VERSION 5.8 ;
BUSBITCHARS "[]" ;
DIVIDERCHAR "/" ;
UNITS
    DATABASE MICRONS 2000 ;
END UNITS

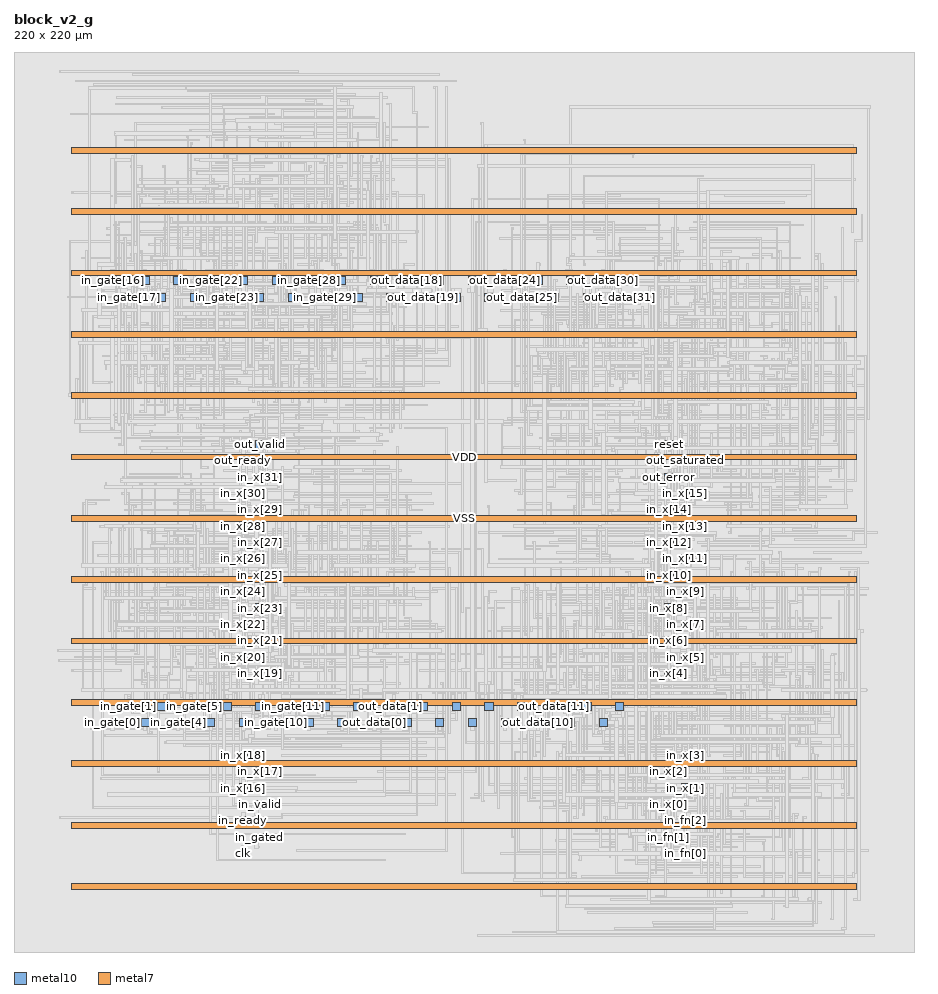
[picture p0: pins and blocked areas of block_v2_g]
MACRO block_v2_g
  FOREIGN block_v2_g 0 0 ;
  CLASS BLOCK ;
  SIZE 220 BY 220 ;
  PIN clk
    DIRECTION INPUT ;
    USE SIGNAL ;
    PORT
      LAYER metal10 ;
        RECT  55.095 23.07 57.095 25.07 ;
    END
  END clk
  PIN in_fn[0]
    DIRECTION INPUT ;
    USE SIGNAL ;
    PORT
      LAYER metal10 ;
        RECT  163.095 23.07 165.095 25.07 ;
    END
  END in_fn[0]
  PIN in_fn[1]
    DIRECTION INPUT ;
    USE SIGNAL ;
    PORT
      LAYER metal10 ;
        RECT  159.095 27.07 161.095 29.07 ;
    END
  END in_fn[1]
  PIN in_fn[2]
    DIRECTION INPUT ;
    USE SIGNAL ;
    PORT
      LAYER metal10 ;
        RECT  163.095 31.07 165.095 33.07 ;
    END
  END in_fn[2]
  PIN in_gate[0]
    DIRECTION INPUT ;
    USE SIGNAL ;
    PORT
      LAYER metal10 ;
        RECT  23.095 55.07 25.095 57.07 ;
    END
  END in_gate[0]
  PIN in_gate[10]
    DIRECTION INPUT ;
    USE SIGNAL ;
    PORT
      LAYER metal10 ;
        RECT  63.095 55.07 65.095 57.07 ;
    END
  END in_gate[10]
  PIN in_gate[11]
    DIRECTION INPUT ;
    USE SIGNAL ;
    PORT
      LAYER metal10 ;
        RECT  67.095 59.07 69.095 61.07 ;
    END
  END in_gate[11]
  PIN in_gate[12]
    DIRECTION INPUT ;
    USE SIGNAL ;
    PORT
      LAYER metal10 ;
        RECT  71.095 55.07 73.095 57.07 ;
    END
  END in_gate[12]
  PIN in_gate[13]
    DIRECTION INPUT ;
    USE SIGNAL ;
    PORT
      LAYER metal10 ;
        RECT  75.095 59.07 77.095 61.07 ;
    END
  END in_gate[13]
  PIN in_gate[14]
    DIRECTION INPUT ;
    USE SIGNAL ;
    PORT
      LAYER metal10 ;
        RECT  79.095 55.07 81.095 57.07 ;
    END
  END in_gate[14]
  PIN in_gate[15]
    DIRECTION INPUT ;
    USE SIGNAL ;
    PORT
      LAYER metal10 ;
        RECT  83.095 59.07 85.095 61.07 ;
    END
  END in_gate[15]
  PIN in_gate[16]
    DIRECTION INPUT ;
    USE SIGNAL ;
    PORT
      LAYER metal10 ;
        RECT  23.095 163.07 25.095 165.07 ;
    END
  END in_gate[16]
  PIN in_gate[17]
    DIRECTION INPUT ;
    USE SIGNAL ;
    PORT
      LAYER metal10 ;
        RECT  27.095 159.07 29.095 161.07 ;
    END
  END in_gate[17]
  PIN in_gate[18]
    DIRECTION INPUT ;
    USE SIGNAL ;
    PORT
      LAYER metal10 ;
        RECT  31.095 163.07 33.095 165.07 ;
    END
  END in_gate[18]
  PIN in_gate[19]
    DIRECTION INPUT ;
    USE SIGNAL ;
    PORT
      LAYER metal10 ;
        RECT  35.095 159.07 37.095 161.07 ;
    END
  END in_gate[19]
  PIN in_gate[1]
    DIRECTION INPUT ;
    USE SIGNAL ;
    PORT
      LAYER metal10 ;
        RECT  27.095 59.07 29.095 61.07 ;
    END
  END in_gate[1]
  PIN in_gate[20]
    DIRECTION INPUT ;
    USE SIGNAL ;
    PORT
      LAYER metal10 ;
        RECT  39.095 163.07 41.095 165.07 ;
    END
  END in_gate[20]
  PIN in_gate[21]
    DIRECTION INPUT ;
    USE SIGNAL ;
    PORT
      LAYER metal10 ;
        RECT  43.095 159.07 45.095 161.07 ;
    END
  END in_gate[21]
  PIN in_gate[22]
    DIRECTION INPUT ;
    USE SIGNAL ;
    PORT
      LAYER metal10 ;
        RECT  47.095 163.07 49.095 165.07 ;
    END
  END in_gate[22]
  PIN in_gate[23]
    DIRECTION INPUT ;
    USE SIGNAL ;
    PORT
      LAYER metal10 ;
        RECT  51.095 159.07 53.095 161.07 ;
    END
  END in_gate[23]
  PIN in_gate[24]
    DIRECTION INPUT ;
    USE SIGNAL ;
    PORT
      LAYER metal10 ;
        RECT  55.095 163.07 57.095 165.07 ;
    END
  END in_gate[24]
  PIN in_gate[25]
    DIRECTION INPUT ;
    USE SIGNAL ;
    PORT
      LAYER metal10 ;
        RECT  59.095 159.07 61.095 161.07 ;
    END
  END in_gate[25]
  PIN in_gate[26]
    DIRECTION INPUT ;
    USE SIGNAL ;
    PORT
      LAYER metal10 ;
        RECT  63.095 163.07 65.095 165.07 ;
    END
  END in_gate[26]
  PIN in_gate[27]
    DIRECTION INPUT ;
    USE SIGNAL ;
    PORT
      LAYER metal10 ;
        RECT  67.095 159.07 69.095 161.07 ;
    END
  END in_gate[27]
  PIN in_gate[28]
    DIRECTION INPUT ;
    USE SIGNAL ;
    PORT
      LAYER metal10 ;
        RECT  71.095 163.07 73.095 165.07 ;
    END
  END in_gate[28]
  PIN in_gate[29]
    DIRECTION INPUT ;
    USE SIGNAL ;
    PORT
      LAYER metal10 ;
        RECT  75.095 159.07 77.095 161.07 ;
    END
  END in_gate[29]
  PIN in_gate[2]
    DIRECTION INPUT ;
    USE SIGNAL ;
    PORT
      LAYER metal10 ;
        RECT  31.095 55.07 33.095 57.07 ;
    END
  END in_gate[2]
  PIN in_gate[30]
    DIRECTION INPUT ;
    USE SIGNAL ;
    PORT
      LAYER metal10 ;
        RECT  79.095 163.07 81.095 165.07 ;
    END
  END in_gate[30]
  PIN in_gate[31]
    DIRECTION INPUT ;
    USE SIGNAL ;
    PORT
      LAYER metal10 ;
        RECT  83.095 159.07 85.095 161.07 ;
    END
  END in_gate[31]
  PIN in_gate[3]
    DIRECTION INPUT ;
    USE SIGNAL ;
    PORT
      LAYER metal10 ;
        RECT  35.095 59.07 37.095 61.07 ;
    END
  END in_gate[3]
  PIN in_gate[4]
    DIRECTION INPUT ;
    USE SIGNAL ;
    PORT
      LAYER metal10 ;
        RECT  39.095 55.07 41.095 57.07 ;
    END
  END in_gate[4]
  PIN in_gate[5]
    DIRECTION INPUT ;
    USE SIGNAL ;
    PORT
      LAYER metal10 ;
        RECT  43.095 59.07 45.095 61.07 ;
    END
  END in_gate[5]
  PIN in_gate[6]
    DIRECTION INPUT ;
    USE SIGNAL ;
    PORT
      LAYER metal10 ;
        RECT  47.095 55.07 49.095 57.07 ;
    END
  END in_gate[6]
  PIN in_gate[7]
    DIRECTION INPUT ;
    USE SIGNAL ;
    PORT
      LAYER metal10 ;
        RECT  51.095 59.07 53.095 61.07 ;
    END
  END in_gate[7]
  PIN in_gate[8]
    DIRECTION INPUT ;
    USE SIGNAL ;
    PORT
      LAYER metal10 ;
        RECT  55.095 55.07 57.095 57.07 ;
    END
  END in_gate[8]
  PIN in_gate[9]
    DIRECTION INPUT ;
    USE SIGNAL ;
    PORT
      LAYER metal10 ;
        RECT  59.095 59.07 61.095 61.07 ;
    END
  END in_gate[9]
  PIN in_gated
    DIRECTION INPUT ;
    USE SIGNAL ;
    PORT
      LAYER metal10 ;
        RECT  59.095 27.07 61.095 29.07 ;
    END
  END in_gated
  PIN in_ready
    DIRECTION OUTPUT ;
    USE SIGNAL ;
    PORT
      LAYER metal10 ;
        RECT  55.095 31.07 57.095 33.07 ;
    END
  END in_ready
  PIN in_valid
    DIRECTION INPUT ;
    USE SIGNAL ;
    PORT
      LAYER metal10 ;
        RECT  59.095 35.07 61.095 37.07 ;
    END
  END in_valid
  PIN in_x[0]
    DIRECTION INPUT ;
    USE SIGNAL ;
    PORT
      LAYER metal10 ;
        RECT  159.095 35.07 161.095 37.07 ;
    END
  END in_x[0]
  PIN in_x[10]
    DIRECTION INPUT ;
    USE SIGNAL ;
    PORT
      LAYER metal10 ;
        RECT  159.095 91.07 161.095 93.07 ;
    END
  END in_x[10]
  PIN in_x[11]
    DIRECTION INPUT ;
    USE SIGNAL ;
    PORT
      LAYER metal10 ;
        RECT  163.095 95.07 165.095 97.07 ;
    END
  END in_x[11]
  PIN in_x[12]
    DIRECTION INPUT ;
    USE SIGNAL ;
    PORT
      LAYER metal10 ;
        RECT  159.095 99.07 161.095 101.07 ;
    END
  END in_x[12]
  PIN in_x[13]
    DIRECTION INPUT ;
    USE SIGNAL ;
    PORT
      LAYER metal10 ;
        RECT  163.095 103.07 165.095 105.07 ;
    END
  END in_x[13]
  PIN in_x[14]
    DIRECTION INPUT ;
    USE SIGNAL ;
    PORT
      LAYER metal10 ;
        RECT  159.095 107.07 161.095 109.07 ;
    END
  END in_x[14]
  PIN in_x[15]
    DIRECTION INPUT ;
    USE SIGNAL ;
    PORT
      LAYER metal10 ;
        RECT  163.095 111.07 165.095 113.07 ;
    END
  END in_x[15]
  PIN in_x[16]
    DIRECTION INPUT ;
    USE SIGNAL ;
    PORT
      LAYER metal10 ;
        RECT  55.095 39.07 57.095 41.07 ;
    END
  END in_x[16]
  PIN in_x[17]
    DIRECTION INPUT ;
    USE SIGNAL ;
    PORT
      LAYER metal10 ;
        RECT  59.095 43.07 61.095 45.07 ;
    END
  END in_x[17]
  PIN in_x[18]
    DIRECTION INPUT ;
    USE SIGNAL ;
    PORT
      LAYER metal10 ;
        RECT  55.095 47.07 57.095 49.07 ;
    END
  END in_x[18]
  PIN in_x[19]
    DIRECTION INPUT ;
    USE SIGNAL ;
    PORT
      LAYER metal10 ;
        RECT  59.095 67.07 61.095 69.07 ;
    END
  END in_x[19]
  PIN in_x[1]
    DIRECTION INPUT ;
    USE SIGNAL ;
    PORT
      LAYER metal10 ;
        RECT  163.095 39.07 165.095 41.07 ;
    END
  END in_x[1]
  PIN in_x[20]
    DIRECTION INPUT ;
    USE SIGNAL ;
    PORT
      LAYER metal10 ;
        RECT  55.095 71.07 57.095 73.07 ;
    END
  END in_x[20]
  PIN in_x[21]
    DIRECTION INPUT ;
    USE SIGNAL ;
    PORT
      LAYER metal10 ;
        RECT  59.095 75.07 61.095 77.07 ;
    END
  END in_x[21]
  PIN in_x[22]
    DIRECTION INPUT ;
    USE SIGNAL ;
    PORT
      LAYER metal10 ;
        RECT  55.095 79.07 57.095 81.07 ;
    END
  END in_x[22]
  PIN in_x[23]
    DIRECTION INPUT ;
    USE SIGNAL ;
    PORT
      LAYER metal10 ;
        RECT  59.095 83.07 61.095 85.07 ;
    END
  END in_x[23]
  PIN in_x[24]
    DIRECTION INPUT ;
    USE SIGNAL ;
    PORT
      LAYER metal10 ;
        RECT  55.095 87.07 57.095 89.07 ;
    END
  END in_x[24]
  PIN in_x[25]
    DIRECTION INPUT ;
    USE SIGNAL ;
    PORT
      LAYER metal10 ;
        RECT  59.095 91.07 61.095 93.07 ;
    END
  END in_x[25]
  PIN in_x[26]
    DIRECTION INPUT ;
    USE SIGNAL ;
    PORT
      LAYER metal10 ;
        RECT  55.095 95.07 57.095 97.07 ;
    END
  END in_x[26]
  PIN in_x[27]
    DIRECTION INPUT ;
    USE SIGNAL ;
    PORT
      LAYER metal10 ;
        RECT  59.095 99.07 61.095 101.07 ;
    END
  END in_x[27]
  PIN in_x[28]
    DIRECTION INPUT ;
    USE SIGNAL ;
    PORT
      LAYER metal10 ;
        RECT  55.095 103.07 57.095 105.07 ;
    END
  END in_x[28]
  PIN in_x[29]
    DIRECTION INPUT ;
    USE SIGNAL ;
    PORT
      LAYER metal10 ;
        RECT  59.095 107.07 61.095 109.07 ;
    END
  END in_x[29]
  PIN in_x[2]
    DIRECTION INPUT ;
    USE SIGNAL ;
    PORT
      LAYER metal10 ;
        RECT  159.095 43.07 161.095 45.07 ;
    END
  END in_x[2]
  PIN in_x[30]
    DIRECTION INPUT ;
    USE SIGNAL ;
    PORT
      LAYER metal10 ;
        RECT  55.095 111.07 57.095 113.07 ;
    END
  END in_x[30]
  PIN in_x[31]
    DIRECTION INPUT ;
    USE SIGNAL ;
    PORT
      LAYER metal10 ;
        RECT  59.095 115.07 61.095 117.07 ;
    END
  END in_x[31]
  PIN in_x[3]
    DIRECTION INPUT ;
    USE SIGNAL ;
    PORT
      LAYER metal10 ;
        RECT  163.095 47.07 165.095 49.07 ;
    END
  END in_x[3]
  PIN in_x[4]
    DIRECTION INPUT ;
    USE SIGNAL ;
    PORT
      LAYER metal10 ;
        RECT  159.095 67.07 161.095 69.07 ;
    END
  END in_x[4]
  PIN in_x[5]
    DIRECTION INPUT ;
    USE SIGNAL ;
    PORT
      LAYER metal10 ;
        RECT  163.095 71.07 165.095 73.07 ;
    END
  END in_x[5]
  PIN in_x[6]
    DIRECTION INPUT ;
    USE SIGNAL ;
    PORT
      LAYER metal10 ;
        RECT  159.095 75.07 161.095 77.07 ;
    END
  END in_x[6]
  PIN in_x[7]
    DIRECTION INPUT ;
    USE SIGNAL ;
    PORT
      LAYER metal10 ;
        RECT  163.095 79.07 165.095 81.07 ;
    END
  END in_x[7]
  PIN in_x[8]
    DIRECTION INPUT ;
    USE SIGNAL ;
    PORT
      LAYER metal10 ;
        RECT  159.095 83.07 161.095 85.07 ;
    END
  END in_x[8]
  PIN in_x[9]
    DIRECTION INPUT ;
    USE SIGNAL ;
    PORT
      LAYER metal10 ;
        RECT  163.095 87.07 165.095 89.07 ;
    END
  END in_x[9]
  PIN out_data[0]
    DIRECTION OUTPUT ;
    USE SIGNAL ;
    PORT
      LAYER metal10 ;
        RECT  87.095 55.07 89.095 57.07 ;
    END
  END out_data[0]
  PIN out_data[10]
    DIRECTION OUTPUT ;
    USE SIGNAL ;
    PORT
      LAYER metal10 ;
        RECT  127.095 55.07 129.095 57.07 ;
    END
  END out_data[10]
  PIN out_data[11]
    DIRECTION OUTPUT ;
    USE SIGNAL ;
    PORT
      LAYER metal10 ;
        RECT  131.095 59.07 133.095 61.07 ;
    END
  END out_data[11]
  PIN out_data[12]
    DIRECTION OUTPUT ;
    USE SIGNAL ;
    PORT
      LAYER metal10 ;
        RECT  135.095 55.07 137.095 57.07 ;
    END
  END out_data[12]
  PIN out_data[13]
    DIRECTION OUTPUT ;
    USE SIGNAL ;
    PORT
      LAYER metal10 ;
        RECT  139.095 59.07 141.095 61.07 ;
    END
  END out_data[13]
  PIN out_data[14]
    DIRECTION OUTPUT ;
    USE SIGNAL ;
    PORT
      LAYER metal10 ;
        RECT  143.095 55.07 145.095 57.07 ;
    END
  END out_data[14]
  PIN out_data[15]
    DIRECTION OUTPUT ;
    USE SIGNAL ;
    PORT
      LAYER metal10 ;
        RECT  147.095 59.07 149.095 61.07 ;
    END
  END out_data[15]
  PIN out_data[16]
    DIRECTION OUTPUT ;
    USE SIGNAL ;
    PORT
      LAYER metal10 ;
        RECT  87.095 163.07 89.095 165.07 ;
    END
  END out_data[16]
  PIN out_data[17]
    DIRECTION OUTPUT ;
    USE SIGNAL ;
    PORT
      LAYER metal10 ;
        RECT  91.095 159.07 93.095 161.07 ;
    END
  END out_data[17]
  PIN out_data[18]
    DIRECTION OUTPUT ;
    USE SIGNAL ;
    PORT
      LAYER metal10 ;
        RECT  95.095 163.07 97.095 165.07 ;
    END
  END out_data[18]
  PIN out_data[19]
    DIRECTION OUTPUT ;
    USE SIGNAL ;
    PORT
      LAYER metal10 ;
        RECT  99.095 159.07 101.095 161.07 ;
    END
  END out_data[19]
  PIN out_data[1]
    DIRECTION OUTPUT ;
    USE SIGNAL ;
    PORT
      LAYER metal10 ;
        RECT  91.095 59.07 93.095 61.07 ;
    END
  END out_data[1]
  PIN out_data[20]
    DIRECTION OUTPUT ;
    USE SIGNAL ;
    PORT
      LAYER metal10 ;
        RECT  103.095 163.07 105.095 165.07 ;
    END
  END out_data[20]
  PIN out_data[21]
    DIRECTION OUTPUT ;
    USE SIGNAL ;
    PORT
      LAYER metal10 ;
        RECT  107.095 159.07 109.095 161.07 ;
    END
  END out_data[21]
  PIN out_data[22]
    DIRECTION OUTPUT ;
    USE SIGNAL ;
    PORT
      LAYER metal10 ;
        RECT  111.095 163.07 113.095 165.07 ;
    END
  END out_data[22]
  PIN out_data[23]
    DIRECTION OUTPUT ;
    USE SIGNAL ;
    PORT
      LAYER metal10 ;
        RECT  115.095 159.07 117.095 161.07 ;
    END
  END out_data[23]
  PIN out_data[24]
    DIRECTION OUTPUT ;
    USE SIGNAL ;
    PORT
      LAYER metal10 ;
        RECT  119.095 163.07 121.095 165.07 ;
    END
  END out_data[24]
  PIN out_data[25]
    DIRECTION OUTPUT ;
    USE SIGNAL ;
    PORT
      LAYER metal10 ;
        RECT  123.095 159.07 125.095 161.07 ;
    END
  END out_data[25]
  PIN out_data[26]
    DIRECTION OUTPUT ;
    USE SIGNAL ;
    PORT
      LAYER metal10 ;
        RECT  127.095 163.07 129.095 165.07 ;
    END
  END out_data[26]
  PIN out_data[27]
    DIRECTION OUTPUT ;
    USE SIGNAL ;
    PORT
      LAYER metal10 ;
        RECT  131.095 159.07 133.095 161.07 ;
    END
  END out_data[27]
  PIN out_data[28]
    DIRECTION OUTPUT ;
    USE SIGNAL ;
    PORT
      LAYER metal10 ;
        RECT  135.095 163.07 137.095 165.07 ;
    END
  END out_data[28]
  PIN out_data[29]
    DIRECTION OUTPUT ;
    USE SIGNAL ;
    PORT
      LAYER metal10 ;
        RECT  139.095 159.07 141.095 161.07 ;
    END
  END out_data[29]
  PIN out_data[2]
    DIRECTION OUTPUT ;
    USE SIGNAL ;
    PORT
      LAYER metal10 ;
        RECT  95.095 55.07 97.095 57.07 ;
    END
  END out_data[2]
  PIN out_data[30]
    DIRECTION OUTPUT ;
    USE SIGNAL ;
    PORT
      LAYER metal10 ;
        RECT  143.095 163.07 145.095 165.07 ;
    END
  END out_data[30]
  PIN out_data[31]
    DIRECTION OUTPUT ;
    USE SIGNAL ;
    PORT
      LAYER metal10 ;
        RECT  147.095 159.07 149.095 161.07 ;
    END
  END out_data[31]
  PIN out_data[3]
    DIRECTION OUTPUT ;
    USE SIGNAL ;
    PORT
      LAYER metal10 ;
        RECT  99.095 59.07 101.095 61.07 ;
    END
  END out_data[3]
  PIN out_data[4]
    DIRECTION OUTPUT ;
    USE SIGNAL ;
    PORT
      LAYER metal10 ;
        RECT  103.095 55.07 105.095 57.07 ;
    END
  END out_data[4]
  PIN out_data[5]
    DIRECTION OUTPUT ;
    USE SIGNAL ;
    PORT
      LAYER metal10 ;
        RECT  107.095 59.07 109.095 61.07 ;
    END
  END out_data[5]
  PIN out_data[6]
    DIRECTION OUTPUT ;
    USE SIGNAL ;
    PORT
      LAYER metal10 ;
        RECT  111.095 55.07 113.095 57.07 ;
    END
  END out_data[6]
  PIN out_data[7]
    DIRECTION OUTPUT ;
    USE SIGNAL ;
    PORT
      LAYER metal10 ;
        RECT  115.095 59.07 117.095 61.07 ;
    END
  END out_data[7]
  PIN out_data[8]
    DIRECTION OUTPUT ;
    USE SIGNAL ;
    PORT
      LAYER metal10 ;
        RECT  119.095 55.07 121.095 57.07 ;
    END
  END out_data[8]
  PIN out_data[9]
    DIRECTION OUTPUT ;
    USE SIGNAL ;
    PORT
      LAYER metal10 ;
        RECT  123.095 59.07 125.095 61.07 ;
    END
  END out_data[9]
  PIN out_error
    DIRECTION OUTPUT ;
    USE SIGNAL ;
    PORT
      LAYER metal10 ;
        RECT  159.095 115.07 161.095 117.07 ;
    END
  END out_error
  PIN out_ready
    DIRECTION INPUT ;
    USE SIGNAL ;
    PORT
      LAYER metal10 ;
        RECT  55.095 119.07 57.095 121.07 ;
    END
  END out_ready
  PIN out_saturated
    DIRECTION OUTPUT ;
    USE SIGNAL ;
    PORT
      LAYER metal10 ;
        RECT  163.095 119.07 165.095 121.07 ;
    END
  END out_saturated
  PIN out_valid
    DIRECTION OUTPUT ;
    USE SIGNAL ;
    PORT
      LAYER metal10 ;
        RECT  59.095 123.07 61.095 125.07 ;
    END
  END out_valid
  PIN reset
    DIRECTION INPUT ;
    USE SIGNAL ;
    PORT
      LAYER metal10 ;
        RECT  159.095 123.07 161.095 125.07 ;
    END
  END reset
  PIN VSS
    DIRECTION INOUT ;
    USE GROUND ;
    PORT
      LAYER metal7 ;
        RECT  14.06 195.3 205.96 196.7 ;
        RECT  14.06 165.3 205.96 166.7 ;
        RECT  14.06 135.3 205.96 136.7 ;
        RECT  14.06 105.3 205.96 106.7 ;
        RECT  14.06 75.3 205.96 76.7 ;
        RECT  14.06 45.3 205.96 46.7 ;
        RECT  14.06 15.3 205.96 16.7 ;
    END
  END VSS
  PIN VDD
    DIRECTION INOUT ;
    USE POWER ;
    PORT
      LAYER metal7 ;
        RECT  14.06 180.3 205.96 181.7 ;
        RECT  14.06 150.3 205.96 151.7 ;
        RECT  14.06 120.3 205.96 121.7 ;
        RECT  14.06 90.3 205.96 91.7 ;
        RECT  14.06 60.3 205.96 61.7 ;
        RECT  14.06 30.3 205.96 31.7 ;
    END
  END VDD
  OBS
    LAYER metal1 ;
     RECT 0 0 220 220 ;
    LAYER metal2 ;
     RECT 0 0 220 220 ;
    LAYER metal3 ;
     RECT 0 0 220 220 ;
    LAYER metal4 ;
     RECT 0 0 220 220 ;
    LAYER metal5 ;
     RECT 0 0 220 220 ;
    LAYER metal6 ;
     RECT 0 0 220 220 ;
    LAYER metal7 ;
     RECT  15.095 139.87 15.695 140.27 ;
     RECT  16.695 134.27 17.095 134.67 ;
     RECT  17.495 171.07 17.935 171.47 ;
     RECT  18.095 163.87 18.695 164.27 ;
     RECT  16.695 88.67 19.895 89.07 ;
     RECT  16.695 109.47 20.175 109.87 ;
     RECT  21.175 92.67 21.895 93.07 ;
     RECT  22.295 93.47 22.695 93.87 ;
     RECT  20.895 103.87 22.695 104.27 ;
     RECT  22.295 114.27 22.695 114.67 ;
     RECT  22.295 142.27 22.695 142.67 ;
     RECT  17.495 110.27 23.255 110.67 ;
     RECT  19.095 139.07 23.255 139.47 ;
     RECT  22.855 38.27 23.495 38.67 ;
     RECT  19.095 99.87 23.815 100.27 ;
     RECT  23.095 103.07 24.095 103.47 ;
     RECT  23.695 127.87 24.295 128.27 ;
     RECT  23.695 139.07 24.295 139.47 ;
     RECT  23.895 74.27 24.375 74.67 ;
     RECT  23.895 163.87 24.375 164.27 ;
     RECT  23.895 56.67 24.655 57.07 ;
     RECT  24.535 178.27 25.095 178.67 ;
     RECT  24.535 183.07 25.095 183.47 ;
     RECT  24.255 177.47 25.495 177.87 ;
     RECT  23.095 78.27 25.775 78.67 ;
     RECT  21.735 145.47 25.895 145.87 ;
     RECT  22.575 176.67 25.895 177.07 ;
     RECT  25.495 177.47 25.895 178.67 ;
     RECT  25.495 128.67 26.055 129.07 ;
     RECT  24.815 79.07 26.295 79.47 ;
     RECT  14.175 68.67 26.335 69.07 ;
     RECT  15.895 127.07 26.335 127.47 ;
     RECT  26.295 78.27 26.695 79.47 ;
     RECT  23.895 85.47 26.695 85.87 ;
     RECT  26.215 115.07 26.695 115.47 ;
     RECT  25.655 123.87 26.695 124.27 ;
     RECT  26.295 103.87 26.895 104.27 ;
     RECT  25.495 103.07 27.175 103.47 ;
     RECT  26.295 153.47 27.175 153.87 ;
     RECT  24.815 159.07 27.495 159.47 ;
     RECT  26.775 174.27 27.495 174.67 ;
     RECT  27.095 160.67 27.735 161.07 ;
     RECT  27.895 62.27 28.295 62.67 ;
     RECT  26.215 111.87 28.295 112.27 ;
     RECT  27.895 128.67 28.295 129.07 ;
     RECT  27.895 153.47 28.295 153.87 ;
     RECT  27.895 79.07 28.575 79.47 ;
     RECT  26.295 172.67 28.575 173.07 ;
     RECT  13.495 173.47 28.735 173.87 ;
     RECT  10.535 73.47 28.855 73.87 ;
     RECT  24.695 93.47 28.855 93.87 ;
     RECT  23.135 129.47 28.855 129.87 ;
     RECT  27.895 193.47 28.855 193.87 ;
     RECT  28.695 58.27 29.095 59.47 ;
     RECT  23.415 92.67 29.095 93.07 ;
     RECT  29.095 59.07 29.135 59.47 ;
     RECT  28.695 162.27 29.135 162.67 ;
     RECT  28.735 173.47 29.135 174.67 ;
     RECT  28.695 194.27 29.135 194.67 ;
     RECT  19.095 155.07 29.695 155.47 ;
     RECT  29.135 174.27 29.695 174.67 ;
     RECT  29.295 73.47 29.895 73.87 ;
     RECT  28.455 170.27 29.895 170.67 ;
     RECT  29.295 172.67 29.895 173.07 ;
     RECT  28.695 108.67 29.975 109.07 ;
     RECT  16.415 169.47 30.295 169.87 ;
     RECT  29.575 72.67 30.695 73.07 ;
     RECT  30.135 94.27 30.695 94.67 ;
     RECT  29.295 141.47 30.695 141.87 ;
     RECT  30.295 169.47 30.695 170.67 ;
     RECT  29.575 173.47 30.695 173.87 ;
     RECT  30.135 187.07 30.695 187.47 ;
     RECT  30.295 139.07 31.095 139.47 ;
     RECT  30.695 114.27 31.495 114.67 ;
     RECT  30.695 123.07 31.495 123.47 ;
     RECT  30.695 160.67 31.495 161.07 ;
     RECT  30.975 171.07 31.495 171.47 ;
     RECT  30.975 183.87 31.495 184.27 ;
     RECT  28.455 191.87 31.495 192.27 ;
     RECT  21.735 161.47 31.655 161.87 ;
     RECT  31.095 163.87 31.655 164.27 ;
     RECT  31.095 68.67 31.935 69.07 ;
     RECT  26.295 143.07 32.215 143.47 ;
     RECT  30.695 131.87 32.295 132.27 ;
     RECT  31.535 145.47 32.295 145.87 ;
     RECT  23.695 184.67 32.495 185.07 ;
     RECT  28.175 142.27 32.695 142.67 ;
     RECT  29.575 162.27 32.695 162.67 ;
     RECT  24.695 70.27 32.775 70.67 ;
     RECT  29.495 153.47 32.775 153.87 ;
     RECT  31.895 55.87 33.055 56.27 ;
     RECT  32.095 67.87 33.095 68.27 ;
     RECT  32.375 84.67 33.095 85.07 ;
     RECT  32.655 134.27 33.095 134.67 ;
     RECT  32.695 142.27 33.095 144.27 ;
     RECT  32.695 161.47 33.095 162.67 ;
     RECT  31.895 163.07 33.335 163.47 ;
     RECT  27.095 109.47 33.615 109.87 ;
     RECT  32.695 53.47 33.895 53.87 ;
     RECT  30.975 103.07 33.895 103.47 ;
     RECT  33.495 122.27 33.895 122.67 ;
     RECT  33.215 127.07 33.895 127.47 ;
     RECT  33.495 145.47 33.895 145.87 ;
     RECT  33.495 169.47 33.895 169.87 ;
     RECT  14.735 71.87 34.175 72.27 ;
     RECT  29.575 128.67 34.695 129.07 ;
     RECT  34.295 59.07 34.735 59.47 ;
     RECT  34.295 114.27 34.735 114.67 ;
     RECT  33.495 143.07 35.015 143.47 ;
     RECT  28.695 126.27 35.295 126.67 ;
     RECT  35.095 43.87 35.575 44.27 ;
     RECT  35.095 138.27 35.575 138.67 ;
     RECT  35.095 163.07 35.575 163.47 ;
     RECT  35.095 182.27 35.575 182.67 ;
     RECT  28.175 168.67 36.135 169.07 ;
     RECT  30.415 83.07 36.295 83.47 ;
     RECT  35.735 134.27 36.295 134.67 ;
     RECT  35.735 173.47 36.295 173.87 ;
     RECT  34.295 174.27 36.695 174.67 ;
     RECT  35.095 99.07 36.975 99.47 ;
     RECT  35.895 141.47 36.975 141.87 ;
     RECT  36.575 62.27 37.095 62.67 ;
     RECT  24.255 131.07 37.095 131.47 ;
     RECT  36.015 160.67 37.095 161.07 ;
     RECT  36.295 169.47 37.095 169.87 ;
     RECT  36.295 191.87 37.095 192.27 ;
     RECT  22.575 175.07 37.135 175.47 ;
     RECT  29.015 85.47 37.415 85.87 ;
     RECT  30.695 170.27 37.495 170.67 ;
     RECT  25.375 167.87 37.535 168.27 ;
     RECT  37.135 174.27 37.535 175.47 ;
     RECT  14.175 185.47 37.535 185.87 ;
     RECT  37.415 84.67 37.815 85.87 ;
     RECT  36.855 51.07 37.895 51.47 ;
     RECT  31.815 67.07 37.895 67.47 ;
     RECT  32.655 102.27 37.895 102.67 ;
     RECT  33.495 162.27 37.895 162.67 ;
     RECT  37.495 169.47 37.895 170.67 ;
     RECT  37.495 131.87 38.095 132.27 ;
     RECT  36.575 168.67 38.295 169.07 ;
     RECT  31.815 186.27 38.295 186.67 ;
     RECT  37.695 67.87 38.695 68.27 ;
     RECT  38.255 132.67 38.695 133.07 ;
     RECT  38.295 167.87 38.695 169.07 ;
     RECT  38.255 179.07 38.695 179.47 ;
     RECT  38.295 185.47 38.695 186.67 ;
     RECT  30.415 79.07 39.095 79.47 ;
     RECT  37.495 183.07 39.215 183.47 ;
     RECT  39.095 79.07 39.495 80.27 ;
     RECT  39.095 102.27 39.495 102.67 ;
     RECT  38.815 163.07 39.495 163.47 ;
     RECT  39.095 71.87 39.775 72.27 ;
     RECT  39.095 100.67 39.775 101.07 ;
     RECT  39.095 141.47 39.775 141.87 ;
     RECT  10.815 71.07 39.895 71.47 ;
     RECT  32.375 163.87 39.895 164.27 ;
     RECT  26.495 115.87 40.055 116.27 ;
     RECT  39.895 70.27 40.295 71.47 ;
     RECT  39.895 162.27 40.295 164.27 ;
     RECT  39.655 187.87 40.295 188.27 ;
     RECT  39.895 55.87 40.335 56.27 ;
     RECT  40.295 70.27 40.335 70.67 ;
     RECT  39.895 79.07 40.335 79.47 ;
     RECT  39.895 112.67 40.335 113.07 ;
     RECT  39.895 126.27 40.335 126.67 ;
     RECT  21.735 63.87 40.615 64.27 ;
     RECT  32.375 93.47 40.615 93.87 ;
     RECT  29.095 58.27 40.895 58.67 ;
     RECT  38.815 87.07 41.095 87.47 ;
     RECT  36.575 176.67 41.095 177.07 ;
     RECT  40.695 62.27 41.175 62.67 ;
     RECT  40.695 131.07 41.175 131.47 ;
     RECT  37.135 147.07 41.175 147.47 ;
     RECT  40.695 115.87 41.455 116.27 ;
     RECT  39.495 79.87 41.495 80.27 ;
     RECT  30.975 115.07 41.615 115.47 ;
     RECT  40.695 144.67 41.735 145.07 ;
     RECT  41.495 79.07 41.895 80.27 ;
     RECT  40.775 84.67 41.895 85.07 ;
     RECT  39.655 132.67 41.895 133.07 ;
     RECT  40.775 163.87 41.895 164.27 ;
     RECT  41.495 74.27 42.015 74.67 ;
     RECT  41.615 114.27 42.015 115.47 ;
     RECT  42.175 93.47 42.695 93.87 ;
     RECT  41.335 100.67 42.695 101.07 ;
     RECT  41.895 175.07 42.695 175.47 ;
     RECT  42.175 199.07 42.695 199.47 ;
     RECT  28.455 82.27 43.135 82.67 ;
     RECT  25.935 140.67 43.135 141.07 ;
     RECT  43.015 62.27 43.495 62.67 ;
     RECT  43.015 94.27 43.495 94.67 ;
     RECT  28.175 116.67 43.495 117.07 ;
     RECT  13.055 159.87 43.495 160.27 ;
     RECT  42.015 114.27 43.695 114.67 ;
     RECT  43.095 197.47 43.695 197.87 ;
     RECT  37.415 83.07 43.895 83.47 ;
     RECT  33.775 99.87 43.895 100.27 ;
     RECT  33.775 69.47 43.975 69.87 ;
     RECT  20.335 96.67 43.975 97.07 ;
     RECT  43.015 68.67 44.295 69.07 ;
     RECT  43.895 82.27 44.295 83.47 ;
     RECT  43.895 99.07 44.295 100.27 ;
     RECT  43.295 112.67 44.295 113.07 ;
     RECT  41.335 139.87 44.295 140.27 ;
     RECT  43.095 103.87 44.535 104.27 ;
     RECT  17.495 130.27 44.695 130.67 ;
     RECT  44.695 59.07 45.095 59.47 ;
     RECT  44.135 100.67 45.095 101.07 ;
     RECT  36.855 103.07 45.095 103.47 ;
     RECT  44.695 127.87 45.095 130.67 ;
     RECT  44.135 159.87 45.095 160.27 ;
     RECT  44.695 190.27 45.095 190.67 ;
     RECT  27.055 198.27 45.375 198.67 ;
     RECT  29.575 66.27 45.4 66.67 ;
     RECT  39.095 95.07 45.4 95.47 ;
     RECT  39.655 171.87 45.4 172.27 ;
     RECT  32.935 172.67 45.4 173.07 ;
     RECT  40.775 160.67 45.495 161.07 ;
     RECT  43.895 93.47 45.655 93.87 ;
     RECT  45.4 65.47 45.8 66.67 ;
     RECT  45.4 94.27 45.8 95.47 ;
     RECT  45.4 171.07 45.8 172.27 ;
     RECT  45.4 172.67 45.8 173.87 ;
     RECT  41.895 141.47 45.895 141.87 ;
     RECT  45.495 159.87 45.895 161.07 ;
     RECT  44.135 193.47 45.895 193.87 ;
     RECT  38.815 73.47 45.935 73.87 ;
     RECT  41.495 102.27 45.935 102.67 ;
     RECT  30.975 133.47 45.935 133.87 ;
     RECT  45.495 139.87 46.215 140.27 ;
     RECT  28.455 110.27 46.495 110.67 ;
     RECT  24.535 125.47 46.495 125.87 ;
     RECT  21.455 55.07 46.695 55.47 ;
     RECT  44.415 108.67 46.695 109.07 ;
     RECT  45.255 183.07 46.695 183.47 ;
     RECT  46.295 66.27 47.055 66.67 ;
     RECT  31.535 187.07 47.055 187.47 ;
     RECT  44.295 99.07 47.095 99.47 ;
     RECT  47.095 99.07 47.495 100.27 ;
     RECT  46.655 103.07 47.495 103.47 ;
     RECT  46.095 147.07 47.495 147.47 ;
     RECT  46.935 148.67 47.495 149.07 ;
     RECT  47.095 89.47 47.615 89.87 ;
     RECT  45.495 118.27 47.615 118.67 ;
     RECT  47.095 55.87 47.895 56.27 ;
     RECT  47.095 133.47 47.895 133.87 ;
     RECT  47.095 168.67 47.895 169.07 ;
     RECT  40.295 162.27 48.175 162.67 ;
     RECT  47.895 148.67 48.295 149.87 ;
     RECT  47.775 163.07 48.295 163.47 ;
     RECT  47.895 99.07 48.455 99.47 ;
     RECT  28.735 113.47 48.455 113.87 ;
     RECT  37.535 174.27 48.455 174.67 ;
     RECT  21.735 87.87 48.735 88.27 ;
     RECT  45.495 116.67 48.735 117.07 ;
     RECT  38.695 185.47 48.735 185.87 ;
     RECT  28.735 83.87 49.015 84.27 ;
     RECT  47.775 73.47 49.095 73.87 ;
     RECT  30.695 188.67 49.095 189.07 ;
     RECT  48.695 77.47 49.295 77.87 ;
     RECT  37.895 169.47 49.295 169.87 ;
     RECT  34.055 88.67 49.495 89.07 ;
     RECT  48.695 130.27 49.575 130.67 ;
     RECT  38.535 153.47 49.575 153.87 ;
     RECT  49.455 74.27 49.895 74.67 ;
     RECT  49.495 87.87 49.895 89.07 ;
     RECT  49.175 149.47 49.895 149.87 ;
     RECT  48.895 162.27 49.895 162.67 ;
     RECT  44.295 82.27 50.135 82.67 ;
     RECT  41.895 155.07 50.135 155.47 ;
     RECT  33.095 161.47 50.295 161.87 ;
     RECT  49.495 187.07 50.415 187.47 ;
     RECT  37.695 63.07 50.695 63.47 ;
     RECT  50.295 88.67 50.695 89.07 ;
     RECT  45.535 131.07 50.695 131.47 ;
     RECT  50.295 161.47 50.695 162.67 ;
     RECT  48.895 176.67 50.695 177.07 ;
     RECT  33.775 92.67 50.855 93.07 ;
     RECT  27.055 107.87 50.975 108.27 ;
     RECT  46.095 186.27 51.095 186.67 ;
     RECT  50.855 92.67 51.255 93.87 ;
     RECT  46.295 95.07 51.255 95.47 ;
     RECT  31.255 124.67 51.255 125.07 ;
     RECT  33.095 143.87 51.255 144.27 ;
     RECT  50.295 144.67 51.255 145.07 ;
     RECT  32.935 184.67 51.255 185.07 ;
     RECT  50.575 73.47 51.495 73.87 ;
     RECT  50.855 122.27 51.495 122.67 ;
     RECT  50.855 149.47 51.495 149.87 ;
     RECT  51.095 186.27 51.495 187.47 ;
     RECT  50.855 193.47 51.495 193.87 ;
     RECT  51.095 161.47 51.535 161.87 ;
     RECT  45.895 159.87 51.695 160.27 ;
     RECT  29.495 202.27 51.815 202.67 ;
     RECT  43.095 84.67 52.095 85.07 ;
     RECT  21.455 157.47 52.095 157.87 ;
     RECT  51.695 159.07 52.095 160.27 ;
     RECT  51.695 144.67 52.295 145.07 ;
     RECT  39.935 177.47 52.295 177.87 ;
     RECT  49.175 198.27 52.295 198.67 ;
     RECT  51.895 62.27 52.375 62.67 ;
     RECT  51.895 194.27 52.375 194.67 ;
     RECT  51.895 186.27 52.655 186.67 ;
     RECT  50.295 125.47 52.695 125.87 ;
     RECT  26.695 78.27 52.935 78.67 ;
     RECT  48.335 63.87 53.095 64.27 ;
     RECT  52.695 124.67 53.095 125.87 ;
     RECT  51.975 143.87 53.095 144.27 ;
     RECT  42.735 67.07 53.215 67.47 ;
     RECT  48.695 69.47 53.215 69.87 ;
     RECT  33.495 86.27 53.215 86.67 ;
     RECT  52.695 89.47 53.215 89.87 ;
     RECT  44.415 70.27 53.495 70.67 ;
     RECT  39.935 72.67 53.495 73.07 ;
     RECT  49.895 87.87 53.495 88.27 ;
     RECT  27.895 98.27 53.495 98.67 ;
     RECT  31.815 139.07 53.775 139.47 ;
     RECT  25.935 156.67 53.775 157.07 ;
     RECT  53.495 72.67 53.895 73.87 ;
     RECT  53.495 87.87 53.895 89.07 ;
     RECT  51.975 155.87 53.895 156.27 ;
     RECT  42.455 191.07 53.895 191.47 ;
     RECT  48.695 139.87 54.295 140.27 ;
     RECT  53.495 63.07 54.335 63.47 ;
     RECT  23.415 80.67 54.335 81.07 ;
     RECT  53.495 78.27 54.615 78.67 ;
     RECT  48.895 167.87 54.615 168.27 ;
     RECT  54.295 139.07 54.695 140.27 ;
     RECT  53.375 193.47 54.695 193.87 ;
     RECT  54.295 183.07 54.895 183.47 ;
     RECT  53.495 71.07 55.175 71.47 ;
     RECT  37.135 123.07 55.175 123.47 ;
     RECT  22.015 52.67 55.455 53.07 ;
     RECT  54.295 87.87 55.455 88.27 ;
     RECT  51.255 93.47 55.455 93.87 ;
     RECT  54.695 139.07 55.455 139.47 ;
     RECT  55.055 68.67 55.495 69.07 ;
     RECT  55.055 95.07 55.495 95.47 ;
     RECT  55.055 127.07 55.495 127.47 ;
     RECT  51.895 99.07 55.735 99.47 ;
     RECT  41.615 53.47 55.895 53.87 ;
     RECT  55.895 25.47 56.295 25.87 ;
     RECT  55.095 39.87 56.295 40.27 ;
     RECT  55.895 41.47 56.295 41.87 ;
     RECT  55.895 51.87 56.295 53.87 ;
     RECT  55.895 55.07 56.295 55.47 ;
     RECT  55.615 80.67 56.295 81.07 ;
     RECT  55.615 86.27 56.295 86.67 ;
     RECT  55.895 89.47 56.295 89.87 ;
     RECT  55.335 110.27 56.295 110.67 ;
     RECT  55.895 122.27 56.295 122.67 ;
     RECT  55.095 163.07 56.295 163.47 ;
     RECT  55.895 188.67 56.295 189.07 ;
     RECT  55.895 33.47 56.575 33.87 ;
     RECT  37.135 56.67 56.575 57.07 ;
     RECT  48.055 96.67 56.575 97.07 ;
     RECT  44.415 97.47 56.575 97.87 ;
     RECT  55.895 155.07 56.575 155.47 ;
     RECT  53.935 55.87 56.695 56.27 ;
     RECT  43.015 85.47 56.695 85.87 ;
     RECT  56.695 55.07 57.095 56.27 ;
     RECT  56.695 85.47 57.095 87.47 ;
     RECT  56.455 123.07 57.095 123.47 ;
     RECT  56.175 141.47 57.095 141.87 ;
     RECT  56.695 103.07 57.135 103.47 ;
     RECT  46.375 128.67 57.135 129.07 ;
     RECT  39.655 131.87 57.415 132.27 ;
     RECT  20.615 152.67 57.415 153.07 ;
     RECT  24.535 199.87 57.415 200.27 ;
     RECT  45.8 65.47 57.695 65.87 ;
     RECT  39.095 109.47 57.695 109.87 ;
     RECT  53.095 124.67 57.695 125.07 ;
     RECT  34.295 142.27 57.695 142.67 ;
     RECT  57.295 70.27 57.895 70.67 ;
     RECT  57.295 107.87 57.895 108.27 ;
     RECT  57.295 137.47 57.895 137.87 ;
     RECT  57.015 155.07 57.895 155.47 ;
     RECT  44.975 158.27 57.895 158.67 ;
     RECT  33.775 183.87 57.895 184.27 ;
     RECT  57.295 201.47 57.895 201.87 ;
     RECT  19.095 35.07 57.975 35.47 ;
     RECT  41.895 79.07 57.975 79.47 ;
     RECT  57.495 100.67 57.975 101.07 ;
     RECT  39.935 111.87 57.975 112.27 ;
     RECT  57.495 47.87 58.255 48.27 ;
     RECT  55.095 108.67 58.255 109.07 ;
     RECT  57.495 131.07 58.255 131.47 ;
     RECT  57.495 143.87 58.535 144.27 ;
     RECT  57.855 55.87 58.695 56.27 ;
     RECT  57.855 127.07 58.695 127.47 ;
     RECT  46.095 175.07 58.695 175.47 ;
     RECT  57.495 92.67 58.815 93.07 ;
     RECT  58.295 134.27 58.815 134.67 ;
     RECT  58.295 97.47 59.095 97.87 ;
     RECT  58.295 113.47 59.095 113.87 ;
     RECT  58.695 35.07 59.495 35.47 ;
     RECT  58.975 59.07 59.495 59.47 ;
     RECT  58.975 74.27 59.495 74.67 ;
     RECT  55.335 98.27 59.495 98.67 ;
     RECT  58.135 123.07 59.495 123.47 ;
     RECT  45.8 173.47 59.495 173.87 ;
     RECT  59.095 131.07 59.655 131.47 ;
     RECT  59.095 193.47 59.655 193.87 ;
     RECT  59.095 25.47 59.935 25.87 ;
     RECT  59.095 43.87 59.935 44.27 ;
     RECT  57.495 84.67 59.935 85.07 ;
     RECT  53.895 88.67 59.935 89.07 ;
     RECT  59.095 124.67 59.935 125.07 ;
     RECT  55.895 129.47 59.935 129.87 ;
     RECT  59.535 133.47 59.935 134.67 ;
     RECT  42.735 145.47 59.935 145.87 ;
     RECT  59.095 57.47 60.215 57.87 ;
     RECT  50.295 58.27 60.215 58.67 ;
     RECT  43.015 115.07 60.215 115.47 ;
     RECT  59.095 118.27 60.215 118.67 ;
     RECT  39.935 154.27 60.215 154.67 ;
     RECT  45.8 171.07 60.215 171.47 ;
     RECT  47.775 187.87 60.215 188.27 ;
     RECT  25.095 208.67 60.215 209.07 ;
     RECT  59.815 62.27 60.295 62.67 ;
     RECT  59.815 100.67 60.295 101.07 ;
     RECT  56.175 176.67 60.295 177.07 ;
     RECT  59.535 198.27 60.295 198.67 ;
     RECT  55.095 78.27 60.495 78.67 ;
     RECT  59.095 107.87 61.055 108.27 ;
     RECT  48.295 148.67 61.055 149.07 ;
     RECT  59.095 161.47 61.055 161.87 ;
     RECT  60.375 98.27 61.095 98.67 ;
     RECT  60.655 127.07 61.095 127.47 ;
     RECT  60.655 171.07 61.095 171.47 ;
     RECT  53.655 125.47 61.335 125.87 ;
     RECT  48.055 191.87 61.335 192.27 ;
     RECT  25.895 178.27 61.615 178.67 ;
     RECT  60.695 55.87 61.895 56.27 ;
     RECT  61.495 84.67 61.895 85.07 ;
     RECT  61.495 123.07 61.895 123.47 ;
     RECT  61.495 149.47 61.895 149.87 ;
     RECT  61.495 194.27 61.895 194.67 ;
     RECT  36.015 206.27 61.895 206.67 ;
     RECT  57.495 66.27 62.175 66.67 ;
     RECT  53.895 73.47 62.175 73.87 ;
     RECT  18.655 54.27 62.695 54.67 ;
     RECT  62.055 100.67 62.695 101.07 ;
     RECT  39.095 147.87 62.695 148.27 ;
     RECT  62.295 83.87 63.015 84.27 ;
     RECT  43.095 163.87 63.015 164.27 ;
     RECT  47.495 99.87 63.095 100.27 ;
     RECT  51.975 184.67 63.295 185.07 ;
     RECT  59.095 188.67 63.295 189.07 ;
     RECT  49.175 192.67 63.295 193.07 ;
     RECT  52.815 81.47 63.495 81.87 ;
     RECT  63.095 99.87 63.495 101.07 ;
     RECT  52.095 159.07 63.495 159.47 ;
     RECT  63.095 122.27 63.575 122.67 ;
     RECT  13.895 204.67 63.575 205.07 ;
     RECT  57.095 87.07 63.895 87.47 ;
     RECT  63.095 67.07 64.135 67.47 ;
     RECT  36.295 101.47 64.135 101.87 ;
     RECT  63.735 64.67 64.295 65.07 ;
     RECT  62.335 86.27 64.295 86.67 ;
     RECT  63.895 87.07 64.295 88.27 ;
     RECT  63.175 107.87 64.295 108.27 ;
     RECT  63.455 134.27 64.295 134.67 ;
     RECT  63.735 182.27 64.295 182.67 ;
     RECT  63.895 54.27 64.415 54.67 ;
     RECT  63.895 143.87 64.415 144.27 ;
     RECT  45.8 94.27 64.695 94.67 ;
     RECT  59.095 156.67 64.695 157.07 ;
     RECT  63.895 161.47 64.695 161.87 ;
     RECT  45.535 71.87 64.975 72.27 ;
     RECT  63.095 93.47 64.975 93.87 ;
     RECT  63.895 113.47 64.975 113.87 ;
     RECT  62.615 66.27 65.095 66.67 ;
     RECT  64.575 88.67 65.095 89.07 ;
     RECT  64.575 124.67 65.095 125.07 ;
     RECT  62.615 169.47 65.095 169.87 ;
     RECT  64.575 199.87 65.095 200.27 ;
     RECT  52.535 67.87 65.255 68.27 ;
     RECT  62.295 139.87 65.255 140.27 ;
     RECT  64.695 167.87 65.255 168.27 ;
     RECT  11.095 32.67 65.35 33.07 ;
     RECT  53.095 82.27 65.35 82.67 ;
     RECT  36.695 138.27 65.35 138.67 ;
     RECT  58.135 147.07 65.35 147.47 ;
     RECT  43.015 200.67 65.35 201.07 ;
     RECT  62.055 125.47 65.495 125.87 ;
     RECT  65.35 32.67 65.75 33.87 ;
     RECT  65.35 81.47 65.75 82.67 ;
     RECT  65.35 138.27 65.75 139.47 ;
     RECT  65.35 147.07 65.75 148.27 ;
     RECT  65.35 200.67 65.75 201.87 ;
     RECT  63.095 103.07 65.815 103.47 ;
     RECT  65.415 74.27 65.895 74.67 ;
     RECT  61.495 97.47 65.895 97.87 ;
     RECT  65.415 118.27 65.895 118.67 ;
     RECT  65.495 124.67 65.895 125.87 ;
     RECT  64.855 143.87 65.895 144.27 ;
     RECT  45.535 126.27 66.095 126.67 ;
     RECT  48.615 168.67 66.095 169.07 ;
     RECT  53.095 144.67 66.295 145.07 ;
     RECT  49.175 83.07 66.375 83.47 ;
     RECT  61.215 176.67 66.375 177.07 ;
     RECT  48.695 79.87 66.655 80.27 ;
     RECT  65.495 159.07 66.655 159.47 ;
     RECT  62.055 52.67 66.695 53.07 ;
     RECT  66.255 62.27 66.695 62.67 ;
     RECT  65.975 66.27 66.695 66.67 ;
     RECT  66.255 89.47 66.695 89.87 ;
     RECT  65.975 98.27 66.695 98.67 ;
     RECT  66.295 143.87 66.695 145.07 ;
     RECT  65.695 167.87 66.695 168.27 ;
     RECT  66.295 83.87 66.935 84.27 ;
     RECT  56.295 51.87 67.095 52.27 ;
     RECT  63.455 178.27 67.215 178.67 ;
     RECT  67.095 51.87 67.495 53.07 ;
     RECT  67.095 58.27 67.495 58.67 ;
     RECT  55.055 63.87 67.495 64.27 ;
     RECT  67.095 70.27 67.495 70.67 ;
     RECT  67.095 97.47 67.495 97.87 ;
     RECT  56.735 99.07 67.495 99.47 ;
     RECT  67.095 138.27 67.495 138.67 ;
     RECT  62.615 158.27 67.495 158.67 ;
     RECT  67.095 159.07 67.495 160.27 ;
     RECT  67.095 197.47 67.495 197.87 ;
     RECT  51.135 117.47 67.775 117.87 ;
     RECT  63.495 100.67 68.055 101.07 ;
     RECT  67.095 79.87 68.295 80.27 ;
     RECT  67.375 103.07 68.295 103.47 ;
     RECT  67.095 182.27 68.295 182.67 ;
     RECT  67.895 62.27 68.335 62.67 ;
     RECT  67.895 66.27 68.335 66.67 ;
     RECT  67.895 134.27 68.335 134.67 ;
     RECT  67.895 161.47 68.335 161.87 ;
     RECT  63.095 73.47 68.615 73.87 ;
     RECT  57.855 110.27 68.615 110.67 ;
     RECT  65.75 139.07 68.615 139.47 ;
     RECT  36.575 143.07 68.615 143.47 ;
     RECT  56.175 130.27 68.695 130.67 ;
     RECT  67.935 63.87 69.095 64.27 ;
     RECT  66.815 87.07 69.095 87.47 ;
     RECT  68.215 118.27 69.095 118.67 ;
     RECT  68.215 126.27 69.095 126.67 ;
     RECT  68.695 130.27 69.095 131.47 ;
     RECT  61.775 163.07 69.095 163.47 ;
     RECT  50.695 162.27 69.175 162.67 ;
     RECT  67.495 52.67 69.455 53.07 ;
     RECT  53.935 69.47 69.455 69.87 ;
     RECT  54.495 112.67 69.455 113.07 ;
     RECT  68.695 123.07 69.455 123.47 ;
     RECT  11.095 215.07 69.455 215.47 ;
     RECT  59.935 133.47 69.615 133.87 ;
     RECT  68.695 101.47 69.735 101.87 ;
     RECT  69.335 55.87 69.895 56.27 ;
     RECT  69.055 97.47 69.895 97.87 ;
     RECT  67.895 107.87 70.015 108.27 ;
     RECT  69.615 133.47 70.015 134.67 ;
     RECT  25.375 146.27 70.015 146.67 ;
     RECT  67.895 163.87 70.015 164.27 ;
     RECT  46.935 199.07 70.015 199.47 ;
     RECT  45.095 127.87 70.855 128.27 ;
     RECT  58.415 152.67 70.855 153.07 ;
     RECT  67.655 87.87 71.095 88.27 ;
     RECT  67.895 93.47 71.135 93.87 ;
     RECT  71.095 87.87 71.495 89.07 ;
     RECT  70.455 107.87 71.495 108.27 ;
     RECT  65.975 169.47 71.495 169.87 ;
     RECT  67.095 192.67 71.495 193.07 ;
     RECT  69.495 144.67 71.695 145.07 ;
     RECT  59.895 189.47 71.695 189.87 ;
     RECT  52.695 157.47 71.975 157.87 ;
     RECT  63.895 80.67 72.255 81.07 ;
     RECT  71.015 108.67 72.295 109.07 ;
     RECT  71.855 134.27 72.295 134.67 ;
     RECT  71.575 182.27 72.295 182.67 ;
     RECT  57.095 55.07 72.535 55.47 ;
     RECT  62.895 116.67 72.695 117.07 ;
     RECT  69.335 167.87 72.695 168.27 ;
     RECT  71.895 55.87 72.815 56.27 ;
     RECT  71.895 191.87 72.815 192.27 ;
     RECT  72.415 68.67 73.095 69.07 ;
     RECT  59.535 95.07 73.095 95.47 ;
     RECT  71.575 100.67 73.095 101.07 ;
     RECT  72.695 116.67 73.095 117.87 ;
     RECT  72.695 129.47 73.095 129.87 ;
     RECT  46.095 140.67 73.095 141.07 ;
     RECT  58.695 142.27 73.095 142.67 ;
     RECT  72.695 167.87 73.095 169.07 ;
     RECT  58.695 71.07 73.375 71.47 ;
     RECT  21.495 43.07 73.655 43.47 ;
     RECT  72.415 178.27 73.895 178.67 ;
     RECT  71.295 207.87 73.895 208.27 ;
     RECT  72.695 163.87 73.935 164.27 ;
     RECT  73.495 175.07 73.935 175.47 ;
     RECT  73.495 143.07 74.215 143.47 ;
     RECT  73.495 167.87 74.215 168.27 ;
     RECT  56.175 183.07 74.215 183.47 ;
     RECT  64.855 193.47 74.495 193.87 ;
     RECT  65.895 124.67 74.775 125.07 ;
     RECT  74.295 142.27 74.775 142.67 ;
     RECT  61.495 174.27 75.095 174.67 ;
     RECT  24.815 207.07 75.095 207.47 ;
     RECT  60.935 57.47 75.335 57.87 ;
     RECT  74.935 59.07 75.495 59.47 ;
     RECT  74.935 93.47 75.495 93.87 ;
     RECT  69.895 128.67 75.495 129.07 ;
     RECT  73.095 168.67 75.495 169.07 ;
     RECT  75.095 174.27 75.495 175.47 ;
     RECT  75.095 206.27 75.495 207.47 ;
     RECT  75.095 68.67 75.615 69.07 ;
     RECT  75.095 74.27 75.615 74.67 ;
     RECT  75.095 138.27 75.615 138.67 ;
     RECT  75.095 161.47 75.615 161.87 ;
     RECT  75.095 193.47 75.895 193.87 ;
     RECT  70.735 70.27 76.055 70.67 ;
     RECT  72.135 147.07 76.295 147.47 ;
     RECT  74.295 58.27 76.455 58.67 ;
     RECT  76.055 70.27 76.455 71.47 ;
     RECT  75.895 87.07 76.455 87.47 ;
     RECT  75.895 134.27 76.455 134.67 ;
     RECT  76.615 97.47 76.695 97.87 ;
     RECT  65.135 99.87 76.695 100.27 ;
     RECT  69.095 131.07 76.735 131.47 ;
     RECT  74.295 103.87 77.015 104.27 ;
     RECT  62.615 115.87 77.015 116.27 ;
     RECT  66.295 155.07 77.015 155.47 ;
     RECT  30.695 175.87 77.015 176.27 ;
     RECT  72.975 80.67 77.095 81.07 ;
     RECT  76.615 89.47 77.095 89.87 ;
     RECT  76.695 97.47 77.095 100.27 ;
     RECT  76.055 168.67 77.095 169.07 ;
     RECT  68.215 184.67 77.095 185.07 ;
     RECT  76.615 194.27 77.095 194.67 ;
     RECT  59.815 85.47 77.295 85.87 ;
     RECT  65.415 127.07 77.295 127.47 ;
     RECT  42.455 210.27 77.295 210.67 ;
     RECT  61.775 63.07 77.575 63.47 ;
     RECT  66.535 125.47 77.575 125.87 ;
     RECT  70.295 123.07 77.855 123.47 ;
     RECT  60.375 56.67 77.895 57.07 ;
     RECT  76.895 68.67 77.895 69.07 ;
     RECT  77.175 70.27 77.895 70.67 ;
     RECT  76.895 93.47 77.895 93.87 ;
     RECT  77.175 161.47 77.895 161.87 ;
     RECT  63.095 145.47 78.135 145.87 ;
     RECT  76.455 71.07 78.295 71.47 ;
     RECT  77.495 167.87 78.415 168.27 ;
     RECT  78.295 62.27 78.695 62.67 ;
     RECT  78.295 70.27 78.695 71.47 ;
     RECT  76.895 95.07 78.695 95.47 ;
     RECT  78.015 129.47 78.695 129.87 ;
     RECT  78.015 147.07 78.695 147.47 ;
     RECT  78.015 155.07 78.695 155.47 ;
     RECT  78.295 207.07 78.695 207.47 ;
     RECT  67.935 86.27 79.255 86.67 ;
     RECT  72.975 79.87 79.495 80.27 ;
     RECT  78.855 167.87 79.495 168.27 ;
     RECT  78.855 189.47 79.495 189.87 ;
     RECT  62.615 109.47 79.535 109.87 ;
     RECT  79.095 123.07 79.535 123.47 ;
     RECT  79.095 85.47 79.815 85.87 ;
     RECT  79.095 194.27 79.815 194.67 ;
     RECT  50.855 203.07 79.815 203.47 ;
     RECT  41.495 50.27 80.095 50.67 ;
     RECT  76.695 107.87 80.095 108.27 ;
     RECT  77.495 144.67 80.095 145.07 ;
     RECT  46.095 170.27 80.095 170.67 ;
     RECT  79.895 55.07 80.375 55.47 ;
     RECT  46.655 102.27 80.375 102.67 ;
     RECT  79.895 157.47 80.375 157.87 ;
     RECT  75.895 191.87 80.375 192.27 ;
     RECT  19.495 211.87 80.375 212.27 ;
     RECT  79.895 187.87 80.655 188.27 ;
     RECT  75.895 57.47 80.935 57.87 ;
     RECT  65.495 205.47 80.935 205.87 ;
     RECT  65.695 72.67 81.095 73.07 ;
     RECT  80.535 94.27 81.095 94.67 ;
     RECT  80.535 163.87 81.095 164.27 ;
     RECT  70.175 162.27 81.215 162.67 ;
     RECT  67.935 158.27 81.495 158.67 ;
     RECT  75.495 206.27 81.775 206.67 ;
     RECT  80.815 52.67 81.895 53.07 ;
     RECT  81.375 110.27 81.895 110.67 ;
     RECT  81.495 157.47 81.895 158.67 ;
     RECT  81.375 182.27 81.895 182.67 ;
     RECT  79.695 207.87 81.895 208.27 ;
     RECT  81.495 178.27 82.055 178.67 ;
     RECT  79.895 138.27 82.335 138.67 ;
     RECT  72.695 199.87 82.335 200.27 ;
     RECT  74.095 154.27 82.615 154.67 ;
     RECT  51.495 187.07 82.615 187.47 ;
     RECT  81.655 56.67 82.695 57.07 ;
     RECT  82.215 94.27 82.695 94.67 ;
     RECT  82.215 189.47 82.695 189.87 ;
     RECT  73.095 117.47 82.895 117.87 ;
     RECT  71.855 152.67 82.895 153.07 ;
     RECT  75.215 163.07 82.895 163.47 ;
     RECT  82.295 171.07 82.895 171.47 ;
     RECT  75.095 183.07 82.895 183.47 ;
     RECT  67.375 78.27 83.175 78.67 ;
     RECT  71.495 88.67 83.175 89.07 ;
     RECT  51.135 171.87 83.175 172.27 ;
     RECT  78.295 174.27 83.175 174.67 ;
     RECT  79.095 124.67 83.455 125.07 ;
     RECT  67.895 156.67 83.455 157.07 ;
     RECT  47.895 209.47 83.455 209.87 ;
     RECT  57.015 41.47 83.735 41.87 ;
     RECT  61.495 79.07 84.015 79.47 ;
     RECT  83.895 79.87 84.295 80.27 ;
     RECT  59.535 92.67 84.295 93.07 ;
     RECT  83.895 159.07 84.295 159.47 ;
     RECT  83.095 161.47 84.295 161.87 ;
     RECT  83.895 199.87 84.295 200.27 ;
     RECT  78.295 125.47 84.575 125.87 ;
     RECT  83.095 127.07 84.575 127.47 ;
     RECT  59.815 185.47 84.575 185.87 ;
     RECT  83.895 78.27 85.095 78.67 ;
     RECT  84.695 62.27 85.135 62.67 ;
     RECT  84.695 170.27 85.135 170.67 ;
     RECT  78.015 98.27 85.3 98.67 ;
     RECT  76.335 118.27 85.3 118.67 ;
     RECT  84.695 194.27 85.415 194.67 ;
     RECT  69.615 130.27 85.695 130.67 ;
     RECT  83.095 178.27 85.695 178.67 ;
     RECT  85.3 98.27 85.7 99.47 ;
     RECT  85.3 117.47 85.7 118.67 ;
     RECT  45.255 95.87 85.895 96.27 ;
     RECT  69.055 83.87 85.975 84.27 ;
     RECT  73.535 108.67 85.975 109.07 ;
     RECT  63.175 141.47 85.975 141.87 ;
     RECT  85.495 158.27 85.975 158.67 ;
     RECT  85.495 163.07 85.975 163.47 ;
     RECT  85.495 185.47 85.975 185.87 ;
     RECT  55.055 186.27 85.975 186.67 ;
     RECT  77.095 97.47 86.255 97.87 ;
     RECT  66.695 143.87 86.255 144.27 ;
     RECT  58.415 96.67 86.295 97.07 ;
     RECT  78.575 63.87 86.535 64.27 ;
     RECT  86.295 95.87 86.695 97.07 ;
     RECT  86.135 163.87 86.695 164.27 ;
     RECT  86.135 187.87 86.695 188.27 ;
     RECT  86.295 56.67 87.095 57.07 ;
     RECT  72.135 169.47 87.095 169.87 ;
     RECT  86.295 99.87 87.375 100.27 ;
     RECT  86.295 162.27 87.375 162.67 ;
     RECT  86.975 89.47 87.495 89.87 ;
     RECT  86.695 175.87 87.495 176.27 ;
     RECT  84.695 107.87 87.655 108.27 ;
     RECT  43.015 132.67 87.655 133.07 ;
     RECT  87.095 194.27 87.655 194.67 ;
     RECT  57.575 203.87 88.215 204.27 ;
     RECT  85.855 88.67 88.295 89.07 ;
     RECT  87.815 122.27 88.295 122.67 ;
     RECT  87.255 127.07 88.295 127.47 ;
     RECT  87.895 55.07 88.495 55.47 ;
     RECT  71.575 139.87 88.775 140.27 ;
     RECT  60.655 177.47 88.775 177.87 ;
     RECT  87.895 189.47 88.775 189.87 ;
     RECT  74.655 192.67 88.775 193.07 ;
     RECT  88.655 99.87 89.095 100.27 ;
     RECT  66.815 176.67 89.095 177.07 ;
     RECT  75.495 175.07 89.335 175.47 ;
     RECT  89.495 62.27 89.895 62.67 ;
     RECT  89.495 66.27 89.895 66.67 ;
     RECT  89.495 128.67 89.895 129.07 ;
     RECT  62.335 148.67 89.895 149.07 ;
     RECT  88.695 193.47 89.895 193.87 ;
     RECT  89.495 197.47 89.895 197.87 ;
     RECT  89.495 209.47 89.895 209.87 ;
     RECT  48.335 123.87 90.175 124.27 ;
     RECT  69.615 126.27 90.175 126.67 ;
     RECT  89.495 71.07 90.695 71.47 ;
     RECT  84.455 73.47 90.695 73.87 ;
     RECT  63.735 202.27 90.695 202.67 ;
     RECT  49.495 22.27 90.735 22.67 ;
     RECT  85.495 94.27 90.735 94.67 ;
     RECT  88.695 162.27 90.735 162.67 ;
     RECT  90.295 178.27 90.735 178.67 ;
     RECT  71.015 69.47 91.295 69.87 ;
     RECT  68.215 111.07 91.295 111.47 ;
     RECT  62.615 183.87 91.295 184.27 ;
     RECT  61.495 208.67 91.295 209.07 ;
     RECT  86.975 156.67 91.495 157.07 ;
     RECT  90.615 177.47 91.495 177.87 ;
     RECT  71.015 54.27 91.575 54.67 ;
     RECT  91.095 107.87 91.575 108.27 ;
     RECT  91.095 118.27 91.575 118.67 ;
     RECT  88.695 124.67 91.575 125.07 ;
     RECT  91.095 85.47 91.855 85.87 ;
     RECT  64.855 190.27 91.855 190.67 ;
     RECT  88.695 199.07 91.855 199.47 ;
     RECT  88.695 72.67 91.895 73.07 ;
     RECT  91.095 148.67 92.135 149.07 ;
     RECT  91.895 72.67 92.295 73.87 ;
     RECT  73.815 116.67 92.295 117.07 ;
     RECT  91.175 207.07 92.295 207.47 ;
     RECT  91.895 127.07 92.415 127.47 ;
     RECT  59.815 153.47 92.415 153.87 ;
     RECT  56.175 155.87 92.415 156.27 ;
     RECT  91.095 56.67 92.975 57.07 ;
     RECT  92.295 73.47 92.975 73.87 ;
     RECT  65.135 188.67 92.975 189.07 ;
     RECT  82.495 103.07 93.095 103.47 ;
     RECT  86.975 127.87 93.095 128.27 ;
     RECT  92.695 62.27 93.255 62.67 ;
     RECT  46.295 160.67 93.255 161.07 ;
     RECT  68.695 159.87 93.535 160.27 ;
     RECT  65.75 81.47 93.815 81.87 ;
     RECT  91.095 97.47 93.815 97.87 ;
     RECT  83.095 198.27 93.815 198.67 ;
     RECT  85.015 63.07 93.895 63.47 ;
     RECT  93.415 88.67 93.895 89.07 ;
     RECT  93.415 123.07 93.895 123.47 ;
     RECT  93.415 149.47 93.895 149.87 ;
     RECT  91.735 185.47 93.895 185.87 ;
     RECT  90.295 57.47 94.375 57.87 ;
     RECT  59.815 65.47 94.375 65.87 ;
     RECT  92.695 85.47 94.375 85.87 ;
     RECT  74.095 100.67 94.375 101.07 ;
     RECT  60.375 131.87 94.375 132.27 ;
     RECT  79.695 87.07 94.655 87.47 ;
     RECT  85.7 117.47 94.655 117.87 ;
     RECT  94.255 127.87 94.695 128.27 ;
     RECT  69.055 71.87 94.935 72.27 ;
     RECT  95.095 54.27 95.495 54.67 ;
     RECT  79.415 55.87 95.495 56.27 ;
     RECT  95.095 82.27 95.495 82.67 ;
     RECT  86.695 95.87 95.495 96.27 ;
     RECT  88.095 132.67 95.495 133.07 ;
     RECT  47.895 28.67 95.775 29.07 ;
     RECT  92.695 161.47 95.775 161.87 ;
     RECT  93.495 96.67 96.055 97.07 ;
     RECT  81.895 157.47 96.055 157.87 ;
     RECT  77.735 173.47 96.055 173.87 ;
     RECT  95.655 87.07 96.295 87.47 ;
     RECT  95.655 111.07 96.295 111.47 ;
     RECT  68.775 51.87 96.335 52.27 ;
     RECT  78.695 70.27 96.615 70.67 ;
     RECT  87.895 108.67 96.695 109.07 ;
     RECT  70.455 101.47 96.895 101.87 ;
     RECT  68.695 39.07 97.095 39.47 ;
     RECT  95.375 81.47 97.095 81.87 ;
     RECT  96.695 107.87 97.095 109.07 ;
     RECT  91.895 93.47 97.175 93.87 ;
     RECT  85.7 99.07 97.175 99.47 ;
     RECT  90.615 110.27 97.175 110.67 ;
     RECT  69.895 115.07 97.175 115.47 ;
     RECT  41.895 211.07 97.895 211.47 ;
     RECT  97.495 88.67 98.015 89.07 ;
     RECT  91.095 92.67 98.015 93.07 ;
     RECT  97.495 94.27 98.015 94.67 ;
     RECT  95.095 167.87 98.015 168.27 ;
     RECT  65.75 33.47 98.695 33.87 ;
     RECT  90.895 145.47 98.695 145.87 ;
     RECT  97.495 175.87 98.855 176.27 ;
     RECT  65.75 147.87 99.415 148.27 ;
     RECT  99.095 62.27 99.695 62.67 ;
     RECT  69.055 84.67 99.695 85.07 ;
     RECT  86.975 102.27 99.695 102.67 ;
     RECT  97.095 107.87 99.975 108.27 ;
     RECT  97.495 160.67 99.975 161.07 ;
     RECT  87.535 138.27 100.295 138.67 ;
     RECT  86.415 184.67 100.295 185.07 ;
     RECT  65.415 47.87 100.815 48.27 ;
     RECT  53.935 51.07 100.815 51.47 ;
     RECT  81.095 133.47 101.095 133.87 ;
     RECT  65.75 201.47 101.375 201.87 ;
     RECT  80.815 86.27 101.655 86.67 ;
     RECT  101.255 64.67 101.895 65.07 ;
     RECT  101.255 99.87 101.895 100.27 ;
     RECT  79.135 80.67 101.935 81.07 ;
     RECT  68.495 111.87 101.935 112.27 ;
     RECT  101.495 161.47 102.215 161.87 ;
     RECT  100.695 163.87 102.215 164.27 ;
     RECT  80.255 109.47 102.495 109.87 ;
     RECT  53.495 35.87 103.495 36.27 ;
     RECT  95.375 79.87 103.495 80.27 ;
     RECT  91.735 146.27 103.495 146.67 ;
     RECT  102.655 211.07 103.495 211.47 ;
     RECT  71.895 87.87 103.615 88.27 ;
     RECT  86.135 98.27 103.615 98.67 ;
     RECT  70.735 139.07 103.895 139.47 ;
     RECT  29.015 214.27 103.895 214.67 ;
     RECT  103.775 54.27 104.295 54.67 ;
     RECT  103.775 73.47 104.295 73.87 ;
     RECT  103.895 163.07 104.455 163.47 ;
     RECT  103.895 78.27 105.015 78.67 ;
     RECT  104.335 65.47 105.095 65.87 ;
     RECT  21.175 42.27 105.295 42.67 ;
     RECT  65.495 49.47 105.575 49.87 ;
     RECT  79.415 95.07 105.855 95.47 ;
     RECT  69.055 24.67 105.895 25.07 ;
     RECT  95.375 127.87 105.895 128.27 ;
     RECT  93.695 147.07 105.895 147.47 ;
     RECT  105.455 211.07 105.895 211.47 ;
     RECT  84.455 79.07 106.135 79.47 ;
     RECT  79.695 103.87 106.415 104.27 ;
     RECT  85.295 144.67 106.415 145.07 ;
     RECT  85.015 191.87 106.415 192.27 ;
     RECT  76.615 53.47 106.695 53.87 ;
     RECT  99.015 93.47 106.695 93.87 ;
     RECT  85.855 143.07 106.695 143.47 ;
     RECT  92.575 193.47 106.695 193.87 ;
     RECT  106.855 62.27 107.495 62.67 ;
     RECT  48.055 38.27 107.815 38.67 ;
     RECT  93.695 58.27 108.095 58.67 ;
     RECT  15.015 212.67 108.095 213.07 ;
     RECT  93.695 56.67 108.295 57.07 ;
     RECT  102.375 88.67 108.295 89.07 ;
     RECT  92.695 152.67 108.655 153.07 ;
     RECT  95.375 71.07 109.095 71.47 ;
     RECT  102.375 97.47 109.095 97.87 ;
     RECT  108.535 161.47 109.095 161.87 ;
     RECT  73.255 114.27 109.775 114.67 ;
     RECT  109.095 83.07 109.895 83.47 ;
     RECT  99.295 159.87 109.895 160.27 ;
     RECT  102.375 63.07 110.055 63.47 ;
     RECT  111.095 161.47 111.735 161.87 ;
     RECT  111.895 54.27 112.295 54.67 ;
     RECT  111.895 137.47 112.295 137.87 ;
     RECT  88.935 43.87 113.095 44.27 ;
     RECT  111.615 37.47 113.895 37.87 ;
     RECT  114.135 62.27 114.695 62.67 ;
     RECT  98.295 72.67 114.695 73.07 ;
     RECT  104.615 98.27 114.695 98.67 ;
     RECT  114.135 202.27 114.695 202.67 ;
     RECT  114.295 36.67 115.095 37.07 ;
     RECT  99.015 68.67 115.095 69.07 ;
     RECT  115.095 86.27 115.655 86.67 ;
     RECT  115.815 108.67 116.295 109.07 ;
     RECT  113.495 65.47 117.095 65.87 ;
     RECT  116.655 159.07 117.095 159.47 ;
     RECT  116.695 83.07 117.335 83.47 ;
     RECT  115.895 87.87 117.895 88.27 ;
     RECT  118.295 35.07 118.735 35.47 ;
     RECT  117.495 57.47 119.495 57.87 ;
     RECT  110.295 83.87 119.855 84.27 ;
     RECT  119.095 118.27 120.135 118.67 ;
     RECT  119.895 54.27 120.415 54.67 ;
     RECT  119.895 163.87 120.695 164.27 ;
     RECT  119.735 128.67 121.895 129.07 ;
     RECT  121.495 175.07 121.895 177.07 ;
     RECT  121.495 27.87 122.095 28.27 ;
     RECT  121.895 176.67 122.095 177.07 ;
     RECT  118.295 63.87 122.375 64.27 ;
     RECT  121.975 62.27 122.695 62.67 ;
     RECT  122.255 103.87 122.695 104.27 ;
     RECT  115.095 115.07 122.935 115.47 ;
     RECT  122.295 138.27 123.215 138.67 ;
     RECT  121.495 88.67 123.495 89.07 ;
     RECT  123.095 160.67 123.775 161.07 ;
     RECT  123.375 111.87 124.295 112.27 ;
     RECT  123.375 127.87 124.295 128.27 ;
     RECT  123.895 62.27 124.335 62.67 ;
     RECT  123.895 64.67 124.615 65.07 ;
     RECT  124.495 94.27 125.095 94.67 ;
     RECT  124.495 198.27 125.095 198.67 ;
     RECT  124.695 77.47 125.175 77.87 ;
     RECT  123.375 51.87 125.2 52.27 ;
     RECT  124.695 55.07 125.455 55.47 ;
     RECT  112.735 63.07 125.455 63.47 ;
     RECT  125.2 51.87 125.6 53.07 ;
     RECT  124.695 68.67 125.735 69.07 ;
     RECT  119.095 79.07 125.735 79.47 ;
     RECT  117.495 85.47 125.735 85.87 ;
     RECT  114.295 139.07 125.735 139.47 ;
     RECT  125.335 89.47 125.895 89.87 ;
     RECT  125.335 139.87 125.895 140.27 ;
     RECT  116.095 78.27 126.295 78.67 ;
     RECT  126.295 78.27 126.695 79.47 ;
     RECT  126.295 51.87 126.855 52.27 ;
     RECT  125.495 126.27 126.855 126.67 ;
     RECT  122.295 154.27 126.855 154.67 ;
     RECT  126.295 37.47 127.415 37.87 ;
     RECT  126.735 99.87 127.495 100.27 ;
     RECT  127.095 47.87 127.695 48.27 ;
     RECT  127.575 88.67 128.295 89.07 ;
     RECT  126.295 132.67 128.295 133.07 ;
     RECT  125.615 140.67 128.295 141.07 ;
     RECT  127.095 71.07 128.535 71.47 ;
     RECT  113.495 129.47 128.535 129.87 ;
     RECT  112.695 178.27 128.535 178.67 ;
     RECT  124.695 98.27 128.815 98.67 ;
     RECT  127.895 142.27 128.815 142.67 ;
     RECT  126.295 145.47 128.815 145.87 ;
     RECT  127.895 147.07 128.815 147.47 ;
     RECT  127.895 167.87 128.815 168.27 ;
     RECT  122.295 48.67 129.095 49.07 ;
     RECT  119.175 70.27 129.095 70.67 ;
     RECT  119.735 123.07 129.095 123.47 ;
     RECT  123.895 131.87 129.095 132.27 ;
     RECT  127.895 58.27 129.655 58.67 ;
     RECT  128.695 47.87 129.895 48.27 ;
     RECT  129.255 71.07 129.895 71.47 ;
     RECT  129.255 103.87 129.895 104.27 ;
     RECT  127.855 146.27 129.895 146.67 ;
     RECT  125.055 64.67 130.215 65.07 ;
     RECT  121.415 177.47 130.295 177.87 ;
     RECT  119.175 161.47 130.495 161.87 ;
     RECT  125.6 52.67 130.695 53.07 ;
     RECT  127.095 81.47 130.695 81.87 ;
     RECT  130.295 177.47 130.695 178.67 ;
     RECT  128.695 53.47 130.775 53.87 ;
     RECT  129.495 51.87 131.055 52.27 ;
     RECT  130.295 70.27 131.055 70.67 ;
     RECT  123.895 87.87 131.335 88.27 ;
     RECT  130.935 57.47 131.495 57.87 ;
     RECT  125.335 109.47 131.495 109.87 ;
     RECT  131.095 67.07 131.615 67.47 ;
     RECT  125.495 36.67 131.895 37.07 ;
     RECT  113.575 102.27 131.895 102.67 ;
     RECT  118.335 152.67 131.895 153.07 ;
     RECT  131.095 138.27 132.175 138.67 ;
     RECT  131.895 35.87 132.295 37.07 ;
     RECT  130.095 113.47 132.295 113.87 ;
     RECT  131.895 152.67 132.295 154.67 ;
     RECT  132.055 55.07 132.695 55.47 ;
     RECT  131.895 163.87 132.735 164.27 ;
     RECT  125.055 99.07 133.015 99.47 ;
     RECT  132.615 48.67 133.095 49.07 ;
     RECT  132.695 55.07 133.095 57.07 ;
     RECT  131.495 63.07 133.095 63.47 ;
     RECT  132.615 89.47 133.095 89.87 ;
     RECT  132.335 161.47 133.095 161.87 ;
     RECT  132.695 138.27 133.295 138.67 ;
     RECT  118.335 71.87 133.575 72.27 ;
     RECT  120.575 130.27 133.575 130.67 ;
     RECT  131.895 143.87 133.575 144.27 ;
     RECT  133.175 36.67 133.895 37.07 ;
     RECT  132.615 47.87 133.895 48.27 ;
     RECT  131.495 72.67 133.895 73.07 ;
     RECT  133.455 95.07 133.895 95.47 ;
     RECT  132.695 87.87 134.135 88.27 ;
     RECT  132.695 153.47 134.135 153.87 ;
     RECT  112.455 38.27 134.415 38.67 ;
     RECT  122.255 143.07 134.415 143.47 ;
     RECT  134.295 49.47 134.695 49.87 ;
     RECT  133.455 81.47 134.695 81.87 ;
     RECT  133.735 134.27 134.695 134.67 ;
     RECT  134.295 149.47 134.695 149.87 ;
     RECT  132.295 154.27 135.095 154.67 ;
     RECT  134.295 55.07 135.255 55.47 ;
     RECT  125.495 162.27 135.255 162.67 ;
     RECT  134.015 34.27 135.495 34.67 ;
     RECT  134.855 55.87 135.495 56.27 ;
     RECT  133.455 78.27 135.495 78.67 ;
     RECT  135.095 153.47 135.495 154.67 ;
     RECT  135.095 143.07 135.535 143.47 ;
     RECT  135.095 163.87 135.535 164.27 ;
     RECT  110.295 51.07 136.295 51.47 ;
     RECT  133.095 56.67 136.295 57.07 ;
     RECT  134.295 130.27 136.295 130.67 ;
     RECT  135.695 147.07 136.295 147.47 ;
     RECT  135.695 168.67 136.295 169.07 ;
     RECT  134.295 64.67 136.375 65.07 ;
     RECT  134.295 71.07 136.935 71.47 ;
     RECT  135.895 170.27 136.935 170.67 ;
     RECT  122.255 65.47 137.095 65.87 ;
     RECT  136.695 59.07 137.215 59.47 ;
     RECT  136.695 79.87 137.215 80.27 ;
     RECT  118.895 156.67 137.215 157.07 ;
     RECT  118.615 174.27 137.215 174.67 ;
     RECT  135.895 18.27 137.495 18.67 ;
     RECT  109.495 19.07 137.495 19.47 ;
     RECT  132.695 85.47 137.495 85.87 ;
     RECT  136.695 103.87 137.775 104.27 ;
     RECT  122.255 112.67 137.775 113.07 ;
     RECT  133.455 145.47 137.775 145.87 ;
     RECT  136.815 32.67 137.895 33.07 ;
     RECT  137.375 55.87 137.895 56.27 ;
     RECT  136.815 80.67 137.895 81.07 ;
     RECT  129.495 139.87 137.895 140.27 ;
     RECT  137.495 114.27 138.055 114.67 ;
     RECT  137.495 160.67 138.055 161.07 ;
     RECT  137.935 22.27 138.695 22.67 ;
     RECT  118.895 23.87 138.695 24.27 ;
     RECT  128.415 35.07 138.695 35.47 ;
     RECT  137.655 79.87 138.695 80.27 ;
     RECT  125.335 147.87 138.695 148.27 ;
     RECT  135.415 152.67 138.695 153.07 ;
     RECT  137.495 43.87 138.895 44.27 ;
     RECT  138.295 47.87 138.895 48.27 ;
     RECT  138.295 68.67 138.895 69.07 ;
     RECT  130.695 178.27 138.895 178.67 ;
     RECT  124.215 157.47 139.455 157.87 ;
     RECT  139.055 33.47 139.495 33.87 ;
     RECT  138.495 41.47 139.495 41.87 ;
     RECT  138.775 63.07 139.495 63.47 ;
     RECT  138.495 71.87 139.495 72.27 ;
     RECT  136.695 108.67 139.495 109.07 ;
     RECT  139.055 163.87 139.495 164.27 ;
     RECT  137.495 64.67 139.735 65.07 ;
     RECT  139.095 134.27 139.735 134.67 ;
     RECT  139.095 167.87 139.735 168.27 ;
     RECT  137.655 156.67 139.895 157.07 ;
     RECT  131.095 93.47 140.015 93.87 ;
     RECT  133.175 100.67 140.015 101.07 ;
     RECT  124.215 141.47 140.015 141.87 ;
     RECT  139.895 49.47 140.295 49.87 ;
     RECT  139.895 89.47 140.295 89.87 ;
     RECT  135.095 116.67 140.295 117.07 ;
     RECT  139.895 156.67 140.295 157.87 ;
     RECT  139.895 160.67 140.295 161.07 ;
     RECT  130.295 124.67 140.575 125.07 ;
     RECT  140.695 127.87 141.135 128.27 ;
     RECT  140.695 137.47 141.135 137.87 ;
     RECT  140.695 163.87 141.135 164.27 ;
     RECT  127.855 69.47 141.415 69.87 ;
     RECT  141.295 53.47 141.895 53.87 ;
     RECT  141.295 94.27 141.895 94.67 ;
     RECT  125.615 128.67 141.895 129.07 ;
     RECT  140.735 160.67 141.895 161.07 ;
     RECT  141.495 156.67 141.975 157.07 ;
     RECT  142.135 123.87 142.295 124.27 ;
     RECT  128.415 125.47 142.295 125.87 ;
     RECT  130.375 146.27 142.295 146.67 ;
     RECT  126.735 159.07 142.535 159.47 ;
     RECT  142.135 29.47 142.695 29.87 ;
     RECT  142.135 83.87 142.695 84.27 ;
     RECT  142.295 123.87 142.695 125.87 ;
     RECT  142.295 146.27 142.695 147.47 ;
     RECT  141.855 152.67 142.695 153.07 ;
     RECT  123.095 24.67 142.815 25.07 ;
     RECT  117.495 39.07 142.815 39.47 ;
     RECT  115.895 40.67 142.815 41.07 ;
     RECT  124.495 63.87 142.815 64.27 ;
     RECT  126.695 79.07 142.815 79.47 ;
     RECT  141.495 138.27 142.815 138.67 ;
     RECT  132.335 84.67 143.095 85.07 ;
     RECT  127.575 87.07 143.095 87.47 ;
     RECT  131.495 126.27 143.095 126.67 ;
     RECT  132.335 88.67 143.375 89.07 ;
     RECT  124.495 176.67 143.375 177.07 ;
     RECT  142.975 43.87 143.495 44.27 ;
     RECT  142.695 53.47 143.495 53.87 ;
     RECT  143.095 83.87 143.495 85.07 ;
     RECT  138.295 98.27 143.655 98.67 ;
     RECT  143.095 102.27 143.655 102.67 ;
     RECT  143.095 149.47 143.655 149.87 ;
     RECT  142.135 87.87 143.895 88.27 ;
     RECT  143.535 74.27 144.295 74.67 ;
     RECT  143.815 77.47 144.295 77.87 ;
     RECT  143.895 87.07 144.295 88.27 ;
     RECT  142.135 103.87 144.295 104.27 ;
     RECT  143.815 108.67 144.295 109.07 ;
     RECT  143.095 47.87 144.495 48.27 ;
     RECT  143.895 162.27 144.495 162.67 ;
     RECT  143.095 55.87 144.775 56.27 ;
     RECT  127.295 139.07 144.775 139.47 ;
     RECT  143.895 163.87 145.055 164.27 ;
     RECT  144.095 32.67 145.095 33.07 ;
     RECT  134.295 58.27 145.095 58.67 ;
     RECT  132.615 97.47 145.095 97.87 ;
     RECT  144.655 122.27 145.095 122.67 ;
     RECT  144.375 124.67 145.095 125.07 ;
     RECT  142.415 174.27 145.095 174.67 ;
     RECT  144.695 87.87 145.15 88.27 ;
     RECT  144.935 88.67 145.15 89.07 ;
     RECT  124.775 133.47 145.15 133.87 ;
     RECT  129.255 142.27 145.15 142.67 ;
     RECT  144.695 147.87 145.335 148.27 ;
     RECT  135.095 169.47 145.335 169.87 ;
     RECT  145.15 87.87 145.55 89.07 ;
     RECT  145.15 131.87 145.55 133.87 ;
     RECT  145.15 141.47 145.55 142.67 ;
     RECT  134.295 67.87 145.615 68.27 ;
     RECT  135.415 111.07 145.615 111.47 ;
     RECT  121.895 175.07 145.615 175.47 ;
     RECT  145.495 23.07 145.895 23.47 ;
     RECT  145.495 62.27 145.895 62.67 ;
     RECT  143.255 63.87 145.895 64.27 ;
     RECT  145.495 74.27 145.895 74.67 ;
     RECT  143.495 83.87 145.895 84.27 ;
     RECT  142.415 96.67 145.895 97.07 ;
     RECT  124.775 86.27 146.175 86.67 ;
     RECT  129.495 155.07 146.175 155.47 ;
     RECT  143.895 63.07 146.295 63.47 ;
     RECT  142.695 147.07 146.295 147.47 ;
     RECT  146.055 147.87 146.295 148.27 ;
     RECT  123.095 107.87 146.455 108.27 ;
     RECT  125.335 115.07 146.455 115.47 ;
     RECT  145.495 138.27 146.455 138.67 ;
     RECT  145.215 57.47 146.695 57.87 ;
     RECT  146.295 63.07 146.695 64.27 ;
     RECT  145.775 94.27 146.695 94.67 ;
     RECT  146.055 122.27 146.695 122.67 ;
     RECT  146.295 147.07 146.695 148.27 ;
     RECT  139.335 178.27 146.695 178.67 ;
     RECT  143.895 51.07 146.735 51.47 ;
     RECT  146.295 129.47 146.735 129.87 ;
     RECT  143.095 25.47 147.015 25.87 ;
     RECT  132.295 35.87 147.015 36.27 ;
     RECT  140.295 157.47 147.015 157.87 ;
     RECT  146.895 62.27 147.095 62.67 ;
     RECT  146.055 26.27 147.495 26.67 ;
     RECT  147.095 62.27 147.495 63.47 ;
     RECT  146.895 68.67 147.495 69.07 ;
     RECT  146.895 85.47 147.495 85.87 ;
     RECT  146.895 139.87 147.495 140.27 ;
     RECT  145.495 163.87 147.495 164.27 ;
     RECT  132.335 27.07 147.575 27.47 ;
     RECT  146.295 70.27 147.575 70.67 ;
     RECT  147.095 116.67 147.855 117.07 ;
     RECT  135.495 153.47 147.855 153.87 ;
     RECT  144.375 69.47 147.895 69.87 ;
     RECT  128.975 140.67 147.895 141.07 ;
     RECT  145.55 87.87 148.135 88.27 ;
     RECT  133.175 115.87 148.135 116.27 ;
     RECT  130.295 184.67 148.135 185.07 ;
     RECT  147.495 63.07 148.295 63.47 ;
     RECT  147.895 68.67 148.295 69.87 ;
     RECT  147.175 88.67 148.295 89.07 ;
     RECT  147.455 107.87 148.295 108.27 ;
     RECT  147.735 124.67 148.295 125.07 ;
     RECT  147.895 139.87 148.295 141.07 ;
     RECT  147.735 157.47 148.295 157.87 ;
     RECT  133.455 73.47 148.415 73.87 ;
     RECT  143.815 79.07 148.415 79.47 ;
     RECT  128.975 155.87 148.415 156.27 ;
     RECT  122.255 66.27 148.695 66.67 ;
     RECT  125.335 117.47 148.695 117.87 ;
     RECT  148.695 62.27 149.095 63.47 ;
     RECT  144.935 65.47 149.095 65.87 ;
     RECT  149.095 63.07 149.255 63.47 ;
     RECT  148.695 160.67 149.255 161.07 ;
     RECT  139.335 67.07 149.415 67.47 ;
     RECT  141.855 78.27 149.495 78.67 ;
     RECT  149.415 66.27 149.815 67.47 ;
     RECT  148.695 87.87 149.815 88.27 ;
     RECT  147.175 35.07 149.895 35.47 ;
     RECT  149.495 78.27 149.895 80.27 ;
     RECT  148.855 139.07 149.895 139.47 ;
     RECT  149.495 86.27 150.095 86.67 ;
     RECT  143.255 156.67 150.295 157.07 ;
     RECT  149.495 70.27 150.655 70.67 ;
     RECT  142.415 131.07 150.655 131.47 ;
     RECT  150.255 47.87 150.695 48.27 ;
     RECT  150.255 51.07 150.695 51.47 ;
     RECT  149.415 92.67 150.695 93.07 ;
     RECT  150.295 155.87 150.695 157.07 ;
     RECT  144.295 87.07 151.095 87.47 ;
     RECT  130.935 99.87 151.215 100.27 ;
     RECT  148.855 24.67 151.495 25.07 ;
     RECT  136.815 28.67 151.495 29.07 ;
     RECT  134.575 43.07 151.495 43.47 ;
     RECT  146.695 63.87 151.495 64.27 ;
     RECT  147.095 71.07 151.495 71.47 ;
     RECT  151.095 77.47 151.495 77.87 ;
     RECT  151.095 86.27 151.495 87.47 ;
     RECT  151.095 89.47 151.495 89.87 ;
     RECT  118.335 95.87 151.495 96.27 ;
     RECT  138.495 111.87 151.495 112.27 ;
     RECT  151.095 156.67 151.495 157.07 ;
     RECT  151.095 194.27 151.495 194.67 ;
     RECT  150.295 78.27 151.775 78.67 ;
     RECT  151.095 140.67 151.775 141.07 ;
     RECT  136.695 154.27 151.775 154.67 ;
     RECT  145.495 127.87 152.295 128.27 ;
     RECT  151.655 129.47 152.295 129.87 ;
     RECT  151.895 51.87 152.335 52.27 ;
     RECT  139.055 148.67 152.335 149.07 ;
     RECT  146.295 159.07 152.615 159.47 ;
     RECT  148.855 88.67 152.695 89.07 ;
     RECT  152.695 87.87 153.095 89.07 ;
     RECT  146.055 142.27 153.095 142.67 ;
     RECT  142.695 36.67 153.175 37.07 ;
     RECT  152.695 71.07 153.175 71.47 ;
     RECT  152.695 78.27 153.175 78.67 ;
     RECT  137.095 158.27 153.175 158.67 ;
     RECT  152.695 134.27 153.455 134.67 ;
     RECT  136.815 95.07 153.615 95.47 ;
     RECT  147.735 94.27 153.895 94.67 ;
     RECT  153.335 157.47 153.895 157.87 ;
     RECT  153.495 33.47 154.015 33.87 ;
     RECT  124.775 42.27 154.015 42.67 ;
     RECT  150.295 83.87 154.015 84.27 ;
     RECT  153.615 95.07 154.015 96.27 ;
     RECT  145.55 141.47 154.015 141.87 ;
     RECT  145.495 152.67 154.015 153.07 ;
     RECT  128.695 13.47 154.295 13.87 ;
     RECT  153.495 62.27 154.295 62.67 ;
     RECT  153.495 140.67 154.295 141.07 ;
     RECT  144.095 176.67 154.295 177.07 ;
     RECT  137.375 191.87 154.295 192.27 ;
     RECT  154.175 17.47 154.695 17.87 ;
     RECT  154.175 24.67 154.695 25.07 ;
     RECT  154.175 73.47 154.695 73.87 ;
     RECT  144.655 102.27 154.695 102.67 ;
     RECT  153.895 114.27 154.695 114.67 ;
     RECT  152.775 127.87 154.695 128.27 ;
     RECT  130.935 144.67 154.855 145.07 ;
     RECT  149.895 79.87 155.095 80.27 ;
     RECT  141.855 127.07 155.135 127.47 ;
     RECT  139.335 145.47 155.415 145.87 ;
     RECT  155.015 14.27 155.495 14.67 ;
     RECT  155.095 79.07 155.495 80.27 ;
     RECT  153.095 87.87 155.495 88.27 ;
     RECT  155.015 141.47 155.495 141.87 ;
     RECT  155.095 38.27 155.695 38.67 ;
     RECT  155.095 65.47 155.695 65.87 ;
     RECT  147.735 57.47 155.895 57.87 ;
     RECT  155.095 78.27 155.975 78.67 ;
     RECT  155.095 115.07 155.975 115.47 ;
     RECT  147.095 19.07 156.255 19.47 ;
     RECT  155.895 56.67 156.295 57.87 ;
     RECT  155.855 62.27 156.295 62.67 ;
     RECT  154.735 95.07 156.295 95.47 ;
     RECT  153.895 126.27 156.295 126.67 ;
     RECT  155.015 147.87 156.295 148.27 ;
     RECT  149.975 160.67 156.295 161.07 ;
     RECT  154.295 51.07 156.535 51.47 ;
     RECT  143.815 39.07 156.695 39.47 ;
     RECT  147.175 147.07 156.695 147.47 ;
     RECT  150.695 155.87 156.815 156.27 ;
     RECT  156.695 19.07 157.095 19.47 ;
     RECT  155.895 36.67 157.095 37.07 ;
     RECT  156.695 38.27 157.095 39.47 ;
     RECT  155.895 67.87 157.095 68.27 ;
     RECT  146.335 80.67 157.095 81.07 ;
     RECT  142.295 99.07 157.095 99.47 ;
     RECT  138.775 118.27 157.095 118.67 ;
     RECT  156.695 122.27 157.095 122.67 ;
     RECT  153.495 132.67 157.095 133.07 ;
     RECT  156.695 133.47 157.095 134.67 ;
     RECT  156.415 145.47 157.095 145.87 ;
     RECT  156.695 147.07 157.095 148.27 ;
     RECT  156.135 169.47 157.095 169.87 ;
     RECT  156.695 63.07 157.375 63.47 ;
     RECT  142.415 64.67 157.375 65.07 ;
     RECT  151.655 99.87 157.375 100.27 ;
     RECT  152.695 139.07 157.495 139.47 ;
     RECT  156.975 79.87 157.895 80.27 ;
     RECT  157.255 124.67 157.895 125.07 ;
     RECT  157.495 138.27 157.895 139.47 ;
     RECT  111.895 183.87 157.895 184.27 ;
     RECT  157.495 99.07 157.935 99.47 ;
     RECT  155.095 162.27 157.935 162.67 ;
     RECT  131.095 177.47 157.935 177.87 ;
     RECT  157.495 23.87 158.215 24.27 ;
     RECT  157.495 32.67 158.215 33.07 ;
     RECT  141.495 109.47 158.215 109.87 ;
     RECT  148.295 139.87 158.215 140.27 ;
     RECT  157.495 167.87 158.215 168.27 ;
     RECT  152.775 63.87 158.295 64.27 ;
     RECT  156.695 87.87 158.495 88.27 ;
     RECT  125.335 103.07 158.495 103.47 ;
     RECT  150.815 115.87 158.495 116.27 ;
     RECT  147.895 174.27 158.495 174.67 ;
     RECT  149.135 22.27 158.695 22.67 ;
     RECT  158.295 63.87 158.695 65.07 ;
     RECT  155.575 67.07 158.695 67.47 ;
     RECT  158.095 94.27 158.695 94.67 ;
     RECT  158.095 141.47 158.695 141.87 ;
     RECT  157.815 161.47 158.695 161.87 ;
     RECT  158.295 97.47 158.775 97.87 ;
     RECT  157.495 53.47 159.055 53.87 ;
     RECT  154.015 95.87 159.055 96.27 ;
     RECT  149.815 66.27 159.095 66.67 ;
     RECT  146.895 125.47 159.4 125.87 ;
     RECT  156.695 13.47 159.495 13.87 ;
     RECT  155.095 19.87 159.495 20.27 ;
     RECT  159.095 66.27 159.495 67.47 ;
     RECT  158.935 144.67 159.495 145.07 ;
     RECT  157.815 160.67 159.495 161.07 ;
     RECT  159.095 29.47 159.615 29.87 ;
     RECT  156.695 57.47 159.615 57.87 ;
     RECT  159.095 74.27 159.615 74.67 ;
     RECT  159.095 119.07 159.615 119.47 ;
     RECT  159.095 129.47 159.615 129.87 ;
     RECT  155.895 153.47 159.615 153.87 ;
     RECT  159.4 124.67 159.8 125.87 ;
     RECT  159.495 19.07 159.895 20.27 ;
     RECT  153.895 25.47 159.895 25.87 ;
     RECT  156.695 85.47 159.895 85.87 ;
     RECT  145.775 81.47 160.175 81.87 ;
     RECT  159.775 35.07 160.295 35.47 ;
     RECT  159.775 43.87 160.295 44.27 ;
     RECT  159.495 109.47 160.295 109.87 ;
     RECT  158.095 114.27 160.295 114.67 ;
     RECT  159.895 27.87 160.455 28.27 ;
     RECT  159.895 79.87 160.455 80.27 ;
     RECT  159.895 92.67 160.455 93.07 ;
     RECT  159.895 122.27 160.455 122.67 ;
     RECT  156.295 56.67 160.695 57.07 ;
     RECT  136.255 143.07 160.735 143.47 ;
     RECT  133.735 159.87 160.735 160.27 ;
     RECT  144.375 49.47 161.015 49.87 ;
     RECT  159.895 117.47 161.015 117.87 ;
     RECT  136.535 163.07 161.015 163.47 ;
     RECT  159.895 169.47 161.015 169.87 ;
     RECT  160.695 56.67 161.095 57.87 ;
     RECT  160.615 102.27 161.095 102.67 ;
     RECT  160.695 22.27 161.295 22.67 ;
     RECT  149.415 35.87 161.295 36.27 ;
     RECT  160.695 53.47 161.575 53.87 ;
     RECT  159.895 33.47 161.855 33.87 ;
     RECT  148.295 68.67 161.855 69.07 ;
     RECT  160.695 85.47 161.855 85.87 ;
     RECT  156.695 130.27 161.855 130.67 ;
     RECT  161.455 27.87 161.895 28.27 ;
     RECT  161.455 59.07 161.895 59.47 ;
     RECT  160.615 67.87 161.895 68.27 ;
     RECT  161.455 77.47 161.895 77.87 ;
     RECT  159.495 87.07 161.895 87.47 ;
     RECT  159.8 124.67 161.895 125.07 ;
     RECT  158.935 148.67 161.895 149.07 ;
     RECT  161.455 169.47 161.895 169.87 ;
     RECT  159.895 51.07 162.135 51.47 ;
     RECT  151.095 131.07 162.135 131.47 ;
     RECT  134.015 50.27 162.415 50.67 ;
     RECT  161.495 158.27 162.415 158.67 ;
     RECT  148.575 163.87 162.415 164.27 ;
     RECT  144.655 170.27 162.415 170.67 ;
     RECT  147.735 172.67 162.415 173.07 ;
     RECT  160.695 176.67 162.415 177.07 ;
     RECT  156.415 47.87 162.695 48.27 ;
     RECT  161.175 55.87 162.695 56.27 ;
     RECT  162.295 71.07 162.695 71.47 ;
     RECT  161.495 107.87 162.695 108.27 ;
     RECT  161.495 111.07 162.695 111.47 ;
     RECT  147.175 112.67 162.695 113.07 ;
     RECT  162.295 143.07 162.975 143.47 ;
     RECT  145.495 168.67 162.975 169.07 ;
     RECT  161.455 49.47 163.095 49.87 ;
     RECT  162.295 130.27 163.095 130.67 ;
     RECT  127.575 82.27 163.255 82.67 ;
     RECT  157.815 132.67 163.255 133.07 ;
     RECT  157.895 138.27 163.255 138.67 ;
     RECT  163.095 49.47 163.495 50.67 ;
     RECT  163.095 130.27 163.495 131.47 ;
     RECT  158.295 39.07 163.535 39.47 ;
     RECT  156.415 127.07 163.535 127.47 ;
     RECT  142.695 171.07 163.535 171.47 ;
     RECT  134.295 72.67 163.815 73.07 ;
     RECT  163.095 107.87 163.815 108.27 ;
     RECT  163.095 112.67 164.095 113.07 ;
     RECT  163.695 29.47 164.295 29.87 ;
     RECT  162.295 109.47 164.295 109.87 ;
     RECT  162.295 155.07 164.295 155.47 ;
     RECT  163.895 47.87 164.375 48.27 ;
     RECT  163.495 131.07 164.375 131.47 ;
     RECT  163.895 99.07 164.655 99.47 ;
     RECT  158.655 155.87 164.655 156.27 ;
     RECT  157.095 147.87 164.935 148.27 ;
     RECT  164.255 33.47 165.095 33.87 ;
     RECT  164.255 40.67 165.095 41.07 ;
     RECT  161.175 42.27 165.095 42.67 ;
     RECT  164.535 81.47 165.095 81.87 ;
     RECT  164.255 87.07 165.095 87.47 ;
     RECT  164.255 103.87 165.095 104.27 ;
     RECT  136.535 55.07 165.1 55.47 ;
     RECT  143.255 71.87 165.1 72.27 ;
     RECT  156.415 78.27 165.1 78.67 ;
     RECT  136.815 83.07 165.1 83.47 ;
     RECT  153.335 110.27 165.1 110.67 ;
     RECT  163.135 126.27 165.1 126.67 ;
     RECT  158.935 139.07 165.1 139.47 ;
     RECT  160.335 157.47 165.1 157.87 ;
     RECT  162.015 163.07 165.1 163.47 ;
     RECT  164.695 23.87 165.215 24.27 ;
     RECT  154.455 143.87 165.215 144.27 ;
     RECT  164.695 72.67 165.495 73.07 ;
     RECT  164.695 94.27 165.495 94.67 ;
     RECT  155.855 152.67 165.495 153.07 ;
     RECT  165.1 55.07 165.5 56.27 ;
     RECT  165.1 70.27 165.5 72.27 ;
     RECT  165.1 77.47 165.5 78.67 ;
     RECT  165.1 83.07 165.5 84.27 ;
     RECT  165.1 110.27 165.5 111.47 ;
     RECT  165.1 126.27 165.5 127.47 ;
     RECT  165.1 138.27 165.5 139.47 ;
     RECT  165.1 157.47 165.5 158.67 ;
     RECT  165.1 163.07 165.5 164.27 ;
     RECT  159.895 19.07 165.775 19.47 ;
     RECT  139.095 37.47 165.775 37.87 ;
     RECT  163.095 63.07 165.775 63.47 ;
     RECT  153.895 98.27 165.775 98.67 ;
     RECT  163.975 49.47 165.895 49.87 ;
     RECT  164.695 63.87 166.055 64.27 ;
     RECT  165.5 77.47 166.055 77.87 ;
     RECT  157.495 123.07 166.055 123.47 ;
     RECT  163.895 139.87 166.055 140.27 ;
     RECT  152.215 156.67 166.055 157.07 ;
     RECT  163.095 36.67 166.295 37.07 ;
     RECT  164.815 109.47 166.295 109.87 ;
     RECT  165.495 79.87 166.335 80.27 ;
     RECT  153.895 100.67 166.335 101.07 ;
     RECT  165.495 112.67 166.335 113.07 ;
     RECT  154.735 140.67 166.335 141.07 ;
     RECT  162.295 56.67 166.615 57.07 ;
     RECT  166.295 36.67 166.695 37.87 ;
     RECT  166.215 55.07 166.695 55.47 ;
     RECT  166.215 59.07 166.695 59.47 ;
     RECT  166.295 109.47 166.695 110.67 ;
     RECT  166.215 115.87 166.695 116.27 ;
     RECT  165.375 162.27 166.695 162.67 ;
     RECT  166.295 87.87 166.895 88.27 ;
     RECT  165.495 155.07 166.895 155.47 ;
     RECT  156.975 65.47 167.175 65.87 ;
     RECT  141.575 175.87 167.175 176.27 ;
     RECT  121.975 4.67 167.455 5.07 ;
     RECT  166.295 68.67 167.455 69.07 ;
     RECT  166.215 83.07 167.495 83.47 ;
     RECT  166.495 87.07 167.495 87.47 ;
     RECT  167.055 140.67 167.495 141.07 ;
     RECT  162.015 154.27 167.495 154.67 ;
     RECT  166.215 159.07 167.495 159.47 ;
     RECT  142.695 128.67 167.735 129.07 ;
     RECT  154.175 69.47 167.895 69.87 ;
     RECT  167.095 56.67 168.015 57.07 ;
     RECT  167.095 115.07 168.015 115.47 ;
     RECT  145.55 131.87 168.015 132.27 ;
     RECT  159.895 161.47 168.015 161.87 ;
     RECT  167.895 19.07 168.295 19.47 ;
     RECT  130.655 54.27 168.295 54.67 ;
     RECT  167.895 68.67 168.295 69.87 ;
     RECT  167.895 71.07 168.295 71.47 ;
     RECT  167.895 72.67 168.295 73.07 ;
     RECT  163.095 148.67 168.295 149.07 ;
     RECT  167.895 179.07 168.295 179.47 ;
     RECT  139.095 189.47 168.575 189.87 ;
     RECT  165.5 70.27 168.695 70.67 ;
     RECT  161.495 95.07 168.855 95.47 ;
     RECT  168.175 27.87 169.095 28.27 ;
     RECT  162.015 43.87 169.095 44.27 ;
     RECT  168.295 68.67 169.095 69.07 ;
     RECT  168.695 69.47 169.095 70.67 ;
     RECT  168.455 137.47 169.095 137.87 ;
     RECT  167.895 156.67 169.095 157.07 ;
     RECT  168.695 163.07 169.135 163.47 ;
     RECT  157.815 28.67 169.495 29.07 ;
     RECT  158.695 64.67 169.495 65.07 ;
     RECT  157.535 133.47 169.495 133.87 ;
     RECT  145.775 12.67 169.895 13.07 ;
     RECT  169.495 27.87 169.895 29.07 ;
     RECT  169.295 29.47 169.895 29.87 ;
     RECT  169.495 64.67 169.895 65.87 ;
     RECT  169.295 66.27 169.895 66.67 ;
     RECT  168.175 71.87 169.895 72.27 ;
     RECT  169.015 100.67 169.895 101.07 ;
     RECT  169.495 133.47 169.895 134.67 ;
     RECT  169.495 47.87 170.255 48.27 ;
     RECT  169.495 70.27 170.255 70.67 ;
     RECT  142.695 123.87 170.535 124.27 ;
     RECT  169.495 159.07 170.535 159.47 ;
     RECT  169.295 71.07 170.695 71.47 ;
     RECT  170.135 126.27 170.695 126.67 ;
     RECT  170.135 149.47 170.695 149.87 ;
     RECT  167.615 167.87 170.695 168.27 ;
     RECT  159.095 113.47 170.815 113.87 ;
     RECT  165.5 158.27 170.975 158.67 ;
     RECT  152.495 26.27 171.095 26.67 ;
     RECT  166.775 67.87 171.095 68.27 ;
     RECT  170.295 28.67 171.375 29.07 ;
     RECT  157.095 38.27 171.375 38.67 ;
     RECT  147.175 39.87 171.375 40.27 ;
     RECT  167.095 144.67 171.375 145.07 ;
     RECT  170.975 158.27 171.375 159.47 ;
     RECT  146.895 5.47 171.495 5.87 ;
     RECT  171.095 67.87 171.495 69.07 ;
     RECT  170.975 87.07 171.495 87.47 ;
     RECT  143.535 146.27 171.495 146.67 ;
     RECT  168.175 155.07 171.495 155.47 ;
     RECT  139.335 10.27 171.655 10.67 ;
     RECT  159.215 24.67 171.655 25.07 ;
     RECT  171.095 66.27 171.655 66.67 ;
     RECT  119.455 101.47 171.655 101.87 ;
     RECT  169.895 27.87 171.895 28.27 ;
     RECT  171.095 71.87 171.935 72.27 ;
     RECT  151.895 21.47 172.215 21.87 ;
     RECT  171.895 27.87 172.295 29.07 ;
     RECT  171.815 77.47 172.295 77.87 ;
     RECT  171.815 117.47 172.295 117.87 ;
     RECT  148.295 93.47 172.495 93.87 ;
     RECT  170.295 147.87 172.495 148.27 ;
     RECT  171.895 154.27 172.495 154.67 ;
     RECT  160.055 118.27 172.695 118.67 ;
     RECT  153.895 34.27 172.775 34.67 ;
     RECT  172.655 14.27 173.095 14.67 ;
     RECT  172.655 38.27 173.095 38.67 ;
     RECT  172.655 67.87 173.095 68.27 ;
     RECT  172.695 117.47 173.095 118.67 ;
     RECT  167.615 139.07 173.095 139.47 ;
     RECT  171.095 40.67 173.335 41.07 ;
     RECT  154.175 88.67 173.335 89.07 ;
     RECT  172.695 97.47 173.335 97.87 ;
     RECT  172.695 152.67 173.335 153.07 ;
     RECT  171.495 68.67 173.495 69.07 ;
     RECT  173.495 62.27 173.895 62.67 ;
     RECT  171.095 63.07 173.895 63.47 ;
     RECT  173.495 67.87 173.895 69.07 ;
     RECT  173.495 118.27 173.895 118.67 ;
     RECT  173.495 154.27 173.895 154.67 ;
     RECT  172.655 167.87 173.895 168.27 ;
     RECT  169.895 65.47 174.175 65.87 ;
     RECT  165.5 55.87 174.455 56.27 ;
     RECT  166.695 110.27 174.695 110.67 ;
     RECT  173.775 147.87 174.695 148.27 ;
     RECT  174.295 140.67 175.015 141.07 ;
     RECT  171.255 64.67 175.095 65.07 ;
     RECT  173.495 26.27 175.295 26.67 ;
     RECT  174.295 33.47 175.295 33.87 ;
     RECT  174.295 79.87 175.295 80.27 ;
     RECT  153.615 142.27 175.295 142.67 ;
     RECT  169.495 148.67 175.295 149.07 ;
     RECT  172.695 171.07 175.295 171.47 ;
     RECT  174.895 34.27 175.495 34.67 ;
     RECT  174.895 51.07 175.495 51.47 ;
     RECT  175.095 64.67 175.495 65.87 ;
     RECT  174.615 102.27 175.495 102.67 ;
     RECT  174.335 143.87 175.495 144.27 ;
     RECT  173.775 158.27 175.495 158.67 ;
     RECT  174.615 168.67 175.495 169.07 ;
     RECT  175.095 139.87 175.575 140.27 ;
     RECT  175.095 92.67 175.855 93.07 ;
     RECT  172.935 143.07 175.895 143.47 ;
     RECT  175.455 42.27 176.295 42.67 ;
     RECT  175.175 123.07 176.295 123.47 ;
     RECT  175.895 142.27 176.295 143.47 ;
     RECT  175.895 97.47 176.415 97.87 ;
     RECT  165.5 163.87 176.5 164.27 ;
     RECT  165.655 96.67 176.695 97.07 ;
     RECT  156.695 108.67 176.695 109.07 ;
     RECT  173.095 117.47 176.695 117.87 ;
     RECT  174.295 162.27 176.695 162.67 ;
     RECT  176.5 163.07 176.9 164.27 ;
     RECT  138.775 18.27 176.975 18.67 ;
     RECT  160.335 25.47 176.975 25.87 ;
     RECT  175.495 65.47 176.975 65.87 ;
     RECT  145.215 84.67 176.975 85.07 ;
     RECT  151.495 86.27 176.975 86.67 ;
     RECT  168.735 72.67 177.095 73.07 ;
     RECT  153.615 116.67 177.535 117.07 ;
     RECT  141.295 52.67 177.815 53.07 ;
     RECT  173.495 47.87 177.895 48.27 ;
     RECT  176.575 103.87 177.895 104.27 ;
     RECT  177.415 143.07 177.895 143.47 ;
     RECT  176.295 142.27 178.295 142.67 ;
     RECT  165.5 138.27 178.375 138.67 ;
     RECT  177.695 34.27 178.695 34.67 ;
     RECT  175.735 63.07 178.695 63.47 ;
     RECT  178.295 142.27 178.695 143.47 ;
     RECT  177.415 161.47 178.695 161.87 ;
     RECT  155.495 79.07 178.935 79.47 ;
     RECT  158.655 111.87 178.935 112.27 ;
     RECT  176.695 144.67 178.935 145.07 ;
     RECT  164.535 145.47 178.935 145.87 ;
     RECT  140.175 9.47 179.215 9.87 ;
     RECT  166.215 131.07 179.35 131.47 ;
     RECT  162.015 153.47 179.35 153.87 ;
     RECT  178.535 35.87 179.495 36.27 ;
     RECT  174.295 43.07 179.495 43.47 ;
     RECT  178.815 51.07 179.495 51.47 ;
     RECT  179.095 64.67 179.495 65.87 ;
     RECT  178.695 143.07 179.495 143.47 ;
     RECT  179.095 167.87 179.495 168.27 ;
     RECT  144.695 185.47 179.495 185.87 ;
     RECT  179.35 131.07 179.75 132.27 ;
     RECT  179.35 152.67 179.75 153.87 ;
     RECT  172.295 28.67 179.775 29.07 ;
     RECT  146.615 41.47 179.775 41.87 ;
     RECT  178.295 42.27 179.775 42.67 ;
     RECT  168.175 99.07 179.775 99.47 ;
     RECT  179.095 110.27 179.775 110.67 ;
     RECT  178.295 139.87 179.775 140.27 ;
     RECT  173.495 146.27 179.775 146.67 ;
     RECT  177.495 154.27 179.775 154.67 ;
     RECT  173.775 43.87 180.295 44.27 ;
     RECT  179.375 95.07 180.295 95.47 ;
     RECT  176.015 133.47 180.295 133.87 ;
     RECT  179.895 74.27 180.335 74.67 ;
     RECT  179.895 108.67 180.615 109.07 ;
     RECT  165.5 111.07 180.615 111.47 ;
     RECT  179.895 111.87 180.615 112.27 ;
     RECT  177.495 70.27 181.175 70.67 ;
     RECT  179.095 88.67 181.175 89.07 ;
     RECT  180.695 89.47 181.175 89.87 ;
     RECT  163.975 95.87 181.175 96.27 ;
     RECT  166.695 37.47 181.495 37.87 ;
     RECT  181.495 36.67 181.895 37.87 ;
     RECT  181.055 68.67 181.895 69.07 ;
     RECT  165.375 174.27 181.895 174.67 ;
     RECT  181.495 41.47 182.015 41.87 ;
     RECT  165.375 125.47 182.295 125.87 ;
     RECT  156.695 20.67 182.575 21.07 ;
     RECT  161.095 57.47 182.575 57.87 ;
     RECT  176.695 83.07 182.575 83.47 ;
     RECT  182.295 102.27 182.695 103.47 ;
     RECT  180.775 103.87 182.695 104.27 ;
     RECT  182.295 66.27 182.855 66.67 ;
     RECT  182.295 77.47 182.855 77.87 ;
     RECT  182.695 103.07 182.855 103.47 ;
     RECT  164.695 141.47 182.855 141.87 ;
     RECT  182.295 153.47 182.855 153.87 ;
     RECT  170.135 169.47 183.135 169.87 ;
     RECT  166.495 63.87 183.415 64.27 ;
     RECT  167.055 99.87 183.415 100.27 ;
     RECT  182.735 13.47 183.495 13.87 ;
     RECT  183.015 26.27 183.495 26.67 ;
     RECT  182.175 95.07 183.495 95.47 ;
     RECT  178.255 162.27 183.495 162.67 ;
     RECT  155.015 27.07 183.695 27.47 ;
     RECT  167.895 130.27 183.695 130.67 ;
     RECT  183.095 64.67 183.895 65.07 ;
     RECT  183.095 132.67 183.975 133.07 ;
     RECT  175.175 156.67 183.975 157.07 ;
     RECT  183.895 63.87 184.295 65.07 ;
     RECT  183.855 79.87 184.295 80.27 ;
     RECT  182.455 145.47 184.295 145.87 ;
     RECT  183.895 39.07 184.535 39.47 ;
     RECT  179.75 131.87 184.535 132.27 ;
     RECT  183.095 147.87 184.535 148.27 ;
     RECT  133.735 48.67 184.815 49.07 ;
     RECT  184.295 63.87 184.815 64.27 ;
     RECT  183.895 133.47 184.815 133.87 ;
     RECT  163.495 50.27 185.05 50.67 ;
     RECT  173.495 56.67 185.05 57.07 ;
     RECT  179.75 152.67 185.05 153.07 ;
     RECT  180.495 170.27 185.05 170.67 ;
     RECT  184.695 34.27 185.095 34.67 ;
     RECT  184.695 54.27 185.095 54.67 ;
     RECT  173.495 113.47 185.095 113.87 ;
     RECT  176.575 143.87 185.095 144.27 ;
     RECT  166.215 78.27 185.375 78.67 ;
     RECT  184.695 103.87 185.375 104.27 ;
     RECT  171.375 159.07 185.375 159.47 ;
     RECT  185.05 49.47 185.45 50.67 ;
     RECT  185.05 55.87 185.45 57.07 ;
     RECT  185.05 152.67 185.45 153.87 ;
     RECT  185.05 169.47 185.45 170.67 ;
     RECT  182.455 68.67 185.655 69.07 ;
     RECT  165.5 83.87 185.655 84.27 ;
     RECT  178.255 126.27 185.655 126.67 ;
     RECT  185.255 7.87 185.895 8.27 ;
     RECT  184.695 43.07 185.895 43.47 ;
     RECT  179.495 65.47 185.895 65.87 ;
     RECT  185.255 144.67 185.895 145.07 ;
     RECT  158.935 73.47 185.935 73.87 ;
     RECT  185.495 74.27 185.935 74.67 ;
     RECT  171.095 100.67 185.935 101.07 ;
     RECT  182.295 140.67 185.935 141.07 ;
     RECT  163.135 35.07 186.215 35.47 ;
     RECT  158.375 147.07 186.215 147.47 ;
     RECT  168.175 171.87 186.495 172.27 ;
     RECT  186.095 71.07 186.695 71.47 ;
     RECT  186.095 117.47 186.695 117.87 ;
     RECT  165.095 176.67 186.695 177.07 ;
     RECT  186.295 47.87 186.775 48.27 ;
     RECT  181.895 111.07 186.775 111.47 ;
     RECT  185.495 123.07 186.775 123.47 ;
     RECT  186.295 141.47 187.055 141.87 ;
     RECT  180.775 92.67 187.335 93.07 ;
     RECT  177.135 27.87 187.495 28.27 ;
     RECT  186.935 97.47 187.495 97.87 ;
     RECT  184.135 139.87 187.495 140.27 ;
     RECT  186.655 144.67 187.495 145.07 ;
     RECT  186.935 171.07 187.495 171.47 ;
     RECT  187.095 54.27 187.615 54.67 ;
     RECT  178.295 18.27 187.895 18.67 ;
     RECT  173.775 109.47 187.895 109.87 ;
     RECT  187.095 124.67 187.895 125.07 ;
     RECT  185.45 49.47 188.175 49.87 ;
     RECT  183.015 71.87 188.175 72.27 ;
     RECT  187.775 24.67 188.295 25.07 ;
     RECT  181.495 43.87 188.295 44.27 ;
     RECT  187.215 48.67 188.295 49.07 ;
     RECT  187.215 53.47 188.295 53.87 ;
     RECT  187.775 63.87 188.295 64.27 ;
     RECT  187.215 73.47 188.295 73.87 ;
     RECT  187.775 92.67 188.295 93.07 ;
     RECT  187.495 125.47 188.295 125.87 ;
     RECT  187.215 149.47 188.295 149.87 ;
     RECT  173.895 67.87 188.455 68.27 ;
     RECT  182.735 131.07 188.455 131.47 ;
     RECT  139.055 183.07 188.455 183.47 ;
     RECT  168.735 19.07 188.695 19.47 ;
     RECT  181.895 36.67 188.735 37.07 ;
     RECT  159.495 67.07 188.735 67.47 ;
     RECT  188.055 11.07 189.095 11.47 ;
     RECT  188.695 18.27 189.095 19.47 ;
     RECT  188.055 23.87 189.095 24.27 ;
     RECT  169.095 69.47 189.095 69.87 ;
     RECT  188.615 88.67 189.095 89.07 ;
     RECT  188.335 133.47 189.095 133.87 ;
     RECT  188.695 147.07 189.295 147.47 ;
     RECT  168.455 173.47 189.295 173.87 ;
     RECT  188.695 42.27 189.575 42.67 ;
     RECT  174.055 159.87 189.575 160.27 ;
     RECT  157.815 80.67 189.855 81.07 ;
     RECT  189.175 27.87 189.895 28.27 ;
     RECT  189.455 117.47 189.895 117.87 ;
     RECT  189.175 144.67 189.895 145.07 ;
     RECT  166.215 178.27 189.895 178.67 ;
     RECT  189.495 67.87 190.135 68.27 ;
     RECT  176.855 118.27 190.295 118.67 ;
     RECT  174.055 139.07 190.415 139.47 ;
     RECT  189.495 147.87 190.415 148.27 ;
     RECT  190.295 13.47 190.695 13.87 ;
     RECT  190.295 117.47 190.695 118.67 ;
     RECT  186.295 162.27 190.695 162.67 ;
     RECT  178.815 116.67 190.975 117.07 ;
     RECT  188.335 139.87 191.095 140.27 ;
     RECT  174.055 107.87 191.255 108.27 ;
     RECT  178.815 138.27 191.255 138.67 ;
     RECT  182.175 155.87 191.255 156.27 ;
     RECT  189.735 23.87 191.495 24.27 ;
     RECT  190.015 52.67 191.495 53.07 ;
     RECT  191.095 139.07 191.495 140.27 ;
     RECT  190.295 144.67 191.495 145.07 ;
     RECT  160.055 160.67 191.495 161.07 ;
     RECT  159.215 32.67 191.535 33.07 ;
     RECT  155.895 51.87 191.535 52.27 ;
     RECT  191.095 83.07 191.535 83.47 ;
     RECT  191.095 94.27 191.535 94.67 ;
     RECT  191.095 118.27 191.535 118.67 ;
     RECT  190.295 33.47 191.815 33.87 ;
     RECT  165.935 81.47 191.895 81.87 ;
     RECT  191.095 66.27 192.095 66.67 ;
     RECT  172.375 127.87 192.095 128.27 ;
     RECT  178.535 163.87 192.095 164.27 ;
     RECT  182.175 51.07 192.295 51.47 ;
     RECT  191.895 80.67 192.295 81.87 ;
     RECT  165.5 127.07 192.295 127.47 ;
     RECT  191.895 107.87 192.375 108.27 ;
     RECT  191.895 138.27 192.375 138.67 ;
     RECT  185.45 169.47 192.375 169.87 ;
     RECT  191.895 109.47 192.655 109.87 ;
     RECT  191.895 129.47 192.655 129.87 ;
     RECT  190.295 130.27 192.695 130.67 ;
     RECT  184.695 64.67 192.935 65.07 ;
     RECT  163.415 85.47 192.935 85.87 ;
     RECT  178.815 93.47 192.935 93.87 ;
     RECT  167.895 177.47 192.935 177.87 ;
     RECT  191.695 56.67 193.095 57.07 ;
     RECT  192.535 88.67 193.095 89.07 ;
     RECT  190.855 111.87 193.095 112.27 ;
     RECT  192.695 130.27 193.095 131.47 ;
     RECT  192.535 142.27 193.095 142.67 ;
     RECT  192.815 57.47 193.495 57.87 ;
     RECT  192.695 32.67 193.775 33.07 ;
     RECT  173.775 184.67 193.775 185.07 ;
     RECT  173.775 55.07 193.895 55.47 ;
     RECT  193.495 56.67 193.895 57.87 ;
     RECT  193.375 107.87 193.895 108.27 ;
     RECT  192.815 139.87 193.895 140.27 ;
     RECT  193.375 159.87 193.895 160.27 ;
     RECT  175.455 39.87 194.335 40.27 ;
     RECT  169.015 115.07 194.335 115.47 ;
     RECT  193.495 129.47 194.335 129.87 ;
     RECT  167.335 157.47 194.335 157.87 ;
     RECT  185.45 153.47 194.615 153.87 ;
     RECT  176.9 163.07 194.615 163.47 ;
     RECT  193.935 12.67 194.695 13.07 ;
     RECT  192.815 42.27 194.695 42.67 ;
     RECT  193.375 64.67 194.695 65.07 ;
     RECT  194.215 103.87 194.695 104.27 ;
     RECT  187.775 146.27 194.695 146.67 ;
     RECT  194.295 79.87 194.895 80.27 ;
     RECT  194.295 123.07 194.895 123.47 ;
     RECT  173.495 23.07 195.455 23.47 ;
     RECT  192.295 80.67 195.455 81.07 ;
     RECT  156.415 6.27 195.495 6.67 ;
     RECT  194.495 49.47 195.495 49.87 ;
     RECT  193.655 69.47 195.495 69.87 ;
     RECT  195.055 74.27 195.495 74.67 ;
     RECT  194.775 127.87 195.495 128.27 ;
     RECT  195.095 39.87 195.735 40.27 ;
     RECT  185.815 143.87 195.735 144.27 ;
     RECT  195.095 152.67 195.735 153.07 ;
     RECT  156.135 7.07 196.295 7.47 ;
     RECT  191.415 53.47 196.295 53.87 ;
     RECT  194.215 78.27 196.295 78.67 ;
     RECT  185.255 102.27 196.295 102.67 ;
     RECT  195.615 103.87 196.295 104.27 ;
     RECT  195.895 129.47 196.295 129.87 ;
     RECT  181.055 143.07 196.295 143.47 ;
     RECT  195.895 156.67 196.295 157.07 ;
     RECT  187.895 161.47 196.295 161.87 ;
     RECT  195.895 169.47 196.295 169.87 ;
     RECT  195.895 47.87 196.575 48.27 ;
     RECT  180.215 99.07 196.575 99.47 ;
     RECT  167.335 115.87 196.575 116.27 ;
     RECT  190.855 19.07 196.855 19.47 ;
     RECT  195.095 22.27 196.855 22.67 ;
     RECT  194.295 92.67 196.855 93.07 ;
     RECT  196.455 38.27 197.095 38.67 ;
     RECT  193.895 56.67 197.095 57.07 ;
     RECT  196.175 119.07 197.095 119.47 ;
     RECT  195.055 170.27 197.095 170.67 ;
     RECT  185.255 108.67 197.135 109.07 ;
     RECT  185.255 110.27 197.135 110.67 ;
     RECT  155.575 11.87 197.415 12.27 ;
     RECT  193.495 51.07 197.415 51.47 ;
     RECT  196.695 93.47 197.415 93.87 ;
     RECT  185.255 79.07 197.695 79.47 ;
     RECT  185.255 158.27 197.695 158.67 ;
     RECT  196.735 73.47 197.895 73.87 ;
     RECT  194.495 126.27 197.895 126.67 ;
     RECT  197.015 167.87 197.895 168.27 ;
     RECT  187.215 111.07 198.535 111.47 ;
     RECT  197.495 57.47 198.815 57.87 ;
     RECT  191.895 162.27 198.815 162.67 ;
     RECT  179.375 40.67 199.935 41.07 ;
     RECT  192.815 81.47 199.935 81.87 ;
     RECT  182.735 95.87 199.935 96.27 ;
     RECT  186.375 113.47 199.935 113.87 ;
     RECT  190.695 117.47 199.935 117.87 ;
     RECT  188.695 141.47 199.935 141.87 ;
     RECT  185.45 55.87 200.215 56.27 ;
     RECT  199.535 7.87 200.295 8.27 ;
     RECT  187.495 68.67 200.295 69.07 ;
     RECT  159.895 58.27 200.495 58.67 ;
     RECT  185.255 70.27 200.775 70.67 ;
     RECT  199.895 72.67 201.055 73.07 ;
     RECT  181.895 128.67 201.055 129.07 ;
     RECT  200.375 124.67 201.095 125.07 ;
     RECT  200.655 159.87 201.095 160.27 ;
     RECT  184.695 123.87 201.335 124.27 ;
     RECT  201.495 85.47 201.895 85.87 ;
     RECT  201.495 115.87 201.895 116.27 ;
     RECT  201.495 152.67 201.895 153.07 ;
     RECT  194.215 67.87 202.695 68.27 ;
     RECT  191.975 118.27 202.695 118.67 ;
     RECT  202.295 176.67 202.735 177.07 ;
     RECT  202.295 39.87 203.015 40.27 ;
     RECT  196.175 66.27 203.495 66.67 ;
     RECT  183.295 148.67 203.495 149.07 ;
     RECT  177.135 101.47 203.575 101.87 ;
     RECT  193.655 63.07 204.135 63.47 ;
     RECT  202.335 38.27 204.295 38.67 ;
     RECT  203.895 92.67 204.415 93.07 ;
     RECT  183.575 112.67 204.975 113.07 ;
     RECT  189.095 18.27 205 18.67 ;
     RECT  190.855 100.67 205 101.07 ;
     RECT  191.495 139.07 205 139.47 ;
     RECT  190.015 140.67 205 141.07 ;
     RECT  183.015 37.47 205.255 37.87 ;
     RECT  204.695 175.87 205.255 176.27 ;
     RECT  205 18.27 205.4 19.47 ;
     RECT  205 100.67 205.4 102.67 ;
     RECT  205 138.27 205.4 139.47 ;
     RECT  205 140.67 205.4 142.67 ;
     RECT  192.815 127.07 205.815 127.47 ;
     RECT  167.095 188.67 205.815 189.07 ;
     RECT  205.4 19.07 205.895 19.47 ;
     RECT  205.415 92.67 205.895 93.07 ;
     RECT  199.255 115.07 205.895 115.47 ;
     RECT  14.06 15.3 205.96 16.7 ;
     RECT  14.06 30.3 205.96 31.7 ;
     RECT  14.06 45.3 205.96 46.7 ;
     RECT  14.06 60.3 205.96 61.7 ;
     RECT  14.06 75.3 205.96 76.7 ;
     RECT  14.06 90.3 205.96 91.7 ;
     RECT  14.06 105.3 205.96 106.7 ;
     RECT  14.06 120.3 205.96 121.7 ;
     RECT  14.06 135.3 205.96 136.7 ;
     RECT  14.06 150.3 205.96 151.7 ;
     RECT  14.06 165.3 205.96 166.7 ;
     RECT  14.06 180.3 205.96 181.7 ;
     RECT  14.06 195.3 205.96 196.7 ;
     RECT  195.095 163.87 206.375 164.27 ;
     RECT  205.135 12.67 206.695 13.07 ;
     RECT  191.095 50.27 206.695 50.67 ;
     RECT  202.055 93.47 206.695 93.87 ;
     RECT  205.695 143.87 206.695 144.27 ;
     RECT  195.335 97.47 207.215 97.87 ;
     RECT  206.255 78.27 207.495 78.67 ;
     RECT  207.095 179.87 207.495 180.27 ;
     RECT  190.295 103.07 208.055 103.47 ;
     RECT  193.095 131.07 208.055 131.47 ;
     RECT  205.4 138.27 208.295 138.67 ;
     RECT  203.455 145.47 208.295 145.87 ;
     RECT  191.135 87.07 208.335 87.47 ;
     RECT  185.255 132.67 208.335 133.07 ;
     RECT  207.895 63.87 208.615 64.27 ;
     RECT  188.895 24.67 208.895 25.07 ;
     RECT  193.935 88.67 208.895 89.07 ;
     RECT  184.695 95.07 208.895 95.47 ;
     RECT  194.215 130.27 209.095 130.67 ;
     RECT  205.4 142.27 209.175 142.67 ;
     RECT  113.295 3.87 210.295 4.27 ;
     RECT  205.4 102.27 211.135 102.67 ;
    LAYER metal8 ;
     RECT  202.295 4.67 202.695 5.5 ;
     RECT  202.295 5.5 203.495 5.9 ;
     RECT  188.695 11.07 189.095 11.47 ;
     RECT  194.295 12.67 194.695 13.07 ;
     RECT  206.295 12.67 206.695 13.07 ;
     RECT  154.295 17.47 154.695 17.87 ;
     RECT  138.295 22.27 138.695 24.27 ;
     RECT  157.495 23.87 157.895 24.27 ;
     RECT  164.695 23.87 165.095 24.27 ;
     RECT  188.695 23.87 189.095 24.27 ;
     RECT  191.095 12.67 191.495 24.27 ;
     RECT  55.895 25.47 56.295 25.87 ;
     RECT  59.095 25.47 59.495 25.87 ;
     RECT  183.095 13.47 183.495 26.67 ;
     RECT  151.095 24.67 151.495 27.87 ;
     RECT  150.295 27.87 151.495 28.27 ;
     RECT  159.895 25.47 160.295 28.27 ;
     RECT  151.095 28.67 151.495 29.07 ;
     RECT  170.295 28.67 170.695 29.07 ;
     RECT  159.095 13.47 159.495 29.87 ;
     RECT  150.295 28.27 150.695 30.27 ;
     RECT  150.295 30.27 151.495 30.67 ;
     RECT  144.695 31.87 145.095 33.07 ;
     RECT  157.495 31.87 157.895 33.07 ;
     RECT  192.695 19.07 193.095 33.07 ;
     RECT  55.895 33.47 56.295 33.87 ;
     RECT  159.895 31.87 160.295 33.87 ;
     RECT  164.695 33.47 165.095 33.87 ;
     RECT  190.295 13.47 190.695 33.87 ;
     RECT  135.095 11.07 135.495 34.67 ;
     RECT  175.095 11.07 175.495 34.67 ;
     RECT  178.295 18.27 178.695 34.67 ;
     RECT  184.695 31.87 185.095 34.67 ;
     RECT  59.095 35.07 59.495 35.47 ;
     RECT  159.895 35.07 160.295 35.47 ;
     RECT  133.495 36.67 133.895 37.07 ;
     RECT  155.895 36.67 156.295 37.07 ;
     RECT  139.095 33.47 139.495 37.87 ;
     RECT  23.095 38.27 23.495 38.67 ;
     RECT  155.095 14.27 155.495 38.67 ;
     RECT  163.095 36.67 163.495 38.67 ;
     RECT  172.695 14.27 173.095 38.67 ;
     RECT  196.695 38.27 197.095 38.67 ;
     RECT  158.295 22.27 158.695 39.47 ;
     RECT  68.695 39.07 69.095 40.27 ;
     RECT  195.095 6.27 195.495 40.27 ;
     RECT  164.695 39.87 165.095 41.07 ;
     RECT  171.095 5.47 171.495 41.07 ;
     RECT  55.895 41.47 56.295 41.87 ;
     RECT  181.495 41.47 181.895 41.87 ;
     RECT  175.895 38.27 176.295 42.67 ;
     RECT  174.295 33.47 174.695 43.47 ;
     RECT  185.495 7.87 185.895 43.47 ;
     RECT  188.695 42.27 189.095 43.47 ;
     RECT  137.495 32.67 137.895 44.27 ;
     RECT  143.095 25.47 143.495 44.27 ;
     RECT  168.695 27.87 169.095 44.27 ;
     RECT  187.895 24.67 188.295 44.27 ;
     RECT  138.295 35.07 138.695 44.67 ;
     RECT  59.095 43.87 59.495 45.07 ;
     RECT  137.495 44.67 138.695 45.07 ;
     RECT  90.295 38.27 90.695 45.4 ;
     RECT  114.295 36.67 114.695 45.4 ;
     RECT  123.095 24.67 123.495 45.4 ;
     RECT  142.295 29.47 142.695 45.4 ;
     RECT  153.495 33.47 153.895 45.4 ;
     RECT  161.495 27.87 161.895 45.4 ;
     RECT  163.895 29.47 164.295 45.4 ;
     RECT  169.495 12.67 169.895 45.4 ;
     RECT  89.495 45.4 90.695 45.8 ;
     RECT  114.295 45.4 115.495 45.8 ;
     RECT  123.095 45.4 124.295 45.8 ;
     RECT  142.295 45.4 143.495 45.8 ;
     RECT  152.695 45.4 153.895 45.8 ;
     RECT  161.495 45.4 162.695 45.8 ;
     RECT  163.095 45.4 164.295 45.8 ;
     RECT  168.695 45.4 169.895 45.8 ;
     RECT  160.695 22.27 161.095 46.27 ;
     RECT  173.495 26.27 173.895 46.27 ;
     RECT  151.095 30.67 151.495 46.67 ;
     RECT  159.895 43.87 160.295 46.67 ;
     RECT  160.695 46.27 161.895 46.67 ;
     RECT  173.495 46.27 176.295 46.67 ;
     RECT  203.095 5.9 203.495 46.67 ;
     RECT  57.495 46.27 57.895 48.27 ;
     RECT  133.495 47.87 133.895 48.27 ;
     RECT  143.095 45.8 143.495 48.27 ;
     RECT  150.295 43.07 150.695 48.27 ;
     RECT  162.295 45.8 162.695 48.27 ;
     RECT  163.895 46.27 164.295 48.27 ;
     RECT  195.895 7.07 196.295 48.27 ;
     RECT  122.295 17.47 122.695 49.07 ;
     RECT  132.695 4.67 133.095 49.07 ;
     RECT  187.895 46.27 188.295 49.07 ;
     RECT  134.295 49.47 134.695 49.87 ;
     RECT  195.095 47.87 195.495 49.87 ;
     RECT  37.495 51.07 37.895 51.47 ;
     RECT  135.895 18.27 136.295 51.47 ;
     RECT  150.295 51.07 150.695 51.47 ;
     RECT  179.095 35.87 179.495 51.47 ;
     RECT  191.095 50.27 191.495 51.47 ;
     RECT  126.295 37.47 126.695 52.27 ;
     RECT  151.895 21.47 152.295 52.27 ;
     RECT  66.295 52.67 66.695 53.07 ;
     RECT  128.695 13.47 129.095 53.87 ;
     RECT  63.895 54.27 64.295 54.67 ;
     RECT  95.095 54.27 95.495 54.67 ;
     RECT  103.895 54.27 104.295 54.67 ;
     RECT  111.895 54.27 112.295 54.67 ;
     RECT  119.895 54.27 120.295 54.67 ;
     RECT  143.095 53.47 143.495 54.67 ;
     RECT  184.695 41.47 185.095 54.67 ;
     RECT  187.095 27.87 187.495 54.67 ;
     RECT  135.095 38.27 135.495 55.07 ;
     RECT  55.895 54.27 56.295 55.47 ;
     RECT  79.895 54.27 80.295 55.47 ;
     RECT  87.895 54.27 88.295 55.47 ;
     RECT  124.695 54.27 125.095 55.47 ;
     RECT  134.295 55.07 135.495 55.47 ;
     RECT  193.495 51.07 193.895 55.47 ;
     RECT  31.895 54.27 32.295 56.27 ;
     RECT  39.895 54.27 40.295 56.27 ;
     RECT  47.095 54.27 47.495 56.27 ;
     RECT  71.895 54.27 72.295 56.27 ;
     RECT  137.495 45.07 137.895 56.27 ;
     RECT  162.295 55.87 162.695 56.27 ;
     RECT  186.295 47.87 186.695 56.27 ;
     RECT  23.895 54.27 24.295 57.07 ;
     RECT  91.095 55.87 91.495 57.07 ;
     RECT  135.895 54.27 136.295 57.07 ;
     RECT  167.095 23.87 167.495 57.07 ;
     RECT  166.295 55.07 166.695 57.47 ;
     RECT  59.095 57.47 59.495 57.87 ;
     RECT  131.095 57.47 131.495 57.87 ;
     RECT  146.295 57.47 146.695 57.87 ;
     RECT  156.695 19.07 157.095 57.87 ;
     RECT  166.295 57.47 167.495 57.87 ;
     RECT  187.895 53.47 188.295 57.87 ;
     RECT  59.095 59.07 59.495 59.47 ;
     RECT  75.095 57.47 75.495 59.47 ;
     RECT  90.295 57.47 90.695 59.47 ;
     RECT  136.695 57.47 137.095 59.47 ;
     RECT  144.695 58.27 145.095 59.47 ;
     RECT  161.495 46.67 161.895 59.47 ;
     RECT  166.295 59.07 166.695 59.47 ;
     RECT  89.495 45.8 89.895 60.67 ;
     RECT  81.495 52.67 81.895 61.07 ;
     RECT  89.495 60.67 90.695 61.07 ;
     RECT  27.895 62.27 28.295 62.67 ;
     RECT  36.695 62.27 37.095 62.67 ;
     RECT  43.095 62.27 43.495 62.67 ;
     RECT  51.895 62.27 52.295 62.67 ;
     RECT  59.895 62.27 60.295 62.67 ;
     RECT  66.295 62.27 66.695 62.67 ;
     RECT  67.895 62.27 68.295 62.67 ;
     RECT  89.495 62.27 89.895 62.67 ;
     RECT  92.695 62.27 93.095 62.67 ;
     RECT  99.095 62.27 99.495 62.67 ;
     RECT  107.095 62.27 107.495 62.67 ;
     RECT  114.295 62.27 114.695 62.67 ;
     RECT  122.295 62.27 122.695 62.67 ;
     RECT  123.895 45.8 124.295 62.67 ;
     RECT  145.495 23.07 145.895 62.67 ;
     RECT  148.695 47.87 149.095 62.67 ;
     RECT  155.895 51.87 156.295 62.67 ;
     RECT  173.495 62.27 173.895 62.67 ;
     RECT  53.495 35.87 53.895 63.47 ;
     RECT  139.095 41.47 139.495 63.47 ;
     RECT  143.895 51.07 144.295 63.47 ;
     RECT  163.095 45.8 163.495 63.47 ;
     RECT  178.295 42.27 178.695 63.47 ;
     RECT  68.695 55.87 69.095 64.27 ;
     RECT  79.095 63.87 79.495 64.27 ;
     RECT  84.695 62.27 85.095 64.27 ;
     RECT  118.295 35.07 118.695 64.27 ;
     RECT  132.695 63.07 133.095 64.27 ;
     RECT  145.495 63.87 145.895 64.27 ;
     RECT  164.695 42.27 165.095 64.27 ;
     RECT  171.095 63.07 171.495 64.27 ;
     RECT  187.895 63.87 188.295 64.27 ;
     RECT  207.895 63.87 208.295 64.27 ;
     RECT  194.295 42.27 194.695 65.07 ;
     RECT  47.895 28.67 48.295 65.35 ;
     RECT  58.295 55.87 58.695 65.35 ;
     RECT  130.295 52.67 130.695 65.35 ;
     RECT  31.895 60.67 32.295 65.47 ;
     RECT  47.095 65.35 48.295 65.75 ;
     RECT  58.295 65.35 59.495 65.75 ;
     RECT  130.295 65.35 133.095 65.75 ;
     RECT  31.095 65.47 32.295 65.87 ;
     RECT  104.695 52.67 105.095 65.87 ;
     RECT  113.495 37.47 113.895 65.87 ;
     RECT  115.895 40.67 116.295 65.87 ;
     RECT  57.495 59.07 57.895 66.67 ;
     RECT  67.895 65.47 68.295 66.67 ;
     RECT  89.495 65.47 89.895 66.67 ;
     RECT  169.495 47.87 169.895 66.67 ;
     RECT  182.295 65.47 182.695 66.67 ;
     RECT  191.095 52.67 191.495 66.67 ;
     RECT  67.095 58.27 67.495 67.07 ;
     RECT  168.695 45.8 169.095 67.07 ;
     RECT  191.895 51.07 192.295 67.07 ;
     RECT  37.495 59.07 37.895 67.47 ;
     RECT  63.095 65.47 63.495 67.47 ;
     RECT  67.095 67.07 68.295 67.47 ;
     RECT  158.295 52.67 158.695 67.47 ;
     RECT  168.695 67.07 170.695 67.47 ;
     RECT  171.095 66.27 171.495 67.47 ;
     RECT  191.095 67.07 192.295 67.47 ;
     RECT  32.695 53.47 33.095 68.27 ;
     RECT  134.295 64.67 134.695 68.27 ;
     RECT  189.495 27.87 189.895 68.27 ;
     RECT  202.295 39.87 202.695 68.27 ;
     RECT  31.095 65.87 31.495 69.07 ;
     RECT  43.895 68.67 44.295 69.07 ;
     RECT  55.095 39.87 55.495 69.07 ;
     RECT  75.095 68.67 75.495 69.07 ;
     RECT  77.495 56.67 77.895 69.07 ;
     RECT  109.495 19.07 109.895 69.07 ;
     RECT  124.695 62.27 125.095 69.07 ;
     RECT  138.295 47.87 138.695 69.07 ;
     RECT  147.095 19.07 147.495 69.07 ;
     RECT  166.295 68.67 166.695 69.07 ;
     RECT  181.495 43.87 181.895 69.07 ;
     RECT  199.895 7.87 200.295 69.07 ;
     RECT  48.695 60.67 49.095 69.87 ;
     RECT  195.095 55.87 195.495 69.87 ;
     RECT  54.295 56.67 54.695 70.27 ;
     RECT  54.295 70.27 56.295 70.67 ;
     RECT  57.495 70.27 57.895 70.67 ;
     RECT  67.095 70.27 67.495 70.67 ;
     RECT  128.695 70.27 129.095 70.67 ;
     RECT  149.495 35.07 149.895 70.67 ;
     RECT  169.495 70.27 169.895 70.67 ;
     RECT  177.495 47.87 177.895 70.67 ;
     RECT  53.495 70.27 53.895 71.47 ;
     RECT  90.295 61.07 90.695 71.47 ;
     RECT  127.095 47.87 127.495 71.47 ;
     RECT  129.495 47.87 129.895 71.47 ;
     RECT  152.695 45.8 153.095 71.47 ;
     RECT  167.895 19.07 168.295 71.47 ;
     RECT  170.295 67.47 170.695 71.47 ;
     RECT  28.695 59.07 29.095 72.27 ;
     RECT  51.095 57.47 51.495 72.27 ;
     RECT  63.895 64.67 64.295 72.27 ;
     RECT  161.495 67.87 161.895 72.27 ;
     RECT  98.295 33.47 98.695 73.07 ;
     RECT  199.895 71.87 200.295 73.07 ;
     RECT  59.095 65.75 59.495 73.47 ;
     RECT  48.695 73.47 49.095 73.87 ;
     RECT  58.295 73.47 59.495 73.87 ;
     RECT  103.895 73.47 104.295 73.87 ;
     RECT  139.095 71.87 139.495 73.87 ;
     RECT  154.295 24.67 154.695 73.87 ;
     RECT  162.295 71.07 162.695 73.87 ;
     RECT  164.695 72.67 165.095 73.87 ;
     RECT  167.895 72.67 168.295 73.87 ;
     RECT  197.495 57.47 197.895 73.87 ;
     RECT  41.495 50.27 41.895 74.67 ;
     RECT  49.495 22.27 49.895 74.67 ;
     RECT  65.495 49.47 65.895 74.67 ;
     RECT  143.895 65.47 144.295 74.67 ;
     RECT  179.895 43.87 180.295 74.67 ;
     RECT  185.495 65.47 185.895 74.67 ;
     RECT  90.295 73.47 90.695 75.07 ;
     RECT  38.295 67.87 38.695 75.47 ;
     RECT  75.095 74.27 75.495 75.47 ;
     RECT  90.295 75.07 91.495 75.47 ;
     RECT  145.495 74.27 145.895 75.47 ;
     RECT  159.095 74.27 159.495 75.47 ;
     RECT  168.695 68.67 169.095 75.47 ;
     RECT  195.095 74.27 195.495 75.47 ;
     RECT  155.095 65.47 155.495 76.67 ;
     RECT  159.895 51.07 160.295 76.67 ;
     RECT  59.095 74.27 59.495 77.07 ;
     RECT  154.295 76.67 155.495 77.07 ;
     RECT  158.295 76.67 160.295 77.07 ;
     RECT  151.095 63.87 151.495 77.87 ;
     RECT  69.495 55.87 69.895 78.27 ;
     RECT  48.695 77.47 49.095 78.67 ;
     RECT  53.495 78.27 53.895 78.67 ;
     RECT  56.695 68.67 57.095 78.67 ;
     RECT  69.495 78.27 71.495 78.67 ;
     RECT  103.895 78.27 104.295 78.67 ;
     RECT  135.095 55.87 135.495 78.67 ;
     RECT  150.295 78.27 150.695 78.67 ;
     RECT  152.695 76.67 153.095 78.67 ;
     RECT  155.095 78.27 155.495 78.67 ;
     RECT  171.895 77.47 172.295 78.67 ;
     RECT  195.895 53.47 196.295 78.67 ;
     RECT  207.095 78.27 207.495 78.67 ;
     RECT  119.095 57.47 119.495 79.47 ;
     RECT  51.095 73.47 51.495 80.27 ;
     RECT  55.895 70.67 56.295 80.27 ;
     RECT  67.895 67.47 68.295 80.27 ;
     RECT  83.895 71.87 84.295 80.27 ;
     RECT  103.095 35.87 103.495 80.27 ;
     RECT  136.695 65.47 137.095 80.27 ;
     RECT  165.495 49.47 165.895 80.27 ;
     RECT  174.295 79.87 174.695 80.27 ;
     RECT  183.895 39.07 184.295 80.27 ;
     RECT  194.295 78.27 194.695 80.27 ;
     RECT  63.895 79.87 64.295 81.07 ;
     RECT  76.695 79.87 77.095 81.07 ;
     RECT  137.495 64.67 137.895 81.07 ;
     RECT  156.695 63.07 157.095 81.07 ;
     RECT  55.895 80.67 56.295 81.87 ;
     RECT  77.495 70.27 77.895 81.87 ;
     RECT  96.695 39.07 97.095 81.87 ;
     RECT  130.295 70.27 130.695 81.87 ;
     RECT  134.295 71.07 134.695 81.87 ;
     RECT  164.695 81.47 165.095 81.87 ;
     RECT  31.895 67.07 32.295 83.07 ;
     RECT  31.895 83.07 33.095 83.47 ;
     RECT  35.895 83.07 36.295 83.47 ;
     RECT  116.695 65.47 117.095 83.47 ;
     RECT  161.495 77.47 161.895 83.47 ;
     RECT  167.095 57.87 167.495 83.47 ;
     RECT  176.695 72.67 177.095 83.47 ;
     RECT  191.095 67.47 191.495 83.47 ;
     RECT  62.295 54.27 62.695 84.27 ;
     RECT  66.295 66.27 66.695 84.27 ;
     RECT  110.295 51.07 110.695 84.27 ;
     RECT  142.295 78.27 142.695 84.27 ;
     RECT  32.695 83.47 33.095 85.07 ;
     RECT  57.495 84.67 57.895 85.07 ;
     RECT  47.095 65.75 47.495 85.3 ;
     RECT  115.095 45.8 115.495 85.3 ;
     RECT  138.295 79.87 138.695 85.3 ;
     RECT  159.895 79.87 160.295 85.3 ;
     RECT  189.495 73.47 189.895 85.3 ;
     RECT  47.095 85.3 48.295 85.7 ;
     RECT  115.095 85.3 116.295 85.7 ;
     RECT  137.495 85.3 138.695 85.7 ;
     RECT  159.095 85.3 160.295 85.7 ;
     RECT  189.495 85.3 191.495 85.7 ;
     RECT  23.895 74.27 24.295 85.87 ;
     RECT  91.095 75.47 91.495 85.87 ;
     RECT  117.495 39.07 117.895 85.87 ;
     RECT  132.695 65.75 133.095 85.87 ;
     RECT  147.095 71.07 147.495 85.87 ;
     RECT  160.695 53.47 161.095 85.87 ;
     RECT  201.495 52.67 201.895 85.87 ;
     RECT  43.095 84.67 43.495 86.67 ;
     RECT  55.895 86.27 56.295 86.67 ;
     RECT  63.895 86.27 64.295 86.67 ;
     RECT  71.095 78.67 71.495 86.67 ;
     RECT  115.095 86.27 115.495 86.67 ;
     RECT  149.495 86.27 149.895 86.67 ;
     RECT  156.695 85.47 157.095 86.67 ;
     RECT  40.695 62.27 41.095 87.47 ;
     RECT  75.895 57.47 76.295 87.47 ;
     RECT  164.695 86.27 165.095 87.47 ;
     RECT  167.095 86.27 167.495 87.47 ;
     RECT  171.095 71.87 171.495 87.47 ;
     RECT  143.895 77.47 144.295 87.87 ;
     RECT  54.295 83.07 54.695 88.27 ;
     RECT  115.895 85.7 116.295 88.27 ;
     RECT  123.895 64.67 124.295 88.27 ;
     RECT  132.695 87.87 133.095 88.27 ;
     RECT  143.895 87.87 145.095 88.27 ;
     RECT  148.695 65.47 149.095 88.27 ;
     RECT  166.295 87.87 166.695 88.27 ;
     RECT  50.295 58.27 50.695 89.07 ;
     RECT  64.695 66.27 65.095 89.07 ;
     RECT  87.895 73.47 88.295 89.07 ;
     RECT  93.495 63.07 93.895 89.07 ;
     RECT  97.495 86.27 97.895 89.07 ;
     RECT  107.895 56.67 108.295 89.07 ;
     RECT  121.495 27.87 121.895 89.07 ;
     RECT  127.895 58.27 128.295 89.07 ;
     RECT  147.895 63.07 148.295 89.07 ;
     RECT  154.295 77.07 154.695 89.07 ;
     RECT  188.695 69.47 189.095 89.07 ;
     RECT  192.695 56.67 193.095 89.07 ;
     RECT  16.695 63.87 17.095 89.47 ;
     RECT  16.695 89.47 17.895 89.87 ;
     RECT  47.095 89.47 47.495 89.87 ;
     RECT  52.695 63.87 53.095 89.87 ;
     RECT  55.095 78.27 55.495 89.87 ;
     RECT  66.295 89.47 66.695 89.87 ;
     RECT  125.495 36.67 125.895 89.87 ;
     RECT  132.695 89.47 133.095 89.87 ;
     RECT  139.895 49.47 140.295 89.87 ;
     RECT  151.095 89.47 151.495 89.87 ;
     RECT  155.095 87.87 155.495 89.87 ;
     RECT  179.095 88.67 179.495 89.87 ;
     RECT  180.695 89.47 181.095 89.87 ;
     RECT  203.095 66.27 203.495 89.87 ;
     RECT  46.295 55.07 46.695 91.87 ;
     RECT  46.295 91.87 47.495 92.27 ;
     RECT  21.495 43.07 21.895 93.07 ;
     RECT  57.495 92.67 57.895 93.07 ;
     RECT  91.095 89.47 91.495 93.07 ;
     RECT  150.295 83.87 150.695 93.07 ;
     RECT  156.695 87.87 157.095 93.07 ;
     RECT  175.095 51.07 175.495 93.07 ;
     RECT  186.295 71.07 186.695 93.07 ;
     RECT  187.895 73.47 188.295 93.07 ;
     RECT  194.295 91.07 194.695 93.07 ;
     RECT  203.895 38.27 204.295 93.07 ;
     RECT  205.495 19.07 205.895 93.07 ;
     RECT  22.295 86.27 22.695 93.87 ;
     RECT  24.695 70.27 25.095 93.87 ;
     RECT  106.295 53.47 106.695 93.87 ;
     RECT  131.095 67.07 131.495 93.87 ;
     RECT  196.695 56.67 197.095 93.87 ;
     RECT  206.295 50.27 206.695 93.87 ;
     RECT  30.295 72.67 30.695 94.67 ;
     RECT  43.095 94.27 43.495 94.67 ;
     RECT  80.695 72.67 81.095 94.67 ;
     RECT  82.295 56.67 82.695 94.67 ;
     RECT  97.495 94.27 97.895 94.67 ;
     RECT  124.695 77.47 125.095 94.67 ;
     RECT  141.495 53.47 141.895 94.67 ;
     RECT  146.295 70.27 146.695 94.67 ;
     RECT  153.495 62.27 153.895 94.67 ;
     RECT  158.295 77.07 158.695 94.67 ;
     RECT  159.895 92.67 160.295 94.67 ;
     RECT  164.695 94.27 165.095 94.67 ;
     RECT  191.095 85.7 191.495 94.67 ;
     RECT  78.295 62.27 78.695 95.47 ;
     RECT  133.495 72.67 133.895 95.47 ;
     RECT  155.895 67.87 156.295 95.47 ;
     RECT  161.495 87.07 161.895 95.47 ;
     RECT  179.895 83.07 180.295 95.47 ;
     RECT  183.095 64.67 183.495 95.47 ;
     RECT  85.495 94.27 85.895 96.27 ;
     RECT  95.095 82.27 95.495 96.27 ;
     RECT  145.495 91.07 145.895 97.07 ;
     RECT  55.095 95.07 55.495 97.87 ;
     RECT  58.295 73.87 58.695 97.87 ;
     RECT  61.495 84.67 61.895 97.87 ;
     RECT  67.095 91.07 67.495 97.87 ;
     RECT  69.495 97.47 69.895 97.87 ;
     RECT  91.095 97.47 91.495 97.87 ;
     RECT  108.695 71.07 109.095 97.87 ;
     RECT  158.295 97.47 158.695 97.87 ;
     RECT  172.695 67.87 173.095 97.87 ;
     RECT  175.895 46.67 176.295 97.87 ;
     RECT  184.695 95.07 185.095 97.87 ;
     RECT  187.095 79.07 187.495 97.87 ;
     RECT  29.495 73.47 29.895 98.67 ;
     RECT  60.695 55.87 61.095 98.67 ;
     RECT  66.295 94.27 66.695 98.67 ;
     RECT  114.295 72.67 114.695 98.67 ;
     RECT  59.895 78.27 60.295 99.07 ;
     RECT  35.095 43.87 35.495 99.47 ;
     RECT  47.895 85.7 48.295 99.47 ;
     RECT  51.895 99.07 52.295 99.47 ;
     RECT  59.895 99.07 61.895 99.47 ;
     RECT  157.495 53.47 157.895 99.47 ;
     RECT  59.095 98.27 59.495 99.87 ;
     RECT  19.095 35.07 19.495 100.27 ;
     RECT  59.095 99.87 61.095 100.27 ;
     RECT  86.295 56.67 86.695 100.27 ;
     RECT  88.695 72.67 89.095 100.27 ;
     RECT  101.495 64.67 101.895 100.27 ;
     RECT  127.095 81.47 127.495 100.27 ;
     RECT  39.095 71.87 39.495 101.07 ;
     RECT  42.295 93.47 42.695 101.07 ;
     RECT  44.695 59.07 45.095 101.07 ;
     RECT  57.495 100.67 57.895 101.07 ;
     RECT  62.295 100.67 62.695 101.07 ;
     RECT  72.695 68.67 73.095 101.07 ;
     RECT  169.495 71.87 169.895 101.07 ;
     RECT  37.495 89.47 37.895 102.67 ;
     RECT  39.095 102.27 39.495 102.67 ;
     RECT  41.495 84.67 41.895 102.67 ;
     RECT  59.895 100.67 60.295 102.67 ;
     RECT  143.095 55.87 143.495 102.67 ;
     RECT  154.295 102.27 154.695 102.67 ;
     RECT  171.095 100.67 171.495 102.67 ;
     RECT  182.295 77.47 182.695 102.67 ;
     RECT  23.095 78.27 23.495 103.47 ;
     RECT  25.495 79.87 25.895 103.47 ;
     RECT  33.495 99.07 33.895 103.47 ;
     RECT  44.695 103.07 45.895 103.47 ;
     RECT  47.095 92.27 47.495 103.47 ;
     RECT  56.695 102.27 57.095 103.47 ;
     RECT  63.095 73.47 63.495 103.47 ;
     RECT  67.895 93.47 68.295 103.47 ;
     RECT  92.695 85.47 93.095 103.47 ;
     RECT  22.295 103.87 22.695 104.27 ;
     RECT  26.295 85.47 26.695 104.27 ;
     RECT  43.095 103.87 43.495 104.27 ;
     RECT  74.295 58.27 74.695 104.27 ;
     RECT  122.295 103.87 122.695 104.27 ;
     RECT  142.295 99.07 142.695 104.27 ;
     RECT  143.895 103.87 144.295 104.27 ;
     RECT  164.695 103.87 165.095 104.27 ;
     RECT  194.295 103.87 194.695 104.27 ;
     RECT  55.895 89.47 56.295 105.25 ;
     RECT  67.095 99.07 67.495 105.25 ;
     RECT  68.695 87.07 69.095 105.25 ;
     RECT  77.495 93.47 77.895 105.25 ;
     RECT  87.095 89.47 87.495 105.25 ;
     RECT  55.895 105.25 57.095 105.65 ;
     RECT  67.095 105.25 68.295 105.65 ;
     RECT  68.695 105.25 69.895 105.65 ;
     RECT  77.495 105.25 78.695 105.65 ;
     RECT  87.095 105.25 88.295 105.65 ;
     RECT  129.495 103.87 129.895 105.87 ;
     RECT  70.295 105.47 70.695 107.87 ;
     RECT  57.495 107.07 57.895 108.27 ;
     RECT  59.095 105.47 59.495 108.27 ;
     RECT  63.895 87.87 64.295 108.27 ;
     RECT  67.895 105.65 68.295 108.27 ;
     RECT  70.295 107.87 71.495 108.27 ;
     RECT  76.695 89.47 77.095 108.27 ;
     RECT  84.695 78.27 85.095 108.27 ;
     RECT  91.095 105.47 91.495 108.27 ;
     RECT  161.495 107.07 161.895 108.27 ;
     RECT  163.095 103.87 163.495 108.27 ;
     RECT  163.895 99.07 164.295 108.67 ;
     RECT  28.695 92.67 29.095 109.07 ;
     RECT  46.295 95.07 46.695 109.07 ;
     RECT  71.895 87.87 72.295 109.07 ;
     RECT  115.895 94.27 116.295 109.07 ;
     RECT  136.695 103.87 137.095 109.07 ;
     RECT  143.895 107.07 144.295 109.07 ;
     RECT  162.295 108.67 164.295 109.07 ;
     RECT  191.895 107.87 192.295 109.07 ;
     RECT  16.695 94.27 17.095 109.87 ;
     RECT  131.095 105.47 131.495 109.87 ;
     RECT  159.895 105.47 160.295 109.87 ;
     RECT  163.895 109.47 164.295 110.27 ;
     RECT  17.495 89.87 17.895 110.67 ;
     RECT  55.895 110.27 56.295 110.67 ;
     RECT  81.495 91.07 81.895 110.67 ;
     RECT  163.895 110.27 165.095 110.67 ;
     RECT  174.295 103.87 174.695 110.67 ;
     RECT  179.895 108.67 180.295 110.67 ;
     RECT  95.895 87.07 96.295 111.47 ;
     RECT  27.895 79.07 28.295 112.27 ;
     RECT  39.895 79.07 40.295 113.07 ;
     RECT  43.895 93.47 44.295 113.07 ;
     RECT  63.895 113.47 64.295 113.87 ;
     RECT  159.095 85.7 159.495 113.87 ;
     RECT  163.095 112.67 163.495 113.87 ;
     RECT  184.695 99.07 185.095 113.87 ;
     RECT  22.295 113.47 22.695 114.67 ;
     RECT  31.095 83.87 31.495 114.67 ;
     RECT  34.295 59.07 34.695 114.67 ;
     RECT  137.495 85.7 137.895 114.67 ;
     RECT  159.895 113.47 160.295 114.67 ;
     RECT  26.295 115.07 26.695 115.47 ;
     RECT  115.095 115.07 115.495 115.47 ;
     RECT  147.895 107.87 148.295 115.47 ;
     RECT  155.095 94.27 155.495 115.47 ;
     RECT  43.095 107.07 43.495 117.07 ;
     RECT  45.495 103.47 45.895 117.07 ;
     RECT  91.895 93.47 92.295 117.07 ;
     RECT  159.895 116.67 160.295 117.87 ;
     RECT  59.095 118.27 59.495 118.67 ;
     RECT  65.495 97.47 65.895 118.67 ;
     RECT  68.695 118.27 69.095 118.67 ;
     RECT  91.095 118.27 91.495 118.67 ;
     RECT  161.495 111.07 161.895 118.67 ;
     RECT  173.495 118.27 173.895 118.67 ;
     RECT  191.095 118.27 191.495 118.67 ;
     RECT  33.495 121.47 33.895 122.67 ;
     RECT  63.095 115.07 63.495 122.67 ;
     RECT  87.895 105.65 88.295 122.67 ;
     RECT  144.695 97.47 145.095 122.67 ;
     RECT  146.295 122.27 146.695 123.07 ;
     RECT  31.095 123.07 31.495 123.47 ;
     RECT  48.695 79.87 49.095 123.47 ;
     RECT  55.895 122.27 56.295 123.47 ;
     RECT  56.695 105.65 57.095 123.47 ;
     RECT  59.095 123.07 59.495 123.47 ;
     RECT  61.495 99.47 61.895 123.47 ;
     RECT  68.695 121.47 69.095 123.47 ;
     RECT  70.295 123.07 70.695 123.47 ;
     RECT  79.095 79.87 79.495 123.47 ;
     RECT  93.495 96.67 93.895 123.47 ;
     RECT  128.695 123.07 129.095 123.47 ;
     RECT  145.495 123.07 146.695 123.47 ;
     RECT  147.095 116.67 147.495 123.47 ;
     RECT  157.495 121.47 157.895 123.47 ;
     RECT  185.495 115.07 185.895 123.47 ;
     RECT  194.295 123.07 194.695 123.47 ;
     RECT  59.095 124.67 59.495 125.07 ;
     RECT  159.895 122.27 160.295 125.07 ;
     RECT  161.495 124.67 161.895 125.07 ;
     RECT  60.695 100.27 61.095 125.2 ;
     RECT  131.895 113.47 132.295 125.2 ;
     RECT  195.895 103.87 196.295 125.2 ;
     RECT  60.695 125.2 61.895 125.6 ;
     RECT  131.895 125.2 133.895 125.6 ;
     RECT  194.295 125.2 196.295 125.6 ;
     RECT  50.295 123.07 50.695 125.87 ;
     RECT  78.295 105.65 78.695 125.87 ;
     RECT  187.895 102.27 188.295 125.87 ;
     RECT  159.095 119.07 159.495 126.27 ;
     RECT  68.695 126.27 69.095 126.67 ;
     RECT  88.695 124.67 89.095 126.67 ;
     RECT  159.095 126.27 160.295 126.67 ;
     RECT  170.295 113.47 170.695 126.67 ;
     RECT  33.495 126.27 33.895 127.47 ;
     RECT  55.095 108.67 55.495 127.47 ;
     RECT  58.295 113.47 58.695 127.47 ;
     RECT  191.895 109.47 192.295 127.47 ;
     RECT  23.895 127.87 24.295 128.27 ;
     RECT  105.495 24.67 105.895 128.27 ;
     RECT  123.895 111.87 124.295 128.27 ;
     RECT  140.695 127.87 141.095 128.27 ;
     RECT  151.895 111.87 152.295 128.27 ;
     RECT  154.295 114.27 154.695 128.27 ;
     RECT  141.495 109.47 141.895 129.07 ;
     RECT  25.495 128.67 25.895 129.87 ;
     RECT  55.895 129.47 56.295 129.87 ;
     RECT  75.095 93.47 75.495 129.87 ;
     RECT  78.295 129.47 78.695 129.87 ;
     RECT  119.095 118.27 119.495 129.87 ;
     RECT  146.295 129.47 146.695 129.87 ;
     RECT  151.895 129.47 152.295 129.87 ;
     RECT  191.895 129.47 192.295 129.87 ;
     RECT  195.895 129.47 196.295 129.87 ;
     RECT  162.295 109.07 162.695 130.67 ;
     RECT  40.695 115.87 41.095 131.47 ;
     RECT  57.495 126.27 57.895 131.47 ;
     RECT  59.095 131.07 59.495 131.47 ;
     RECT  159.095 129.47 159.495 131.47 ;
     RECT  38.295 132.67 38.695 133.07 ;
     RECT  127.895 129.47 128.295 133.07 ;
     RECT  156.695 122.27 157.095 133.07 ;
     RECT  179.895 111.87 180.295 133.87 ;
     RECT  151.095 131.07 151.495 134.67 ;
     RECT  152.695 126.27 153.095 134.67 ;
     RECT  159.895 126.67 160.295 134.67 ;
     RECT  183.895 133.47 184.295 134.67 ;
     RECT  32.695 134.27 33.095 136.27 ;
     RECT  61.495 125.6 61.895 137.47 ;
     RECT  147.895 124.67 148.295 137.47 ;
     RECT  188.695 133.47 189.095 137.47 ;
     RECT  57.495 137.47 57.895 137.87 ;
     RECT  61.495 137.47 63.495 137.87 ;
     RECT  94.295 127.87 94.695 137.87 ;
     RECT  147.895 137.47 149.095 137.87 ;
     RECT  187.895 137.47 189.095 137.87 ;
     RECT  36.695 131.07 37.095 138.67 ;
     RECT  131.095 134.27 131.495 138.67 ;
     RECT  35.895 134.27 36.295 139.07 ;
     RECT  35.895 139.07 37.095 139.47 ;
     RECT  63.895 134.27 64.295 139.47 ;
     RECT  172.695 139.07 173.095 139.47 ;
     RECT  189.495 117.47 189.895 139.47 ;
     RECT  193.495 107.87 193.895 139.47 ;
     RECT  15.095 129.47 15.495 140.27 ;
     RECT  45.495 118.27 45.895 140.27 ;
     RECT  163.895 131.07 164.295 140.27 ;
     RECT  175.095 102.27 175.495 140.27 ;
     RECT  187.095 124.67 187.495 140.27 ;
     RECT  30.295 139.07 30.695 141.07 ;
     RECT  72.695 129.47 73.095 141.07 ;
     RECT  127.895 140.67 129.095 141.07 ;
     RECT  129.495 139.87 129.895 141.07 ;
     RECT  167.095 115.07 167.495 141.07 ;
     RECT  182.295 103.87 182.695 141.07 ;
     RECT  164.695 110.67 165.095 141.87 ;
     RECT  186.295 117.47 186.695 141.87 ;
     RECT  130.295 124.67 130.695 142.27 ;
     RECT  144.695 124.67 145.095 142.27 ;
     RECT  187.895 137.87 188.295 142.27 ;
     RECT  34.295 128.67 34.695 142.67 ;
     RECT  130.295 142.27 131.495 142.67 ;
     RECT  135.895 130.27 136.295 142.67 ;
     RECT  143.895 142.27 145.095 142.67 ;
     RECT  152.695 139.07 153.095 142.67 ;
     RECT  174.295 140.67 174.695 142.67 ;
     RECT  184.695 142.27 188.295 142.67 ;
     RECT  192.695 111.87 193.095 142.67 ;
     RECT  26.295 123.87 26.695 143.47 ;
     RECT  177.495 103.87 177.895 143.47 ;
     RECT  33.495 143.07 33.895 143.87 ;
     RECT  22.295 142.27 22.695 144.27 ;
     RECT  33.495 143.87 34.695 144.27 ;
     RECT  57.495 143.87 57.895 144.27 ;
     RECT  63.895 143.87 64.295 144.27 ;
     RECT  65.495 143.87 65.895 144.27 ;
     RECT  160.695 102.27 161.095 144.27 ;
     RECT  175.095 143.87 175.495 144.27 ;
     RECT  184.695 142.67 185.095 144.27 ;
     RECT  185.495 143.87 188.295 144.27 ;
     RECT  188.695 141.47 189.095 144.27 ;
     RECT  189.495 143.87 190.695 144.27 ;
     RECT  206.295 143.87 206.695 144.27 ;
     RECT  50.295 131.07 50.695 145.07 ;
     RECT  69.495 105.65 69.895 145.07 ;
     RECT  159.095 143.87 159.495 145.07 ;
     RECT  185.495 144.27 185.895 145.07 ;
     RECT  189.495 144.27 189.895 145.07 ;
     RECT  37.495 131.87 37.895 145.15 ;
     RECT  128.695 141.07 129.095 145.15 ;
     RECT  135.095 116.67 135.495 145.15 ;
     RECT  175.895 123.07 176.295 145.15 ;
     RECT  183.095 132.67 183.495 145.15 ;
     RECT  191.095 144.67 191.495 145.15 ;
     RECT  51.095 122.27 51.495 145.47 ;
     RECT  37.495 145.15 38.695 145.55 ;
     RECT  128.695 145.15 130.695 145.55 ;
     RECT  135.095 145.15 137.095 145.55 ;
     RECT  175.095 145.15 176.295 145.55 ;
     RECT  183.095 145.15 184.295 145.55 ;
     RECT  190.295 145.15 191.495 145.55 ;
     RECT  31.895 131.87 32.295 145.87 ;
     RECT  36.695 139.47 37.095 145.87 ;
     RECT  49.495 145.47 51.495 145.87 ;
     RECT  63.095 137.87 63.495 145.87 ;
     RECT  126.295 132.67 126.695 145.87 ;
     RECT  133.495 125.6 133.895 145.87 ;
     RECT  174.295 145.47 174.695 145.87 ;
     RECT  183.895 145.55 184.295 145.87 ;
     RECT  207.895 99.07 208.295 145.87 ;
     RECT  194.295 125.6 194.695 146.67 ;
     RECT  51.895 144.67 52.295 147.07 ;
     RECT  191.895 138.27 192.295 147.07 ;
     RECT  47.095 133.47 47.495 147.47 ;
     RECT  51.095 147.07 52.295 147.47 ;
     RECT  75.895 134.27 76.295 147.47 ;
     RECT  127.895 142.27 128.295 147.47 ;
     RECT  171.095 146.27 171.495 147.47 ;
     RECT  188.695 147.07 189.095 147.47 ;
     RECT  191.095 147.07 192.295 147.47 ;
     RECT  62.295 139.87 62.695 148.27 ;
     RECT  138.295 98.27 138.695 148.27 ;
     RECT  155.895 126.27 156.295 148.27 ;
     RECT  170.295 145.47 170.695 148.27 ;
     RECT  143.895 142.67 144.295 148.67 ;
     RECT  187.895 144.27 188.295 148.67 ;
     RECT  15.895 127.07 16.295 149.07 ;
     RECT  51.095 147.47 51.495 149.07 ;
     RECT  143.095 148.67 144.295 149.07 ;
     RECT  161.495 148.67 161.895 149.07 ;
     RECT  163.095 118.27 163.495 149.07 ;
     RECT  169.495 134.27 169.895 149.07 ;
     RECT  187.895 148.67 189.095 149.07 ;
     RECT  203.095 108.67 203.495 149.07 ;
     RECT  47.895 145.47 48.295 149.87 ;
     RECT  49.495 145.87 49.895 149.87 ;
     RECT  134.295 134.27 134.695 149.87 ;
     RECT  143.095 149.07 143.495 149.87 ;
     RECT  83.095 127.07 83.495 150.27 ;
     RECT  77.495 144.67 77.895 150.67 ;
     RECT  82.295 150.27 83.495 150.67 ;
     RECT  91.095 148.67 91.495 150.67 ;
     RECT  149.495 139.07 149.895 150.67 ;
     RECT  187.895 149.47 188.295 150.67 ;
     RECT  156.695 134.27 157.095 151.87 ;
     RECT  188.695 149.07 189.095 151.87 ;
     RECT  41.495 132.67 41.895 152.27 ;
     RECT  155.895 151.87 157.095 152.27 ;
     RECT  187.895 151.87 189.095 152.27 ;
     RECT  92.695 127.87 93.095 153.07 ;
     RECT  138.295 151.87 138.695 153.07 ;
     RECT  145.495 138.27 145.895 153.07 ;
     RECT  195.095 127.87 195.495 153.07 ;
     RECT  201.495 115.87 201.895 153.07 ;
     RECT  78.295 147.07 78.695 153.47 ;
     RECT  27.895 128.67 28.295 153.87 ;
     RECT  77.495 153.47 78.695 153.87 ;
     RECT  132.695 138.27 133.095 153.87 ;
     RECT  142.295 152.67 142.695 153.87 ;
     RECT  122.295 138.27 122.695 154.67 ;
     RECT  136.695 145.55 137.095 154.67 ;
     RECT  167.095 144.67 167.495 154.67 ;
     RECT  171.895 117.47 172.295 154.67 ;
     RECT  173.495 151.87 173.895 154.67 ;
     RECT  19.095 139.07 19.495 155.47 ;
     RECT  38.295 145.55 38.695 155.47 ;
     RECT  55.895 155.07 56.295 155.47 ;
     RECT  57.495 155.07 57.895 155.47 ;
     RECT  74.295 142.27 74.695 155.47 ;
     RECT  75.095 138.27 75.495 155.47 ;
     RECT  129.495 146.27 129.895 155.47 ;
     RECT  162.295 143.07 162.695 155.47 ;
     RECT  163.895 155.07 164.295 155.47 ;
     RECT  165.495 112.67 165.895 155.47 ;
     RECT  177.495 154.27 177.895 155.47 ;
     RECT  23.895 139.07 24.295 156.67 ;
     RECT  16.695 134.27 17.095 157.07 ;
     RECT  23.895 156.67 25.095 157.07 ;
     RECT  58.295 134.27 58.695 157.07 ;
     RECT  67.895 134.27 68.295 157.07 ;
     RECT  141.495 138.27 141.895 157.07 ;
     RECT  151.095 140.67 151.495 157.07 ;
     RECT  171.095 155.07 171.495 157.07 ;
     RECT  195.895 156.67 196.295 157.07 ;
     RECT  52.695 143.87 53.095 157.87 ;
     RECT  79.895 138.27 80.295 157.87 ;
     RECT  153.495 132.67 153.895 157.87 ;
     RECT  59.095 156.67 59.495 158.27 ;
     RECT  57.495 158.27 57.895 158.67 ;
     RECT  58.295 158.27 59.495 158.67 ;
     RECT  67.095 138.27 67.495 158.67 ;
     RECT  85.495 158.27 85.895 158.67 ;
     RECT  168.695 137.47 169.095 159.4 ;
     RECT  27.095 109.47 27.495 159.47 ;
     RECT  63.095 156.67 63.495 159.47 ;
     RECT  167.895 159.4 169.095 159.8 ;
     RECT  51.095 149.47 51.495 159.87 ;
     RECT  50.295 159.87 51.495 160.27 ;
     RECT  109.495 83.07 109.895 160.27 ;
     RECT  193.495 139.87 193.895 160.27 ;
     RECT  200.695 124.67 201.095 160.27 ;
     RECT  27.095 159.87 27.495 161.07 ;
     RECT  31.095 159.87 31.495 161.07 ;
     RECT  46.295 159.87 46.695 161.07 ;
     RECT  97.495 159.87 97.895 161.07 ;
     RECT  137.495 139.87 137.895 161.07 ;
     RECT  139.895 150.27 140.295 161.07 ;
     RECT  141.495 159.87 141.895 161.07 ;
     RECT  148.695 137.87 149.095 161.07 ;
     RECT  155.895 152.27 156.295 161.07 ;
     RECT  191.095 147.47 191.495 161.07 ;
     RECT  170.295 149.47 170.695 161.47 ;
     RECT  36.695 160.67 37.095 161.87 ;
     RECT  44.695 159.87 45.095 161.87 ;
     RECT  51.095 161.47 51.495 161.87 ;
     RECT  59.095 161.47 59.495 161.87 ;
     RECT  63.895 161.47 64.295 161.87 ;
     RECT  67.895 161.47 68.295 161.87 ;
     RECT  75.095 161.47 75.495 161.87 ;
     RECT  77.495 153.87 77.895 161.87 ;
     RECT  83.095 161.47 83.495 161.87 ;
     RECT  92.695 159.87 93.095 161.87 ;
     RECT  101.495 161.47 101.895 161.87 ;
     RECT  108.695 161.47 109.095 161.87 ;
     RECT  111.095 161.47 111.495 161.87 ;
     RECT  116.695 159.07 117.095 161.87 ;
     RECT  123.095 160.67 123.495 161.87 ;
     RECT  132.695 161.47 133.095 161.87 ;
     RECT  147.895 157.47 148.295 161.87 ;
     RECT  158.295 130.27 158.695 161.87 ;
     RECT  159.895 143.07 160.295 161.87 ;
     RECT  169.495 159.07 169.895 161.87 ;
     RECT  170.295 161.47 171.495 161.87 ;
     RECT  178.295 139.87 178.695 161.87 ;
     RECT  187.895 152.27 188.295 161.87 ;
     RECT  39.095 141.47 39.495 162.27 ;
     RECT  159.095 160.67 159.495 162.27 ;
     RECT  28.695 126.27 29.095 162.67 ;
     RECT  33.495 145.47 33.895 162.67 ;
     RECT  38.295 162.27 39.495 162.67 ;
     RECT  86.295 161.47 86.695 162.67 ;
     RECT  125.495 126.27 125.895 162.67 ;
     RECT  155.095 141.47 155.495 162.67 ;
     RECT  159.095 162.27 160.295 162.67 ;
     RECT  166.295 115.87 166.695 162.67 ;
     RECT  174.295 147.87 174.695 162.67 ;
     RECT  183.095 147.87 183.495 162.67 ;
     RECT  190.295 145.55 190.695 162.67 ;
     RECT  191.895 159.87 192.295 162.67 ;
     RECT  35.095 138.27 35.495 163.47 ;
     RECT  39.095 163.07 39.495 163.47 ;
     RECT  47.895 161.47 48.295 163.47 ;
     RECT  55.095 161.47 55.495 163.47 ;
     RECT  68.695 159.87 69.095 163.47 ;
     RECT  85.495 163.07 85.895 163.47 ;
     RECT  103.895 163.07 104.295 163.47 ;
     RECT  143.895 162.27 144.295 163.47 ;
     RECT  168.695 163.07 169.095 163.47 ;
     RECT  161.495 158.27 161.895 163.87 ;
     RECT  43.095 159.87 43.495 164.27 ;
     RECT  131.895 143.87 132.295 164.27 ;
     RECT  139.095 108.67 139.495 164.27 ;
     RECT  140.695 137.47 141.095 164.27 ;
     RECT  147.095 139.87 147.495 164.27 ;
     RECT  161.495 163.87 162.695 164.27 ;
     RECT  72.695 163.87 73.095 165.07 ;
     RECT  80.695 163.87 81.095 165.07 ;
     RECT  100.695 163.87 101.095 165.07 ;
     RECT  143.895 163.87 144.295 165.07 ;
     RECT  73.495 143.07 73.895 165.1 ;
     RECT  157.495 124.67 157.895 165.1 ;
     RECT  159.895 162.67 160.295 165.1 ;
     RECT  73.495 165.1 74.695 165.5 ;
     RECT  157.495 165.1 159.495 165.5 ;
     RECT  159.895 165.1 161.095 165.5 ;
     RECT  23.895 163.87 24.295 166.67 ;
     RECT  31.895 163.07 32.295 166.67 ;
     RECT  41.495 163.87 41.895 166.67 ;
     RECT  47.095 148.67 47.495 166.67 ;
     RECT  119.895 163.87 120.295 166.67 ;
     RECT  135.095 163.87 135.495 166.67 ;
     RECT  135.895 147.07 136.295 167.87 ;
     RECT  38.295 162.67 38.695 168.27 ;
     RECT  64.695 124.67 65.095 168.27 ;
     RECT  66.295 155.07 66.695 168.27 ;
     RECT  73.495 166.27 73.895 168.27 ;
     RECT  79.095 124.67 79.495 168.27 ;
     RECT  95.095 132.67 95.495 168.27 ;
     RECT  127.895 167.87 128.295 168.27 ;
     RECT  135.095 167.87 136.295 168.27 ;
     RECT  170.295 161.87 170.695 168.27 ;
     RECT  173.495 167.87 173.895 168.27 ;
     RECT  179.095 110.27 179.495 168.27 ;
     RECT  197.495 126.27 197.895 168.27 ;
     RECT  145.495 161.47 145.895 169.07 ;
     RECT  175.095 145.55 175.495 169.07 ;
     RECT  74.295 165.5 74.695 169.47 ;
     RECT  78.295 155.07 78.695 169.47 ;
     RECT  159.095 165.5 159.495 169.47 ;
     RECT  33.495 169.47 33.895 169.87 ;
     RECT  49.495 162.27 49.895 169.87 ;
     RECT  73.495 169.47 74.695 169.87 ;
     RECT  78.295 169.47 79.495 169.87 ;
     RECT  135.095 168.27 135.495 169.87 ;
     RECT  135.895 168.67 136.295 169.87 ;
     RECT  156.695 169.47 157.095 169.87 ;
     RECT  159.095 169.47 160.295 169.87 ;
     RECT  161.495 169.47 161.895 169.87 ;
     RECT  176.695 144.67 177.095 169.87 ;
     RECT  195.895 169.47 196.295 169.87 ;
     RECT  29.495 153.47 29.895 170.67 ;
     RECT  196.695 119.07 197.095 170.67 ;
     RECT  162.295 164.27 162.695 171.07 ;
     RECT  17.495 130.27 17.895 171.47 ;
     RECT  31.095 163.07 31.495 171.47 ;
     RECT  60.695 127.07 61.095 171.47 ;
     RECT  82.295 150.67 82.695 171.47 ;
     RECT  161.495 171.07 162.695 171.47 ;
     RECT  172.695 152.67 173.095 171.47 ;
     RECT  187.095 144.67 187.495 171.47 ;
     RECT  26.295 153.47 26.695 173.07 ;
     RECT  205.495 115.07 205.895 173.65 ;
     RECT  13.495 135.87 13.895 173.87 ;
     RECT  35.895 141.47 36.295 173.87 ;
     RECT  205.495 173.65 207.495 174.05 ;
     RECT  182.295 153.47 182.695 174.27 ;
     RECT  27.095 161.47 27.495 174.67 ;
     RECT  34.295 144.27 34.695 174.67 ;
     RECT  61.495 149.47 61.895 174.67 ;
     RECT  78.295 174.27 78.695 174.67 ;
     RECT  147.895 169.47 148.295 174.67 ;
     RECT  181.495 174.27 182.695 174.67 ;
     RECT  58.295 158.67 58.695 175.47 ;
     RECT  73.495 169.87 73.895 175.47 ;
     RECT  121.495 128.67 121.895 175.47 ;
     RECT  97.495 175.87 97.895 176.27 ;
     RECT  25.495 145.47 25.895 177.07 ;
     RECT  40.695 144.67 41.095 177.07 ;
     RECT  50.295 160.27 50.695 177.07 ;
     RECT  88.695 162.27 89.095 177.07 ;
     RECT  160.695 165.5 161.095 177.07 ;
     RECT  186.295 162.27 186.695 177.07 ;
     RECT  202.295 118.27 202.695 177.07 ;
     RECT  82.295 177.47 83.495 177.87 ;
     RECT  91.095 156.67 91.495 177.87 ;
     RECT  131.095 142.67 131.495 177.87 ;
     RECT  167.895 159.8 168.295 177.87 ;
     RECT  24.695 157.07 25.095 178.67 ;
     RECT  81.495 154.27 81.895 178.67 ;
     RECT  83.095 177.87 83.495 178.67 ;
     RECT  112.695 43.87 113.095 178.67 ;
     RECT  146.295 159.07 146.695 178.67 ;
     RECT  189.495 147.87 189.895 178.67 ;
     RECT  38.295 177.47 38.695 179.47 ;
     RECT  207.095 174.05 207.495 180.27 ;
     RECT  56.695 141.47 57.095 181.07 ;
     RECT  161.495 171.47 161.895 181.07 ;
     RECT  167.895 179.07 168.295 181.07 ;
     RECT  45.495 141.47 45.895 182.27 ;
     RECT  35.095 180.67 35.495 182.67 ;
     RECT  45.495 182.27 46.695 182.67 ;
     RECT  63.895 175.87 64.295 182.67 ;
     RECT  67.895 163.87 68.295 182.67 ;
     RECT  71.895 134.27 72.295 182.67 ;
     RECT  37.495 162.27 37.895 183.47 ;
     RECT  46.295 182.67 46.695 183.47 ;
     RECT  54.295 182.27 54.695 183.47 ;
     RECT  75.095 168.67 75.495 183.47 ;
     RECT  76.695 168.67 77.095 183.87 ;
     RECT  31.095 182.27 31.495 184.27 ;
     RECT  75.895 183.87 77.095 184.27 ;
     RECT  111.895 137.47 112.295 184.27 ;
     RECT  157.495 167.87 157.895 184.27 ;
     RECT  30.295 141.47 30.695 185.05 ;
     RECT  43.895 139.87 44.295 185.05 ;
     RECT  47.095 168.67 47.495 185.05 ;
     RECT  77.495 167.87 77.895 185.05 ;
     RECT  99.895 138.27 100.295 185.07 ;
     RECT  130.295 145.55 130.695 185.07 ;
     RECT  30.295 185.05 31.495 185.45 ;
     RECT  43.095 185.05 44.295 185.45 ;
     RECT  47.095 185.05 48.295 185.45 ;
     RECT  77.495 185.05 78.695 185.45 ;
     RECT  85.495 185.47 85.895 185.87 ;
     RECT  93.495 149.47 93.895 185.87 ;
     RECT  144.695 147.87 145.095 185.87 ;
     RECT  195.095 163.87 195.495 185.87 ;
     RECT  51.895 159.87 52.295 186.67 ;
     RECT  30.295 187.07 30.695 187.47 ;
     RECT  49.495 187.07 49.895 187.47 ;
     RECT  39.895 126.27 40.295 188.27 ;
     RECT  79.895 187.07 80.295 188.27 ;
     RECT  86.295 163.87 86.695 188.27 ;
     RECT  48.695 130.27 49.095 189.07 ;
     RECT  55.895 159.87 56.295 189.07 ;
     RECT  59.095 173.47 59.495 189.07 ;
     RECT  167.095 159.07 167.495 189.07 ;
     RECT  59.895 176.67 60.295 189.87 ;
     RECT  79.095 169.87 79.495 189.87 ;
     RECT  87.895 127.07 88.295 189.87 ;
     RECT  139.095 167.87 139.495 189.87 ;
     RECT  44.695 190.27 45.095 190.67 ;
     RECT  53.495 155.87 53.895 191.47 ;
     RECT  31.095 185.45 31.495 192.27 ;
     RECT  36.695 169.47 37.095 192.27 ;
     RECT  71.895 190.27 72.295 192.27 ;
     RECT  75.895 184.27 76.295 192.27 ;
     RECT  113.495 129.47 113.895 192.27 ;
     RECT  71.095 169.47 71.495 193.07 ;
     RECT  27.895 193.47 28.295 193.87 ;
     RECT  45.495 193.47 45.895 193.87 ;
     RECT  59.095 193.47 59.495 193.87 ;
     RECT  75.095 193.47 75.495 193.87 ;
     RECT  88.695 193.47 89.095 193.87 ;
     RECT  106.295 143.07 106.695 193.87 ;
     RECT  28.695 168.67 29.095 194.67 ;
     RECT  76.695 184.67 77.095 194.67 ;
     RECT  84.695 170.27 85.095 194.67 ;
     RECT  87.095 175.87 87.495 194.67 ;
     RECT  51.895 194.27 52.295 195.47 ;
     RECT  79.095 194.27 79.495 195.47 ;
     RECT  123.895 131.87 124.295 195.47 ;
     RECT  151.095 194.27 151.495 195.47 ;
     RECT  204.695 175.87 205.095 197.07 ;
     RECT  43.095 185.45 43.495 197.87 ;
     RECT  67.095 159.87 67.495 197.87 ;
     RECT  89.495 128.67 89.895 197.87 ;
     RECT  59.895 198.27 60.295 198.67 ;
     RECT  83.095 198.27 83.495 198.67 ;
     RECT  124.695 98.27 125.095 198.67 ;
     RECT  42.295 175.07 42.695 199.47 ;
     RECT  24.695 183.07 25.095 200.27 ;
     RECT  51.895 198.27 52.295 200.27 ;
     RECT  64.695 169.47 65.095 200.27 ;
     RECT  72.695 199.87 73.095 200.27 ;
     RECT  83.895 159.07 84.295 200.27 ;
     RECT  57.495 183.87 57.895 201.87 ;
     RECT  29.495 172.67 29.895 202.67 ;
     RECT  90.295 178.27 90.695 202.67 ;
     RECT  114.295 139.07 114.695 202.67 ;
     RECT  54.295 193.47 54.695 203.47 ;
     RECT  88.695 199.07 89.095 203.47 ;
     RECT  98.295 145.47 98.695 205 ;
     RECT  97.495 205 98.695 205.4 ;
     RECT  65.495 159.07 65.895 205.87 ;
     RECT  51.095 193.47 51.495 206.67 ;
     RECT  82.295 189.47 82.695 206.67 ;
     RECT  135.895 170.27 136.295 206.67 ;
     RECT  208.695 130.27 209.095 206.67 ;
     RECT  78.295 185.45 78.695 207.47 ;
     RECT  91.895 127.07 92.295 207.47 ;
     RECT  73.495 178.27 73.895 208.27 ;
     RECT  81.495 182.27 81.895 208.27 ;
     RECT  61.495 194.27 61.895 209.07 ;
     RECT  47.895 185.45 48.295 209.87 ;
     RECT  89.495 209.47 89.895 209.87 ;
     RECT  18.295 163.87 18.695 211.47 ;
     RECT  97.495 205.4 97.895 211.47 ;
     RECT  103.095 146.27 103.495 211.47 ;
     RECT  105.495 147.07 105.895 211.47 ;
    LAYER metal9 ;
     RECT  14.895 129.27 23.695 130.07 ;
     RECT  23.695 54.07 24.495 54.87 ;
     RECT  23.695 127.67 24.495 128.47 ;
     RECT  23.695 129.27 24.495 131.67 ;
     RECT  23.695 166.07 24.495 166.87 ;
     RECT  25.295 129.27 26.095 130.07 ;
     RECT  24.495 130.87 26.895 131.67 ;
     RECT  26.895 129.27 27.695 131.67 ;
     RECT  26.895 158.07 27.695 160.47 ;
     RECT  25.295 161.27 27.695 162.07 ;
     RECT  26.895 62.07 28.495 62.87 ;
     RECT  23.695 193.27 28.495 194.07 ;
     RECT  30.095 140.47 30.895 141.27 ;
     RECT  30.095 161.27 30.895 163.67 ;
     RECT  30.895 162.87 31.695 163.67 ;
     RECT  31.695 54.07 32.495 54.87 ;
     RECT  31.695 166.07 32.495 166.87 ;
     RECT  13.295 135.67 33.295 136.47 ;
     RECT  36.495 62.07 37.295 62.87 ;
     RECT  34.895 161.27 37.295 162.07 ;
     RECT  38.095 132.47 38.895 133.27 ;
     RECT  38.095 161.27 38.895 163.67 ;
     RECT  39.695 54.07 40.495 54.87 ;
     RECT  16.495 63.67 41.295 64.47 ;
     RECT  41.295 63.67 42.095 69.27 ;
     RECT  39.695 166.07 42.095 166.87 ;
     RECT  42.895 62.07 43.695 62.87 ;
     RECT  22.095 86.07 43.695 86.87 ;
     RECT  16.495 94.07 43.695 94.87 ;
     RECT  22.095 103.67 43.695 104.47 ;
     RECT  38.895 102.07 45.295 102.87 ;
     RECT  44.495 161.27 45.295 162.07 ;
     RECT  30.895 159.67 46.895 160.47 ;
     RECT  46.895 54.07 48.495 54.87 ;
     RECT  36.495 145.27 48.495 146.07 ;
     RECT  47.695 161.27 48.495 162.07 ;
     RECT  24.495 199.67 48.495 200.47 ;
     RECT  31.695 60.47 49.295 61.27 ;
     RECT  48.495 78.07 50.095 78.87 ;
     RECT  33.295 169.27 50.095 170.07 ;
     RECT  30.095 186.87 50.095 187.67 ;
     RECT  30.895 122.87 50.895 123.67 ;
     RECT  49.295 142.07 50.895 142.87 ;
     RECT  50.895 39.67 51.695 42.07 ;
     RECT  50.895 57.27 51.695 58.07 ;
     RECT  49.295 71.67 51.695 72.47 ;
     RECT  25.295 79.67 51.695 80.47 ;
     RECT  15.695 148.47 51.695 149.27 ;
     RECT  50.895 161.27 51.695 162.07 ;
     RECT  33.295 98.87 52.495 99.67 ;
     RECT  49.295 159.67 52.495 160.47 ;
     RECT  51.695 62.07 53.295 62.87 ;
     RECT  45.295 193.27 53.295 194.07 ;
     RECT  52.495 78.07 54.095 78.87 ;
     RECT  35.695 82.87 54.895 83.67 ;
     RECT  30.895 182.07 54.895 182.87 ;
     RECT  37.295 89.27 55.695 90.07 ;
     RECT  22.095 143.67 55.695 144.47 ;
     RECT  55.695 25.27 56.495 26.07 ;
     RECT  55.695 33.27 56.495 34.07 ;
     RECT  55.695 41.27 56.495 42.07 ;
     RECT  55.695 54.07 56.495 54.87 ;
     RECT  53.295 70.07 56.495 70.87 ;
     RECT  55.695 81.27 56.495 82.07 ;
     RECT  55.695 86.07 56.495 86.87 ;
     RECT  54.895 97.27 56.495 98.07 ;
     RECT  55.695 110.07 56.495 110.87 ;
     RECT  55.695 122.87 56.495 123.67 ;
     RECT  27.695 129.27 56.495 130.07 ;
     RECT  55.695 142.07 56.495 144.47 ;
     RECT  38.095 154.87 56.495 155.67 ;
     RECT  54.895 161.27 56.495 162.07 ;
     RECT  42.095 68.47 57.295 69.27 ;
     RECT  55.695 102.07 57.295 102.87 ;
     RECT  34.895 180.47 57.295 181.27 ;
     RECT  55.695 46.07 58.095 46.87 ;
     RECT  37.295 50.87 58.095 51.67 ;
     RECT  37.295 58.87 58.095 59.67 ;
     RECT  57.295 84.47 58.095 85.27 ;
     RECT  57.295 92.47 58.095 93.27 ;
     RECT  52.495 100.47 58.095 101.27 ;
     RECT  42.895 106.87 58.095 107.67 ;
     RECT  33.295 126.07 58.095 126.87 ;
     RECT  57.295 143.67 58.095 144.47 ;
     RECT  55.695 159.67 58.095 160.47 ;
     RECT  56.495 142.07 58.895 142.87 ;
     RECT  16.495 156.47 58.895 157.27 ;
     RECT  58.895 25.27 59.695 26.07 ;
     RECT  58.895 33.27 59.695 35.67 ;
     RECT  58.895 44.47 59.695 46.87 ;
     RECT  58.095 57.27 59.695 58.07 ;
     RECT  57.295 76.47 59.695 77.27 ;
     RECT  58.895 105.27 59.695 106.07 ;
     RECT  58.895 118.07 59.695 118.87 ;
     RECT  57.295 124.47 59.695 125.27 ;
     RECT  58.895 142.07 59.695 144.47 ;
     RECT  58.895 161.27 59.695 162.07 ;
     RECT  56.495 78.07 60.495 78.87 ;
     RECT  58.895 102.07 60.495 102.87 ;
     RECT  59.695 62.07 61.295 62.87 ;
     RECT  48.495 73.27 62.895 74.07 ;
     RECT  62.095 100.47 62.895 101.27 ;
     RECT  58.895 65.27 63.695 66.07 ;
     RECT  26.095 114.87 63.695 115.67 ;
     RECT  62.095 156.47 63.695 157.27 ;
     RECT  63.695 54.07 64.495 54.87 ;
     RECT  55.695 79.67 64.495 80.47 ;
     RECT  22.095 113.27 64.495 114.07 ;
     RECT  63.695 138.87 64.495 139.67 ;
     RECT  59.695 143.67 64.495 144.47 ;
     RECT  63.695 161.27 64.495 162.07 ;
     RECT  58.895 130.87 65.15 131.67 ;
     RECT  41.295 151.67 65.15 152.47 ;
     RECT  57.295 70.07 65.295 70.87 ;
     RECT  65.15 129.27 65.95 131.67 ;
     RECT  65.15 150.07 65.95 152.47 ;
     RECT  65.295 68.47 66.095 70.87 ;
     RECT  65.295 62.07 66.895 62.87 ;
     RECT  44.495 94.07 66.895 94.87 ;
     RECT  66.895 70.07 67.695 70.87 ;
     RECT  66.895 90.87 67.695 91.67 ;
     RECT  66.895 161.27 68.495 162.07 ;
     RECT  51.695 39.67 69.295 40.47 ;
     RECT  33.295 121.27 69.295 122.07 ;
     RECT  65.295 143.67 70.095 144.47 ;
     RECT  58.895 122.87 70.895 123.67 ;
     RECT  71.695 54.07 72.495 54.87 ;
     RECT  44.495 190.07 72.495 190.87 ;
     RECT  51.695 199.67 73.295 200.47 ;
     RECT  46.895 166.07 74.095 166.87 ;
     RECT  57.295 154.87 74.895 155.67 ;
     RECT  72.495 164.47 74.895 165.27 ;
     RECT  74.895 57.27 75.695 58.07 ;
     RECT  66.095 68.47 75.695 69.27 ;
     RECT  38.095 74.87 75.695 75.67 ;
     RECT  65.95 129.27 75.695 130.07 ;
     RECT  74.895 161.27 75.695 162.07 ;
     RECT  74.895 164.47 75.695 166.87 ;
     RECT  58.895 193.27 75.695 194.07 ;
     RECT  65.95 150.07 78.095 150.87 ;
     RECT  78.095 174.07 78.895 174.87 ;
     RECT  18.095 210.87 78.895 211.67 ;
     RECT  52.495 63.67 79.695 64.47 ;
     RECT  51.695 194.87 79.695 195.67 ;
     RECT  79.695 54.07 80.495 54.87 ;
     RECT  52.495 186.87 80.495 187.67 ;
     RECT  81.295 60.47 82.095 61.27 ;
     RECT  81.295 90.87 82.095 91.67 ;
     RECT  38.095 177.27 82.895 178.07 ;
     RECT  50.895 206.07 82.895 206.87 ;
     RECT  82.895 161.27 83.695 162.07 ;
     RECT  80.495 164.47 83.695 165.27 ;
     RECT  59.695 198.07 83.695 198.87 ;
     RECT  63.695 71.67 84.495 72.47 ;
     RECT  84.495 63.67 85.295 64.47 ;
     RECT  57.295 158.07 86.095 158.87 ;
     RECT  38.895 162.87 86.095 163.67 ;
     RECT  86.095 161.27 86.895 162.07 ;
     RECT  85.295 185.27 86.895 186.07 ;
     RECT  86.095 166.07 87.695 166.87 ;
     RECT  87.695 54.07 88.495 54.87 ;
     RECT  87.695 161.27 88.495 166.87 ;
     RECT  76.495 79.67 89.295 80.47 ;
     RECT  68.495 126.07 89.295 126.87 ;
     RECT  54.095 202.87 89.295 203.67 ;
     RECT  67.695 62.07 90.095 62.87 ;
     RECT  67.695 65.27 90.095 66.07 ;
     RECT  89.295 78.07 90.095 80.47 ;
     RECT  88.495 193.27 90.095 194.07 ;
     RECT  89.295 209.27 90.095 210.07 ;
     RECT  22.895 38.07 90.895 38.87 ;
     RECT  58.895 58.87 90.895 59.67 ;
     RECT  68.495 55.67 91.695 56.47 ;
     RECT  66.095 89.27 91.695 90.07 ;
     RECT  69.295 97.27 91.695 98.07 ;
     RECT  70.095 105.27 91.695 106.07 ;
     RECT  68.495 118.07 91.695 118.87 ;
     RECT  92.495 62.07 93.295 62.87 ;
     RECT  92.495 158.07 93.295 160.47 ;
     RECT  92.495 164.47 93.295 166.87 ;
     RECT  57.295 137.27 94.895 138.07 ;
     RECT  94.895 54.07 96.495 54.87 ;
     RECT  93.295 166.07 96.495 166.87 ;
     RECT  63.695 86.07 98.095 86.87 ;
     RECT  78.095 94.07 98.095 94.87 ;
     RECT  97.295 159.67 98.095 160.47 ;
     RECT  63.695 175.67 98.095 176.47 ;
     RECT  98.895 62.07 99.695 62.87 ;
     RECT  93.295 164.47 101.295 165.27 ;
     RECT  88.495 161.27 102.095 162.07 ;
     RECT  103.695 54.07 104.495 54.87 ;
     RECT  87.695 73.27 104.495 74.07 ;
     RECT  90.095 78.07 104.495 78.87 ;
     RECT  103.695 161.27 104.495 163.67 ;
     RECT  66.095 52.47 105.295 53.27 ;
     RECT  106.895 62.07 107.695 62.87 ;
     RECT  106.895 161.27 109.295 162.07 ;
     RECT  111.695 54.07 112.495 54.87 ;
     RECT  90.095 63.67 112.495 64.47 ;
     RECT  90.895 150.07 112.495 150.87 ;
     RECT  110.895 161.27 112.495 162.07 ;
     RECT  113.295 159.67 114.095 163.67 ;
     RECT  114.095 162.87 114.895 163.67 ;
     RECT  114.095 62.07 115.695 62.87 ;
     RECT  114.895 86.07 115.695 86.87 ;
     RECT  114.895 114.87 115.695 115.67 ;
     RECT  114.895 162.87 115.695 166.87 ;
     RECT  114.895 65.27 116.495 66.07 ;
     RECT  114.895 161.27 117.295 162.07 ;
     RECT  78.095 129.27 119.695 130.07 ;
     RECT  119.695 54.07 120.495 54.87 ;
     RECT  119.695 166.07 120.495 166.87 ;
     RECT  122.095 62.07 123.695 62.87 ;
     RECT  122.895 161.27 123.695 162.07 ;
     RECT  124.495 54.07 128.495 54.87 ;
     RECT  127.695 167.67 128.495 168.47 ;
     RECT  109.295 68.47 130.095 69.27 ;
     RECT  129.295 105.27 130.095 106.07 ;
     RECT  129.295 140.47 130.095 141.27 ;
     RECT  130.895 57.27 131.695 58.07 ;
     RECT  132.495 63.67 133.295 66.07 ;
     RECT  129.295 87.67 133.295 88.47 ;
     RECT  132.495 89.27 133.295 90.07 ;
     RECT  132.495 161.27 133.295 162.07 ;
     RECT  133.295 36.47 134.895 37.27 ;
     RECT  134.095 49.27 134.895 50.07 ;
     RECT  135.695 54.07 136.495 54.87 ;
     RECT  134.895 166.07 136.495 166.87 ;
     RECT  136.495 57.27 139.695 58.07 ;
     RECT  138.895 159.67 139.695 162.07 ;
     RECT  140.495 127.67 141.295 128.47 ;
     RECT  139.695 150.07 141.295 150.87 ;
     RECT  139.695 159.67 142.095 160.47 ;
     RECT  142.095 55.67 142.895 59.67 ;
     RECT  122.095 103.67 142.895 104.47 ;
     RECT  142.095 153.27 142.895 154.07 ;
     RECT  142.895 54.07 144.495 54.87 ;
     RECT  143.695 106.87 144.495 107.67 ;
     RECT  143.695 164.47 144.495 166.87 ;
     RECT  135.695 142.07 144.95 142.87 ;
     RECT  130.895 105.27 145.295 106.07 ;
     RECT  144.95 142.07 145.75 144.47 ;
     RECT  145.295 74.87 146.095 75.67 ;
     RECT  145.295 105.27 146.095 107.67 ;
     RECT  128.495 122.87 146.095 123.67 ;
     RECT  142.095 161.27 146.095 162.07 ;
     RECT  142.895 55.67 146.895 56.47 ;
     RECT  127.695 129.27 146.895 130.07 ;
     RECT  146.895 54.07 147.695 56.47 ;
     RECT  146.895 161.27 148.495 162.07 ;
     RECT  135.695 169.27 148.495 170.07 ;
     RECT  133.295 47.67 149.295 48.47 ;
     RECT  146.095 57.27 149.295 58.07 ;
     RECT  142.095 78.07 150.895 78.87 ;
     RECT  130.895 134.07 151.695 134.87 ;
     RECT  123.695 194.87 151.695 195.67 ;
     RECT  150.895 46.07 152.495 46.87 ;
     RECT  150.895 89.27 152.495 90.07 ;
     RECT  143.695 126.07 153.295 126.87 ;
     RECT  125.295 132.47 154.095 133.27 ;
     RECT  127.695 146.87 154.095 147.67 ;
     RECT  122.095 17.27 154.895 18.07 ;
     RECT  154.895 12.47 155.695 18.07 ;
     RECT  152.495 76.47 155.695 77.27 ;
     RECT  154.895 78.07 155.695 80.47 ;
     RECT  149.295 86.07 155.695 86.87 ;
     RECT  115.695 94.07 155.695 94.87 ;
     RECT  146.895 36.47 156.495 37.27 ;
     RECT  156.495 92.47 157.295 93.27 ;
     RECT  156.495 169.27 157.295 170.07 ;
     RECT  138.095 23.67 158.095 24.47 ;
     RECT  144.495 31.67 158.095 32.47 ;
     RECT  156.495 121.27 158.095 122.07 ;
     RECT  148.495 82.87 158.895 83.67 ;
     RECT  156.495 86.07 158.895 86.87 ;
     RECT  158.095 126.07 159.2 126.87 ;
     RECT  156.495 74.87 159.695 75.67 ;
     RECT  158.895 79.67 159.695 83.67 ;
     RECT  156.495 130.87 159.695 131.67 ;
     RECT  145.75 143.67 159.695 144.47 ;
     RECT  159.2 124.47 160 126.87 ;
     RECT  159.695 25.27 160.495 26.07 ;
     RECT  159.695 33.27 160.495 35.67 ;
     RECT  159.695 46.07 160.495 46.87 ;
     RECT  159.695 94.07 160.495 94.87 ;
     RECT  158.095 97.27 160.495 98.07 ;
     RECT  159.695 105.27 160.495 106.07 ;
     RECT  159.695 113.27 160.495 114.07 ;
     RECT  160 124.47 160.495 125.27 ;
     RECT  159.695 71.67 162.095 72.47 ;
     RECT  146.095 106.87 162.095 107.67 ;
     RECT  118.895 118.07 162.095 118.87 ;
     RECT  161.295 124.47 162.095 126.87 ;
     RECT  161.295 148.47 162.095 149.27 ;
     RECT  138.895 73.27 162.895 74.07 ;
     RECT  134.895 38.07 163.695 38.87 ;
     RECT  143.695 103.67 163.695 104.47 ;
     RECT  162.895 113.27 163.695 114.07 ;
     RECT  159.695 116.47 163.695 117.27 ;
     RECT  162.895 46.07 164.495 46.87 ;
     RECT  164.495 23.67 165.295 27.67 ;
     RECT  164.495 33.27 165.295 34.07 ;
     RECT  164.495 38.07 165.295 40.47 ;
     RECT  164.495 73.27 165.295 74.07 ;
     RECT  164.495 81.27 165.295 82.07 ;
     RECT  164.495 86.07 165.295 86.87 ;
     RECT  164.495 94.07 165.295 94.87 ;
     RECT  164.495 103.67 165.295 107.67 ;
     RECT  144.495 58.87 166.895 59.67 ;
     RECT  166.095 68.47 166.895 69.27 ;
     RECT  166.095 87.67 166.895 88.47 ;
     RECT  166.895 84.47 167.695 86.87 ;
     RECT  161.295 180.47 168.495 181.27 ;
     RECT  151.695 111.67 169.295 112.47 ;
     RECT  143.695 162.87 169.295 163.67 ;
     RECT  128.495 70.07 170.095 70.87 ;
     RECT  167.695 84.47 170.095 85.27 ;
     RECT  169.295 110.07 170.095 112.47 ;
     RECT  169.295 161.27 170.095 162.07 ;
     RECT  150.895 28.47 170.895 29.27 ;
     RECT  153.295 145.27 170.895 146.07 ;
     RECT  145.295 63.67 171.695 64.47 ;
     RECT  169.295 66.87 171.695 67.67 ;
     RECT  154.095 102.07 171.695 102.87 ;
     RECT  124.495 62.07 174.095 62.87 ;
     RECT  138.095 151.67 174.095 152.47 ;
     RECT  159.695 79.67 174.895 80.47 ;
     RECT  146.895 142.07 174.895 142.87 ;
     RECT  174.095 145.27 174.895 146.07 ;
     RECT  173.295 167.67 174.895 168.47 ;
     RECT  134.895 10.87 175.695 11.67 ;
     RECT  161.295 169.27 177.295 170.07 ;
     RECT  163.695 154.87 178.095 155.67 ;
     RECT  154.895 89.27 179.695 90.07 ;
     RECT  161.295 82.87 180.495 83.67 ;
     RECT  170.095 110.07 180.495 110.87 ;
     RECT  154.895 41.27 182.095 42.07 ;
     RECT  143.695 65.27 182.895 66.07 ;
     RECT  159.695 134.07 184.495 134.87 ;
     RECT  159.695 31.67 185.295 32.47 ;
     RECT  169.295 97.27 185.295 98.07 ;
     RECT  147.695 114.87 186.095 115.67 ;
     RECT  149.295 150.07 188.495 150.87 ;
     RECT  170.895 161.27 188.495 162.07 ;
     RECT  188.495 10.87 189.295 11.67 ;
     RECT  166.895 23.67 189.295 24.47 ;
     RECT  150.095 42.87 189.295 43.67 ;
     RECT  174.895 143.67 189.295 144.47 ;
     RECT  170.895 146.87 189.295 147.67 ;
     RECT  167.695 73.27 190.095 74.07 ;
     RECT  155.695 12.47 191.695 13.27 ;
     RECT  150.095 50.87 191.695 51.67 ;
     RECT  173.295 118.07 192.495 118.87 ;
     RECT  151.695 129.27 192.495 130.07 ;
     RECT  191.695 159.67 192.495 160.47 ;
     RECT  172.495 138.87 194.095 139.67 ;
     RECT  171.695 78.07 194.895 78.87 ;
     RECT  145.295 90.87 194.895 91.67 ;
     RECT  174.095 103.67 194.895 104.47 ;
     RECT  146.895 122.87 194.895 123.67 ;
     RECT  194.095 12.47 195.695 13.27 ;
     RECT  194.895 47.67 195.695 48.47 ;
     RECT  162.095 55.67 195.695 56.47 ;
     RECT  168.495 74.87 195.695 75.67 ;
     RECT  169.295 185.27 195.695 186.07 ;
     RECT  113.295 191.67 195.695 192.47 ;
     RECT  194.895 129.27 196.495 130.07 ;
     RECT  170.895 156.47 196.495 157.27 ;
     RECT  194.895 169.27 196.495 170.07 ;
     RECT  175.695 38.07 197.295 38.87 ;
     RECT  187.695 57.27 200.495 58.07 ;
     RECT  199.695 71.67 200.495 72.47 ;
     RECT  158.095 52.47 202.095 53.27 ;
     RECT  132.495 4.47 202.895 5.27 ;
     RECT  184.495 41.27 202.895 42.07 ;
     RECT  187.695 46.07 203.695 46.87 ;
     RECT  180.495 89.27 203.695 90.07 ;
     RECT  191.695 108.47 203.695 109.27 ;
     RECT  114.895 196.47 205.295 197.27 ;
     RECT  206.095 12.47 206.895 13.27 ;
     RECT  190.095 143.67 206.895 144.47 ;
     RECT  206.095 78.07 207.695 78.87 ;
     RECT  187.695 63.67 208.495 64.47 ;
     RECT  184.495 98.87 208.495 99.67 ;
     RECT  135.695 206.07 209.295 206.87 ;
    LAYER metal10 ;
     RECT  55.695 24.07 56.495 26.07 ;
     RECT  164.495 24.07 165.295 27.67 ;
     RECT  58.895 25.27 59.695 28.07 ;
     RECT  159.695 25.27 160.495 28.07 ;
     RECT  55.695 32.07 56.495 34.07 ;
     RECT  164.495 32.07 165.295 34.07 ;
     RECT  58.895 33.27 59.695 36.07 ;
     RECT  159.695 33.27 160.495 36.07 ;
     RECT  164.495 38.07 165.295 40.07 ;
     RECT  55.695 40.07 56.495 42.07 ;
     RECT  58.895 44.07 59.695 46.87 ;
     RECT  159.695 44.07 160.495 46.87 ;
     RECT  55.695 46.07 56.495 48.07 ;
     RECT  162.895 46.07 163.695 48.07 ;
     RECT  194.895 12.47 195.695 48.47 ;
     RECT  134.095 36.47 134.895 50.07 ;
     RECT  57.295 50.87 58.095 52.47 ;
     RECT  57.295 52.47 58.895 53.27 ;
     RECT  146.895 36.47 147.695 54.87 ;
     RECT  23.695 54.07 24.495 56.07 ;
     RECT  31.695 54.07 32.495 56.07 ;
     RECT  39.695 54.07 40.495 56.07 ;
     RECT  47.695 54.07 48.495 56.07 ;
     RECT  55.695 54.07 56.495 56.07 ;
     RECT  63.695 54.07 64.495 56.07 ;
     RECT  71.695 54.07 72.495 56.07 ;
     RECT  79.695 54.07 80.495 56.07 ;
     RECT  87.695 54.07 88.495 56.07 ;
     RECT  95.695 54.07 96.495 56.07 ;
     RECT  103.695 54.07 104.495 56.07 ;
     RECT  111.695 54.07 112.495 56.07 ;
     RECT  119.695 54.07 120.495 56.07 ;
     RECT  127.695 54.07 128.495 56.07 ;
     RECT  135.695 54.07 136.495 56.07 ;
     RECT  143.695 54.07 144.495 56.07 ;
     RECT  50.895 41.27 51.695 58.07 ;
     RECT  58.095 53.27 58.895 58.07 ;
     RECT  188.495 10.87 189.295 58.07 ;
     RECT  142.095 58.87 142.895 59.45 ;
     RECT  74.895 57.27 75.695 60.07 ;
     RECT  130.895 57.27 131.695 60.07 ;
     RECT  138.895 57.27 139.695 60.07 ;
     RECT  142.095 59.45 146.095 60.25 ;
     RECT  148.495 57.27 149.295 60.25 ;
     RECT  66.895 60.07 67.695 62.07 ;
     RECT  26.895 60.07 27.695 62.87 ;
     RECT  36.495 60.07 37.295 62.87 ;
     RECT  42.895 60.07 43.695 62.87 ;
     RECT  52.495 60.07 53.295 62.87 ;
     RECT  60.495 60.07 61.295 62.87 ;
     RECT  65.295 62.07 67.695 62.87 ;
     RECT  92.495 60.07 93.295 62.87 ;
     RECT  98.895 60.07 99.695 62.87 ;
     RECT  106.895 60.07 107.695 62.87 ;
     RECT  114.895 60.07 115.695 62.87 ;
     RECT  122.895 60.07 123.695 62.87 ;
     RECT  84.495 60.07 85.295 64.47 ;
     RECT  58.895 65.27 59.695 68.07 ;
     RECT  55.695 70.07 56.495 72.07 ;
     RECT  159.695 68.07 160.495 72.47 ;
     RECT  199.695 57.27 200.495 72.47 ;
     RECT  156.495 73.27 160.495 74.07 ;
     RECT  164.495 72.07 165.295 74.07 ;
     RECT  57.295 74.07 59.695 74.87 ;
     RECT  145.295 60.25 146.095 75.67 ;
     RECT  156.495 74.07 157.295 75.67 ;
     RECT  58.895 74.87 59.695 76.07 ;
     RECT  159.695 74.07 160.495 76.07 ;
     RECT  57.295 74.87 58.095 77.27 ;
     RECT  154.895 41.27 155.695 77.27 ;
     RECT  49.295 71.67 50.095 78.87 ;
     RECT  206.095 12.47 206.895 78.87 ;
     RECT  55.695 80.07 56.495 82.07 ;
     RECT  164.495 80.07 165.295 82.07 ;
     RECT  57.295 84.47 58.095 85.1 ;
     RECT  58.895 84.07 59.695 85.1 ;
     RECT  57.295 85.1 59.695 85.9 ;
     RECT  159.695 84.07 160.495 86.07 ;
     RECT  114.895 65.27 115.695 86.87 ;
     RECT  154.895 79.67 155.695 86.87 ;
     RECT  158.095 86.07 160.495 86.87 ;
     RECT  55.695 86.07 56.495 88.07 ;
     RECT  164.495 86.07 165.295 88.07 ;
     RECT  129.295 68.47 130.095 88.47 ;
     RECT  166.095 68.47 166.895 88.47 ;
     RECT  132.495 65.27 133.295 90.07 ;
     RECT  151.695 46.07 152.495 90.07 ;
     RECT  66.895 70.07 67.695 91.67 ;
     RECT  81.295 60.47 82.095 91.67 ;
     RECT  57.295 92.47 58.095 93.27 ;
     RECT  58.895 92.07 59.695 93.27 ;
     RECT  57.295 93.27 59.695 94.07 ;
     RECT  159.695 92.07 160.495 94.87 ;
     RECT  164.495 94.07 165.295 96.07 ;
     RECT  55.695 96.07 56.495 98.07 ;
     RECT  169.295 66.87 170.095 98.07 ;
     RECT  159.695 97.27 160.495 100.07 ;
     RECT  52.495 78.07 53.295 101.27 ;
     RECT  62.095 73.27 62.895 101.27 ;
     RECT  44.495 94.07 45.295 102.87 ;
     RECT  58.895 100.07 59.695 102.87 ;
     RECT  55.695 102.07 56.495 104.07 ;
     RECT  164.495 104.07 165.295 107.67 ;
     RECT  58.895 105.27 59.695 108.07 ;
     RECT  159.695 105.27 160.495 108.07 ;
     RECT  55.695 110.07 56.495 112.07 ;
     RECT  162.895 112.07 163.695 114.07 ;
     RECT  159.695 113.27 160.495 116.07 ;
     RECT  58.895 116.07 59.695 118.87 ;
     RECT  162.895 116.47 163.695 120.07 ;
     RECT  156.495 92.47 157.295 122.07 ;
     RECT  55.695 120.07 56.495 123.67 ;
     RECT  57.295 124.47 58.095 125 ;
     RECT  58.895 124.07 59.695 125 ;
     RECT  57.295 125 59.695 125.8 ;
     RECT  159.695 124.07 160.495 126.07 ;
     RECT  143.695 106.87 144.495 126.87 ;
     RECT  158.095 126.07 160.495 126.87 ;
     RECT  129.295 105.27 130.095 141.27 ;
     RECT  153.295 132.47 154.095 146.07 ;
     RECT  161.295 126.07 162.095 149.27 ;
     RECT  111.695 63.67 112.495 150.87 ;
     RECT  140.495 127.67 141.295 150.87 ;
     RECT  114.895 114.87 115.695 151.67 ;
     RECT  113.295 151.67 115.695 152.47 ;
     RECT  23.695 127.67 24.495 154.87 ;
     RECT  63.695 138.87 64.495 154.87 ;
     RECT  20.495 154.87 24.495 155.67 ;
     RECT  62.095 154.87 64.495 155.67 ;
     RECT  62.095 155.67 62.895 157.27 ;
     RECT  26.895 158.07 27.695 160.07 ;
     RECT  92.495 158.07 93.295 160.07 ;
     RECT  49.295 142.07 50.095 160.47 ;
     RECT  57.295 143.67 58.095 160.47 ;
     RECT  113.295 152.47 114.095 160.47 ;
     RECT  191.695 118.07 192.495 160.47 ;
     RECT  97.295 159.67 98.095 161.27 ;
     RECT  98.895 160.07 99.695 161.27 ;
     RECT  25.295 129.27 26.095 162.07 ;
     RECT  30.095 140.47 30.895 162.07 ;
     RECT  34.895 160.07 35.695 162.07 ;
     RECT  38.095 132.47 38.895 162.07 ;
     RECT  44.495 160.07 45.295 162.07 ;
     RECT  50.895 160.07 51.695 162.07 ;
     RECT  58.895 160.07 59.695 162.07 ;
     RECT  66.895 160.07 67.695 162.07 ;
     RECT  74.895 160.07 75.695 162.07 ;
     RECT  82.895 160.07 83.695 162.07 ;
     RECT  86.095 161.27 88.495 162.07 ;
     RECT  97.295 161.27 99.695 162.07 ;
     RECT  106.895 160.07 107.695 162.07 ;
     RECT  114.895 160.07 115.695 162.07 ;
     RECT  122.895 160.07 123.695 162.07 ;
     RECT  132.495 160.07 133.295 162.07 ;
     RECT  138.895 160.07 139.695 162.07 ;
     RECT  142.095 153.27 142.895 162.07 ;
     RECT  146.895 160.07 147.695 162.07 ;
     RECT  47.695 161.27 48.495 164.07 ;
     RECT  55.695 161.27 56.495 164.07 ;
     RECT  63.695 161.27 64.495 164.07 ;
     RECT  87.695 162.07 88.495 164.07 ;
     RECT  103.695 161.27 104.495 164.07 ;
     RECT  111.695 161.27 112.495 164.07 ;
     RECT  71.695 164.07 72.495 166.07 ;
     RECT  79.695 164.07 80.495 166.07 ;
     RECT  82.895 164.47 83.695 166.07 ;
     RECT  23.695 164.07 24.495 166.87 ;
     RECT  31.695 164.07 32.495 166.87 ;
     RECT  39.695 164.07 40.495 166.87 ;
     RECT  71.695 166.07 75.695 166.87 ;
     RECT  79.695 166.07 83.695 166.87 ;
     RECT  95.695 164.07 96.495 166.87 ;
     RECT  119.695 164.07 120.495 166.87 ;
     RECT  135.695 164.07 136.495 166.87 ;
     RECT  143.695 164.07 144.495 166.87 ;
     RECT  20.495 155.67 21.295 167.67 ;
     RECT  20.495 167.67 24.495 168.47 ;
     RECT  127.695 164.07 128.495 168.47 ;
     RECT  174.095 145.27 174.895 168.47 ;
     RECT  156.495 130.87 157.295 170.07 ;
     RECT  86.095 166.07 86.895 186.07 ;
     RECT  169.295 161.27 170.095 186.07 ;
     RECT  194.895 129.27 195.695 192.47 ;
     RECT  23.695 168.47 24.495 194.07 ;
     RECT  52.495 186.87 53.295 194.07 ;
     RECT  114.895 166.07 115.695 197.27 ;
     RECT  89.295 193.27 90.095 210.07 ;
     RECT  78.095 174.07 78.895 211.67 ;
    LAYER via6 ;
     RECT 10.66500 73.60000 10.80500 73.74000 ;
     RECT 10.94500 71.20000 11.08500 71.34000 ;
     RECT 11.22500 32.80000 11.36500 32.94000 ;
     RECT 11.22500 215.20000 11.36500 215.34000 ;
     RECT 13.18500 160.00000 13.32500 160.14000 ;
     RECT 14.02500 204.80000 14.16500 204.94000 ;
     RECT 14.30500 68.80000 14.44500 68.94000 ;
     RECT 14.30500 185.60000 14.44500 185.74000 ;
     RECT 14.86500 72.00000 15.00500 72.14000 ;
     RECT 15.14500 212.80000 15.28500 212.94000 ;
     RECT 15.42500 140.00000 15.56500 140.14000 ;
     RECT 15.99000 15.48000 16.13000 15.62000 ;
     RECT 15.99000 15.78000 16.13000 15.92000 ;
     RECT 15.99000 16.08000 16.13000 16.22000 ;
     RECT 15.99000 16.38000 16.13000 16.52000 ;
     RECT 15.99000 45.48000 16.13000 45.62000 ;
     RECT 15.99000 45.78000 16.13000 45.92000 ;
     RECT 15.99000 46.08000 16.13000 46.22000 ;
     RECT 15.99000 46.38000 16.13000 46.52000 ;
     RECT 15.99000 75.48000 16.13000 75.62000 ;
     RECT 15.99000 75.78000 16.13000 75.92000 ;
     RECT 15.99000 76.08000 16.13000 76.22000 ;
     RECT 15.99000 76.38000 16.13000 76.52000 ;
     RECT 15.99000 105.48000 16.13000 105.62000 ;
     RECT 15.99000 105.78000 16.13000 105.92000 ;
     RECT 15.99000 106.08000 16.13000 106.22000 ;
     RECT 15.99000 106.38000 16.13000 106.52000 ;
     RECT 15.99000 135.48000 16.13000 135.62000 ;
     RECT 15.99000 135.78000 16.13000 135.92000 ;
     RECT 15.99000 136.08000 16.13000 136.22000 ;
     RECT 15.99000 136.38000 16.13000 136.52000 ;
     RECT 15.99000 165.48000 16.13000 165.62000 ;
     RECT 15.99000 165.78000 16.13000 165.92000 ;
     RECT 15.99000 166.08000 16.13000 166.22000 ;
     RECT 15.99000 166.38000 16.13000 166.52000 ;
     RECT 15.99000 195.48000 16.13000 195.62000 ;
     RECT 15.99000 195.78000 16.13000 195.92000 ;
     RECT 15.99000 196.08000 16.13000 196.22000 ;
     RECT 15.99000 196.38000 16.13000 196.52000 ;
     RECT 16.54500 169.60000 16.68500 169.74000 ;
     RECT 16.82500 134.40000 16.96500 134.54000 ;
     RECT 17.66500 171.20000 17.80500 171.34000 ;
     RECT 18.22500 164.00000 18.36500 164.14000 ;
     RECT 18.50500 130.40000 18.64500 130.54000 ;
     RECT 18.78500 54.40000 18.92500 54.54000 ;
     RECT 19.62500 88.80000 19.76500 88.94000 ;
     RECT 19.62500 212.00000 19.76500 212.14000 ;
     RECT 19.90500 109.60000 20.04500 109.74000 ;
     RECT 20.46500 96.80000 20.60500 96.94000 ;
     RECT 20.74500 152.80000 20.88500 152.94000 ;
     RECT 21.02500 104.00000 21.16500 104.14000 ;
     RECT 21.30500 42.40000 21.44500 42.54000 ;
     RECT 21.30500 92.80000 21.44500 92.94000 ;
     RECT 21.58500 55.20000 21.72500 55.34000 ;
     RECT 21.58500 157.60000 21.72500 157.74000 ;
     RECT 21.86500 64.00000 22.00500 64.14000 ;
     RECT 21.86500 88.00000 22.00500 88.14000 ;
     RECT 21.86500 145.60000 22.00500 145.74000 ;
     RECT 21.86500 161.60000 22.00500 161.74000 ;
     RECT 22.14500 52.80000 22.28500 52.94000 ;
     RECT 22.42500 93.60000 22.56500 93.74000 ;
     RECT 22.42500 114.40000 22.56500 114.54000 ;
     RECT 22.42500 142.40000 22.56500 142.54000 ;
     RECT 22.70500 175.20000 22.84500 175.34000 ;
     RECT 22.70500 176.80000 22.84500 176.94000 ;
     RECT 22.98500 38.40000 23.12500 38.54000 ;
     RECT 22.98500 110.40000 23.12500 110.54000 ;
     RECT 22.98500 139.20000 23.12500 139.34000 ;
     RECT 23.26500 129.60000 23.40500 129.74000 ;
     RECT 23.54500 80.80000 23.68500 80.94000 ;
     RECT 23.54500 92.80000 23.68500 92.94000 ;
     RECT 23.54500 100.00000 23.68500 100.14000 ;
     RECT 23.82500 103.20000 23.96500 103.34000 ;
     RECT 23.82500 128.00000 23.96500 128.14000 ;
     RECT 23.82500 139.20000 23.96500 139.34000 ;
     RECT 23.82500 184.80000 23.96500 184.94000 ;
     RECT 24.10500 74.40000 24.24500 74.54000 ;
     RECT 24.10500 164.00000 24.24500 164.14000 ;
     RECT 24.38500 56.80000 24.52500 56.94000 ;
     RECT 24.38500 131.20000 24.52500 131.34000 ;
     RECT 24.38500 177.60000 24.52500 177.74000 ;
     RECT 24.66500 125.60000 24.80500 125.74000 ;
     RECT 24.66500 178.40000 24.80500 178.54000 ;
     RECT 24.66500 183.20000 24.80500 183.34000 ;
     RECT 24.66500 200.00000 24.80500 200.14000 ;
     RECT 24.94500 79.20000 25.08500 79.34000 ;
     RECT 24.94500 159.20000 25.08500 159.34000 ;
     RECT 24.94500 207.20000 25.08500 207.34000 ;
     RECT 25.22500 208.80000 25.36500 208.94000 ;
     RECT 25.50500 71.20000 25.64500 71.34000 ;
     RECT 25.50500 78.40000 25.64500 78.54000 ;
     RECT 25.50500 146.40000 25.64500 146.54000 ;
     RECT 25.50500 168.00000 25.64500 168.14000 ;
     RECT 25.78500 124.00000 25.92500 124.14000 ;
     RECT 25.78500 128.80000 25.92500 128.94000 ;
     RECT 26.06500 68.80000 26.20500 68.94000 ;
     RECT 26.06500 127.20000 26.20500 127.34000 ;
     RECT 26.06500 140.80000 26.20500 140.94000 ;
     RECT 26.06500 156.80000 26.20500 156.94000 ;
     RECT 26.34500 112.00000 26.48500 112.14000 ;
     RECT 26.34500 115.20000 26.48500 115.34000 ;
     RECT 26.62500 104.00000 26.76500 104.14000 ;
     RECT 26.62500 116.00000 26.76500 116.14000 ;
     RECT 26.90500 103.20000 27.04500 103.34000 ;
     RECT 26.90500 153.60000 27.04500 153.74000 ;
     RECT 26.90500 174.40000 27.04500 174.54000 ;
     RECT 27.18500 108.00000 27.32500 108.14000 ;
     RECT 27.18500 198.40000 27.32500 198.54000 ;
     RECT 27.46500 160.80000 27.60500 160.94000 ;
     RECT 28.02500 62.40000 28.16500 62.54000 ;
     RECT 28.02500 98.40000 28.16500 98.54000 ;
     RECT 28.02500 128.80000 28.16500 128.94000 ;
     RECT 28.02500 153.60000 28.16500 153.74000 ;
     RECT 28.30500 79.20000 28.44500 79.34000 ;
     RECT 28.30500 116.80000 28.44500 116.94000 ;
     RECT 28.30500 142.40000 28.44500 142.54000 ;
     RECT 28.30500 168.80000 28.44500 168.94000 ;
     RECT 28.30500 172.80000 28.44500 172.94000 ;
     RECT 28.58500 73.60000 28.72500 73.74000 ;
     RECT 28.58500 82.40000 28.72500 82.54000 ;
     RECT 28.58500 93.60000 28.72500 93.74000 ;
     RECT 28.58500 110.40000 28.72500 110.54000 ;
     RECT 28.58500 129.60000 28.72500 129.74000 ;
     RECT 28.58500 170.40000 28.72500 170.54000 ;
     RECT 28.58500 192.00000 28.72500 192.14000 ;
     RECT 28.58500 193.60000 28.72500 193.74000 ;
     RECT 28.86500 59.20000 29.00500 59.34000 ;
     RECT 28.86500 84.00000 29.00500 84.14000 ;
     RECT 28.86500 113.60000 29.00500 113.74000 ;
     RECT 28.86500 162.40000 29.00500 162.54000 ;
     RECT 28.86500 194.40000 29.00500 194.54000 ;
     RECT 29.14500 85.60000 29.28500 85.74000 ;
     RECT 29.14500 214.40000 29.28500 214.54000 ;
     RECT 29.42500 73.60000 29.56500 73.74000 ;
     RECT 29.42500 141.60000 29.56500 141.74000 ;
     RECT 29.42500 155.20000 29.56500 155.34000 ;
     RECT 29.42500 172.80000 29.56500 172.94000 ;
     RECT 29.42500 174.40000 29.56500 174.54000 ;
     RECT 29.70500 66.40000 29.84500 66.54000 ;
     RECT 29.70500 72.80000 29.84500 72.94000 ;
     RECT 29.70500 108.80000 29.84500 108.94000 ;
     RECT 29.70500 128.80000 29.84500 128.94000 ;
     RECT 29.70500 162.40000 29.84500 162.54000 ;
     RECT 29.70500 173.60000 29.84500 173.74000 ;
     RECT 30.26500 94.40000 30.40500 94.54000 ;
     RECT 30.26500 187.20000 30.40500 187.34000 ;
     RECT 30.54500 79.20000 30.68500 79.34000 ;
     RECT 30.54500 83.20000 30.68500 83.34000 ;
     RECT 30.82500 114.40000 30.96500 114.54000 ;
     RECT 30.82500 123.20000 30.96500 123.34000 ;
     RECT 30.82500 132.00000 30.96500 132.14000 ;
     RECT 30.82500 139.20000 30.96500 139.34000 ;
     RECT 30.82500 160.80000 30.96500 160.94000 ;
     RECT 30.82500 176.00000 30.96500 176.14000 ;
     RECT 30.82500 188.80000 30.96500 188.94000 ;
     RECT 31.10500 103.20000 31.24500 103.34000 ;
     RECT 31.10500 115.20000 31.24500 115.34000 ;
     RECT 31.10500 133.60000 31.24500 133.74000 ;
     RECT 31.10500 171.20000 31.24500 171.34000 ;
     RECT 31.10500 184.00000 31.24500 184.14000 ;
     RECT 31.38500 124.80000 31.52500 124.94000 ;
     RECT 31.38500 161.60000 31.52500 161.74000 ;
     RECT 31.38500 164.00000 31.52500 164.14000 ;
     RECT 31.66500 68.80000 31.80500 68.94000 ;
     RECT 31.66500 145.60000 31.80500 145.74000 ;
     RECT 31.66500 187.20000 31.80500 187.34000 ;
     RECT 31.94500 67.20000 32.08500 67.34000 ;
     RECT 31.94500 98.40000 32.08500 98.54000 ;
     RECT 31.94500 139.20000 32.08500 139.34000 ;
     RECT 31.94500 143.20000 32.08500 143.34000 ;
     RECT 31.94500 186.40000 32.08500 186.54000 ;
     RECT 32.22500 68.00000 32.36500 68.14000 ;
     RECT 32.22500 184.80000 32.36500 184.94000 ;
     RECT 32.50500 70.40000 32.64500 70.54000 ;
     RECT 32.50500 84.80000 32.64500 84.94000 ;
     RECT 32.50500 93.60000 32.64500 93.74000 ;
     RECT 32.50500 153.60000 32.64500 153.74000 ;
     RECT 32.50500 164.00000 32.64500 164.14000 ;
     RECT 32.78500 56.00000 32.92500 56.14000 ;
     RECT 32.78500 102.40000 32.92500 102.54000 ;
     RECT 32.78500 134.40000 32.92500 134.54000 ;
     RECT 33.06500 163.20000 33.20500 163.34000 ;
     RECT 33.06500 172.80000 33.20500 172.94000 ;
     RECT 33.06500 184.80000 33.20500 184.94000 ;
     RECT 33.34500 109.60000 33.48500 109.74000 ;
     RECT 33.34500 127.20000 33.48500 127.34000 ;
     RECT 33.62500 53.60000 33.76500 53.74000 ;
     RECT 33.62500 86.40000 33.76500 86.54000 ;
     RECT 33.62500 122.40000 33.76500 122.54000 ;
     RECT 33.62500 145.60000 33.76500 145.74000 ;
     RECT 33.62500 169.60000 33.76500 169.74000 ;
     RECT 33.90500 69.60000 34.04500 69.74000 ;
     RECT 33.90500 72.00000 34.04500 72.14000 ;
     RECT 33.90500 92.80000 34.04500 92.94000 ;
     RECT 33.90500 100.00000 34.04500 100.14000 ;
     RECT 33.90500 184.00000 34.04500 184.14000 ;
     RECT 34.18500 88.80000 34.32500 88.94000 ;
     RECT 34.46500 59.20000 34.60500 59.34000 ;
     RECT 34.46500 114.40000 34.60500 114.54000 ;
     RECT 34.74500 143.20000 34.88500 143.34000 ;
     RECT 35.02500 126.40000 35.16500 126.54000 ;
     RECT 35.30500 44.00000 35.44500 44.14000 ;
     RECT 35.30500 138.40000 35.44500 138.54000 ;
     RECT 35.30500 163.20000 35.44500 163.34000 ;
     RECT 35.30500 182.40000 35.44500 182.54000 ;
     RECT 35.86500 134.40000 36.00500 134.54000 ;
     RECT 35.86500 168.80000 36.00500 168.94000 ;
     RECT 35.86500 173.60000 36.00500 173.74000 ;
     RECT 36.14500 160.80000 36.28500 160.94000 ;
     RECT 36.14500 206.40000 36.28500 206.54000 ;
     RECT 36.42500 101.60000 36.56500 101.74000 ;
     RECT 36.42500 169.60000 36.56500 169.74000 ;
     RECT 36.42500 174.40000 36.56500 174.54000 ;
     RECT 36.42500 192.00000 36.56500 192.14000 ;
     RECT 36.70500 62.40000 36.84500 62.54000 ;
     RECT 36.70500 99.20000 36.84500 99.34000 ;
     RECT 36.70500 141.60000 36.84500 141.74000 ;
     RECT 36.70500 143.20000 36.84500 143.34000 ;
     RECT 36.70500 168.80000 36.84500 168.94000 ;
     RECT 36.70500 176.80000 36.84500 176.94000 ;
     RECT 36.98500 51.20000 37.12500 51.34000 ;
     RECT 36.98500 103.20000 37.12500 103.34000 ;
     RECT 37.26500 56.80000 37.40500 56.94000 ;
     RECT 37.26500 123.20000 37.40500 123.34000 ;
     RECT 37.26500 147.20000 37.40500 147.34000 ;
     RECT 37.26500 168.00000 37.40500 168.14000 ;
     RECT 37.26500 185.60000 37.40500 185.74000 ;
     RECT 37.54500 83.20000 37.68500 83.34000 ;
     RECT 37.54500 84.80000 37.68500 84.94000 ;
     RECT 37.54500 110.40000 37.68500 110.54000 ;
     RECT 37.82500 63.20000 37.96500 63.34000 ;
     RECT 37.82500 68.00000 37.96500 68.14000 ;
     RECT 37.82500 132.00000 37.96500 132.14000 ;
     RECT 38.38500 132.80000 38.52500 132.94000 ;
     RECT 38.38500 179.20000 38.52500 179.34000 ;
     RECT 38.66500 153.60000 38.80500 153.74000 ;
     RECT 38.94500 73.60000 39.08500 73.74000 ;
     RECT 38.94500 87.20000 39.08500 87.34000 ;
     RECT 38.94500 163.20000 39.08500 163.34000 ;
     RECT 38.94500 183.20000 39.08500 183.34000 ;
     RECT 39.22500 95.20000 39.36500 95.34000 ;
     RECT 39.22500 102.40000 39.36500 102.54000 ;
     RECT 39.22500 109.60000 39.36500 109.74000 ;
     RECT 39.22500 148.00000 39.36500 148.14000 ;
     RECT 39.50500 72.00000 39.64500 72.14000 ;
     RECT 39.50500 100.80000 39.64500 100.94000 ;
     RECT 39.50500 141.60000 39.64500 141.74000 ;
     RECT 39.78500 116.00000 39.92500 116.14000 ;
     RECT 39.78500 132.00000 39.92500 132.14000 ;
     RECT 39.78500 132.80000 39.92500 132.94000 ;
     RECT 39.78500 172.00000 39.92500 172.14000 ;
     RECT 39.78500 188.00000 39.92500 188.14000 ;
     RECT 40.06500 56.00000 40.20500 56.14000 ;
     RECT 40.06500 70.40000 40.20500 70.54000 ;
     RECT 40.06500 72.80000 40.20500 72.94000 ;
     RECT 40.06500 79.20000 40.20500 79.34000 ;
     RECT 40.06500 112.00000 40.20500 112.14000 ;
     RECT 40.06500 112.80000 40.20500 112.94000 ;
     RECT 40.06500 126.40000 40.20500 126.54000 ;
     RECT 40.06500 154.40000 40.20500 154.54000 ;
     RECT 40.06500 177.60000 40.20500 177.74000 ;
     RECT 40.34500 64.00000 40.48500 64.14000 ;
     RECT 40.34500 93.60000 40.48500 93.74000 ;
     RECT 40.62500 58.40000 40.76500 58.54000 ;
     RECT 40.90500 62.40000 41.04500 62.54000 ;
     RECT 40.90500 84.80000 41.04500 84.94000 ;
     RECT 40.90500 131.20000 41.04500 131.34000 ;
     RECT 40.90500 147.20000 41.04500 147.34000 ;
     RECT 40.90500 160.80000 41.04500 160.94000 ;
     RECT 40.90500 164.00000 41.04500 164.14000 ;
     RECT 41.18500 116.00000 41.32500 116.14000 ;
     RECT 41.18500 130.40000 41.32500 130.54000 ;
     RECT 41.46500 100.80000 41.60500 100.94000 ;
     RECT 41.46500 140.00000 41.60500 140.14000 ;
     RECT 41.46500 144.80000 41.60500 144.94000 ;
     RECT 41.74500 53.60000 41.88500 53.74000 ;
     RECT 41.74500 74.40000 41.88500 74.54000 ;
     RECT 41.74500 125.60000 41.88500 125.74000 ;
     RECT 42.02500 141.60000 42.16500 141.74000 ;
     RECT 42.02500 155.20000 42.16500 155.34000 ;
     RECT 42.02500 175.20000 42.16500 175.34000 ;
     RECT 42.02500 211.20000 42.16500 211.34000 ;
     RECT 42.30500 93.60000 42.44500 93.74000 ;
     RECT 42.30500 199.20000 42.44500 199.34000 ;
     RECT 42.58500 191.20000 42.72500 191.34000 ;
     RECT 42.58500 210.40000 42.72500 210.54000 ;
     RECT 42.86500 67.20000 43.00500 67.34000 ;
     RECT 42.86500 82.40000 43.00500 82.54000 ;
     RECT 42.86500 140.80000 43.00500 140.94000 ;
     RECT 42.86500 145.60000 43.00500 145.74000 ;
     RECT 43.14500 62.40000 43.28500 62.54000 ;
     RECT 43.14500 68.80000 43.28500 68.94000 ;
     RECT 43.14500 85.60000 43.28500 85.74000 ;
     RECT 43.14500 94.40000 43.28500 94.54000 ;
     RECT 43.14500 115.20000 43.28500 115.34000 ;
     RECT 43.14500 132.80000 43.28500 132.94000 ;
     RECT 43.14500 138.40000 43.28500 138.54000 ;
     RECT 43.14500 200.80000 43.28500 200.94000 ;
     RECT 43.42500 56.80000 43.56500 56.94000 ;
     RECT 43.42500 112.80000 43.56500 112.94000 ;
     RECT 43.42500 114.40000 43.56500 114.54000 ;
     RECT 43.42500 197.60000 43.56500 197.74000 ;
     RECT 43.70500 69.60000 43.84500 69.74000 ;
     RECT 43.70500 96.80000 43.84500 96.94000 ;
     RECT 43.99000 30.48000 44.13000 30.62000 ;
     RECT 43.99000 30.78000 44.13000 30.92000 ;
     RECT 43.99000 31.08000 44.13000 31.22000 ;
     RECT 43.99000 31.38000 44.13000 31.52000 ;
     RECT 43.99000 60.48000 44.13000 60.62000 ;
     RECT 43.99000 60.78000 44.13000 60.92000 ;
     RECT 43.99000 61.08000 44.13000 61.22000 ;
     RECT 43.99000 61.38000 44.13000 61.52000 ;
     RECT 43.99000 90.48000 44.13000 90.62000 ;
     RECT 43.99000 90.78000 44.13000 90.92000 ;
     RECT 43.99000 91.08000 44.13000 91.22000 ;
     RECT 43.99000 91.38000 44.13000 91.52000 ;
     RECT 43.99000 120.48000 44.13000 120.62000 ;
     RECT 43.99000 120.78000 44.13000 120.92000 ;
     RECT 43.99000 121.08000 44.13000 121.22000 ;
     RECT 43.99000 121.38000 44.13000 121.52000 ;
     RECT 43.99000 150.48000 44.13000 150.62000 ;
     RECT 43.99000 150.78000 44.13000 150.92000 ;
     RECT 43.99000 151.08000 44.13000 151.22000 ;
     RECT 43.99000 151.38000 44.13000 151.52000 ;
     RECT 43.99000 180.48000 44.13000 180.62000 ;
     RECT 43.99000 180.78000 44.13000 180.92000 ;
     RECT 43.99000 181.08000 44.13000 181.22000 ;
     RECT 43.99000 181.38000 44.13000 181.52000 ;
     RECT 44.26500 100.80000 44.40500 100.94000 ;
     RECT 44.26500 104.00000 44.40500 104.14000 ;
     RECT 44.26500 160.00000 44.40500 160.14000 ;
     RECT 44.26500 193.60000 44.40500 193.74000 ;
     RECT 44.54500 70.40000 44.68500 70.54000 ;
     RECT 44.54500 97.60000 44.68500 97.74000 ;
     RECT 44.54500 108.80000 44.68500 108.94000 ;
     RECT 44.82500 59.20000 44.96500 59.34000 ;
     RECT 44.82500 190.40000 44.96500 190.54000 ;
     RECT 45.10500 158.40000 45.24500 158.54000 ;
     RECT 45.10500 198.40000 45.24500 198.54000 ;
     RECT 45.38500 93.60000 45.52500 93.74000 ;
     RECT 45.38500 96.00000 45.52500 96.14000 ;
     RECT 45.38500 183.20000 45.52500 183.34000 ;
     RECT 45.66500 72.00000 45.80500 72.14000 ;
     RECT 45.66500 73.60000 45.80500 73.74000 ;
     RECT 45.66500 102.40000 45.80500 102.54000 ;
     RECT 45.66500 126.40000 45.80500 126.54000 ;
     RECT 45.66500 131.20000 45.80500 131.34000 ;
     RECT 45.66500 133.60000 45.80500 133.74000 ;
     RECT 45.94500 140.00000 46.08500 140.14000 ;
     RECT 46.22500 110.40000 46.36500 110.54000 ;
     RECT 46.22500 125.60000 46.36500 125.74000 ;
     RECT 46.22500 140.80000 46.36500 140.94000 ;
     RECT 46.22500 147.20000 46.36500 147.34000 ;
     RECT 46.22500 170.40000 46.36500 170.54000 ;
     RECT 46.22500 175.20000 46.36500 175.34000 ;
     RECT 46.22500 186.40000 46.36500 186.54000 ;
     RECT 46.50500 128.80000 46.64500 128.94000 ;
     RECT 46.78500 66.40000 46.92500 66.54000 ;
     RECT 46.78500 102.40000 46.92500 102.54000 ;
     RECT 46.78500 103.20000 46.92500 103.34000 ;
     RECT 46.78500 160.80000 46.92500 160.94000 ;
     RECT 46.78500 187.20000 46.92500 187.34000 ;
     RECT 47.06500 148.80000 47.20500 148.94000 ;
     RECT 47.06500 199.20000 47.20500 199.34000 ;
     RECT 47.34500 89.60000 47.48500 89.74000 ;
     RECT 47.34500 118.40000 47.48500 118.54000 ;
     RECT 47.62500 56.00000 47.76500 56.14000 ;
     RECT 47.62500 133.60000 47.76500 133.74000 ;
     RECT 47.62500 168.80000 47.76500 168.94000 ;
     RECT 47.90500 73.60000 48.04500 73.74000 ;
     RECT 47.90500 162.40000 48.04500 162.54000 ;
     RECT 47.90500 163.20000 48.04500 163.34000 ;
     RECT 47.90500 188.00000 48.04500 188.14000 ;
     RECT 48.18500 38.40000 48.32500 38.54000 ;
     RECT 48.18500 96.80000 48.32500 96.94000 ;
     RECT 48.18500 99.20000 48.32500 99.34000 ;
     RECT 48.18500 113.60000 48.32500 113.74000 ;
     RECT 48.18500 174.40000 48.32500 174.54000 ;
     RECT 48.18500 192.00000 48.32500 192.14000 ;
     RECT 48.46500 64.00000 48.60500 64.14000 ;
     RECT 48.46500 88.00000 48.60500 88.14000 ;
     RECT 48.46500 116.80000 48.60500 116.94000 ;
     RECT 48.46500 124.00000 48.60500 124.14000 ;
     RECT 48.46500 185.60000 48.60500 185.74000 ;
     RECT 48.74500 84.00000 48.88500 84.14000 ;
     RECT 48.74500 168.80000 48.88500 168.94000 ;
     RECT 49.02500 77.60000 49.16500 77.74000 ;
     RECT 49.02500 162.40000 49.16500 162.54000 ;
     RECT 49.02500 168.00000 49.16500 168.14000 ;
     RECT 49.02500 169.60000 49.16500 169.74000 ;
     RECT 49.02500 176.80000 49.16500 176.94000 ;
     RECT 49.30500 83.20000 49.44500 83.34000 ;
     RECT 49.30500 130.40000 49.44500 130.54000 ;
     RECT 49.30500 149.60000 49.44500 149.74000 ;
     RECT 49.30500 153.60000 49.44500 153.74000 ;
     RECT 49.30500 192.80000 49.44500 192.94000 ;
     RECT 49.30500 198.40000 49.44500 198.54000 ;
     RECT 49.58500 74.40000 49.72500 74.54000 ;
     RECT 49.86500 82.40000 50.00500 82.54000 ;
     RECT 49.86500 155.20000 50.00500 155.34000 ;
     RECT 50.14500 187.20000 50.28500 187.34000 ;
     RECT 50.42500 63.20000 50.56500 63.34000 ;
     RECT 50.42500 88.80000 50.56500 88.94000 ;
     RECT 50.70500 73.60000 50.84500 73.74000 ;
     RECT 50.70500 108.00000 50.84500 108.14000 ;
     RECT 50.98500 95.20000 51.12500 95.34000 ;
     RECT 50.98500 122.40000 51.12500 122.54000 ;
     RECT 50.98500 124.80000 51.12500 124.94000 ;
     RECT 50.98500 144.00000 51.12500 144.14000 ;
     RECT 50.98500 144.80000 51.12500 144.94000 ;
     RECT 50.98500 149.60000 51.12500 149.74000 ;
     RECT 50.98500 184.80000 51.12500 184.94000 ;
     RECT 50.98500 193.60000 51.12500 193.74000 ;
     RECT 50.98500 203.20000 51.12500 203.34000 ;
     RECT 51.26500 117.60000 51.40500 117.74000 ;
     RECT 51.26500 161.60000 51.40500 161.74000 ;
     RECT 51.26500 172.00000 51.40500 172.14000 ;
     RECT 51.54500 202.40000 51.68500 202.54000 ;
     RECT 51.82500 84.80000 51.96500 84.94000 ;
     RECT 51.82500 144.80000 51.96500 144.94000 ;
     RECT 51.82500 157.60000 51.96500 157.74000 ;
     RECT 52.10500 62.40000 52.24500 62.54000 ;
     RECT 52.10500 144.00000 52.24500 144.14000 ;
     RECT 52.10500 156.00000 52.24500 156.14000 ;
     RECT 52.10500 184.80000 52.24500 184.94000 ;
     RECT 52.10500 194.40000 52.24500 194.54000 ;
     RECT 52.38500 186.40000 52.52500 186.54000 ;
     RECT 52.66500 68.00000 52.80500 68.14000 ;
     RECT 52.66500 78.40000 52.80500 78.54000 ;
     RECT 52.94500 53.60000 53.08500 53.74000 ;
     RECT 52.94500 67.20000 53.08500 67.34000 ;
     RECT 52.94500 69.60000 53.08500 69.74000 ;
     RECT 52.94500 81.60000 53.08500 81.74000 ;
     RECT 52.94500 86.40000 53.08500 86.54000 ;
     RECT 52.94500 89.60000 53.08500 89.74000 ;
     RECT 53.22500 70.40000 53.36500 70.54000 ;
     RECT 53.22500 82.40000 53.36500 82.54000 ;
     RECT 53.22500 98.40000 53.36500 98.54000 ;
     RECT 53.22500 144.80000 53.36500 144.94000 ;
     RECT 53.50500 139.20000 53.64500 139.34000 ;
     RECT 53.50500 156.80000 53.64500 156.94000 ;
     RECT 53.50500 193.60000 53.64500 193.74000 ;
     RECT 53.78500 88.80000 53.92500 88.94000 ;
     RECT 53.78500 125.60000 53.92500 125.74000 ;
     RECT 53.78500 173.60000 53.92500 173.74000 ;
     RECT 54.06500 51.20000 54.20500 51.34000 ;
     RECT 54.06500 56.00000 54.20500 56.14000 ;
     RECT 54.06500 63.20000 54.20500 63.34000 ;
     RECT 54.06500 69.60000 54.20500 69.74000 ;
     RECT 54.06500 80.80000 54.20500 80.94000 ;
     RECT 54.34500 78.40000 54.48500 78.54000 ;
     RECT 54.34500 96.80000 54.48500 96.94000 ;
     RECT 54.34500 168.00000 54.48500 168.14000 ;
     RECT 54.62500 112.80000 54.76500 112.94000 ;
     RECT 54.62500 183.20000 54.76500 183.34000 ;
     RECT 54.90500 71.20000 55.04500 71.34000 ;
     RECT 54.90500 123.20000 55.04500 123.34000 ;
     RECT 55.18500 52.80000 55.32500 52.94000 ;
     RECT 55.18500 64.00000 55.32500 64.14000 ;
     RECT 55.18500 68.80000 55.32500 68.94000 ;
     RECT 55.18500 88.00000 55.32500 88.14000 ;
     RECT 55.18500 93.60000 55.32500 93.74000 ;
     RECT 55.18500 95.20000 55.32500 95.34000 ;
     RECT 55.18500 127.20000 55.32500 127.34000 ;
     RECT 55.18500 139.20000 55.32500 139.34000 ;
     RECT 55.18500 186.40000 55.32500 186.54000 ;
     RECT 55.46500 98.40000 55.60500 98.54000 ;
     RECT 55.46500 99.20000 55.60500 99.34000 ;
     RECT 55.46500 110.40000 55.60500 110.54000 ;
     RECT 55.74500 80.80000 55.88500 80.94000 ;
     RECT 55.74500 86.40000 55.88500 86.54000 ;
     RECT 56.02500 25.60000 56.16500 25.74000 ;
     RECT 56.02500 40.00000 56.16500 40.14000 ;
     RECT 56.02500 41.60000 56.16500 41.74000 ;
     RECT 56.02500 55.20000 56.16500 55.34000 ;
     RECT 56.02500 89.60000 56.16500 89.74000 ;
     RECT 56.02500 122.40000 56.16500 122.54000 ;
     RECT 56.02500 163.20000 56.16500 163.34000 ;
     RECT 56.02500 188.80000 56.16500 188.94000 ;
     RECT 56.30500 33.60000 56.44500 33.74000 ;
     RECT 56.30500 56.80000 56.44500 56.94000 ;
     RECT 56.30500 94.40000 56.44500 94.54000 ;
     RECT 56.30500 96.80000 56.44500 96.94000 ;
     RECT 56.30500 97.60000 56.44500 97.74000 ;
     RECT 56.30500 130.40000 56.44500 130.54000 ;
     RECT 56.30500 141.60000 56.44500 141.74000 ;
     RECT 56.30500 155.20000 56.44500 155.34000 ;
     RECT 56.30500 156.00000 56.44500 156.14000 ;
     RECT 56.30500 176.80000 56.44500 176.94000 ;
     RECT 56.30500 183.20000 56.44500 183.34000 ;
     RECT 56.58500 123.20000 56.72500 123.34000 ;
     RECT 56.86500 99.20000 57.00500 99.34000 ;
     RECT 56.86500 103.20000 57.00500 103.34000 ;
     RECT 56.86500 128.80000 57.00500 128.94000 ;
     RECT 56.86500 184.00000 57.00500 184.14000 ;
     RECT 57.14500 41.60000 57.28500 41.74000 ;
     RECT 57.14500 82.40000 57.28500 82.54000 ;
     RECT 57.14500 132.00000 57.28500 132.14000 ;
     RECT 57.14500 152.80000 57.28500 152.94000 ;
     RECT 57.14500 155.20000 57.28500 155.34000 ;
     RECT 57.14500 200.00000 57.28500 200.14000 ;
     RECT 57.42500 65.60000 57.56500 65.74000 ;
     RECT 57.42500 70.40000 57.56500 70.54000 ;
     RECT 57.42500 108.00000 57.56500 108.14000 ;
     RECT 57.42500 109.60000 57.56500 109.74000 ;
     RECT 57.42500 124.80000 57.56500 124.94000 ;
     RECT 57.42500 137.60000 57.56500 137.74000 ;
     RECT 57.42500 142.40000 57.56500 142.54000 ;
     RECT 57.42500 201.60000 57.56500 201.74000 ;
     RECT 57.70500 35.20000 57.84500 35.34000 ;
     RECT 57.70500 79.20000 57.84500 79.34000 ;
     RECT 57.70500 100.80000 57.84500 100.94000 ;
     RECT 57.70500 112.00000 57.84500 112.14000 ;
     RECT 57.70500 204.00000 57.84500 204.14000 ;
     RECT 57.98500 48.00000 58.12500 48.14000 ;
     RECT 57.98500 56.00000 58.12500 56.14000 ;
     RECT 57.98500 81.60000 58.12500 81.74000 ;
     RECT 57.98500 108.80000 58.12500 108.94000 ;
     RECT 57.98500 110.40000 58.12500 110.54000 ;
     RECT 57.98500 127.20000 58.12500 127.34000 ;
     RECT 57.98500 131.20000 58.12500 131.34000 ;
     RECT 58.26500 123.20000 58.40500 123.34000 ;
     RECT 58.26500 144.00000 58.40500 144.14000 ;
     RECT 58.26500 147.20000 58.40500 147.34000 ;
     RECT 58.54500 92.80000 58.68500 92.94000 ;
     RECT 58.54500 96.80000 58.68500 96.94000 ;
     RECT 58.54500 134.40000 58.68500 134.54000 ;
     RECT 58.54500 152.80000 58.68500 152.94000 ;
     RECT 58.82500 35.20000 58.96500 35.34000 ;
     RECT 58.82500 71.20000 58.96500 71.34000 ;
     RECT 58.82500 97.60000 58.96500 97.74000 ;
     RECT 58.82500 113.60000 58.96500 113.74000 ;
     RECT 58.82500 142.40000 58.96500 142.54000 ;
     RECT 58.82500 186.40000 58.96500 186.54000 ;
     RECT 59.10500 59.20000 59.24500 59.34000 ;
     RECT 59.10500 74.40000 59.24500 74.54000 ;
     RECT 59.38500 131.20000 59.52500 131.34000 ;
     RECT 59.38500 193.60000 59.52500 193.74000 ;
     RECT 59.66500 25.60000 59.80500 25.74000 ;
     RECT 59.66500 44.00000 59.80500 44.14000 ;
     RECT 59.66500 84.80000 59.80500 84.94000 ;
     RECT 59.66500 88.80000 59.80500 88.94000 ;
     RECT 59.66500 92.80000 59.80500 92.94000 ;
     RECT 59.66500 95.20000 59.80500 95.34000 ;
     RECT 59.66500 124.80000 59.80500 124.94000 ;
     RECT 59.66500 129.60000 59.80500 129.74000 ;
     RECT 59.66500 134.40000 59.80500 134.54000 ;
     RECT 59.66500 145.60000 59.80500 145.74000 ;
     RECT 59.66500 198.40000 59.80500 198.54000 ;
     RECT 59.94500 57.60000 60.08500 57.74000 ;
     RECT 59.94500 58.40000 60.08500 58.54000 ;
     RECT 59.94500 62.40000 60.08500 62.54000 ;
     RECT 59.94500 65.60000 60.08500 65.74000 ;
     RECT 59.94500 85.60000 60.08500 85.74000 ;
     RECT 59.94500 100.80000 60.08500 100.94000 ;
     RECT 59.94500 115.20000 60.08500 115.34000 ;
     RECT 59.94500 118.40000 60.08500 118.54000 ;
     RECT 59.94500 153.60000 60.08500 153.74000 ;
     RECT 59.94500 154.40000 60.08500 154.54000 ;
     RECT 59.94500 171.20000 60.08500 171.34000 ;
     RECT 59.94500 185.60000 60.08500 185.74000 ;
     RECT 59.94500 188.00000 60.08500 188.14000 ;
     RECT 59.94500 208.80000 60.08500 208.94000 ;
     RECT 60.22500 78.40000 60.36500 78.54000 ;
     RECT 60.50500 56.80000 60.64500 56.94000 ;
     RECT 60.50500 98.40000 60.64500 98.54000 ;
     RECT 60.50500 132.00000 60.64500 132.14000 ;
     RECT 60.78500 108.00000 60.92500 108.14000 ;
     RECT 60.78500 127.20000 60.92500 127.34000 ;
     RECT 60.78500 148.80000 60.92500 148.94000 ;
     RECT 60.78500 161.60000 60.92500 161.74000 ;
     RECT 60.78500 171.20000 60.92500 171.34000 ;
     RECT 60.78500 177.60000 60.92500 177.74000 ;
     RECT 61.06500 57.60000 61.20500 57.74000 ;
     RECT 61.06500 125.60000 61.20500 125.74000 ;
     RECT 61.06500 192.00000 61.20500 192.14000 ;
     RECT 61.34500 176.80000 61.48500 176.94000 ;
     RECT 61.34500 178.40000 61.48500 178.54000 ;
     RECT 61.62500 56.00000 61.76500 56.14000 ;
     RECT 61.62500 79.20000 61.76500 79.34000 ;
     RECT 61.62500 84.80000 61.76500 84.94000 ;
     RECT 61.62500 123.20000 61.76500 123.34000 ;
     RECT 61.62500 149.60000 61.76500 149.74000 ;
     RECT 61.62500 174.40000 61.76500 174.54000 ;
     RECT 61.62500 194.40000 61.76500 194.54000 ;
     RECT 61.62500 206.40000 61.76500 206.54000 ;
     RECT 61.90500 63.20000 62.04500 63.34000 ;
     RECT 61.90500 66.40000 62.04500 66.54000 ;
     RECT 61.90500 73.60000 62.04500 73.74000 ;
     RECT 61.90500 163.20000 62.04500 163.34000 ;
     RECT 62.18500 52.80000 62.32500 52.94000 ;
     RECT 62.18500 100.80000 62.32500 100.94000 ;
     RECT 62.18500 125.60000 62.32500 125.74000 ;
     RECT 62.46500 86.40000 62.60500 86.54000 ;
     RECT 62.46500 148.80000 62.60500 148.94000 ;
     RECT 62.74500 66.40000 62.88500 66.54000 ;
     RECT 62.74500 84.00000 62.88500 84.14000 ;
     RECT 62.74500 109.60000 62.88500 109.74000 ;
     RECT 62.74500 116.00000 62.88500 116.14000 ;
     RECT 62.74500 158.40000 62.88500 158.54000 ;
     RECT 62.74500 164.00000 62.88500 164.14000 ;
     RECT 62.74500 169.60000 62.88500 169.74000 ;
     RECT 62.74500 184.00000 62.88500 184.14000 ;
     RECT 63.02500 116.80000 63.16500 116.94000 ;
     RECT 63.02500 184.80000 63.16500 184.94000 ;
     RECT 63.02500 188.80000 63.16500 188.94000 ;
     RECT 63.02500 192.80000 63.16500 192.94000 ;
     RECT 63.30500 108.00000 63.44500 108.14000 ;
     RECT 63.30500 122.40000 63.44500 122.54000 ;
     RECT 63.30500 141.60000 63.44500 141.74000 ;
     RECT 63.30500 183.20000 63.44500 183.34000 ;
     RECT 63.30500 204.80000 63.44500 204.94000 ;
     RECT 63.58500 134.40000 63.72500 134.54000 ;
     RECT 63.58500 178.40000 63.72500 178.54000 ;
     RECT 63.86500 64.80000 64.00500 64.94000 ;
     RECT 63.86500 67.20000 64.00500 67.34000 ;
     RECT 63.86500 101.60000 64.00500 101.74000 ;
     RECT 63.86500 182.40000 64.00500 182.54000 ;
     RECT 63.86500 202.40000 64.00500 202.54000 ;
     RECT 64.14500 54.40000 64.28500 54.54000 ;
     RECT 64.14500 144.00000 64.28500 144.14000 ;
     RECT 64.42500 94.40000 64.56500 94.54000 ;
     RECT 64.42500 156.80000 64.56500 156.94000 ;
     RECT 64.42500 161.60000 64.56500 161.74000 ;
     RECT 64.70500 72.00000 64.84500 72.14000 ;
     RECT 64.70500 88.80000 64.84500 88.94000 ;
     RECT 64.70500 93.60000 64.84500 93.74000 ;
     RECT 64.70500 113.60000 64.84500 113.74000 ;
     RECT 64.70500 124.80000 64.84500 124.94000 ;
     RECT 64.70500 200.00000 64.84500 200.14000 ;
     RECT 64.98500 68.00000 65.12500 68.14000 ;
     RECT 64.98500 140.00000 65.12500 140.14000 ;
     RECT 64.98500 144.00000 65.12500 144.14000 ;
     RECT 64.98500 168.00000 65.12500 168.14000 ;
     RECT 64.98500 190.40000 65.12500 190.54000 ;
     RECT 64.98500 193.60000 65.12500 193.74000 ;
     RECT 65.26500 100.00000 65.40500 100.14000 ;
     RECT 65.26500 188.80000 65.40500 188.94000 ;
     RECT 65.54500 48.00000 65.68500 48.14000 ;
     RECT 65.54500 74.40000 65.68500 74.54000 ;
     RECT 65.54500 103.20000 65.68500 103.34000 ;
     RECT 65.54500 118.40000 65.68500 118.54000 ;
     RECT 65.54500 127.20000 65.68500 127.34000 ;
     RECT 65.82500 72.80000 65.96500 72.94000 ;
     RECT 65.82500 126.40000 65.96500 126.54000 ;
     RECT 65.82500 168.00000 65.96500 168.14000 ;
     RECT 65.82500 168.80000 65.96500 168.94000 ;
     RECT 66.10500 66.40000 66.24500 66.54000 ;
     RECT 66.10500 83.20000 66.24500 83.34000 ;
     RECT 66.10500 98.40000 66.24500 98.54000 ;
     RECT 66.10500 169.60000 66.24500 169.74000 ;
     RECT 66.10500 176.80000 66.24500 176.94000 ;
     RECT 66.38500 62.40000 66.52500 62.54000 ;
     RECT 66.38500 80.00000 66.52500 80.14000 ;
     RECT 66.38500 89.60000 66.52500 89.74000 ;
     RECT 66.38500 159.20000 66.52500 159.34000 ;
     RECT 66.66500 84.00000 66.80500 84.14000 ;
     RECT 66.66500 125.60000 66.80500 125.74000 ;
     RECT 66.94500 87.20000 67.08500 87.34000 ;
     RECT 66.94500 176.80000 67.08500 176.94000 ;
     RECT 66.94500 178.40000 67.08500 178.54000 ;
     RECT 67.22500 58.40000 67.36500 58.54000 ;
     RECT 67.22500 64.00000 67.36500 64.14000 ;
     RECT 67.22500 70.40000 67.36500 70.54000 ;
     RECT 67.22500 80.00000 67.36500 80.14000 ;
     RECT 67.22500 97.60000 67.36500 97.74000 ;
     RECT 67.22500 138.40000 67.36500 138.54000 ;
     RECT 67.22500 159.20000 67.36500 159.34000 ;
     RECT 67.22500 182.40000 67.36500 182.54000 ;
     RECT 67.22500 192.80000 67.36500 192.94000 ;
     RECT 67.22500 197.60000 67.36500 197.74000 ;
     RECT 67.50500 78.40000 67.64500 78.54000 ;
     RECT 67.50500 103.20000 67.64500 103.34000 ;
     RECT 67.50500 117.60000 67.64500 117.74000 ;
     RECT 67.78500 88.00000 67.92500 88.14000 ;
     RECT 67.78500 100.80000 67.92500 100.94000 ;
     RECT 68.06500 62.40000 68.20500 62.54000 ;
     RECT 68.06500 64.00000 68.20500 64.14000 ;
     RECT 68.06500 66.40000 68.20500 66.54000 ;
     RECT 68.06500 86.40000 68.20500 86.54000 ;
     RECT 68.06500 134.40000 68.20500 134.54000 ;
     RECT 68.06500 158.40000 68.20500 158.54000 ;
     RECT 68.06500 161.60000 68.20500 161.74000 ;
     RECT 68.34500 73.60000 68.48500 73.74000 ;
     RECT 68.34500 110.40000 68.48500 110.54000 ;
     RECT 68.34500 111.20000 68.48500 111.34000 ;
     RECT 68.34500 118.40000 68.48500 118.54000 ;
     RECT 68.34500 126.40000 68.48500 126.54000 ;
     RECT 68.34500 139.20000 68.48500 139.34000 ;
     RECT 68.34500 143.20000 68.48500 143.34000 ;
     RECT 68.34500 184.80000 68.48500 184.94000 ;
     RECT 68.62500 112.00000 68.76500 112.14000 ;
     RECT 68.90500 52.00000 69.04500 52.14000 ;
     RECT 68.90500 162.40000 69.04500 162.54000 ;
     RECT 69.18500 24.80000 69.32500 24.94000 ;
     RECT 69.18500 52.80000 69.32500 52.94000 ;
     RECT 69.18500 69.60000 69.32500 69.74000 ;
     RECT 69.18500 72.00000 69.32500 72.14000 ;
     RECT 69.18500 84.00000 69.32500 84.14000 ;
     RECT 69.18500 84.80000 69.32500 84.94000 ;
     RECT 69.18500 97.60000 69.32500 97.74000 ;
     RECT 69.18500 112.80000 69.32500 112.94000 ;
     RECT 69.18500 123.20000 69.32500 123.34000 ;
     RECT 69.18500 215.20000 69.32500 215.34000 ;
     RECT 69.46500 56.00000 69.60500 56.14000 ;
     RECT 69.46500 78.40000 69.60500 78.54000 ;
     RECT 69.46500 101.60000 69.60500 101.74000 ;
     RECT 69.46500 168.00000 69.60500 168.14000 ;
     RECT 69.74500 108.00000 69.88500 108.14000 ;
     RECT 69.74500 126.40000 69.88500 126.54000 ;
     RECT 69.74500 130.40000 69.88500 130.54000 ;
     RECT 69.74500 134.40000 69.88500 134.54000 ;
     RECT 69.74500 146.40000 69.88500 146.54000 ;
     RECT 69.74500 164.00000 69.88500 164.14000 ;
     RECT 69.74500 199.20000 69.88500 199.34000 ;
     RECT 70.02500 115.20000 70.16500 115.34000 ;
     RECT 70.02500 128.80000 70.16500 128.94000 ;
     RECT 70.30500 162.40000 70.44500 162.54000 ;
     RECT 70.58500 101.60000 70.72500 101.74000 ;
     RECT 70.58500 108.00000 70.72500 108.14000 ;
     RECT 70.58500 128.00000 70.72500 128.14000 ;
     RECT 70.58500 152.80000 70.72500 152.94000 ;
     RECT 70.86500 70.40000 71.00500 70.54000 ;
     RECT 70.86500 93.60000 71.00500 93.74000 ;
     RECT 70.86500 139.20000 71.00500 139.34000 ;
     RECT 70.86500 156.80000 71.00500 156.94000 ;
     RECT 70.86500 184.80000 71.00500 184.94000 ;
     RECT 71.14500 54.40000 71.28500 54.54000 ;
     RECT 71.14500 69.60000 71.28500 69.74000 ;
     RECT 71.14500 108.80000 71.28500 108.94000 ;
     RECT 71.42500 144.80000 71.56500 144.94000 ;
     RECT 71.42500 189.60000 71.56500 189.74000 ;
     RECT 71.42500 208.00000 71.56500 208.14000 ;
     RECT 71.70500 100.80000 71.84500 100.94000 ;
     RECT 71.70500 140.00000 71.84500 140.14000 ;
     RECT 71.70500 157.60000 71.84500 157.74000 ;
     RECT 71.70500 182.40000 71.84500 182.54000 ;
     RECT 71.98500 80.80000 72.12500 80.94000 ;
     RECT 71.98500 134.40000 72.12500 134.54000 ;
     RECT 71.98500 152.80000 72.12500 152.94000 ;
     RECT 71.99000 15.48000 72.13000 15.62000 ;
     RECT 71.99000 15.78000 72.13000 15.92000 ;
     RECT 71.99000 16.08000 72.13000 16.22000 ;
     RECT 71.99000 16.38000 72.13000 16.52000 ;
     RECT 71.99000 45.48000 72.13000 45.62000 ;
     RECT 71.99000 45.78000 72.13000 45.92000 ;
     RECT 71.99000 46.08000 72.13000 46.22000 ;
     RECT 71.99000 46.38000 72.13000 46.52000 ;
     RECT 71.99000 75.48000 72.13000 75.62000 ;
     RECT 71.99000 75.78000 72.13000 75.92000 ;
     RECT 71.99000 76.08000 72.13000 76.22000 ;
     RECT 71.99000 76.38000 72.13000 76.52000 ;
     RECT 71.99000 105.48000 72.13000 105.62000 ;
     RECT 71.99000 105.78000 72.13000 105.92000 ;
     RECT 71.99000 106.08000 72.13000 106.22000 ;
     RECT 71.99000 106.38000 72.13000 106.52000 ;
     RECT 71.99000 135.48000 72.13000 135.62000 ;
     RECT 71.99000 135.78000 72.13000 135.92000 ;
     RECT 71.99000 136.08000 72.13000 136.22000 ;
     RECT 71.99000 136.38000 72.13000 136.52000 ;
     RECT 71.99000 165.48000 72.13000 165.62000 ;
     RECT 71.99000 165.78000 72.13000 165.92000 ;
     RECT 71.99000 166.08000 72.13000 166.22000 ;
     RECT 71.99000 166.38000 72.13000 166.52000 ;
     RECT 71.99000 195.48000 72.13000 195.62000 ;
     RECT 71.99000 195.78000 72.13000 195.92000 ;
     RECT 71.99000 196.08000 72.13000 196.22000 ;
     RECT 71.99000 196.38000 72.13000 196.52000 ;
     RECT 72.26500 55.20000 72.40500 55.34000 ;
     RECT 72.26500 88.00000 72.40500 88.14000 ;
     RECT 72.26500 147.20000 72.40500 147.34000 ;
     RECT 72.26500 169.60000 72.40500 169.74000 ;
     RECT 72.54500 56.00000 72.68500 56.14000 ;
     RECT 72.54500 68.80000 72.68500 68.94000 ;
     RECT 72.54500 178.40000 72.68500 178.54000 ;
     RECT 72.54500 192.00000 72.68500 192.14000 ;
     RECT 72.82500 95.20000 72.96500 95.34000 ;
     RECT 72.82500 129.60000 72.96500 129.74000 ;
     RECT 72.82500 142.40000 72.96500 142.54000 ;
     RECT 72.82500 200.00000 72.96500 200.14000 ;
     RECT 73.10500 71.20000 73.24500 71.34000 ;
     RECT 73.10500 80.00000 73.24500 80.14000 ;
     RECT 73.10500 80.80000 73.24500 80.94000 ;
     RECT 73.38500 43.20000 73.52500 43.34000 ;
     RECT 73.38500 114.40000 73.52500 114.54000 ;
     RECT 73.66500 108.80000 73.80500 108.94000 ;
     RECT 73.66500 164.00000 73.80500 164.14000 ;
     RECT 73.66500 175.20000 73.80500 175.34000 ;
     RECT 73.94500 63.20000 74.08500 63.34000 ;
     RECT 73.94500 116.80000 74.08500 116.94000 ;
     RECT 73.94500 143.20000 74.08500 143.34000 ;
     RECT 73.94500 168.00000 74.08500 168.14000 ;
     RECT 73.94500 183.20000 74.08500 183.34000 ;
     RECT 74.22500 100.80000 74.36500 100.94000 ;
     RECT 74.22500 154.40000 74.36500 154.54000 ;
     RECT 74.22500 193.60000 74.36500 193.74000 ;
     RECT 74.50500 124.80000 74.64500 124.94000 ;
     RECT 74.50500 128.80000 74.64500 128.94000 ;
     RECT 74.50500 142.40000 74.64500 142.54000 ;
     RECT 74.78500 192.80000 74.92500 192.94000 ;
     RECT 75.06500 57.60000 75.20500 57.74000 ;
     RECT 75.06500 59.20000 75.20500 59.34000 ;
     RECT 75.06500 93.60000 75.20500 93.74000 ;
     RECT 75.34500 68.80000 75.48500 68.94000 ;
     RECT 75.34500 74.40000 75.48500 74.54000 ;
     RECT 75.34500 138.40000 75.48500 138.54000 ;
     RECT 75.34500 161.60000 75.48500 161.74000 ;
     RECT 75.34500 163.20000 75.48500 163.34000 ;
     RECT 75.62500 193.60000 75.76500 193.74000 ;
     RECT 76.18500 58.40000 76.32500 58.54000 ;
     RECT 76.18500 87.20000 76.32500 87.34000 ;
     RECT 76.18500 134.40000 76.32500 134.54000 ;
     RECT 76.18500 168.80000 76.32500 168.94000 ;
     RECT 76.46500 118.40000 76.60500 118.54000 ;
     RECT 76.46500 131.20000 76.60500 131.34000 ;
     RECT 76.74500 53.60000 76.88500 53.74000 ;
     RECT 76.74500 89.60000 76.88500 89.74000 ;
     RECT 76.74500 97.60000 76.88500 97.74000 ;
     RECT 76.74500 104.00000 76.88500 104.14000 ;
     RECT 76.74500 116.00000 76.88500 116.14000 ;
     RECT 76.74500 155.20000 76.88500 155.34000 ;
     RECT 76.74500 176.00000 76.88500 176.14000 ;
     RECT 76.74500 194.40000 76.88500 194.54000 ;
     RECT 77.02500 68.80000 77.16500 68.94000 ;
     RECT 77.02500 85.60000 77.16500 85.74000 ;
     RECT 77.02500 93.60000 77.16500 93.74000 ;
     RECT 77.02500 95.20000 77.16500 95.34000 ;
     RECT 77.02500 127.20000 77.16500 127.34000 ;
     RECT 77.02500 210.40000 77.16500 210.54000 ;
     RECT 77.30500 63.20000 77.44500 63.34000 ;
     RECT 77.30500 70.40000 77.44500 70.54000 ;
     RECT 77.30500 125.60000 77.44500 125.74000 ;
     RECT 77.30500 161.60000 77.44500 161.74000 ;
     RECT 77.58500 123.20000 77.72500 123.34000 ;
     RECT 77.86500 145.60000 78.00500 145.74000 ;
     RECT 77.86500 173.60000 78.00500 173.74000 ;
     RECT 78.14500 98.40000 78.28500 98.54000 ;
     RECT 78.14500 129.60000 78.28500 129.74000 ;
     RECT 78.14500 147.20000 78.28500 147.34000 ;
     RECT 78.14500 155.20000 78.28500 155.34000 ;
     RECT 78.14500 168.00000 78.28500 168.14000 ;
     RECT 78.42500 62.40000 78.56500 62.54000 ;
     RECT 78.42500 207.20000 78.56500 207.34000 ;
     RECT 78.70500 64.00000 78.84500 64.14000 ;
     RECT 78.98500 86.40000 79.12500 86.54000 ;
     RECT 78.98500 168.00000 79.12500 168.14000 ;
     RECT 78.98500 189.60000 79.12500 189.74000 ;
     RECT 79.26500 80.80000 79.40500 80.94000 ;
     RECT 79.26500 109.60000 79.40500 109.74000 ;
     RECT 79.26500 123.20000 79.40500 123.34000 ;
     RECT 79.54500 56.00000 79.68500 56.14000 ;
     RECT 79.54500 85.60000 79.68500 85.74000 ;
     RECT 79.54500 95.20000 79.68500 95.34000 ;
     RECT 79.54500 194.40000 79.68500 194.54000 ;
     RECT 79.54500 203.20000 79.68500 203.34000 ;
     RECT 79.82500 50.40000 79.96500 50.54000 ;
     RECT 79.82500 87.20000 79.96500 87.34000 ;
     RECT 79.82500 104.00000 79.96500 104.14000 ;
     RECT 79.82500 108.00000 79.96500 108.14000 ;
     RECT 79.82500 144.80000 79.96500 144.94000 ;
     RECT 79.82500 170.40000 79.96500 170.54000 ;
     RECT 79.82500 208.00000 79.96500 208.14000 ;
     RECT 80.10500 55.20000 80.24500 55.34000 ;
     RECT 80.10500 102.40000 80.24500 102.54000 ;
     RECT 80.10500 157.60000 80.24500 157.74000 ;
     RECT 80.10500 192.00000 80.24500 192.14000 ;
     RECT 80.10500 212.00000 80.24500 212.14000 ;
     RECT 80.38500 109.60000 80.52500 109.74000 ;
     RECT 80.38500 188.00000 80.52500 188.14000 ;
     RECT 80.66500 57.60000 80.80500 57.74000 ;
     RECT 80.66500 94.40000 80.80500 94.54000 ;
     RECT 80.66500 164.00000 80.80500 164.14000 ;
     RECT 80.66500 205.60000 80.80500 205.74000 ;
     RECT 80.94500 52.80000 81.08500 52.94000 ;
     RECT 80.94500 86.40000 81.08500 86.54000 ;
     RECT 80.94500 162.40000 81.08500 162.54000 ;
     RECT 80.94500 190.40000 81.08500 190.54000 ;
     RECT 81.22500 133.60000 81.36500 133.74000 ;
     RECT 81.50500 110.40000 81.64500 110.54000 ;
     RECT 81.50500 182.40000 81.64500 182.54000 ;
     RECT 81.50500 206.40000 81.64500 206.54000 ;
     RECT 81.78500 56.80000 81.92500 56.94000 ;
     RECT 81.78500 130.40000 81.92500 130.54000 ;
     RECT 81.78500 178.40000 81.92500 178.54000 ;
     RECT 82.06500 138.40000 82.20500 138.54000 ;
     RECT 82.06500 200.00000 82.20500 200.14000 ;
     RECT 82.34500 94.40000 82.48500 94.54000 ;
     RECT 82.34500 154.40000 82.48500 154.54000 ;
     RECT 82.34500 187.20000 82.48500 187.34000 ;
     RECT 82.34500 189.60000 82.48500 189.74000 ;
     RECT 82.62500 103.20000 82.76500 103.34000 ;
     RECT 82.62500 117.60000 82.76500 117.74000 ;
     RECT 82.62500 152.80000 82.76500 152.94000 ;
     RECT 82.62500 163.20000 82.76500 163.34000 ;
     RECT 82.62500 171.20000 82.76500 171.34000 ;
     RECT 82.62500 183.20000 82.76500 183.34000 ;
     RECT 82.90500 78.40000 83.04500 78.54000 ;
     RECT 82.90500 88.80000 83.04500 88.94000 ;
     RECT 82.90500 172.00000 83.04500 172.14000 ;
     RECT 82.90500 174.40000 83.04500 174.54000 ;
     RECT 83.18500 72.00000 83.32500 72.14000 ;
     RECT 83.18500 124.80000 83.32500 124.94000 ;
     RECT 83.18500 156.80000 83.32500 156.94000 ;
     RECT 83.18500 209.60000 83.32500 209.74000 ;
     RECT 83.46500 41.60000 83.60500 41.74000 ;
     RECT 83.74500 79.20000 83.88500 79.34000 ;
     RECT 84.02500 78.40000 84.16500 78.54000 ;
     RECT 84.02500 80.00000 84.16500 80.14000 ;
     RECT 84.02500 92.80000 84.16500 92.94000 ;
     RECT 84.02500 159.20000 84.16500 159.34000 ;
     RECT 84.02500 161.60000 84.16500 161.74000 ;
     RECT 84.02500 200.00000 84.16500 200.14000 ;
     RECT 84.30500 125.60000 84.44500 125.74000 ;
     RECT 84.30500 127.20000 84.44500 127.34000 ;
     RECT 84.30500 185.60000 84.44500 185.74000 ;
     RECT 84.58500 73.60000 84.72500 73.74000 ;
     RECT 84.58500 79.20000 84.72500 79.34000 ;
     RECT 84.86500 62.40000 85.00500 62.54000 ;
     RECT 84.86500 170.40000 85.00500 170.54000 ;
     RECT 85.14500 63.20000 85.28500 63.34000 ;
     RECT 85.14500 192.00000 85.28500 192.14000 ;
     RECT 85.14500 194.40000 85.28500 194.54000 ;
     RECT 85.42500 130.40000 85.56500 130.54000 ;
     RECT 85.42500 144.80000 85.56500 144.94000 ;
     RECT 85.42500 178.40000 85.56500 178.54000 ;
     RECT 85.70500 84.00000 85.84500 84.14000 ;
     RECT 85.70500 108.80000 85.84500 108.94000 ;
     RECT 85.70500 141.60000 85.84500 141.74000 ;
     RECT 85.70500 158.40000 85.84500 158.54000 ;
     RECT 85.70500 163.20000 85.84500 163.34000 ;
     RECT 85.70500 185.60000 85.84500 185.74000 ;
     RECT 85.70500 186.40000 85.84500 186.54000 ;
     RECT 85.98500 88.80000 86.12500 88.94000 ;
     RECT 85.98500 97.60000 86.12500 97.74000 ;
     RECT 85.98500 100.80000 86.12500 100.94000 ;
     RECT 85.98500 143.20000 86.12500 143.34000 ;
     RECT 85.98500 144.00000 86.12500 144.14000 ;
     RECT 86.26500 64.00000 86.40500 64.14000 ;
     RECT 86.26500 98.40000 86.40500 98.54000 ;
     RECT 86.26500 164.00000 86.40500 164.14000 ;
     RECT 86.26500 188.00000 86.40500 188.14000 ;
     RECT 86.54500 184.80000 86.68500 184.94000 ;
     RECT 86.82500 56.80000 86.96500 56.94000 ;
     RECT 86.82500 169.60000 86.96500 169.74000 ;
     RECT 86.82500 176.00000 86.96500 176.14000 ;
     RECT 87.10500 89.60000 87.24500 89.74000 ;
     RECT 87.10500 100.00000 87.24500 100.14000 ;
     RECT 87.10500 102.40000 87.24500 102.54000 ;
     RECT 87.10500 128.00000 87.24500 128.14000 ;
     RECT 87.10500 156.80000 87.24500 156.94000 ;
     RECT 87.10500 162.40000 87.24500 162.54000 ;
     RECT 87.38500 108.00000 87.52500 108.14000 ;
     RECT 87.38500 127.20000 87.52500 127.34000 ;
     RECT 87.38500 132.80000 87.52500 132.94000 ;
     RECT 87.38500 194.40000 87.52500 194.54000 ;
     RECT 87.66500 138.40000 87.80500 138.54000 ;
     RECT 87.94500 122.40000 88.08500 122.54000 ;
     RECT 87.94500 204.00000 88.08500 204.14000 ;
     RECT 88.22500 55.20000 88.36500 55.34000 ;
     RECT 88.22500 132.80000 88.36500 132.94000 ;
     RECT 88.50500 140.00000 88.64500 140.14000 ;
     RECT 88.50500 177.60000 88.64500 177.74000 ;
     RECT 88.50500 189.60000 88.64500 189.74000 ;
     RECT 88.50500 192.80000 88.64500 192.94000 ;
     RECT 88.78500 100.00000 88.92500 100.14000 ;
     RECT 89.06500 44.00000 89.20500 44.14000 ;
     RECT 89.06500 175.20000 89.20500 175.34000 ;
     RECT 89.62500 62.40000 89.76500 62.54000 ;
     RECT 89.62500 66.40000 89.76500 66.54000 ;
     RECT 89.62500 71.20000 89.76500 71.34000 ;
     RECT 89.62500 86.40000 89.76500 86.54000 ;
     RECT 89.62500 96.00000 89.76500 96.14000 ;
     RECT 89.62500 128.80000 89.76500 128.94000 ;
     RECT 89.62500 148.80000 89.76500 148.94000 ;
     RECT 89.62500 193.60000 89.76500 193.74000 ;
     RECT 89.62500 197.60000 89.76500 197.74000 ;
     RECT 89.62500 209.60000 89.76500 209.74000 ;
     RECT 89.90500 124.00000 90.04500 124.14000 ;
     RECT 89.90500 126.40000 90.04500 126.54000 ;
     RECT 90.46500 22.40000 90.60500 22.54000 ;
     RECT 90.46500 94.40000 90.60500 94.54000 ;
     RECT 90.46500 162.40000 90.60500 162.54000 ;
     RECT 90.46500 178.40000 90.60500 178.54000 ;
     RECT 90.74500 110.40000 90.88500 110.54000 ;
     RECT 90.74500 114.40000 90.88500 114.54000 ;
     RECT 90.74500 177.60000 90.88500 177.74000 ;
     RECT 91.02500 69.60000 91.16500 69.74000 ;
     RECT 91.02500 111.20000 91.16500 111.34000 ;
     RECT 91.02500 145.60000 91.16500 145.74000 ;
     RECT 91.02500 184.00000 91.16500 184.14000 ;
     RECT 91.02500 208.80000 91.16500 208.94000 ;
     RECT 91.30500 54.40000 91.44500 54.54000 ;
     RECT 91.30500 108.00000 91.44500 108.14000 ;
     RECT 91.30500 118.40000 91.44500 118.54000 ;
     RECT 91.30500 124.80000 91.44500 124.94000 ;
     RECT 91.30500 207.20000 91.44500 207.34000 ;
     RECT 91.58500 85.60000 91.72500 85.74000 ;
     RECT 91.58500 190.40000 91.72500 190.54000 ;
     RECT 91.58500 199.20000 91.72500 199.34000 ;
     RECT 91.86500 146.40000 92.00500 146.54000 ;
     RECT 91.86500 148.80000 92.00500 148.94000 ;
     RECT 91.86500 185.60000 92.00500 185.74000 ;
     RECT 92.14500 127.20000 92.28500 127.34000 ;
     RECT 92.14500 153.60000 92.28500 153.74000 ;
     RECT 92.14500 156.00000 92.28500 156.14000 ;
     RECT 92.70500 56.80000 92.84500 56.94000 ;
     RECT 92.70500 73.60000 92.84500 73.74000 ;
     RECT 92.70500 188.80000 92.84500 188.94000 ;
     RECT 92.70500 193.60000 92.84500 193.74000 ;
     RECT 92.98500 62.40000 93.12500 62.54000 ;
     RECT 92.98500 160.80000 93.12500 160.94000 ;
     RECT 93.26500 160.00000 93.40500 160.14000 ;
     RECT 93.54500 81.60000 93.68500 81.74000 ;
     RECT 93.54500 88.80000 93.68500 88.94000 ;
     RECT 93.54500 97.60000 93.68500 97.74000 ;
     RECT 93.54500 123.20000 93.68500 123.34000 ;
     RECT 93.54500 149.60000 93.68500 149.74000 ;
     RECT 93.54500 198.40000 93.68500 198.54000 ;
     RECT 93.82500 56.80000 93.96500 56.94000 ;
     RECT 93.82500 58.40000 93.96500 58.54000 ;
     RECT 93.82500 147.20000 93.96500 147.34000 ;
     RECT 94.10500 57.60000 94.24500 57.74000 ;
     RECT 94.10500 65.60000 94.24500 65.74000 ;
     RECT 94.10500 85.60000 94.24500 85.74000 ;
     RECT 94.10500 100.80000 94.24500 100.94000 ;
     RECT 94.10500 132.00000 94.24500 132.14000 ;
     RECT 94.38500 87.20000 94.52500 87.34000 ;
     RECT 94.38500 117.60000 94.52500 117.74000 ;
     RECT 94.38500 128.00000 94.52500 128.14000 ;
     RECT 94.66500 72.00000 94.80500 72.14000 ;
     RECT 95.22500 54.40000 95.36500 54.54000 ;
     RECT 95.22500 56.00000 95.36500 56.14000 ;
     RECT 95.22500 82.40000 95.36500 82.54000 ;
     RECT 95.50500 28.80000 95.64500 28.94000 ;
     RECT 95.50500 71.20000 95.64500 71.34000 ;
     RECT 95.50500 80.00000 95.64500 80.14000 ;
     RECT 95.50500 81.60000 95.64500 81.74000 ;
     RECT 95.50500 128.00000 95.64500 128.14000 ;
     RECT 95.50500 161.60000 95.64500 161.74000 ;
     RECT 95.78500 87.20000 95.92500 87.34000 ;
     RECT 95.78500 96.80000 95.92500 96.94000 ;
     RECT 95.78500 111.20000 95.92500 111.34000 ;
     RECT 95.78500 157.60000 95.92500 157.74000 ;
     RECT 95.78500 173.60000 95.92500 173.74000 ;
     RECT 96.06500 52.00000 96.20500 52.14000 ;
     RECT 96.34500 70.40000 96.48500 70.54000 ;
     RECT 96.62500 101.60000 96.76500 101.74000 ;
     RECT 96.90500 93.60000 97.04500 93.74000 ;
     RECT 96.90500 99.20000 97.04500 99.34000 ;
     RECT 96.90500 110.40000 97.04500 110.54000 ;
     RECT 96.90500 115.20000 97.04500 115.34000 ;
     RECT 97.74500 88.80000 97.88500 88.94000 ;
     RECT 97.74500 92.80000 97.88500 92.94000 ;
     RECT 97.74500 94.40000 97.88500 94.54000 ;
     RECT 97.74500 168.00000 97.88500 168.14000 ;
     RECT 98.58500 176.00000 98.72500 176.14000 ;
     RECT 99.14500 68.80000 99.28500 68.94000 ;
     RECT 99.14500 93.60000 99.28500 93.74000 ;
     RECT 99.14500 148.00000 99.28500 148.14000 ;
     RECT 99.42500 62.40000 99.56500 62.54000 ;
     RECT 99.42500 84.80000 99.56500 84.94000 ;
     RECT 99.42500 102.40000 99.56500 102.54000 ;
     RECT 99.42500 160.00000 99.56500 160.14000 ;
     RECT 99.70500 108.00000 99.84500 108.14000 ;
     RECT 99.70500 160.80000 99.84500 160.94000 ;
     RECT 99.99000 30.48000 100.13000 30.62000 ;
     RECT 99.99000 30.78000 100.13000 30.92000 ;
     RECT 99.99000 31.08000 100.13000 31.22000 ;
     RECT 99.99000 31.38000 100.13000 31.52000 ;
     RECT 99.99000 60.48000 100.13000 60.62000 ;
     RECT 99.99000 60.78000 100.13000 60.92000 ;
     RECT 99.99000 61.08000 100.13000 61.22000 ;
     RECT 99.99000 61.38000 100.13000 61.52000 ;
     RECT 99.99000 90.48000 100.13000 90.62000 ;
     RECT 99.99000 90.78000 100.13000 90.92000 ;
     RECT 99.99000 91.08000 100.13000 91.22000 ;
     RECT 99.99000 91.38000 100.13000 91.52000 ;
     RECT 99.99000 120.48000 100.13000 120.62000 ;
     RECT 99.99000 120.78000 100.13000 120.92000 ;
     RECT 99.99000 121.08000 100.13000 121.22000 ;
     RECT 99.99000 121.38000 100.13000 121.52000 ;
     RECT 99.99000 150.48000 100.13000 150.62000 ;
     RECT 99.99000 150.78000 100.13000 150.92000 ;
     RECT 99.99000 151.08000 100.13000 151.22000 ;
     RECT 99.99000 151.38000 100.13000 151.52000 ;
     RECT 99.99000 180.48000 100.13000 180.62000 ;
     RECT 99.99000 180.78000 100.13000 180.92000 ;
     RECT 99.99000 181.08000 100.13000 181.22000 ;
     RECT 99.99000 181.38000 100.13000 181.52000 ;
     RECT 100.26500 80.80000 100.40500 80.94000 ;
     RECT 100.54500 48.00000 100.68500 48.14000 ;
     RECT 100.54500 51.20000 100.68500 51.34000 ;
     RECT 100.82500 133.60000 100.96500 133.74000 ;
     RECT 101.10500 201.60000 101.24500 201.74000 ;
     RECT 101.38500 64.80000 101.52500 64.94000 ;
     RECT 101.38500 86.40000 101.52500 86.54000 ;
     RECT 101.38500 100.00000 101.52500 100.14000 ;
     RECT 101.66500 80.80000 101.80500 80.94000 ;
     RECT 101.66500 112.00000 101.80500 112.14000 ;
     RECT 101.94500 161.60000 102.08500 161.74000 ;
     RECT 101.94500 164.00000 102.08500 164.14000 ;
     RECT 102.22500 109.60000 102.36500 109.74000 ;
     RECT 102.50500 63.20000 102.64500 63.34000 ;
     RECT 102.50500 88.80000 102.64500 88.94000 ;
     RECT 102.50500 97.60000 102.64500 97.74000 ;
     RECT 102.78500 211.20000 102.92500 211.34000 ;
     RECT 103.34500 88.00000 103.48500 88.14000 ;
     RECT 103.34500 98.40000 103.48500 98.54000 ;
     RECT 103.62500 139.20000 103.76500 139.34000 ;
     RECT 103.62500 214.40000 103.76500 214.54000 ;
     RECT 103.90500 54.40000 104.04500 54.54000 ;
     RECT 103.90500 73.60000 104.04500 73.74000 ;
     RECT 104.18500 163.20000 104.32500 163.34000 ;
     RECT 104.46500 65.60000 104.60500 65.74000 ;
     RECT 104.74500 78.40000 104.88500 78.54000 ;
     RECT 104.74500 98.40000 104.88500 98.54000 ;
     RECT 105.02500 42.40000 105.16500 42.54000 ;
     RECT 105.30500 49.60000 105.44500 49.74000 ;
     RECT 105.58500 95.20000 105.72500 95.34000 ;
     RECT 105.58500 128.00000 105.72500 128.14000 ;
     RECT 105.58500 211.20000 105.72500 211.34000 ;
     RECT 105.86500 79.20000 106.00500 79.34000 ;
     RECT 106.14500 104.00000 106.28500 104.14000 ;
     RECT 106.14500 144.80000 106.28500 144.94000 ;
     RECT 106.14500 192.00000 106.28500 192.14000 ;
     RECT 106.98500 62.40000 107.12500 62.54000 ;
     RECT 107.54500 38.40000 107.68500 38.54000 ;
     RECT 107.82500 58.40000 107.96500 58.54000 ;
     RECT 107.82500 212.80000 107.96500 212.94000 ;
     RECT 108.38500 152.80000 108.52500 152.94000 ;
     RECT 108.66500 161.60000 108.80500 161.74000 ;
     RECT 109.22500 83.20000 109.36500 83.34000 ;
     RECT 109.50500 114.40000 109.64500 114.54000 ;
     RECT 109.78500 63.20000 109.92500 63.34000 ;
     RECT 111.46500 161.60000 111.60500 161.74000 ;
     RECT 111.74500 37.60000 111.88500 37.74000 ;
     RECT 112.02500 54.40000 112.16500 54.54000 ;
     RECT 112.02500 137.60000 112.16500 137.74000 ;
     RECT 112.58500 38.40000 112.72500 38.54000 ;
     RECT 112.86500 63.20000 113.00500 63.34000 ;
     RECT 113.42500 4.00000 113.56500 4.14000 ;
     RECT 113.70500 102.40000 113.84500 102.54000 ;
     RECT 114.26500 62.40000 114.40500 62.54000 ;
     RECT 114.26500 202.40000 114.40500 202.54000 ;
     RECT 114.82500 36.80000 114.96500 36.94000 ;
     RECT 114.82500 68.80000 114.96500 68.94000 ;
     RECT 115.38500 86.40000 115.52500 86.54000 ;
     RECT 115.94500 108.80000 116.08500 108.94000 ;
     RECT 116.22500 78.40000 116.36500 78.54000 ;
     RECT 116.78500 159.20000 116.92500 159.34000 ;
     RECT 117.06500 83.20000 117.20500 83.34000 ;
     RECT 117.62500 57.60000 117.76500 57.74000 ;
     RECT 117.62500 88.00000 117.76500 88.14000 ;
     RECT 118.46500 35.20000 118.60500 35.34000 ;
     RECT 118.46500 72.00000 118.60500 72.14000 ;
     RECT 118.46500 96.00000 118.60500 96.14000 ;
     RECT 118.46500 152.80000 118.60500 152.94000 ;
     RECT 118.74500 174.40000 118.88500 174.54000 ;
     RECT 119.02500 24.00000 119.16500 24.14000 ;
     RECT 119.02500 156.80000 119.16500 156.94000 ;
     RECT 119.30500 70.40000 119.44500 70.54000 ;
     RECT 119.30500 161.60000 119.44500 161.74000 ;
     RECT 119.58500 84.00000 119.72500 84.14000 ;
     RECT 119.58500 101.60000 119.72500 101.74000 ;
     RECT 119.86500 118.40000 120.00500 118.54000 ;
     RECT 119.86500 123.20000 120.00500 123.34000 ;
     RECT 119.86500 128.80000 120.00500 128.94000 ;
     RECT 120.14500 54.40000 120.28500 54.54000 ;
     RECT 120.42500 164.00000 120.56500 164.14000 ;
     RECT 120.70500 130.40000 120.84500 130.54000 ;
     RECT 121.54500 177.60000 121.68500 177.74000 ;
     RECT 121.82500 28.00000 121.96500 28.14000 ;
     RECT 121.82500 176.80000 121.96500 176.94000 ;
     RECT 122.10500 4.80000 122.24500 4.94000 ;
     RECT 122.10500 62.40000 122.24500 62.54000 ;
     RECT 122.10500 64.00000 122.24500 64.14000 ;
     RECT 122.38500 65.60000 122.52500 65.74000 ;
     RECT 122.38500 66.40000 122.52500 66.54000 ;
     RECT 122.38500 104.00000 122.52500 104.14000 ;
     RECT 122.38500 112.80000 122.52500 112.94000 ;
     RECT 122.38500 143.20000 122.52500 143.34000 ;
     RECT 122.66500 115.20000 122.80500 115.34000 ;
     RECT 122.94500 138.40000 123.08500 138.54000 ;
     RECT 123.22500 88.80000 123.36500 88.94000 ;
     RECT 123.22500 108.00000 123.36500 108.14000 ;
     RECT 123.50500 52.00000 123.64500 52.14000 ;
     RECT 123.50500 112.00000 123.64500 112.14000 ;
     RECT 123.50500 128.00000 123.64500 128.14000 ;
     RECT 123.50500 160.80000 123.64500 160.94000 ;
     RECT 124.06500 62.40000 124.20500 62.54000 ;
     RECT 124.34500 64.80000 124.48500 64.94000 ;
     RECT 124.34500 141.60000 124.48500 141.74000 ;
     RECT 124.34500 157.60000 124.48500 157.74000 ;
     RECT 124.62500 64.00000 124.76500 64.14000 ;
     RECT 124.62500 94.40000 124.76500 94.54000 ;
     RECT 124.62500 176.80000 124.76500 176.94000 ;
     RECT 124.62500 198.40000 124.76500 198.54000 ;
     RECT 124.90500 42.40000 125.04500 42.54000 ;
     RECT 124.90500 77.60000 125.04500 77.74000 ;
     RECT 124.90500 86.40000 125.04500 86.54000 ;
     RECT 124.90500 133.60000 125.04500 133.74000 ;
     RECT 125.18500 55.20000 125.32500 55.34000 ;
     RECT 125.18500 63.20000 125.32500 63.34000 ;
     RECT 125.18500 64.80000 125.32500 64.94000 ;
     RECT 125.18500 99.20000 125.32500 99.34000 ;
     RECT 125.46500 68.80000 125.60500 68.94000 ;
     RECT 125.46500 79.20000 125.60500 79.34000 ;
     RECT 125.46500 85.60000 125.60500 85.74000 ;
     RECT 125.46500 89.60000 125.60500 89.74000 ;
     RECT 125.46500 103.20000 125.60500 103.34000 ;
     RECT 125.46500 109.60000 125.60500 109.74000 ;
     RECT 125.46500 115.20000 125.60500 115.34000 ;
     RECT 125.46500 117.60000 125.60500 117.74000 ;
     RECT 125.46500 139.20000 125.60500 139.34000 ;
     RECT 125.46500 140.00000 125.60500 140.14000 ;
     RECT 125.46500 148.00000 125.60500 148.14000 ;
     RECT 125.74500 128.80000 125.88500 128.94000 ;
     RECT 125.74500 140.80000 125.88500 140.94000 ;
     RECT 126.02500 36.80000 126.16500 36.94000 ;
     RECT 126.30500 115.20000 126.44500 115.34000 ;
     RECT 126.58500 52.00000 126.72500 52.14000 ;
     RECT 126.58500 126.40000 126.72500 126.54000 ;
     RECT 126.58500 154.40000 126.72500 154.54000 ;
     RECT 126.86500 100.00000 127.00500 100.14000 ;
     RECT 126.86500 159.20000 127.00500 159.34000 ;
     RECT 127.14500 37.60000 127.28500 37.74000 ;
     RECT 127.42500 48.00000 127.56500 48.14000 ;
     RECT 127.42500 139.20000 127.56500 139.34000 ;
     RECT 127.70500 82.40000 127.84500 82.54000 ;
     RECT 127.70500 87.20000 127.84500 87.34000 ;
     RECT 127.70500 88.80000 127.84500 88.94000 ;
     RECT 127.98500 69.60000 128.12500 69.74000 ;
     RECT 127.98500 132.80000 128.12500 132.94000 ;
     RECT 127.98500 146.40000 128.12500 146.54000 ;
     RECT 127.99000 15.48000 128.13000 15.62000 ;
     RECT 127.99000 15.78000 128.13000 15.92000 ;
     RECT 127.99000 16.08000 128.13000 16.22000 ;
     RECT 127.99000 16.38000 128.13000 16.52000 ;
     RECT 127.99000 45.48000 128.13000 45.62000 ;
     RECT 127.99000 45.78000 128.13000 45.92000 ;
     RECT 127.99000 46.08000 128.13000 46.22000 ;
     RECT 127.99000 46.38000 128.13000 46.52000 ;
     RECT 127.99000 75.48000 128.13000 75.62000 ;
     RECT 127.99000 75.78000 128.13000 75.92000 ;
     RECT 127.99000 76.08000 128.13000 76.22000 ;
     RECT 127.99000 76.38000 128.13000 76.52000 ;
     RECT 127.99000 105.48000 128.13000 105.62000 ;
     RECT 127.99000 105.78000 128.13000 105.92000 ;
     RECT 127.99000 106.08000 128.13000 106.22000 ;
     RECT 127.99000 106.38000 128.13000 106.52000 ;
     RECT 127.99000 135.48000 128.13000 135.62000 ;
     RECT 127.99000 135.78000 128.13000 135.92000 ;
     RECT 127.99000 136.08000 128.13000 136.22000 ;
     RECT 127.99000 136.38000 128.13000 136.52000 ;
     RECT 127.99000 165.48000 128.13000 165.62000 ;
     RECT 127.99000 165.78000 128.13000 165.92000 ;
     RECT 127.99000 166.08000 128.13000 166.22000 ;
     RECT 127.99000 166.38000 128.13000 166.52000 ;
     RECT 127.99000 195.48000 128.13000 195.62000 ;
     RECT 127.99000 195.78000 128.13000 195.92000 ;
     RECT 127.99000 196.08000 128.13000 196.22000 ;
     RECT 127.99000 196.38000 128.13000 196.52000 ;
     RECT 128.26500 71.20000 128.40500 71.34000 ;
     RECT 128.26500 129.60000 128.40500 129.74000 ;
     RECT 128.26500 178.40000 128.40500 178.54000 ;
     RECT 128.54500 35.20000 128.68500 35.34000 ;
     RECT 128.54500 98.40000 128.68500 98.54000 ;
     RECT 128.54500 125.60000 128.68500 125.74000 ;
     RECT 128.54500 142.40000 128.68500 142.54000 ;
     RECT 128.54500 145.60000 128.68500 145.74000 ;
     RECT 128.54500 147.20000 128.68500 147.34000 ;
     RECT 128.54500 168.00000 128.68500 168.14000 ;
     RECT 128.82500 48.00000 128.96500 48.14000 ;
     RECT 128.82500 48.80000 128.96500 48.94000 ;
     RECT 128.82500 132.00000 128.96500 132.14000 ;
     RECT 129.10500 140.80000 129.24500 140.94000 ;
     RECT 129.10500 156.00000 129.24500 156.14000 ;
     RECT 129.38500 58.40000 129.52500 58.54000 ;
     RECT 129.38500 71.20000 129.52500 71.34000 ;
     RECT 129.38500 104.00000 129.52500 104.14000 ;
     RECT 129.38500 142.40000 129.52500 142.54000 ;
     RECT 129.94500 64.80000 130.08500 64.94000 ;
     RECT 130.22500 113.60000 130.36500 113.74000 ;
     RECT 130.22500 161.60000 130.36500 161.74000 ;
     RECT 130.50500 53.60000 130.64500 53.74000 ;
     RECT 130.50500 146.40000 130.64500 146.54000 ;
     RECT 130.78500 52.00000 130.92500 52.14000 ;
     RECT 130.78500 54.40000 130.92500 54.54000 ;
     RECT 130.78500 70.40000 130.92500 70.54000 ;
     RECT 131.06500 57.60000 131.20500 57.74000 ;
     RECT 131.06500 88.00000 131.20500 88.14000 ;
     RECT 131.06500 100.00000 131.20500 100.14000 ;
     RECT 131.06500 144.80000 131.20500 144.94000 ;
     RECT 131.34500 67.20000 131.48500 67.34000 ;
     RECT 131.62500 63.20000 131.76500 63.34000 ;
     RECT 131.62500 72.80000 131.76500 72.94000 ;
     RECT 131.62500 102.40000 131.76500 102.54000 ;
     RECT 131.62500 126.40000 131.76500 126.54000 ;
     RECT 131.90500 138.40000 132.04500 138.54000 ;
     RECT 132.18500 55.20000 132.32500 55.34000 ;
     RECT 132.46500 27.20000 132.60500 27.34000 ;
     RECT 132.46500 84.80000 132.60500 84.94000 ;
     RECT 132.46500 88.80000 132.60500 88.94000 ;
     RECT 132.46500 161.60000 132.60500 161.74000 ;
     RECT 132.46500 164.00000 132.60500 164.14000 ;
     RECT 132.74500 48.00000 132.88500 48.14000 ;
     RECT 132.74500 48.80000 132.88500 48.94000 ;
     RECT 132.74500 89.60000 132.88500 89.74000 ;
     RECT 132.74500 97.60000 132.88500 97.74000 ;
     RECT 132.74500 99.20000 132.88500 99.34000 ;
     RECT 133.02500 138.40000 133.16500 138.54000 ;
     RECT 133.30500 36.80000 133.44500 36.94000 ;
     RECT 133.30500 72.00000 133.44500 72.14000 ;
     RECT 133.30500 100.80000 133.44500 100.94000 ;
     RECT 133.30500 116.00000 133.44500 116.14000 ;
     RECT 133.30500 130.40000 133.44500 130.54000 ;
     RECT 133.30500 144.00000 133.44500 144.14000 ;
     RECT 133.58500 73.60000 133.72500 73.74000 ;
     RECT 133.58500 78.40000 133.72500 78.54000 ;
     RECT 133.58500 81.60000 133.72500 81.74000 ;
     RECT 133.58500 95.20000 133.72500 95.34000 ;
     RECT 133.58500 145.60000 133.72500 145.74000 ;
     RECT 133.86500 48.80000 134.00500 48.94000 ;
     RECT 133.86500 88.00000 134.00500 88.14000 ;
     RECT 133.86500 134.40000 134.00500 134.54000 ;
     RECT 133.86500 153.60000 134.00500 153.74000 ;
     RECT 133.86500 160.00000 134.00500 160.14000 ;
     RECT 134.14500 34.40000 134.28500 34.54000 ;
     RECT 134.14500 38.40000 134.28500 38.54000 ;
     RECT 134.14500 50.40000 134.28500 50.54000 ;
     RECT 134.14500 143.20000 134.28500 143.34000 ;
     RECT 134.42500 49.60000 134.56500 49.74000 ;
     RECT 134.42500 51.20000 134.56500 51.34000 ;
     RECT 134.42500 58.40000 134.56500 58.54000 ;
     RECT 134.42500 72.80000 134.56500 72.94000 ;
     RECT 134.42500 130.40000 134.56500 130.54000 ;
     RECT 134.42500 149.60000 134.56500 149.74000 ;
     RECT 134.70500 43.20000 134.84500 43.34000 ;
     RECT 134.98500 55.20000 135.12500 55.34000 ;
     RECT 134.98500 56.00000 135.12500 56.14000 ;
     RECT 134.98500 162.40000 135.12500 162.54000 ;
     RECT 135.26500 143.20000 135.40500 143.34000 ;
     RECT 135.26500 164.00000 135.40500 164.14000 ;
     RECT 135.54500 111.20000 135.68500 111.34000 ;
     RECT 135.54500 152.80000 135.68500 152.94000 ;
     RECT 135.54500 169.60000 135.68500 169.74000 ;
     RECT 135.82500 147.20000 135.96500 147.34000 ;
     RECT 135.82500 168.80000 135.96500 168.94000 ;
     RECT 136.10500 64.80000 136.24500 64.94000 ;
     RECT 136.38500 143.20000 136.52500 143.34000 ;
     RECT 136.66500 55.20000 136.80500 55.34000 ;
     RECT 136.66500 71.20000 136.80500 71.34000 ;
     RECT 136.66500 163.20000 136.80500 163.34000 ;
     RECT 136.66500 170.40000 136.80500 170.54000 ;
     RECT 136.94500 28.80000 137.08500 28.94000 ;
     RECT 136.94500 32.80000 137.08500 32.94000 ;
     RECT 136.94500 59.20000 137.08500 59.34000 ;
     RECT 136.94500 80.00000 137.08500 80.14000 ;
     RECT 136.94500 80.80000 137.08500 80.94000 ;
     RECT 136.94500 83.20000 137.08500 83.34000 ;
     RECT 136.94500 95.20000 137.08500 95.34000 ;
     RECT 136.94500 156.80000 137.08500 156.94000 ;
     RECT 136.94500 174.40000 137.08500 174.54000 ;
     RECT 137.22500 18.40000 137.36500 18.54000 ;
     RECT 137.22500 19.20000 137.36500 19.34000 ;
     RECT 137.22500 85.60000 137.36500 85.74000 ;
     RECT 137.22500 158.40000 137.36500 158.54000 ;
     RECT 137.50500 56.00000 137.64500 56.14000 ;
     RECT 137.50500 104.00000 137.64500 104.14000 ;
     RECT 137.50500 112.80000 137.64500 112.94000 ;
     RECT 137.50500 145.60000 137.64500 145.74000 ;
     RECT 137.50500 192.00000 137.64500 192.14000 ;
     RECT 137.78500 80.00000 137.92500 80.14000 ;
     RECT 137.78500 114.40000 137.92500 114.54000 ;
     RECT 137.78500 156.80000 137.92500 156.94000 ;
     RECT 137.78500 160.80000 137.92500 160.94000 ;
     RECT 138.06500 22.40000 138.20500 22.54000 ;
     RECT 138.62500 41.60000 138.76500 41.74000 ;
     RECT 138.62500 44.00000 138.76500 44.14000 ;
     RECT 138.62500 48.00000 138.76500 48.14000 ;
     RECT 138.62500 68.80000 138.76500 68.94000 ;
     RECT 138.62500 72.00000 138.76500 72.14000 ;
     RECT 138.62500 112.00000 138.76500 112.14000 ;
     RECT 138.62500 178.40000 138.76500 178.54000 ;
     RECT 138.90500 18.40000 139.04500 18.54000 ;
     RECT 138.90500 63.20000 139.04500 63.34000 ;
     RECT 138.90500 118.40000 139.04500 118.54000 ;
     RECT 139.18500 33.60000 139.32500 33.74000 ;
     RECT 139.18500 148.80000 139.32500 148.94000 ;
     RECT 139.18500 157.60000 139.32500 157.74000 ;
     RECT 139.18500 164.00000 139.32500 164.14000 ;
     RECT 139.18500 183.20000 139.32500 183.34000 ;
     RECT 139.46500 10.40000 139.60500 10.54000 ;
     RECT 139.46500 64.80000 139.60500 64.94000 ;
     RECT 139.46500 67.20000 139.60500 67.34000 ;
     RECT 139.46500 134.40000 139.60500 134.54000 ;
     RECT 139.46500 145.60000 139.60500 145.74000 ;
     RECT 139.46500 168.00000 139.60500 168.14000 ;
     RECT 139.46500 178.40000 139.60500 178.54000 ;
     RECT 139.74500 93.60000 139.88500 93.74000 ;
     RECT 139.74500 100.80000 139.88500 100.94000 ;
     RECT 139.74500 141.60000 139.88500 141.74000 ;
     RECT 140.02500 49.60000 140.16500 49.74000 ;
     RECT 140.02500 89.60000 140.16500 89.74000 ;
     RECT 140.02500 116.80000 140.16500 116.94000 ;
     RECT 140.02500 160.80000 140.16500 160.94000 ;
     RECT 140.30500 9.60000 140.44500 9.74000 ;
     RECT 140.30500 124.80000 140.44500 124.94000 ;
     RECT 140.86500 128.00000 141.00500 128.14000 ;
     RECT 140.86500 137.60000 141.00500 137.74000 ;
     RECT 140.86500 160.80000 141.00500 160.94000 ;
     RECT 140.86500 164.00000 141.00500 164.14000 ;
     RECT 141.14500 69.60000 141.28500 69.74000 ;
     RECT 141.42500 52.80000 141.56500 52.94000 ;
     RECT 141.42500 53.60000 141.56500 53.74000 ;
     RECT 141.42500 94.40000 141.56500 94.54000 ;
     RECT 141.70500 156.80000 141.84500 156.94000 ;
     RECT 141.70500 176.00000 141.84500 176.14000 ;
     RECT 141.98500 78.40000 142.12500 78.54000 ;
     RECT 141.98500 127.20000 142.12500 127.34000 ;
     RECT 141.98500 152.80000 142.12500 152.94000 ;
     RECT 142.26500 29.60000 142.40500 29.74000 ;
     RECT 142.26500 84.00000 142.40500 84.14000 ;
     RECT 142.26500 88.00000 142.40500 88.14000 ;
     RECT 142.26500 104.00000 142.40500 104.14000 ;
     RECT 142.26500 124.00000 142.40500 124.14000 ;
     RECT 142.26500 159.20000 142.40500 159.34000 ;
     RECT 142.54500 24.80000 142.68500 24.94000 ;
     RECT 142.54500 39.20000 142.68500 39.34000 ;
     RECT 142.54500 40.80000 142.68500 40.94000 ;
     RECT 142.54500 64.00000 142.68500 64.14000 ;
     RECT 142.54500 64.80000 142.68500 64.94000 ;
     RECT 142.54500 79.20000 142.68500 79.34000 ;
     RECT 142.54500 96.80000 142.68500 96.94000 ;
     RECT 142.54500 131.20000 142.68500 131.34000 ;
     RECT 142.54500 138.40000 142.68500 138.54000 ;
     RECT 142.54500 174.40000 142.68500 174.54000 ;
     RECT 142.82500 36.80000 142.96500 36.94000 ;
     RECT 142.82500 53.60000 142.96500 53.74000 ;
     RECT 142.82500 87.20000 142.96500 87.34000 ;
     RECT 142.82500 126.40000 142.96500 126.54000 ;
     RECT 142.82500 128.80000 142.96500 128.94000 ;
     RECT 142.82500 171.20000 142.96500 171.34000 ;
     RECT 143.10500 44.00000 143.24500 44.14000 ;
     RECT 143.10500 88.80000 143.24500 88.94000 ;
     RECT 143.10500 176.80000 143.24500 176.94000 ;
     RECT 143.38500 64.00000 143.52500 64.14000 ;
     RECT 143.38500 72.00000 143.52500 72.14000 ;
     RECT 143.38500 98.40000 143.52500 98.54000 ;
     RECT 143.38500 102.40000 143.52500 102.54000 ;
     RECT 143.38500 149.60000 143.52500 149.74000 ;
     RECT 143.38500 156.80000 143.52500 156.94000 ;
     RECT 143.66500 74.40000 143.80500 74.54000 ;
     RECT 143.66500 146.40000 143.80500 146.54000 ;
     RECT 143.94500 39.20000 144.08500 39.34000 ;
     RECT 143.94500 77.60000 144.08500 77.74000 ;
     RECT 143.94500 79.20000 144.08500 79.34000 ;
     RECT 143.94500 108.80000 144.08500 108.94000 ;
     RECT 144.22500 32.80000 144.36500 32.94000 ;
     RECT 144.22500 48.00000 144.36500 48.14000 ;
     RECT 144.22500 162.40000 144.36500 162.54000 ;
     RECT 144.22500 176.80000 144.36500 176.94000 ;
     RECT 144.50500 49.60000 144.64500 49.74000 ;
     RECT 144.50500 56.00000 144.64500 56.14000 ;
     RECT 144.50500 69.60000 144.64500 69.74000 ;
     RECT 144.50500 124.80000 144.64500 124.94000 ;
     RECT 144.50500 139.20000 144.64500 139.34000 ;
     RECT 144.78500 102.40000 144.92500 102.54000 ;
     RECT 144.78500 122.40000 144.92500 122.54000 ;
     RECT 144.78500 144.80000 144.92500 144.94000 ;
     RECT 144.78500 164.00000 144.92500 164.14000 ;
     RECT 144.78500 170.40000 144.92500 170.54000 ;
     RECT 145.06500 65.60000 145.20500 65.74000 ;
     RECT 145.06500 88.80000 145.20500 88.94000 ;
     RECT 145.06500 148.00000 145.20500 148.14000 ;
     RECT 145.06500 169.60000 145.20500 169.74000 ;
     RECT 145.34500 57.60000 145.48500 57.74000 ;
     RECT 145.34500 68.00000 145.48500 68.14000 ;
     RECT 145.34500 84.80000 145.48500 84.94000 ;
     RECT 145.34500 111.20000 145.48500 111.34000 ;
     RECT 145.34500 175.20000 145.48500 175.34000 ;
     RECT 145.62500 23.20000 145.76500 23.34000 ;
     RECT 145.62500 62.40000 145.76500 62.54000 ;
     RECT 145.62500 74.40000 145.76500 74.54000 ;
     RECT 145.62500 84.00000 145.76500 84.14000 ;
     RECT 145.62500 128.00000 145.76500 128.14000 ;
     RECT 145.62500 164.00000 145.76500 164.14000 ;
     RECT 145.90500 12.80000 146.04500 12.94000 ;
     RECT 145.90500 81.60000 146.04500 81.74000 ;
     RECT 145.90500 86.40000 146.04500 86.54000 ;
     RECT 145.90500 94.40000 146.04500 94.54000 ;
     RECT 145.90500 155.20000 146.04500 155.34000 ;
     RECT 146.18500 26.40000 146.32500 26.54000 ;
     RECT 146.18500 108.00000 146.32500 108.14000 ;
     RECT 146.18500 115.20000 146.32500 115.34000 ;
     RECT 146.18500 122.40000 146.32500 122.54000 ;
     RECT 146.18500 138.40000 146.32500 138.54000 ;
     RECT 146.18500 142.40000 146.32500 142.54000 ;
     RECT 146.18500 148.00000 146.32500 148.14000 ;
     RECT 146.46500 51.20000 146.60500 51.34000 ;
     RECT 146.46500 80.80000 146.60500 80.94000 ;
     RECT 146.46500 129.60000 146.60500 129.74000 ;
     RECT 146.74500 25.60000 146.88500 25.74000 ;
     RECT 146.74500 36.00000 146.88500 36.14000 ;
     RECT 146.74500 41.60000 146.88500 41.74000 ;
     RECT 146.74500 157.60000 146.88500 157.74000 ;
     RECT 147.02500 5.60000 147.16500 5.74000 ;
     RECT 147.02500 62.40000 147.16500 62.54000 ;
     RECT 147.02500 68.80000 147.16500 68.94000 ;
     RECT 147.02500 85.60000 147.16500 85.74000 ;
     RECT 147.02500 125.60000 147.16500 125.74000 ;
     RECT 147.02500 140.00000 147.16500 140.14000 ;
     RECT 147.02500 143.20000 147.16500 143.34000 ;
     RECT 147.30500 27.20000 147.44500 27.34000 ;
     RECT 147.30500 35.20000 147.44500 35.34000 ;
     RECT 147.30500 40.00000 147.44500 40.14000 ;
     RECT 147.30500 70.40000 147.44500 70.54000 ;
     RECT 147.30500 88.80000 147.44500 88.94000 ;
     RECT 147.30500 112.80000 147.44500 112.94000 ;
     RECT 147.30500 147.20000 147.44500 147.34000 ;
     RECT 147.58500 108.00000 147.72500 108.14000 ;
     RECT 147.58500 116.80000 147.72500 116.94000 ;
     RECT 147.58500 153.60000 147.72500 153.74000 ;
     RECT 147.86500 57.60000 148.00500 57.74000 ;
     RECT 147.86500 88.00000 148.00500 88.14000 ;
     RECT 147.86500 94.40000 148.00500 94.54000 ;
     RECT 147.86500 116.00000 148.00500 116.14000 ;
     RECT 147.86500 124.80000 148.00500 124.94000 ;
     RECT 147.86500 157.60000 148.00500 157.74000 ;
     RECT 147.86500 168.80000 148.00500 168.94000 ;
     RECT 147.86500 172.80000 148.00500 172.94000 ;
     RECT 147.86500 184.80000 148.00500 184.94000 ;
     RECT 148.14500 73.60000 148.28500 73.74000 ;
     RECT 148.14500 79.20000 148.28500 79.34000 ;
     RECT 148.14500 156.00000 148.28500 156.14000 ;
     RECT 148.42500 66.40000 148.56500 66.54000 ;
     RECT 148.42500 93.60000 148.56500 93.74000 ;
     RECT 148.42500 117.60000 148.56500 117.74000 ;
     RECT 148.70500 164.00000 148.84500 164.14000 ;
     RECT 148.98500 24.80000 149.12500 24.94000 ;
     RECT 148.98500 63.20000 149.12500 63.34000 ;
     RECT 148.98500 88.80000 149.12500 88.94000 ;
     RECT 148.98500 139.20000 149.12500 139.34000 ;
     RECT 148.98500 160.80000 149.12500 160.94000 ;
     RECT 149.26500 22.40000 149.40500 22.54000 ;
     RECT 149.54500 36.00000 149.68500 36.14000 ;
     RECT 149.54500 88.00000 149.68500 88.14000 ;
     RECT 149.54500 92.80000 149.68500 92.94000 ;
     RECT 149.82500 86.40000 149.96500 86.54000 ;
     RECT 150.10500 160.80000 150.24500 160.94000 ;
     RECT 150.38500 48.00000 150.52500 48.14000 ;
     RECT 150.38500 51.20000 150.52500 51.34000 ;
     RECT 150.38500 70.40000 150.52500 70.54000 ;
     RECT 150.38500 131.20000 150.52500 131.34000 ;
     RECT 150.94500 100.00000 151.08500 100.14000 ;
     RECT 150.94500 116.00000 151.08500 116.14000 ;
     RECT 151.22500 43.20000 151.36500 43.34000 ;
     RECT 151.22500 71.20000 151.36500 71.34000 ;
     RECT 151.22500 77.60000 151.36500 77.74000 ;
     RECT 151.22500 89.60000 151.36500 89.74000 ;
     RECT 151.22500 96.00000 151.36500 96.14000 ;
     RECT 151.22500 112.00000 151.36500 112.14000 ;
     RECT 151.22500 156.80000 151.36500 156.94000 ;
     RECT 151.22500 194.40000 151.36500 194.54000 ;
     RECT 151.50500 78.40000 151.64500 78.54000 ;
     RECT 151.50500 140.80000 151.64500 140.94000 ;
     RECT 151.50500 154.40000 151.64500 154.54000 ;
     RECT 151.78500 100.00000 151.92500 100.14000 ;
     RECT 151.78500 129.60000 151.92500 129.74000 ;
     RECT 152.06500 52.00000 152.20500 52.14000 ;
     RECT 152.06500 148.80000 152.20500 148.94000 ;
     RECT 152.34500 156.80000 152.48500 156.94000 ;
     RECT 152.34500 159.20000 152.48500 159.34000 ;
     RECT 152.62500 26.40000 152.76500 26.54000 ;
     RECT 152.90500 36.80000 153.04500 36.94000 ;
     RECT 152.90500 64.00000 153.04500 64.14000 ;
     RECT 152.90500 71.20000 153.04500 71.34000 ;
     RECT 152.90500 78.40000 153.04500 78.54000 ;
     RECT 152.90500 128.00000 153.04500 128.14000 ;
     RECT 152.90500 158.40000 153.04500 158.54000 ;
     RECT 153.18500 134.40000 153.32500 134.54000 ;
     RECT 153.46500 110.40000 153.60500 110.54000 ;
     RECT 153.46500 157.60000 153.60500 157.74000 ;
     RECT 153.74500 33.60000 153.88500 33.74000 ;
     RECT 153.74500 42.40000 153.88500 42.54000 ;
     RECT 153.74500 84.00000 153.88500 84.14000 ;
     RECT 153.74500 116.80000 153.88500 116.94000 ;
     RECT 153.74500 141.60000 153.88500 141.74000 ;
     RECT 153.74500 142.40000 153.88500 142.54000 ;
     RECT 153.74500 152.80000 153.88500 152.94000 ;
     RECT 154.02500 13.60000 154.16500 13.74000 ;
     RECT 154.02500 25.60000 154.16500 25.74000 ;
     RECT 154.02500 34.40000 154.16500 34.54000 ;
     RECT 154.02500 62.40000 154.16500 62.54000 ;
     RECT 154.02500 98.40000 154.16500 98.54000 ;
     RECT 154.02500 100.80000 154.16500 100.94000 ;
     RECT 154.02500 114.40000 154.16500 114.54000 ;
     RECT 154.02500 126.40000 154.16500 126.54000 ;
     RECT 154.02500 140.80000 154.16500 140.94000 ;
     RECT 154.02500 176.80000 154.16500 176.94000 ;
     RECT 154.02500 192.00000 154.16500 192.14000 ;
     RECT 154.30500 17.60000 154.44500 17.74000 ;
     RECT 154.30500 24.80000 154.44500 24.94000 ;
     RECT 154.30500 69.60000 154.44500 69.74000 ;
     RECT 154.30500 73.60000 154.44500 73.74000 ;
     RECT 154.30500 88.80000 154.44500 88.94000 ;
     RECT 154.58500 18.40000 154.72500 18.54000 ;
     RECT 154.58500 144.00000 154.72500 144.14000 ;
     RECT 154.58500 144.80000 154.72500 144.94000 ;
     RECT 154.86500 95.20000 155.00500 95.34000 ;
     RECT 154.86500 127.20000 155.00500 127.34000 ;
     RECT 154.86500 140.80000 155.00500 140.94000 ;
     RECT 155.14500 14.40000 155.28500 14.54000 ;
     RECT 155.14500 27.20000 155.28500 27.34000 ;
     RECT 155.14500 141.60000 155.28500 141.74000 ;
     RECT 155.14500 145.60000 155.28500 145.74000 ;
     RECT 155.14500 148.00000 155.28500 148.14000 ;
     RECT 155.42500 38.40000 155.56500 38.54000 ;
     RECT 155.42500 65.60000 155.56500 65.74000 ;
     RECT 155.70500 12.00000 155.84500 12.14000 ;
     RECT 155.70500 67.20000 155.84500 67.34000 ;
     RECT 155.70500 78.40000 155.84500 78.54000 ;
     RECT 155.70500 115.20000 155.84500 115.34000 ;
     RECT 155.98500 19.20000 156.12500 19.34000 ;
     RECT 155.98500 62.40000 156.12500 62.54000 ;
     RECT 155.98500 152.80000 156.12500 152.94000 ;
     RECT 155.99000 30.48000 156.13000 30.62000 ;
     RECT 155.99000 30.78000 156.13000 30.92000 ;
     RECT 155.99000 31.08000 156.13000 31.22000 ;
     RECT 155.99000 31.38000 156.13000 31.52000 ;
     RECT 155.99000 60.48000 156.13000 60.62000 ;
     RECT 155.99000 60.78000 156.13000 60.92000 ;
     RECT 155.99000 61.08000 156.13000 61.22000 ;
     RECT 155.99000 61.38000 156.13000 61.52000 ;
     RECT 155.99000 90.48000 156.13000 90.62000 ;
     RECT 155.99000 90.78000 156.13000 90.92000 ;
     RECT 155.99000 91.08000 156.13000 91.22000 ;
     RECT 155.99000 91.38000 156.13000 91.52000 ;
     RECT 155.99000 120.48000 156.13000 120.62000 ;
     RECT 155.99000 120.78000 156.13000 120.92000 ;
     RECT 155.99000 121.08000 156.13000 121.22000 ;
     RECT 155.99000 121.38000 156.13000 121.52000 ;
     RECT 155.99000 150.48000 156.13000 150.62000 ;
     RECT 155.99000 150.78000 156.13000 150.92000 ;
     RECT 155.99000 151.08000 156.13000 151.22000 ;
     RECT 155.99000 151.38000 156.13000 151.52000 ;
     RECT 155.99000 180.48000 156.13000 180.62000 ;
     RECT 155.99000 180.78000 156.13000 180.92000 ;
     RECT 155.99000 181.08000 156.13000 181.22000 ;
     RECT 155.99000 181.38000 156.13000 181.52000 ;
     RECT 156.26500 7.20000 156.40500 7.34000 ;
     RECT 156.26500 51.20000 156.40500 51.34000 ;
     RECT 156.26500 169.60000 156.40500 169.74000 ;
     RECT 156.54500 6.40000 156.68500 6.54000 ;
     RECT 156.54500 48.00000 156.68500 48.14000 ;
     RECT 156.54500 78.40000 156.68500 78.54000 ;
     RECT 156.54500 127.20000 156.68500 127.34000 ;
     RECT 156.54500 145.60000 156.68500 145.74000 ;
     RECT 156.54500 156.00000 156.68500 156.14000 ;
     RECT 156.82500 13.60000 156.96500 13.74000 ;
     RECT 156.82500 19.20000 156.96500 19.34000 ;
     RECT 156.82500 20.80000 156.96500 20.94000 ;
     RECT 156.82500 36.80000 156.96500 36.94000 ;
     RECT 156.82500 68.00000 156.96500 68.14000 ;
     RECT 156.82500 99.20000 156.96500 99.34000 ;
     RECT 156.82500 108.80000 156.96500 108.94000 ;
     RECT 156.82500 118.40000 156.96500 118.54000 ;
     RECT 156.82500 122.40000 156.96500 122.54000 ;
     RECT 156.82500 130.40000 156.96500 130.54000 ;
     RECT 156.82500 133.60000 156.96500 133.74000 ;
     RECT 157.10500 63.20000 157.24500 63.34000 ;
     RECT 157.10500 64.80000 157.24500 64.94000 ;
     RECT 157.10500 65.60000 157.24500 65.74000 ;
     RECT 157.10500 80.00000 157.24500 80.14000 ;
     RECT 157.10500 100.00000 157.24500 100.14000 ;
     RECT 157.38500 124.80000 157.52500 124.94000 ;
     RECT 157.66500 99.20000 157.80500 99.34000 ;
     RECT 157.66500 133.60000 157.80500 133.74000 ;
     RECT 157.66500 162.40000 157.80500 162.54000 ;
     RECT 157.66500 177.60000 157.80500 177.74000 ;
     RECT 157.94500 24.00000 158.08500 24.14000 ;
     RECT 157.94500 28.80000 158.08500 28.94000 ;
     RECT 157.94500 32.80000 158.08500 32.94000 ;
     RECT 157.94500 80.80000 158.08500 80.94000 ;
     RECT 157.94500 109.60000 158.08500 109.74000 ;
     RECT 157.94500 132.80000 158.08500 132.94000 ;
     RECT 157.94500 140.00000 158.08500 140.14000 ;
     RECT 157.94500 160.80000 158.08500 160.94000 ;
     RECT 157.94500 161.60000 158.08500 161.74000 ;
     RECT 157.94500 168.00000 158.08500 168.14000 ;
     RECT 158.22500 88.00000 158.36500 88.14000 ;
     RECT 158.22500 94.40000 158.36500 94.54000 ;
     RECT 158.22500 103.20000 158.36500 103.34000 ;
     RECT 158.22500 114.40000 158.36500 114.54000 ;
     RECT 158.22500 116.00000 158.36500 116.14000 ;
     RECT 158.22500 141.60000 158.36500 141.74000 ;
     RECT 158.22500 174.40000 158.36500 174.54000 ;
     RECT 158.50500 97.60000 158.64500 97.74000 ;
     RECT 158.50500 147.20000 158.64500 147.34000 ;
     RECT 158.78500 53.60000 158.92500 53.74000 ;
     RECT 158.78500 96.00000 158.92500 96.14000 ;
     RECT 158.78500 112.00000 158.92500 112.14000 ;
     RECT 158.78500 156.00000 158.92500 156.14000 ;
     RECT 159.06500 73.60000 159.20500 73.74000 ;
     RECT 159.06500 139.20000 159.20500 139.34000 ;
     RECT 159.06500 144.80000 159.20500 144.94000 ;
     RECT 159.06500 148.80000 159.20500 148.94000 ;
     RECT 159.34500 24.80000 159.48500 24.94000 ;
     RECT 159.34500 29.60000 159.48500 29.74000 ;
     RECT 159.34500 32.80000 159.48500 32.94000 ;
     RECT 159.34500 57.60000 159.48500 57.74000 ;
     RECT 159.34500 74.40000 159.48500 74.54000 ;
     RECT 159.34500 113.60000 159.48500 113.74000 ;
     RECT 159.34500 119.20000 159.48500 119.34000 ;
     RECT 159.34500 129.60000 159.48500 129.74000 ;
     RECT 159.34500 153.60000 159.48500 153.74000 ;
     RECT 159.62500 25.60000 159.76500 25.74000 ;
     RECT 159.62500 85.60000 159.76500 85.74000 ;
     RECT 159.62500 87.20000 159.76500 87.34000 ;
     RECT 159.62500 109.60000 159.76500 109.74000 ;
     RECT 159.62500 124.80000 159.76500 124.94000 ;
     RECT 159.90500 35.20000 160.04500 35.34000 ;
     RECT 159.90500 44.00000 160.04500 44.14000 ;
     RECT 159.90500 81.60000 160.04500 81.74000 ;
     RECT 160.18500 28.00000 160.32500 28.14000 ;
     RECT 160.18500 80.00000 160.32500 80.14000 ;
     RECT 160.18500 92.80000 160.32500 92.94000 ;
     RECT 160.18500 118.40000 160.32500 118.54000 ;
     RECT 160.18500 122.40000 160.32500 122.54000 ;
     RECT 160.18500 160.80000 160.32500 160.94000 ;
     RECT 160.46500 25.60000 160.60500 25.74000 ;
     RECT 160.46500 143.20000 160.60500 143.34000 ;
     RECT 160.46500 157.60000 160.60500 157.74000 ;
     RECT 160.46500 160.00000 160.60500 160.14000 ;
     RECT 160.74500 49.60000 160.88500 49.74000 ;
     RECT 160.74500 68.00000 160.88500 68.14000 ;
     RECT 160.74500 102.40000 160.88500 102.54000 ;
     RECT 160.74500 117.60000 160.88500 117.74000 ;
     RECT 160.74500 163.20000 160.88500 163.34000 ;
     RECT 160.74500 169.60000 160.88500 169.74000 ;
     RECT 161.02500 22.40000 161.16500 22.54000 ;
     RECT 161.02500 36.00000 161.16500 36.14000 ;
     RECT 161.30500 42.40000 161.44500 42.54000 ;
     RECT 161.30500 53.60000 161.44500 53.74000 ;
     RECT 161.30500 56.00000 161.44500 56.14000 ;
     RECT 161.58500 28.00000 161.72500 28.14000 ;
     RECT 161.58500 33.60000 161.72500 33.74000 ;
     RECT 161.58500 49.60000 161.72500 49.74000 ;
     RECT 161.58500 59.20000 161.72500 59.34000 ;
     RECT 161.58500 68.80000 161.72500 68.94000 ;
     RECT 161.58500 77.60000 161.72500 77.74000 ;
     RECT 161.58500 85.60000 161.72500 85.74000 ;
     RECT 161.58500 130.40000 161.72500 130.54000 ;
     RECT 161.58500 169.60000 161.72500 169.74000 ;
     RECT 161.86500 51.20000 162.00500 51.34000 ;
     RECT 161.86500 131.20000 162.00500 131.34000 ;
     RECT 162.14500 44.00000 162.28500 44.14000 ;
     RECT 162.14500 50.40000 162.28500 50.54000 ;
     RECT 162.14500 153.60000 162.28500 153.74000 ;
     RECT 162.14500 154.40000 162.28500 154.54000 ;
     RECT 162.14500 158.40000 162.28500 158.54000 ;
     RECT 162.14500 163.20000 162.28500 163.34000 ;
     RECT 162.14500 164.00000 162.28500 164.14000 ;
     RECT 162.14500 170.40000 162.28500 170.54000 ;
     RECT 162.14500 172.80000 162.28500 172.94000 ;
     RECT 162.14500 176.80000 162.28500 176.94000 ;
     RECT 162.42500 56.80000 162.56500 56.94000 ;
     RECT 162.42500 71.20000 162.56500 71.34000 ;
     RECT 162.42500 108.00000 162.56500 108.14000 ;
     RECT 162.42500 109.60000 162.56500 109.74000 ;
     RECT 162.42500 111.20000 162.56500 111.34000 ;
     RECT 162.42500 112.80000 162.56500 112.94000 ;
     RECT 162.70500 143.20000 162.84500 143.34000 ;
     RECT 162.70500 155.20000 162.84500 155.34000 ;
     RECT 162.70500 168.80000 162.84500 168.94000 ;
     RECT 162.98500 52.80000 163.12500 52.94000 ;
     RECT 162.98500 82.40000 163.12500 82.54000 ;
     RECT 162.98500 132.80000 163.12500 132.94000 ;
     RECT 162.98500 138.40000 163.12500 138.54000 ;
     RECT 163.26500 35.20000 163.40500 35.34000 ;
     RECT 163.26500 36.80000 163.40500 36.94000 ;
     RECT 163.26500 39.20000 163.40500 39.34000 ;
     RECT 163.26500 126.40000 163.40500 126.54000 ;
     RECT 163.26500 127.20000 163.40500 127.34000 ;
     RECT 163.26500 171.20000 163.40500 171.34000 ;
     RECT 163.54500 72.80000 163.68500 72.94000 ;
     RECT 163.54500 85.60000 163.68500 85.74000 ;
     RECT 163.54500 108.00000 163.68500 108.14000 ;
     RECT 163.82500 29.60000 163.96500 29.74000 ;
     RECT 163.82500 112.80000 163.96500 112.94000 ;
     RECT 164.10500 48.00000 164.24500 48.14000 ;
     RECT 164.10500 49.60000 164.24500 49.74000 ;
     RECT 164.10500 96.00000 164.24500 96.14000 ;
     RECT 164.10500 131.20000 164.24500 131.34000 ;
     RECT 164.38500 33.60000 164.52500 33.74000 ;
     RECT 164.38500 40.80000 164.52500 40.94000 ;
     RECT 164.38500 87.20000 164.52500 87.34000 ;
     RECT 164.38500 99.20000 164.52500 99.34000 ;
     RECT 164.38500 104.00000 164.52500 104.14000 ;
     RECT 164.38500 156.00000 164.52500 156.14000 ;
     RECT 164.66500 81.60000 164.80500 81.74000 ;
     RECT 164.66500 145.60000 164.80500 145.74000 ;
     RECT 164.66500 148.00000 164.80500 148.14000 ;
     RECT 164.94500 24.00000 165.08500 24.14000 ;
     RECT 164.94500 109.60000 165.08500 109.74000 ;
     RECT 164.94500 144.00000 165.08500 144.14000 ;
     RECT 165.22500 72.80000 165.36500 72.94000 ;
     RECT 165.22500 94.40000 165.36500 94.54000 ;
     RECT 165.22500 152.80000 165.36500 152.94000 ;
     RECT 165.22500 176.80000 165.36500 176.94000 ;
     RECT 165.50500 19.20000 165.64500 19.34000 ;
     RECT 165.50500 37.60000 165.64500 37.74000 ;
     RECT 165.50500 63.20000 165.64500 63.34000 ;
     RECT 165.50500 98.40000 165.64500 98.54000 ;
     RECT 165.50500 125.60000 165.64500 125.74000 ;
     RECT 165.50500 162.40000 165.64500 162.54000 ;
     RECT 165.50500 174.40000 165.64500 174.54000 ;
     RECT 165.78500 64.00000 165.92500 64.14000 ;
     RECT 165.78500 77.60000 165.92500 77.74000 ;
     RECT 165.78500 96.80000 165.92500 96.94000 ;
     RECT 165.78500 123.20000 165.92500 123.34000 ;
     RECT 165.78500 140.00000 165.92500 140.14000 ;
     RECT 165.78500 156.80000 165.92500 156.94000 ;
     RECT 166.06500 80.00000 166.20500 80.14000 ;
     RECT 166.06500 81.60000 166.20500 81.74000 ;
     RECT 166.06500 100.80000 166.20500 100.94000 ;
     RECT 166.06500 112.80000 166.20500 112.94000 ;
     RECT 166.06500 140.80000 166.20500 140.94000 ;
     RECT 166.34500 55.20000 166.48500 55.34000 ;
     RECT 166.34500 56.80000 166.48500 56.94000 ;
     RECT 166.34500 59.20000 166.48500 59.34000 ;
     RECT 166.34500 78.40000 166.48500 78.54000 ;
     RECT 166.34500 83.20000 166.48500 83.34000 ;
     RECT 166.34500 116.00000 166.48500 116.14000 ;
     RECT 166.34500 131.20000 166.48500 131.34000 ;
     RECT 166.34500 159.20000 166.48500 159.34000 ;
     RECT 166.34500 178.40000 166.48500 178.54000 ;
     RECT 166.62500 64.00000 166.76500 64.14000 ;
     RECT 166.62500 87.20000 166.76500 87.34000 ;
     RECT 166.62500 88.00000 166.76500 88.14000 ;
     RECT 166.62500 155.20000 166.76500 155.34000 ;
     RECT 166.90500 65.60000 167.04500 65.74000 ;
     RECT 166.90500 68.00000 167.04500 68.14000 ;
     RECT 166.90500 176.00000 167.04500 176.14000 ;
     RECT 167.18500 4.80000 167.32500 4.94000 ;
     RECT 167.18500 68.80000 167.32500 68.94000 ;
     RECT 167.18500 100.00000 167.32500 100.14000 ;
     RECT 167.18500 140.80000 167.32500 140.94000 ;
     RECT 167.46500 116.00000 167.60500 116.14000 ;
     RECT 167.46500 116.80000 167.60500 116.94000 ;
     RECT 167.46500 128.80000 167.60500 128.94000 ;
     RECT 167.46500 157.60000 167.60500 157.74000 ;
     RECT 167.74500 56.80000 167.88500 56.94000 ;
     RECT 167.74500 115.20000 167.88500 115.34000 ;
     RECT 167.74500 132.00000 167.88500 132.14000 ;
     RECT 167.74500 139.20000 167.88500 139.34000 ;
     RECT 167.74500 161.60000 167.88500 161.74000 ;
     RECT 167.74500 168.00000 167.88500 168.14000 ;
     RECT 168.02500 19.20000 168.16500 19.34000 ;
     RECT 168.02500 54.40000 168.16500 54.54000 ;
     RECT 168.02500 71.20000 168.16500 71.34000 ;
     RECT 168.02500 72.80000 168.16500 72.94000 ;
     RECT 168.02500 130.40000 168.16500 130.54000 ;
     RECT 168.02500 148.80000 168.16500 148.94000 ;
     RECT 168.02500 156.80000 168.16500 156.94000 ;
     RECT 168.02500 179.20000 168.16500 179.34000 ;
     RECT 168.30500 28.00000 168.44500 28.14000 ;
     RECT 168.30500 72.00000 168.44500 72.14000 ;
     RECT 168.30500 99.20000 168.44500 99.34000 ;
     RECT 168.30500 155.20000 168.44500 155.34000 ;
     RECT 168.30500 172.00000 168.44500 172.14000 ;
     RECT 168.30500 189.60000 168.44500 189.74000 ;
     RECT 168.58500 95.20000 168.72500 95.34000 ;
     RECT 168.58500 137.60000 168.72500 137.74000 ;
     RECT 168.58500 173.60000 168.72500 173.74000 ;
     RECT 168.86500 19.20000 169.00500 19.34000 ;
     RECT 168.86500 72.80000 169.00500 72.94000 ;
     RECT 168.86500 163.20000 169.00500 163.34000 ;
     RECT 169.14500 100.80000 169.28500 100.94000 ;
     RECT 169.14500 115.20000 169.28500 115.34000 ;
     RECT 169.42500 29.60000 169.56500 29.74000 ;
     RECT 169.42500 66.40000 169.56500 66.54000 ;
     RECT 169.42500 71.20000 169.56500 71.34000 ;
     RECT 169.98500 48.00000 170.12500 48.14000 ;
     RECT 169.98500 70.40000 170.12500 70.54000 ;
     RECT 170.26500 124.00000 170.40500 124.14000 ;
     RECT 170.26500 126.40000 170.40500 126.54000 ;
     RECT 170.26500 149.60000 170.40500 149.74000 ;
     RECT 170.26500 159.20000 170.40500 159.34000 ;
     RECT 170.26500 169.60000 170.40500 169.74000 ;
     RECT 170.54500 113.60000 170.68500 113.74000 ;
     RECT 170.82500 26.40000 170.96500 26.54000 ;
     RECT 171.10500 28.80000 171.24500 28.94000 ;
     RECT 171.10500 38.40000 171.24500 38.54000 ;
     RECT 171.10500 40.00000 171.24500 40.14000 ;
     RECT 171.10500 87.20000 171.24500 87.34000 ;
     RECT 171.10500 144.80000 171.24500 144.94000 ;
     RECT 171.38500 10.40000 171.52500 10.54000 ;
     RECT 171.38500 24.80000 171.52500 24.94000 ;
     RECT 171.38500 64.80000 171.52500 64.94000 ;
     RECT 171.38500 66.40000 171.52500 66.54000 ;
     RECT 171.38500 101.60000 171.52500 101.74000 ;
     RECT 171.66500 72.00000 171.80500 72.14000 ;
     RECT 171.94500 21.60000 172.08500 21.74000 ;
     RECT 171.94500 77.60000 172.08500 77.74000 ;
     RECT 171.94500 117.60000 172.08500 117.74000 ;
     RECT 172.22500 93.60000 172.36500 93.74000 ;
     RECT 172.22500 148.00000 172.36500 148.14000 ;
     RECT 172.22500 154.40000 172.36500 154.54000 ;
     RECT 172.50500 34.40000 172.64500 34.54000 ;
     RECT 172.50500 128.00000 172.64500 128.14000 ;
     RECT 172.78500 14.40000 172.92500 14.54000 ;
     RECT 172.78500 38.40000 172.92500 38.54000 ;
     RECT 172.78500 68.00000 172.92500 68.14000 ;
     RECT 172.78500 168.00000 172.92500 168.14000 ;
     RECT 173.06500 40.80000 173.20500 40.94000 ;
     RECT 173.06500 88.80000 173.20500 88.94000 ;
     RECT 173.06500 97.60000 173.20500 97.74000 ;
     RECT 173.06500 143.20000 173.20500 143.34000 ;
     RECT 173.06500 152.80000 173.20500 152.94000 ;
     RECT 173.62500 23.20000 173.76500 23.34000 ;
     RECT 173.62500 48.00000 173.76500 48.14000 ;
     RECT 173.62500 56.80000 173.76500 56.94000 ;
     RECT 173.62500 62.40000 173.76500 62.54000 ;
     RECT 173.62500 63.20000 173.76500 63.34000 ;
     RECT 173.62500 113.60000 173.76500 113.74000 ;
     RECT 173.62500 118.40000 173.76500 118.54000 ;
     RECT 173.62500 146.40000 173.76500 146.54000 ;
     RECT 173.62500 154.40000 173.76500 154.54000 ;
     RECT 173.62500 174.40000 173.76500 174.54000 ;
     RECT 173.90500 44.00000 174.04500 44.14000 ;
     RECT 173.90500 55.20000 174.04500 55.34000 ;
     RECT 173.90500 65.60000 174.04500 65.74000 ;
     RECT 173.90500 109.60000 174.04500 109.74000 ;
     RECT 173.90500 148.00000 174.04500 148.14000 ;
     RECT 173.90500 158.40000 174.04500 158.54000 ;
     RECT 173.90500 184.80000 174.04500 184.94000 ;
     RECT 174.18500 56.00000 174.32500 56.14000 ;
     RECT 174.18500 108.00000 174.32500 108.14000 ;
     RECT 174.18500 139.20000 174.32500 139.34000 ;
     RECT 174.18500 160.00000 174.32500 160.14000 ;
     RECT 174.46500 144.00000 174.60500 144.14000 ;
     RECT 174.74500 102.40000 174.88500 102.54000 ;
     RECT 174.74500 140.80000 174.88500 140.94000 ;
     RECT 174.74500 168.80000 174.88500 168.94000 ;
     RECT 175.02500 26.40000 175.16500 26.54000 ;
     RECT 175.02500 33.60000 175.16500 33.74000 ;
     RECT 175.02500 34.40000 175.16500 34.54000 ;
     RECT 175.02500 51.20000 175.16500 51.34000 ;
     RECT 175.02500 80.00000 175.16500 80.14000 ;
     RECT 175.02500 142.40000 175.16500 142.54000 ;
     RECT 175.02500 148.80000 175.16500 148.94000 ;
     RECT 175.02500 171.20000 175.16500 171.34000 ;
     RECT 175.30500 123.20000 175.44500 123.34000 ;
     RECT 175.30500 140.00000 175.44500 140.14000 ;
     RECT 175.30500 156.80000 175.44500 156.94000 ;
     RECT 175.58500 40.00000 175.72500 40.14000 ;
     RECT 175.58500 42.40000 175.72500 42.54000 ;
     RECT 175.58500 92.80000 175.72500 92.94000 ;
     RECT 175.86500 63.20000 176.00500 63.34000 ;
     RECT 176.14500 97.60000 176.28500 97.74000 ;
     RECT 176.14500 133.60000 176.28500 133.74000 ;
     RECT 176.42500 96.80000 176.56500 96.94000 ;
     RECT 176.42500 108.80000 176.56500 108.94000 ;
     RECT 176.42500 117.60000 176.56500 117.74000 ;
     RECT 176.42500 162.40000 176.56500 162.54000 ;
     RECT 176.70500 18.40000 176.84500 18.54000 ;
     RECT 176.70500 25.60000 176.84500 25.74000 ;
     RECT 176.70500 65.60000 176.84500 65.74000 ;
     RECT 176.70500 84.80000 176.84500 84.94000 ;
     RECT 176.70500 86.40000 176.84500 86.54000 ;
     RECT 176.70500 104.00000 176.84500 104.14000 ;
     RECT 176.70500 144.00000 176.84500 144.14000 ;
     RECT 176.98500 118.40000 177.12500 118.54000 ;
     RECT 177.26500 28.00000 177.40500 28.14000 ;
     RECT 177.26500 101.60000 177.40500 101.74000 ;
     RECT 177.26500 116.80000 177.40500 116.94000 ;
     RECT 177.54500 52.80000 177.68500 52.94000 ;
     RECT 177.54500 143.20000 177.68500 143.34000 ;
     RECT 177.54500 160.80000 177.68500 160.94000 ;
     RECT 177.54500 161.60000 177.68500 161.74000 ;
     RECT 177.82500 34.40000 177.96500 34.54000 ;
     RECT 178.10500 138.40000 178.24500 138.54000 ;
     RECT 178.38500 126.40000 178.52500 126.54000 ;
     RECT 178.38500 162.40000 178.52500 162.54000 ;
     RECT 178.66500 36.00000 178.80500 36.14000 ;
     RECT 178.66500 79.20000 178.80500 79.34000 ;
     RECT 178.66500 112.00000 178.80500 112.14000 ;
     RECT 178.66500 144.80000 178.80500 144.94000 ;
     RECT 178.66500 145.60000 178.80500 145.74000 ;
     RECT 178.66500 164.00000 178.80500 164.14000 ;
     RECT 178.94500 9.60000 179.08500 9.74000 ;
     RECT 178.94500 51.20000 179.08500 51.34000 ;
     RECT 178.94500 93.60000 179.08500 93.74000 ;
     RECT 178.94500 116.80000 179.08500 116.94000 ;
     RECT 178.94500 138.40000 179.08500 138.54000 ;
     RECT 179.22500 18.40000 179.36500 18.54000 ;
     RECT 179.22500 43.20000 179.36500 43.34000 ;
     RECT 179.22500 64.80000 179.36500 64.94000 ;
     RECT 179.22500 168.00000 179.36500 168.14000 ;
     RECT 179.22500 185.60000 179.36500 185.74000 ;
     RECT 179.50500 28.80000 179.64500 28.94000 ;
     RECT 179.50500 40.80000 179.64500 40.94000 ;
     RECT 179.50500 41.60000 179.64500 41.74000 ;
     RECT 179.50500 42.40000 179.64500 42.54000 ;
     RECT 179.50500 95.20000 179.64500 95.34000 ;
     RECT 179.50500 99.20000 179.64500 99.34000 ;
     RECT 179.50500 110.40000 179.64500 110.54000 ;
     RECT 179.50500 140.00000 179.64500 140.14000 ;
     RECT 179.50500 146.40000 179.64500 146.54000 ;
     RECT 179.50500 154.40000 179.64500 154.54000 ;
     RECT 180.06500 74.40000 180.20500 74.54000 ;
     RECT 180.06500 130.40000 180.20500 130.54000 ;
     RECT 180.34500 99.20000 180.48500 99.34000 ;
     RECT 180.34500 108.80000 180.48500 108.94000 ;
     RECT 180.34500 111.20000 180.48500 111.34000 ;
     RECT 180.34500 112.00000 180.48500 112.14000 ;
     RECT 180.62500 57.60000 180.76500 57.74000 ;
     RECT 180.62500 170.40000 180.76500 170.54000 ;
     RECT 180.90500 70.40000 181.04500 70.54000 ;
     RECT 180.90500 88.80000 181.04500 88.94000 ;
     RECT 180.90500 89.60000 181.04500 89.74000 ;
     RECT 180.90500 92.80000 181.04500 92.94000 ;
     RECT 180.90500 96.00000 181.04500 96.14000 ;
     RECT 180.90500 104.00000 181.04500 104.14000 ;
     RECT 181.18500 68.80000 181.32500 68.94000 ;
     RECT 181.18500 143.20000 181.32500 143.34000 ;
     RECT 181.74500 41.60000 181.88500 41.74000 ;
     RECT 182.02500 111.20000 182.16500 111.34000 ;
     RECT 182.02500 125.60000 182.16500 125.74000 ;
     RECT 182.02500 128.80000 182.16500 128.94000 ;
     RECT 182.30500 20.80000 182.44500 20.94000 ;
     RECT 182.30500 51.20000 182.44500 51.34000 ;
     RECT 182.30500 57.60000 182.44500 57.74000 ;
     RECT 182.30500 83.20000 182.44500 83.34000 ;
     RECT 182.30500 95.20000 182.44500 95.34000 ;
     RECT 182.30500 156.00000 182.44500 156.14000 ;
     RECT 182.58500 66.40000 182.72500 66.54000 ;
     RECT 182.58500 68.80000 182.72500 68.94000 ;
     RECT 182.58500 77.60000 182.72500 77.74000 ;
     RECT 182.58500 103.20000 182.72500 103.34000 ;
     RECT 182.58500 141.60000 182.72500 141.74000 ;
     RECT 182.58500 145.60000 182.72500 145.74000 ;
     RECT 182.58500 153.60000 182.72500 153.74000 ;
     RECT 182.86500 13.60000 183.00500 13.74000 ;
     RECT 182.86500 96.00000 183.00500 96.14000 ;
     RECT 182.86500 131.20000 183.00500 131.34000 ;
     RECT 182.86500 169.60000 183.00500 169.74000 ;
     RECT 183.14500 26.40000 183.28500 26.54000 ;
     RECT 183.14500 37.60000 183.28500 37.74000 ;
     RECT 183.14500 64.00000 183.28500 64.14000 ;
     RECT 183.14500 72.00000 183.28500 72.14000 ;
     RECT 183.14500 100.00000 183.28500 100.14000 ;
     RECT 183.42500 27.20000 183.56500 27.34000 ;
     RECT 183.42500 130.40000 183.56500 130.54000 ;
     RECT 183.42500 148.80000 183.56500 148.94000 ;
     RECT 183.70500 112.80000 183.84500 112.94000 ;
     RECT 183.70500 132.80000 183.84500 132.94000 ;
     RECT 183.70500 156.80000 183.84500 156.94000 ;
     RECT 183.98500 80.00000 184.12500 80.14000 ;
     RECT 183.99000 15.48000 184.13000 15.62000 ;
     RECT 183.99000 15.78000 184.13000 15.92000 ;
     RECT 183.99000 16.08000 184.13000 16.22000 ;
     RECT 183.99000 16.38000 184.13000 16.52000 ;
     RECT 183.99000 45.48000 184.13000 45.62000 ;
     RECT 183.99000 45.78000 184.13000 45.92000 ;
     RECT 183.99000 46.08000 184.13000 46.22000 ;
     RECT 183.99000 46.38000 184.13000 46.52000 ;
     RECT 183.99000 75.48000 184.13000 75.62000 ;
     RECT 183.99000 75.78000 184.13000 75.92000 ;
     RECT 183.99000 76.08000 184.13000 76.22000 ;
     RECT 183.99000 76.38000 184.13000 76.52000 ;
     RECT 183.99000 105.48000 184.13000 105.62000 ;
     RECT 183.99000 105.78000 184.13000 105.92000 ;
     RECT 183.99000 106.08000 184.13000 106.22000 ;
     RECT 183.99000 106.38000 184.13000 106.52000 ;
     RECT 183.99000 135.48000 184.13000 135.62000 ;
     RECT 183.99000 135.78000 184.13000 135.92000 ;
     RECT 183.99000 136.08000 184.13000 136.22000 ;
     RECT 183.99000 136.38000 184.13000 136.52000 ;
     RECT 183.99000 165.48000 184.13000 165.62000 ;
     RECT 183.99000 165.78000 184.13000 165.92000 ;
     RECT 183.99000 166.08000 184.13000 166.22000 ;
     RECT 183.99000 166.38000 184.13000 166.52000 ;
     RECT 183.99000 195.48000 184.13000 195.62000 ;
     RECT 183.99000 195.78000 184.13000 195.92000 ;
     RECT 183.99000 196.08000 184.13000 196.22000 ;
     RECT 183.99000 196.38000 184.13000 196.52000 ;
     RECT 184.26500 39.20000 184.40500 39.34000 ;
     RECT 184.26500 132.00000 184.40500 132.14000 ;
     RECT 184.26500 140.00000 184.40500 140.14000 ;
     RECT 184.26500 148.00000 184.40500 148.14000 ;
     RECT 184.54500 48.80000 184.68500 48.94000 ;
     RECT 184.54500 64.00000 184.68500 64.14000 ;
     RECT 184.54500 133.60000 184.68500 133.74000 ;
     RECT 184.82500 34.40000 184.96500 34.54000 ;
     RECT 184.82500 43.20000 184.96500 43.34000 ;
     RECT 184.82500 54.40000 184.96500 54.54000 ;
     RECT 184.82500 64.80000 184.96500 64.94000 ;
     RECT 184.82500 124.00000 184.96500 124.14000 ;
     RECT 185.10500 78.40000 185.24500 78.54000 ;
     RECT 185.10500 104.00000 185.24500 104.14000 ;
     RECT 185.10500 159.20000 185.24500 159.34000 ;
     RECT 185.38500 8.00000 185.52500 8.14000 ;
     RECT 185.38500 68.80000 185.52500 68.94000 ;
     RECT 185.38500 70.40000 185.52500 70.54000 ;
     RECT 185.38500 79.20000 185.52500 79.34000 ;
     RECT 185.38500 84.00000 185.52500 84.14000 ;
     RECT 185.38500 102.40000 185.52500 102.54000 ;
     RECT 185.38500 108.80000 185.52500 108.94000 ;
     RECT 185.38500 110.40000 185.52500 110.54000 ;
     RECT 185.38500 126.40000 185.52500 126.54000 ;
     RECT 185.38500 132.80000 185.52500 132.94000 ;
     RECT 185.38500 144.80000 185.52500 144.94000 ;
     RECT 185.38500 158.40000 185.52500 158.54000 ;
     RECT 185.66500 73.60000 185.80500 73.74000 ;
     RECT 185.66500 74.40000 185.80500 74.54000 ;
     RECT 185.66500 100.80000 185.80500 100.94000 ;
     RECT 185.66500 140.80000 185.80500 140.94000 ;
     RECT 185.94500 35.20000 186.08500 35.34000 ;
     RECT 185.94500 144.00000 186.08500 144.14000 ;
     RECT 185.94500 147.20000 186.08500 147.34000 ;
     RECT 186.22500 71.20000 186.36500 71.34000 ;
     RECT 186.22500 117.60000 186.36500 117.74000 ;
     RECT 186.22500 172.00000 186.36500 172.14000 ;
     RECT 186.50500 48.00000 186.64500 48.14000 ;
     RECT 186.50500 111.20000 186.64500 111.34000 ;
     RECT 186.50500 113.60000 186.64500 113.74000 ;
     RECT 186.50500 123.20000 186.64500 123.34000 ;
     RECT 186.78500 141.60000 186.92500 141.74000 ;
     RECT 186.78500 144.80000 186.92500 144.94000 ;
     RECT 186.78500 162.40000 186.92500 162.54000 ;
     RECT 187.06500 92.80000 187.20500 92.94000 ;
     RECT 187.06500 97.60000 187.20500 97.74000 ;
     RECT 187.06500 171.20000 187.20500 171.34000 ;
     RECT 187.34500 48.80000 187.48500 48.94000 ;
     RECT 187.34500 53.60000 187.48500 53.74000 ;
     RECT 187.34500 54.40000 187.48500 54.54000 ;
     RECT 187.34500 73.60000 187.48500 73.74000 ;
     RECT 187.34500 111.20000 187.48500 111.34000 ;
     RECT 187.34500 149.60000 187.48500 149.74000 ;
     RECT 187.62500 18.40000 187.76500 18.54000 ;
     RECT 187.62500 68.80000 187.76500 68.94000 ;
     RECT 187.62500 109.60000 187.76500 109.74000 ;
     RECT 187.62500 124.80000 187.76500 124.94000 ;
     RECT 187.62500 125.60000 187.76500 125.74000 ;
     RECT 187.90500 24.80000 188.04500 24.94000 ;
     RECT 187.90500 49.60000 188.04500 49.74000 ;
     RECT 187.90500 64.00000 188.04500 64.14000 ;
     RECT 187.90500 72.00000 188.04500 72.14000 ;
     RECT 187.90500 92.80000 188.04500 92.94000 ;
     RECT 187.90500 146.40000 188.04500 146.54000 ;
     RECT 188.18500 11.20000 188.32500 11.34000 ;
     RECT 188.18500 24.00000 188.32500 24.14000 ;
     RECT 188.18500 68.00000 188.32500 68.14000 ;
     RECT 188.18500 131.20000 188.32500 131.34000 ;
     RECT 188.18500 183.20000 188.32500 183.34000 ;
     RECT 188.46500 36.80000 188.60500 36.94000 ;
     RECT 188.46500 67.20000 188.60500 67.34000 ;
     RECT 188.46500 133.60000 188.60500 133.74000 ;
     RECT 188.46500 140.00000 188.60500 140.14000 ;
     RECT 188.74500 88.80000 188.88500 88.94000 ;
     RECT 189.02500 24.80000 189.16500 24.94000 ;
     RECT 189.02500 147.20000 189.16500 147.34000 ;
     RECT 189.02500 173.60000 189.16500 173.74000 ;
     RECT 189.30500 28.00000 189.44500 28.14000 ;
     RECT 189.30500 42.40000 189.44500 42.54000 ;
     RECT 189.30500 144.80000 189.44500 144.94000 ;
     RECT 189.30500 160.00000 189.44500 160.14000 ;
     RECT 189.58500 80.80000 189.72500 80.94000 ;
     RECT 189.58500 117.60000 189.72500 117.74000 ;
     RECT 189.86500 24.00000 190.00500 24.14000 ;
     RECT 189.86500 68.00000 190.00500 68.14000 ;
     RECT 190.14500 52.80000 190.28500 52.94000 ;
     RECT 190.14500 139.20000 190.28500 139.34000 ;
     RECT 190.14500 140.80000 190.28500 140.94000 ;
     RECT 190.14500 148.00000 190.28500 148.14000 ;
     RECT 190.42500 13.60000 190.56500 13.74000 ;
     RECT 190.42500 103.20000 190.56500 103.34000 ;
     RECT 190.42500 130.40000 190.56500 130.54000 ;
     RECT 190.42500 144.80000 190.56500 144.94000 ;
     RECT 190.70500 116.80000 190.84500 116.94000 ;
     RECT 190.98500 19.20000 191.12500 19.34000 ;
     RECT 190.98500 100.80000 191.12500 100.94000 ;
     RECT 190.98500 108.00000 191.12500 108.14000 ;
     RECT 190.98500 112.00000 191.12500 112.14000 ;
     RECT 190.98500 138.40000 191.12500 138.54000 ;
     RECT 190.98500 156.00000 191.12500 156.14000 ;
     RECT 190.98500 160.80000 191.12500 160.94000 ;
     RECT 191.26500 32.80000 191.40500 32.94000 ;
     RECT 191.26500 50.40000 191.40500 50.54000 ;
     RECT 191.26500 52.00000 191.40500 52.14000 ;
     RECT 191.26500 83.20000 191.40500 83.34000 ;
     RECT 191.26500 87.20000 191.40500 87.34000 ;
     RECT 191.26500 94.40000 191.40500 94.54000 ;
     RECT 191.26500 118.40000 191.40500 118.54000 ;
     RECT 191.26500 127.20000 191.40500 127.34000 ;
     RECT 191.54500 33.60000 191.68500 33.74000 ;
     RECT 191.54500 53.60000 191.68500 53.74000 ;
     RECT 191.82500 56.80000 191.96500 56.94000 ;
     RECT 191.82500 66.40000 191.96500 66.54000 ;
     RECT 191.82500 128.00000 191.96500 128.14000 ;
     RECT 191.82500 164.00000 191.96500 164.14000 ;
     RECT 192.10500 108.00000 192.24500 108.14000 ;
     RECT 192.10500 118.40000 192.24500 118.54000 ;
     RECT 192.10500 138.40000 192.24500 138.54000 ;
     RECT 192.10500 169.60000 192.24500 169.74000 ;
     RECT 192.38500 109.60000 192.52500 109.74000 ;
     RECT 192.38500 129.60000 192.52500 129.74000 ;
     RECT 192.66500 64.80000 192.80500 64.94000 ;
     RECT 192.66500 85.60000 192.80500 85.74000 ;
     RECT 192.66500 88.80000 192.80500 88.94000 ;
     RECT 192.66500 93.60000 192.80500 93.74000 ;
     RECT 192.66500 142.40000 192.80500 142.54000 ;
     RECT 192.66500 177.60000 192.80500 177.74000 ;
     RECT 192.94500 42.40000 193.08500 42.54000 ;
     RECT 192.94500 57.60000 193.08500 57.74000 ;
     RECT 192.94500 81.60000 193.08500 81.74000 ;
     RECT 192.94500 127.20000 193.08500 127.34000 ;
     RECT 192.94500 140.00000 193.08500 140.14000 ;
     RECT 193.50500 32.80000 193.64500 32.94000 ;
     RECT 193.50500 64.80000 193.64500 64.94000 ;
     RECT 193.50500 108.00000 193.64500 108.14000 ;
     RECT 193.50500 160.00000 193.64500 160.14000 ;
     RECT 193.50500 184.80000 193.64500 184.94000 ;
     RECT 193.78500 63.20000 193.92500 63.34000 ;
     RECT 193.78500 69.60000 193.92500 69.74000 ;
     RECT 194.06500 12.80000 194.20500 12.94000 ;
     RECT 194.06500 40.00000 194.20500 40.14000 ;
     RECT 194.06500 88.80000 194.20500 88.94000 ;
     RECT 194.06500 115.20000 194.20500 115.34000 ;
     RECT 194.06500 129.60000 194.20500 129.74000 ;
     RECT 194.06500 157.60000 194.20500 157.74000 ;
     RECT 194.34500 68.00000 194.48500 68.14000 ;
     RECT 194.34500 78.40000 194.48500 78.54000 ;
     RECT 194.34500 104.00000 194.48500 104.14000 ;
     RECT 194.34500 130.40000 194.48500 130.54000 ;
     RECT 194.34500 153.60000 194.48500 153.74000 ;
     RECT 194.34500 163.20000 194.48500 163.34000 ;
     RECT 194.62500 49.60000 194.76500 49.74000 ;
     RECT 194.62500 80.00000 194.76500 80.14000 ;
     RECT 194.62500 123.20000 194.76500 123.34000 ;
     RECT 194.62500 126.40000 194.76500 126.54000 ;
     RECT 194.90500 128.00000 195.04500 128.14000 ;
     RECT 195.18500 23.20000 195.32500 23.34000 ;
     RECT 195.18500 74.40000 195.32500 74.54000 ;
     RECT 195.18500 80.80000 195.32500 80.94000 ;
     RECT 195.18500 170.40000 195.32500 170.54000 ;
     RECT 195.46500 40.00000 195.60500 40.14000 ;
     RECT 195.46500 97.60000 195.60500 97.74000 ;
     RECT 195.46500 144.00000 195.60500 144.14000 ;
     RECT 195.46500 152.80000 195.60500 152.94000 ;
     RECT 195.74500 104.00000 195.88500 104.14000 ;
     RECT 196.02500 102.40000 196.16500 102.54000 ;
     RECT 196.02500 129.60000 196.16500 129.74000 ;
     RECT 196.02500 143.20000 196.16500 143.34000 ;
     RECT 196.02500 156.80000 196.16500 156.94000 ;
     RECT 196.02500 161.60000 196.16500 161.74000 ;
     RECT 196.02500 169.60000 196.16500 169.74000 ;
     RECT 196.30500 48.00000 196.44500 48.14000 ;
     RECT 196.30500 66.40000 196.44500 66.54000 ;
     RECT 196.30500 99.20000 196.44500 99.34000 ;
     RECT 196.30500 116.00000 196.44500 116.14000 ;
     RECT 196.30500 119.20000 196.44500 119.34000 ;
     RECT 196.58500 19.20000 196.72500 19.34000 ;
     RECT 196.58500 22.40000 196.72500 22.54000 ;
     RECT 196.58500 38.40000 196.72500 38.54000 ;
     RECT 196.58500 92.80000 196.72500 92.94000 ;
     RECT 196.86500 73.60000 197.00500 73.74000 ;
     RECT 196.86500 108.80000 197.00500 108.94000 ;
     RECT 196.86500 110.40000 197.00500 110.54000 ;
     RECT 197.14500 12.00000 197.28500 12.14000 ;
     RECT 197.14500 51.20000 197.28500 51.34000 ;
     RECT 197.14500 93.60000 197.28500 93.74000 ;
     RECT 197.14500 168.00000 197.28500 168.14000 ;
     RECT 197.42500 79.20000 197.56500 79.34000 ;
     RECT 197.42500 158.40000 197.56500 158.54000 ;
     RECT 198.26500 111.20000 198.40500 111.34000 ;
     RECT 198.54500 57.60000 198.68500 57.74000 ;
     RECT 198.54500 162.40000 198.68500 162.54000 ;
     RECT 199.38500 115.20000 199.52500 115.34000 ;
     RECT 199.66500 8.00000 199.80500 8.14000 ;
     RECT 199.66500 40.80000 199.80500 40.94000 ;
     RECT 199.66500 81.60000 199.80500 81.74000 ;
     RECT 199.66500 96.00000 199.80500 96.14000 ;
     RECT 199.66500 113.60000 199.80500 113.74000 ;
     RECT 199.66500 117.60000 199.80500 117.74000 ;
     RECT 199.66500 141.60000 199.80500 141.74000 ;
     RECT 199.94500 56.00000 200.08500 56.14000 ;
     RECT 200.22500 58.40000 200.36500 58.54000 ;
     RECT 200.50500 70.40000 200.64500 70.54000 ;
     RECT 200.50500 124.80000 200.64500 124.94000 ;
     RECT 200.78500 72.80000 200.92500 72.94000 ;
     RECT 200.78500 128.80000 200.92500 128.94000 ;
     RECT 200.78500 160.00000 200.92500 160.14000 ;
     RECT 201.06500 124.00000 201.20500 124.14000 ;
     RECT 201.62500 85.60000 201.76500 85.74000 ;
     RECT 201.62500 116.00000 201.76500 116.14000 ;
     RECT 201.62500 152.80000 201.76500 152.94000 ;
     RECT 202.18500 93.60000 202.32500 93.74000 ;
     RECT 202.46500 38.40000 202.60500 38.54000 ;
     RECT 202.46500 176.80000 202.60500 176.94000 ;
     RECT 202.74500 40.00000 202.88500 40.14000 ;
     RECT 203.30500 101.60000 203.44500 101.74000 ;
     RECT 203.58500 145.60000 203.72500 145.74000 ;
     RECT 203.86500 63.20000 204.00500 63.34000 ;
     RECT 204.14500 92.80000 204.28500 92.94000 ;
     RECT 204.70500 112.80000 204.84500 112.94000 ;
     RECT 204.98500 37.60000 205.12500 37.74000 ;
     RECT 204.98500 176.00000 205.12500 176.14000 ;
     RECT 205.26500 12.80000 205.40500 12.94000 ;
     RECT 205.54500 92.80000 205.68500 92.94000 ;
     RECT 205.54500 127.20000 205.68500 127.34000 ;
     RECT 205.54500 188.80000 205.68500 188.94000 ;
     RECT 205.82500 144.00000 205.96500 144.14000 ;
     RECT 206.10500 164.00000 206.24500 164.14000 ;
     RECT 206.38500 78.40000 206.52500 78.54000 ;
     RECT 206.94500 97.60000 207.08500 97.74000 ;
     RECT 207.22500 180.00000 207.36500 180.14000 ;
     RECT 207.78500 103.20000 207.92500 103.34000 ;
     RECT 207.78500 131.20000 207.92500 131.34000 ;
     RECT 208.06500 87.20000 208.20500 87.34000 ;
     RECT 208.06500 132.80000 208.20500 132.94000 ;
     RECT 208.34500 64.00000 208.48500 64.14000 ;
     RECT 208.62500 24.80000 208.76500 24.94000 ;
     RECT 208.62500 88.80000 208.76500 88.94000 ;
     RECT 208.62500 95.20000 208.76500 95.34000 ;
     RECT 208.90500 142.40000 209.04500 142.54000 ;
     RECT 210.02500 4.00000 210.16500 4.14000 ;
     RECT 210.86500 102.40000 211.00500 102.54000 ;
    LAYER via7 ;
     RECT 13.49500 173.47000 13.89500 173.87000 ;
     RECT 15.09500 139.87000 15.49500 140.27000 ;
     RECT 15.89500 127.07000 16.29500 127.47000 ;
     RECT 16.69500 88.67000 17.09500 89.07000 ;
     RECT 16.69500 109.47000 17.09500 109.87000 ;
     RECT 16.69500 134.27000 17.09500 134.67000 ;
     RECT 17.49500 110.27000 17.89500 110.67000 ;
     RECT 17.49500 130.27000 17.89500 130.67000 ;
     RECT 17.49500 171.07000 17.89500 171.47000 ;
     RECT 18.29500 163.87000 18.69500 164.27000 ;
     RECT 19.09500 35.07000 19.49500 35.47000 ;
     RECT 19.09500 99.87000 19.49500 100.27000 ;
     RECT 19.09500 139.07000 19.49500 139.47000 ;
     RECT 19.09500 155.07000 19.49500 155.47000 ;
     RECT 21.49500 43.07000 21.89500 43.47000 ;
     RECT 21.49500 92.67000 21.89500 93.07000 ;
     RECT 22.29500 93.47000 22.69500 93.87000 ;
     RECT 22.29500 103.87000 22.69500 104.27000 ;
     RECT 22.29500 114.27000 22.69500 114.67000 ;
     RECT 22.29500 142.27000 22.69500 142.67000 ;
     RECT 23.09500 38.27000 23.49500 38.67000 ;
     RECT 23.09500 78.27000 23.49500 78.67000 ;
     RECT 23.09500 103.07000 23.49500 103.47000 ;
     RECT 23.89500 56.67000 24.29500 57.07000 ;
     RECT 23.89500 74.27000 24.29500 74.67000 ;
     RECT 23.89500 85.47000 24.29500 85.87000 ;
     RECT 23.89500 127.87000 24.29500 128.27000 ;
     RECT 23.89500 139.07000 24.29500 139.47000 ;
     RECT 23.89500 163.87000 24.29500 164.27000 ;
     RECT 24.69500 70.27000 25.09500 70.67000 ;
     RECT 24.69500 93.47000 25.09500 93.87000 ;
     RECT 24.69500 178.27000 25.09500 178.67000 ;
     RECT 24.69500 183.07000 25.09500 183.47000 ;
     RECT 25.49500 103.07000 25.89500 103.47000 ;
     RECT 25.49500 128.67000 25.89500 129.07000 ;
     RECT 25.49500 145.47000 25.89500 145.87000 ;
     RECT 25.49500 176.67000 25.89500 177.07000 ;
     RECT 26.29500 85.47000 26.69500 85.87000 ;
     RECT 26.29500 103.87000 26.69500 104.27000 ;
     RECT 26.29500 115.07000 26.69500 115.47000 ;
     RECT 26.29500 123.87000 26.69500 124.27000 ;
     RECT 26.29500 143.07000 26.69500 143.47000 ;
     RECT 26.29500 153.47000 26.69500 153.87000 ;
     RECT 26.29500 172.67000 26.69500 173.07000 ;
     RECT 27.09500 109.47000 27.49500 109.87000 ;
     RECT 27.09500 159.07000 27.49500 159.47000 ;
     RECT 27.09500 160.67000 27.49500 161.07000 ;
     RECT 27.09500 174.27000 27.49500 174.67000 ;
     RECT 27.89500 62.27000 28.29500 62.67000 ;
     RECT 27.89500 79.07000 28.29500 79.47000 ;
     RECT 27.89500 111.87000 28.29500 112.27000 ;
     RECT 27.89500 128.67000 28.29500 129.07000 ;
     RECT 27.89500 153.47000 28.29500 153.87000 ;
     RECT 27.89500 193.47000 28.29500 193.87000 ;
     RECT 28.69500 59.07000 29.09500 59.47000 ;
     RECT 28.69500 71.87000 29.09500 72.27000 ;
     RECT 28.69500 92.67000 29.09500 93.07000 ;
     RECT 28.69500 108.67000 29.09500 109.07000 ;
     RECT 28.69500 126.27000 29.09500 126.67000 ;
     RECT 28.69500 162.27000 29.09500 162.67000 ;
     RECT 28.69500 168.67000 29.09500 169.07000 ;
     RECT 28.69500 194.27000 29.09500 194.67000 ;
     RECT 29.49500 73.47000 29.89500 73.87000 ;
     RECT 29.49500 98.27000 29.89500 98.67000 ;
     RECT 29.49500 153.47000 29.89500 153.87000 ;
     RECT 29.49500 170.27000 29.89500 170.67000 ;
     RECT 29.49500 172.67000 29.89500 173.07000 ;
     RECT 29.49500 202.27000 29.89500 202.67000 ;
     RECT 30.29500 72.67000 30.69500 73.07000 ;
     RECT 30.29500 94.27000 30.69500 94.67000 ;
     RECT 30.29500 139.07000 30.69500 139.47000 ;
     RECT 30.29500 141.47000 30.69500 141.87000 ;
     RECT 30.29500 173.47000 30.69500 173.87000 ;
     RECT 30.29500 187.07000 30.69500 187.47000 ;
     RECT 31.09500 68.67000 31.49500 69.07000 ;
     RECT 31.09500 83.87000 31.49500 84.27000 ;
     RECT 31.09500 114.27000 31.49500 114.67000 ;
     RECT 31.09500 123.07000 31.49500 123.47000 ;
     RECT 31.09500 160.67000 31.49500 161.07000 ;
     RECT 31.09500 163.87000 31.49500 164.27000 ;
     RECT 31.09500 171.07000 31.49500 171.47000 ;
     RECT 31.09500 183.87000 31.49500 184.27000 ;
     RECT 31.09500 191.87000 31.49500 192.27000 ;
     RECT 31.89500 55.87000 32.29500 56.27000 ;
     RECT 31.89500 67.07000 32.29500 67.47000 ;
     RECT 31.89500 131.87000 32.29500 132.27000 ;
     RECT 31.89500 145.47000 32.29500 145.87000 ;
     RECT 31.89500 163.07000 32.29500 163.47000 ;
     RECT 32.69500 53.47000 33.09500 53.87000 ;
     RECT 32.69500 67.87000 33.09500 68.27000 ;
     RECT 32.69500 84.67000 33.09500 85.07000 ;
     RECT 32.69500 134.27000 33.09500 134.67000 ;
     RECT 33.49500 103.07000 33.89500 103.47000 ;
     RECT 33.49500 122.27000 33.89500 122.67000 ;
     RECT 33.49500 127.07000 33.89500 127.47000 ;
     RECT 33.49500 143.07000 33.89500 143.47000 ;
     RECT 33.49500 145.47000 33.89500 145.87000 ;
     RECT 33.49500 162.27000 33.89500 162.67000 ;
     RECT 33.49500 169.47000 33.89500 169.87000 ;
     RECT 34.29500 59.07000 34.69500 59.47000 ;
     RECT 34.29500 114.27000 34.69500 114.67000 ;
     RECT 34.29500 128.67000 34.69500 129.07000 ;
     RECT 34.29500 142.27000 34.69500 142.67000 ;
     RECT 34.29500 174.27000 34.69500 174.67000 ;
     RECT 35.09500 43.87000 35.49500 44.27000 ;
     RECT 35.09500 99.07000 35.49500 99.47000 ;
     RECT 35.09500 138.27000 35.49500 138.67000 ;
     RECT 35.09500 163.07000 35.49500 163.47000 ;
     RECT 35.09500 182.27000 35.49500 182.67000 ;
     RECT 35.89500 83.07000 36.29500 83.47000 ;
     RECT 35.89500 134.27000 36.29500 134.67000 ;
     RECT 35.89500 141.47000 36.29500 141.87000 ;
     RECT 35.89500 173.47000 36.29500 173.87000 ;
     RECT 36.69500 62.27000 37.09500 62.67000 ;
     RECT 36.69500 131.07000 37.09500 131.47000 ;
     RECT 36.69500 138.27000 37.09500 138.67000 ;
     RECT 36.69500 160.67000 37.09500 161.07000 ;
     RECT 36.69500 169.47000 37.09500 169.87000 ;
     RECT 36.69500 191.87000 37.09500 192.27000 ;
     RECT 37.49500 51.07000 37.89500 51.47000 ;
     RECT 37.49500 67.07000 37.89500 67.47000 ;
     RECT 37.49500 102.27000 37.89500 102.67000 ;
     RECT 37.49500 131.87000 37.89500 132.27000 ;
     RECT 37.49500 162.27000 37.89500 162.67000 ;
     RECT 37.49500 183.07000 37.89500 183.47000 ;
     RECT 38.29500 67.87000 38.69500 68.27000 ;
     RECT 38.29500 132.67000 38.69500 133.07000 ;
     RECT 38.29500 167.87000 38.69500 168.27000 ;
     RECT 38.29500 179.07000 38.69500 179.47000 ;
     RECT 39.09500 71.87000 39.49500 72.27000 ;
     RECT 39.09500 100.67000 39.49500 101.07000 ;
     RECT 39.09500 102.27000 39.49500 102.67000 ;
     RECT 39.09500 141.47000 39.49500 141.87000 ;
     RECT 39.09500 163.07000 39.49500 163.47000 ;
     RECT 39.89500 55.87000 40.29500 56.27000 ;
     RECT 39.89500 79.07000 40.29500 79.47000 ;
     RECT 39.89500 112.67000 40.29500 113.07000 ;
     RECT 39.89500 126.27000 40.29500 126.67000 ;
     RECT 39.89500 187.87000 40.29500 188.27000 ;
     RECT 40.69500 62.27000 41.09500 62.67000 ;
     RECT 40.69500 87.07000 41.09500 87.47000 ;
     RECT 40.69500 115.87000 41.09500 116.27000 ;
     RECT 40.69500 131.07000 41.09500 131.47000 ;
     RECT 40.69500 144.67000 41.09500 145.07000 ;
     RECT 40.69500 176.67000 41.09500 177.07000 ;
     RECT 41.49500 50.27000 41.89500 50.67000 ;
     RECT 41.49500 74.27000 41.89500 74.67000 ;
     RECT 41.49500 84.67000 41.89500 85.07000 ;
     RECT 41.49500 102.27000 41.89500 102.67000 ;
     RECT 41.49500 132.67000 41.89500 133.07000 ;
     RECT 41.49500 163.87000 41.89500 164.27000 ;
     RECT 42.29500 93.47000 42.69500 93.87000 ;
     RECT 42.29500 100.67000 42.69500 101.07000 ;
     RECT 42.29500 175.07000 42.69500 175.47000 ;
     RECT 42.29500 199.07000 42.69500 199.47000 ;
     RECT 43.09500 62.27000 43.49500 62.67000 ;
     RECT 43.09500 84.67000 43.49500 85.07000 ;
     RECT 43.09500 94.27000 43.49500 94.67000 ;
     RECT 43.09500 103.87000 43.49500 104.27000 ;
     RECT 43.09500 116.67000 43.49500 117.07000 ;
     RECT 43.09500 159.87000 43.49500 160.27000 ;
     RECT 43.09500 163.87000 43.49500 164.27000 ;
     RECT 43.09500 197.47000 43.49500 197.87000 ;
     RECT 43.89500 68.67000 44.29500 69.07000 ;
     RECT 43.89500 93.47000 44.29500 93.87000 ;
     RECT 43.89500 112.67000 44.29500 113.07000 ;
     RECT 43.89500 139.87000 44.29500 140.27000 ;
     RECT 44.69500 59.07000 45.09500 59.47000 ;
     RECT 44.69500 100.67000 45.09500 101.07000 ;
     RECT 44.69500 103.07000 45.09500 103.47000 ;
     RECT 44.69500 159.87000 45.09500 160.27000 ;
     RECT 44.69500 190.27000 45.09500 190.67000 ;
     RECT 45.49500 116.67000 45.89500 117.07000 ;
     RECT 45.49500 118.27000 45.89500 118.67000 ;
     RECT 45.49500 139.87000 45.89500 140.27000 ;
     RECT 45.49500 141.47000 45.89500 141.87000 ;
     RECT 45.49500 193.47000 45.89500 193.87000 ;
     RECT 46.29500 55.07000 46.69500 55.47000 ;
     RECT 46.29500 66.27000 46.69500 66.67000 ;
     RECT 46.29500 95.07000 46.69500 95.47000 ;
     RECT 46.29500 108.67000 46.69500 109.07000 ;
     RECT 46.29500 160.67000 46.69500 161.07000 ;
     RECT 46.29500 183.07000 46.69500 183.47000 ;
     RECT 47.09500 55.87000 47.49500 56.27000 ;
     RECT 47.09500 89.47000 47.49500 89.87000 ;
     RECT 47.09500 103.07000 47.49500 103.47000 ;
     RECT 47.09500 133.47000 47.49500 133.87000 ;
     RECT 47.09500 147.07000 47.49500 147.47000 ;
     RECT 47.09500 148.67000 47.49500 149.07000 ;
     RECT 47.09500 168.67000 47.49500 169.07000 ;
     RECT 47.89500 28.67000 48.29500 29.07000 ;
     RECT 47.89500 99.07000 48.29500 99.47000 ;
     RECT 47.89500 149.47000 48.29500 149.87000 ;
     RECT 47.89500 163.07000 48.29500 163.47000 ;
     RECT 47.89500 209.47000 48.29500 209.87000 ;
     RECT 48.69500 69.47000 49.09500 69.87000 ;
     RECT 48.69500 73.47000 49.09500 73.87000 ;
     RECT 48.69500 77.47000 49.09500 77.87000 ;
     RECT 48.69500 79.87000 49.09500 80.27000 ;
     RECT 48.69500 123.07000 49.09500 123.47000 ;
     RECT 48.69500 130.27000 49.09500 130.67000 ;
     RECT 48.69500 139.87000 49.09500 140.27000 ;
     RECT 48.69500 188.67000 49.09500 189.07000 ;
     RECT 49.49500 22.27000 49.89500 22.67000 ;
     RECT 49.49500 74.27000 49.89500 74.67000 ;
     RECT 49.49500 149.47000 49.89500 149.87000 ;
     RECT 49.49500 162.27000 49.89500 162.67000 ;
     RECT 49.49500 187.07000 49.89500 187.47000 ;
     RECT 50.29500 58.27000 50.69500 58.67000 ;
     RECT 50.29500 88.67000 50.69500 89.07000 ;
     RECT 50.29500 125.47000 50.69500 125.87000 ;
     RECT 50.29500 131.07000 50.69500 131.47000 ;
     RECT 50.29500 144.67000 50.69500 145.07000 ;
     RECT 50.29500 176.67000 50.69500 177.07000 ;
     RECT 51.09500 73.47000 51.49500 73.87000 ;
     RECT 51.09500 122.27000 51.49500 122.67000 ;
     RECT 51.09500 149.47000 51.49500 149.87000 ;
     RECT 51.09500 161.47000 51.49500 161.87000 ;
     RECT 51.09500 193.47000 51.49500 193.87000 ;
     RECT 51.89500 62.27000 52.29500 62.67000 ;
     RECT 51.89500 99.07000 52.29500 99.47000 ;
     RECT 51.89500 144.67000 52.29500 145.07000 ;
     RECT 51.89500 177.47000 52.29500 177.87000 ;
     RECT 51.89500 186.27000 52.29500 186.67000 ;
     RECT 51.89500 194.27000 52.29500 194.67000 ;
     RECT 51.89500 198.27000 52.29500 198.67000 ;
     RECT 52.69500 63.87000 53.09500 64.27000 ;
     RECT 52.69500 89.47000 53.09500 89.87000 ;
     RECT 52.69500 143.87000 53.09500 144.27000 ;
     RECT 52.69500 157.47000 53.09500 157.87000 ;
     RECT 53.49500 35.87000 53.89500 36.27000 ;
     RECT 53.49500 63.07000 53.89500 63.47000 ;
     RECT 53.49500 71.07000 53.89500 71.47000 ;
     RECT 53.49500 78.27000 53.89500 78.67000 ;
     RECT 53.49500 155.87000 53.89500 156.27000 ;
     RECT 53.49500 191.07000 53.89500 191.47000 ;
     RECT 54.29500 56.67000 54.69500 57.07000 ;
     RECT 54.29500 87.87000 54.69500 88.27000 ;
     RECT 54.29500 183.07000 54.69500 183.47000 ;
     RECT 54.29500 193.47000 54.69500 193.87000 ;
     RECT 55.09500 39.87000 55.49500 40.27000 ;
     RECT 55.09500 68.67000 55.49500 69.07000 ;
     RECT 55.09500 78.27000 55.49500 78.67000 ;
     RECT 55.09500 95.07000 55.49500 95.47000 ;
     RECT 55.09500 108.67000 55.49500 109.07000 ;
     RECT 55.09500 127.07000 55.49500 127.47000 ;
     RECT 55.09500 163.07000 55.49500 163.47000 ;
     RECT 55.89500 25.47000 56.29500 25.87000 ;
     RECT 55.89500 33.47000 56.29500 33.87000 ;
     RECT 55.89500 41.47000 56.29500 41.87000 ;
     RECT 55.89500 55.07000 56.29500 55.47000 ;
     RECT 55.89500 80.67000 56.29500 81.07000 ;
     RECT 55.89500 86.27000 56.29500 86.67000 ;
     RECT 55.89500 89.47000 56.29500 89.87000 ;
     RECT 55.89500 110.27000 56.29500 110.67000 ;
     RECT 55.89500 122.27000 56.29500 122.67000 ;
     RECT 55.89500 129.47000 56.29500 129.87000 ;
     RECT 55.89500 155.07000 56.29500 155.47000 ;
     RECT 55.89500 188.67000 56.29500 189.07000 ;
     RECT 56.69500 103.07000 57.09500 103.47000 ;
     RECT 56.69500 123.07000 57.09500 123.47000 ;
     RECT 56.69500 141.47000 57.09500 141.87000 ;
     RECT 57.49500 47.87000 57.89500 48.27000 ;
     RECT 57.49500 66.27000 57.89500 66.67000 ;
     RECT 57.49500 70.27000 57.89500 70.67000 ;
     RECT 57.49500 84.67000 57.89500 85.07000 ;
     RECT 57.49500 92.67000 57.89500 93.07000 ;
     RECT 57.49500 100.67000 57.89500 101.07000 ;
     RECT 57.49500 107.87000 57.89500 108.27000 ;
     RECT 57.49500 131.07000 57.89500 131.47000 ;
     RECT 57.49500 137.47000 57.89500 137.87000 ;
     RECT 57.49500 143.87000 57.89500 144.27000 ;
     RECT 57.49500 155.07000 57.89500 155.47000 ;
     RECT 57.49500 158.27000 57.89500 158.67000 ;
     RECT 57.49500 183.87000 57.89500 184.27000 ;
     RECT 57.49500 201.47000 57.89500 201.87000 ;
     RECT 58.29500 55.87000 58.69500 56.27000 ;
     RECT 58.29500 97.47000 58.69500 97.87000 ;
     RECT 58.29500 113.47000 58.69500 113.87000 ;
     RECT 58.29500 127.07000 58.69500 127.47000 ;
     RECT 58.29500 134.27000 58.69500 134.67000 ;
     RECT 58.29500 175.07000 58.69500 175.47000 ;
     RECT 59.09500 25.47000 59.49500 25.87000 ;
     RECT 59.09500 35.07000 59.49500 35.47000 ;
     RECT 59.09500 43.87000 59.49500 44.27000 ;
     RECT 59.09500 57.47000 59.49500 57.87000 ;
     RECT 59.09500 59.07000 59.49500 59.47000 ;
     RECT 59.09500 74.27000 59.49500 74.67000 ;
     RECT 59.09500 98.27000 59.49500 98.67000 ;
     RECT 59.09500 107.87000 59.49500 108.27000 ;
     RECT 59.09500 118.27000 59.49500 118.67000 ;
     RECT 59.09500 123.07000 59.49500 123.47000 ;
     RECT 59.09500 124.67000 59.49500 125.07000 ;
     RECT 59.09500 131.07000 59.49500 131.47000 ;
     RECT 59.09500 156.67000 59.49500 157.07000 ;
     RECT 59.09500 161.47000 59.49500 161.87000 ;
     RECT 59.09500 173.47000 59.49500 173.87000 ;
     RECT 59.09500 188.67000 59.49500 189.07000 ;
     RECT 59.09500 193.47000 59.49500 193.87000 ;
     RECT 59.89500 62.27000 60.29500 62.67000 ;
     RECT 59.89500 100.67000 60.29500 101.07000 ;
     RECT 59.89500 176.67000 60.29500 177.07000 ;
     RECT 59.89500 189.47000 60.29500 189.87000 ;
     RECT 59.89500 198.27000 60.29500 198.67000 ;
     RECT 60.69500 55.87000 61.09500 56.27000 ;
     RECT 60.69500 98.27000 61.09500 98.67000 ;
     RECT 60.69500 127.07000 61.09500 127.47000 ;
     RECT 60.69500 171.07000 61.09500 171.47000 ;
     RECT 61.49500 84.67000 61.89500 85.07000 ;
     RECT 61.49500 97.47000 61.89500 97.87000 ;
     RECT 61.49500 123.07000 61.89500 123.47000 ;
     RECT 61.49500 149.47000 61.89500 149.87000 ;
     RECT 61.49500 174.27000 61.89500 174.67000 ;
     RECT 61.49500 194.27000 61.89500 194.67000 ;
     RECT 61.49500 208.67000 61.89500 209.07000 ;
     RECT 62.29500 54.27000 62.69500 54.67000 ;
     RECT 62.29500 83.87000 62.69500 84.27000 ;
     RECT 62.29500 100.67000 62.69500 101.07000 ;
     RECT 62.29500 139.87000 62.69500 140.27000 ;
     RECT 62.29500 147.87000 62.69500 148.27000 ;
     RECT 63.09500 67.07000 63.49500 67.47000 ;
     RECT 63.09500 73.47000 63.49500 73.87000 ;
     RECT 63.09500 81.47000 63.49500 81.87000 ;
     RECT 63.09500 93.47000 63.49500 93.87000 ;
     RECT 63.09500 103.07000 63.49500 103.47000 ;
     RECT 63.09500 122.27000 63.49500 122.67000 ;
     RECT 63.09500 145.47000 63.49500 145.87000 ;
     RECT 63.09500 159.07000 63.49500 159.47000 ;
     RECT 63.89500 54.27000 64.29500 54.67000 ;
     RECT 63.89500 64.67000 64.29500 65.07000 ;
     RECT 63.89500 80.67000 64.29500 81.07000 ;
     RECT 63.89500 86.27000 64.29500 86.67000 ;
     RECT 63.89500 87.87000 64.29500 88.27000 ;
     RECT 63.89500 107.87000 64.29500 108.27000 ;
     RECT 63.89500 113.47000 64.29500 113.87000 ;
     RECT 63.89500 134.27000 64.29500 134.67000 ;
     RECT 63.89500 143.87000 64.29500 144.27000 ;
     RECT 63.89500 161.47000 64.29500 161.87000 ;
     RECT 63.89500 182.27000 64.29500 182.67000 ;
     RECT 64.69500 66.27000 65.09500 66.67000 ;
     RECT 64.69500 88.67000 65.09500 89.07000 ;
     RECT 64.69500 124.67000 65.09500 125.07000 ;
     RECT 64.69500 167.87000 65.09500 168.27000 ;
     RECT 64.69500 169.47000 65.09500 169.87000 ;
     RECT 64.69500 199.87000 65.09500 200.27000 ;
     RECT 65.49500 49.47000 65.89500 49.87000 ;
     RECT 65.49500 74.27000 65.89500 74.67000 ;
     RECT 65.49500 97.47000 65.89500 97.87000 ;
     RECT 65.49500 118.27000 65.89500 118.67000 ;
     RECT 65.49500 143.87000 65.89500 144.27000 ;
     RECT 65.49500 159.07000 65.89500 159.47000 ;
     RECT 65.49500 205.47000 65.89500 205.87000 ;
     RECT 66.29500 52.67000 66.69500 53.07000 ;
     RECT 66.29500 62.27000 66.69500 62.67000 ;
     RECT 66.29500 66.27000 66.69500 66.67000 ;
     RECT 66.29500 83.87000 66.69500 84.27000 ;
     RECT 66.29500 89.47000 66.69500 89.87000 ;
     RECT 66.29500 98.27000 66.69500 98.67000 ;
     RECT 66.29500 155.07000 66.69500 155.47000 ;
     RECT 66.29500 167.87000 66.69500 168.27000 ;
     RECT 67.09500 58.27000 67.49500 58.67000 ;
     RECT 67.09500 70.27000 67.49500 70.67000 ;
     RECT 67.09500 97.47000 67.49500 97.87000 ;
     RECT 67.09500 99.07000 67.49500 99.47000 ;
     RECT 67.09500 138.27000 67.49500 138.67000 ;
     RECT 67.09500 158.27000 67.49500 158.67000 ;
     RECT 67.09500 159.87000 67.49500 160.27000 ;
     RECT 67.09500 197.47000 67.49500 197.87000 ;
     RECT 67.89500 62.27000 68.29500 62.67000 ;
     RECT 67.89500 66.27000 68.29500 66.67000 ;
     RECT 67.89500 79.87000 68.29500 80.27000 ;
     RECT 67.89500 93.47000 68.29500 93.87000 ;
     RECT 67.89500 103.07000 68.29500 103.47000 ;
     RECT 67.89500 107.87000 68.29500 108.27000 ;
     RECT 67.89500 134.27000 68.29500 134.67000 ;
     RECT 67.89500 156.67000 68.29500 157.07000 ;
     RECT 67.89500 161.47000 68.29500 161.87000 ;
     RECT 67.89500 163.87000 68.29500 164.27000 ;
     RECT 67.89500 182.27000 68.29500 182.67000 ;
     RECT 68.69500 39.07000 69.09500 39.47000 ;
     RECT 68.69500 63.87000 69.09500 64.27000 ;
     RECT 68.69500 87.07000 69.09500 87.47000 ;
     RECT 68.69500 101.47000 69.09500 101.87000 ;
     RECT 68.69500 118.27000 69.09500 118.67000 ;
     RECT 68.69500 123.07000 69.09500 123.47000 ;
     RECT 68.69500 126.27000 69.09500 126.67000 ;
     RECT 68.69500 159.87000 69.09500 160.27000 ;
     RECT 68.69500 163.07000 69.09500 163.47000 ;
     RECT 69.49500 55.87000 69.89500 56.27000 ;
     RECT 69.49500 97.47000 69.89500 97.87000 ;
     RECT 69.49500 144.67000 69.89500 145.07000 ;
     RECT 70.29500 123.07000 70.69500 123.47000 ;
     RECT 71.09500 86.27000 71.49500 86.67000 ;
     RECT 71.09500 107.87000 71.49500 108.27000 ;
     RECT 71.09500 169.47000 71.49500 169.87000 ;
     RECT 71.09500 192.67000 71.49500 193.07000 ;
     RECT 71.89500 55.87000 72.29500 56.27000 ;
     RECT 71.89500 87.87000 72.29500 88.27000 ;
     RECT 71.89500 108.67000 72.29500 109.07000 ;
     RECT 71.89500 134.27000 72.29500 134.67000 ;
     RECT 71.89500 182.27000 72.29500 182.67000 ;
     RECT 71.89500 191.87000 72.29500 192.27000 ;
     RECT 72.69500 68.67000 73.09500 69.07000 ;
     RECT 72.69500 100.67000 73.09500 101.07000 ;
     RECT 72.69500 129.47000 73.09500 129.87000 ;
     RECT 72.69500 140.67000 73.09500 141.07000 ;
     RECT 72.69500 163.87000 73.09500 164.27000 ;
     RECT 72.69500 199.87000 73.09500 200.27000 ;
     RECT 73.49500 143.07000 73.89500 143.47000 ;
     RECT 73.49500 167.87000 73.89500 168.27000 ;
     RECT 73.49500 175.07000 73.89500 175.47000 ;
     RECT 73.49500 178.27000 73.89500 178.67000 ;
     RECT 73.49500 207.87000 73.89500 208.27000 ;
     RECT 74.29500 58.27000 74.69500 58.67000 ;
     RECT 74.29500 103.87000 74.69500 104.27000 ;
     RECT 74.29500 142.27000 74.69500 142.67000 ;
     RECT 75.09500 59.07000 75.49500 59.47000 ;
     RECT 75.09500 68.67000 75.49500 69.07000 ;
     RECT 75.09500 74.27000 75.49500 74.67000 ;
     RECT 75.09500 93.47000 75.49500 93.87000 ;
     RECT 75.09500 128.67000 75.49500 129.07000 ;
     RECT 75.09500 138.27000 75.49500 138.67000 ;
     RECT 75.09500 155.07000 75.49500 155.47000 ;
     RECT 75.09500 161.47000 75.49500 161.87000 ;
     RECT 75.09500 168.67000 75.49500 169.07000 ;
     RECT 75.09500 183.07000 75.49500 183.47000 ;
     RECT 75.09500 193.47000 75.49500 193.87000 ;
     RECT 75.89500 57.47000 76.29500 57.87000 ;
     RECT 75.89500 87.07000 76.29500 87.47000 ;
     RECT 75.89500 134.27000 76.29500 134.67000 ;
     RECT 75.89500 147.07000 76.29500 147.47000 ;
     RECT 75.89500 191.87000 76.29500 192.27000 ;
     RECT 76.69500 80.67000 77.09500 81.07000 ;
     RECT 76.69500 89.47000 77.09500 89.87000 ;
     RECT 76.69500 107.87000 77.09500 108.27000 ;
     RECT 76.69500 168.67000 77.09500 169.07000 ;
     RECT 76.69500 184.67000 77.09500 185.07000 ;
     RECT 76.69500 194.27000 77.09500 194.67000 ;
     RECT 77.49500 56.67000 77.89500 57.07000 ;
     RECT 77.49500 68.67000 77.89500 69.07000 ;
     RECT 77.49500 70.27000 77.89500 70.67000 ;
     RECT 77.49500 81.47000 77.89500 81.87000 ;
     RECT 77.49500 93.47000 77.89500 93.87000 ;
     RECT 77.49500 144.67000 77.89500 145.07000 ;
     RECT 77.49500 161.47000 77.89500 161.87000 ;
     RECT 77.49500 167.87000 77.89500 168.27000 ;
     RECT 78.29500 62.27000 78.69500 62.67000 ;
     RECT 78.29500 95.07000 78.69500 95.47000 ;
     RECT 78.29500 125.47000 78.69500 125.87000 ;
     RECT 78.29500 129.47000 78.69500 129.87000 ;
     RECT 78.29500 147.07000 78.69500 147.47000 ;
     RECT 78.29500 155.07000 78.69500 155.47000 ;
     RECT 78.29500 174.27000 78.69500 174.67000 ;
     RECT 78.29500 207.07000 78.69500 207.47000 ;
     RECT 79.09500 63.87000 79.49500 64.27000 ;
     RECT 79.09500 79.87000 79.49500 80.27000 ;
     RECT 79.09500 85.47000 79.49500 85.87000 ;
     RECT 79.09500 123.07000 79.49500 123.47000 ;
     RECT 79.09500 124.67000 79.49500 125.07000 ;
     RECT 79.09500 167.87000 79.49500 168.27000 ;
     RECT 79.09500 189.47000 79.49500 189.87000 ;
     RECT 79.09500 194.27000 79.49500 194.67000 ;
     RECT 79.89500 55.07000 80.29500 55.47000 ;
     RECT 79.89500 138.27000 80.29500 138.67000 ;
     RECT 79.89500 157.47000 80.29500 157.87000 ;
     RECT 79.89500 187.87000 80.29500 188.27000 ;
     RECT 80.69500 72.67000 81.09500 73.07000 ;
     RECT 80.69500 94.27000 81.09500 94.67000 ;
     RECT 80.69500 163.87000 81.09500 164.27000 ;
     RECT 81.49500 52.67000 81.89500 53.07000 ;
     RECT 81.49500 110.27000 81.89500 110.67000 ;
     RECT 81.49500 154.27000 81.89500 154.67000 ;
     RECT 81.49500 178.27000 81.89500 178.67000 ;
     RECT 81.49500 182.27000 81.89500 182.67000 ;
     RECT 81.49500 207.87000 81.89500 208.27000 ;
     RECT 82.29500 56.67000 82.69500 57.07000 ;
     RECT 82.29500 94.27000 82.69500 94.67000 ;
     RECT 82.29500 171.07000 82.69500 171.47000 ;
     RECT 82.29500 189.47000 82.69500 189.87000 ;
     RECT 83.09500 127.07000 83.49500 127.47000 ;
     RECT 83.09500 161.47000 83.49500 161.87000 ;
     RECT 83.09500 178.27000 83.49500 178.67000 ;
     RECT 83.09500 198.27000 83.49500 198.67000 ;
     RECT 83.89500 79.87000 84.29500 80.27000 ;
     RECT 83.89500 159.07000 84.29500 159.47000 ;
     RECT 83.89500 199.87000 84.29500 200.27000 ;
     RECT 84.69500 62.27000 85.09500 62.67000 ;
     RECT 84.69500 78.27000 85.09500 78.67000 ;
     RECT 84.69500 107.87000 85.09500 108.27000 ;
     RECT 84.69500 170.27000 85.09500 170.67000 ;
     RECT 84.69500 194.27000 85.09500 194.67000 ;
     RECT 85.49500 94.27000 85.89500 94.67000 ;
     RECT 85.49500 95.87000 85.89500 96.27000 ;
     RECT 85.49500 158.27000 85.89500 158.67000 ;
     RECT 85.49500 163.07000 85.89500 163.47000 ;
     RECT 85.49500 185.47000 85.89500 185.87000 ;
     RECT 86.29500 56.67000 86.69500 57.07000 ;
     RECT 86.29500 99.87000 86.69500 100.27000 ;
     RECT 86.29500 162.27000 86.69500 162.67000 ;
     RECT 86.29500 163.87000 86.69500 164.27000 ;
     RECT 86.29500 187.87000 86.69500 188.27000 ;
     RECT 87.09500 89.47000 87.49500 89.87000 ;
     RECT 87.09500 175.87000 87.49500 176.27000 ;
     RECT 87.09500 194.27000 87.49500 194.67000 ;
     RECT 87.89500 55.07000 88.29500 55.47000 ;
     RECT 87.89500 88.67000 88.29500 89.07000 ;
     RECT 87.89500 108.67000 88.29500 109.07000 ;
     RECT 87.89500 122.27000 88.29500 122.67000 ;
     RECT 87.89500 127.07000 88.29500 127.47000 ;
     RECT 87.89500 189.47000 88.29500 189.87000 ;
     RECT 88.69500 72.67000 89.09500 73.07000 ;
     RECT 88.69500 99.87000 89.09500 100.27000 ;
     RECT 88.69500 124.67000 89.09500 125.07000 ;
     RECT 88.69500 162.27000 89.09500 162.67000 ;
     RECT 88.69500 176.67000 89.09500 177.07000 ;
     RECT 88.69500 193.47000 89.09500 193.87000 ;
     RECT 88.69500 199.07000 89.09500 199.47000 ;
     RECT 89.49500 62.27000 89.89500 62.67000 ;
     RECT 89.49500 66.27000 89.89500 66.67000 ;
     RECT 89.49500 128.67000 89.89500 129.07000 ;
     RECT 89.49500 197.47000 89.89500 197.87000 ;
     RECT 89.49500 209.47000 89.89500 209.87000 ;
     RECT 90.29500 57.47000 90.69500 57.87000 ;
     RECT 90.29500 71.07000 90.69500 71.47000 ;
     RECT 90.29500 73.47000 90.69500 73.87000 ;
     RECT 90.29500 178.27000 90.69500 178.67000 ;
     RECT 90.29500 202.27000 90.69500 202.67000 ;
     RECT 91.09500 56.67000 91.49500 57.07000 ;
     RECT 91.09500 85.47000 91.49500 85.87000 ;
     RECT 91.09500 92.67000 91.49500 93.07000 ;
     RECT 91.09500 97.47000 91.49500 97.87000 ;
     RECT 91.09500 107.87000 91.49500 108.27000 ;
     RECT 91.09500 118.27000 91.49500 118.67000 ;
     RECT 91.09500 148.67000 91.49500 149.07000 ;
     RECT 91.09500 156.67000 91.49500 157.07000 ;
     RECT 91.09500 177.47000 91.49500 177.87000 ;
     RECT 91.89500 93.47000 92.29500 93.87000 ;
     RECT 91.89500 116.67000 92.29500 117.07000 ;
     RECT 91.89500 127.07000 92.29500 127.47000 ;
     RECT 91.89500 207.07000 92.29500 207.47000 ;
     RECT 92.69500 62.27000 93.09500 62.67000 ;
     RECT 92.69500 85.47000 93.09500 85.87000 ;
     RECT 92.69500 103.07000 93.09500 103.47000 ;
     RECT 92.69500 127.87000 93.09500 128.27000 ;
     RECT 92.69500 152.67000 93.09500 153.07000 ;
     RECT 92.69500 161.47000 93.09500 161.87000 ;
     RECT 93.49500 63.07000 93.89500 63.47000 ;
     RECT 93.49500 88.67000 93.89500 89.07000 ;
     RECT 93.49500 96.67000 93.89500 97.07000 ;
     RECT 93.49500 123.07000 93.89500 123.47000 ;
     RECT 93.49500 149.47000 93.89500 149.87000 ;
     RECT 93.49500 185.47000 93.89500 185.87000 ;
     RECT 94.29500 127.87000 94.69500 128.27000 ;
     RECT 95.09500 54.27000 95.49500 54.67000 ;
     RECT 95.09500 82.27000 95.49500 82.67000 ;
     RECT 95.09500 95.87000 95.49500 96.27000 ;
     RECT 95.09500 132.67000 95.49500 133.07000 ;
     RECT 95.09500 167.87000 95.49500 168.27000 ;
     RECT 95.89500 87.07000 96.29500 87.47000 ;
     RECT 95.89500 111.07000 96.29500 111.47000 ;
     RECT 96.69500 39.07000 97.09500 39.47000 ;
     RECT 96.69500 81.47000 97.09500 81.87000 ;
     RECT 97.49500 88.67000 97.89500 89.07000 ;
     RECT 97.49500 94.27000 97.89500 94.67000 ;
     RECT 97.49500 160.67000 97.89500 161.07000 ;
     RECT 97.49500 175.87000 97.89500 176.27000 ;
     RECT 97.49500 211.07000 97.89500 211.47000 ;
     RECT 98.29500 33.47000 98.69500 33.87000 ;
     RECT 98.29500 72.67000 98.69500 73.07000 ;
     RECT 98.29500 145.47000 98.69500 145.87000 ;
     RECT 99.09500 62.27000 99.49500 62.67000 ;
     RECT 99.89500 138.27000 100.29500 138.67000 ;
     RECT 99.89500 184.67000 100.29500 185.07000 ;
     RECT 100.69500 163.87000 101.09500 164.27000 ;
     RECT 101.49500 64.67000 101.89500 65.07000 ;
     RECT 101.49500 99.87000 101.89500 100.27000 ;
     RECT 101.49500 161.47000 101.89500 161.87000 ;
     RECT 103.09500 35.87000 103.49500 36.27000 ;
     RECT 103.09500 79.87000 103.49500 80.27000 ;
     RECT 103.09500 146.27000 103.49500 146.67000 ;
     RECT 103.09500 211.07000 103.49500 211.47000 ;
     RECT 103.89500 54.27000 104.29500 54.67000 ;
     RECT 103.89500 73.47000 104.29500 73.87000 ;
     RECT 103.89500 78.27000 104.29500 78.67000 ;
     RECT 103.89500 163.07000 104.29500 163.47000 ;
     RECT 104.69500 65.47000 105.09500 65.87000 ;
     RECT 105.49500 24.67000 105.89500 25.07000 ;
     RECT 105.49500 127.87000 105.89500 128.27000 ;
     RECT 105.49500 147.07000 105.89500 147.47000 ;
     RECT 105.49500 211.07000 105.89500 211.47000 ;
     RECT 106.29500 53.47000 106.69500 53.87000 ;
     RECT 106.29500 93.47000 106.69500 93.87000 ;
     RECT 106.29500 143.07000 106.69500 143.47000 ;
     RECT 106.29500 193.47000 106.69500 193.87000 ;
     RECT 107.09500 62.27000 107.49500 62.67000 ;
     RECT 107.89500 56.67000 108.29500 57.07000 ;
     RECT 107.89500 88.67000 108.29500 89.07000 ;
     RECT 108.69500 71.07000 109.09500 71.47000 ;
     RECT 108.69500 97.47000 109.09500 97.87000 ;
     RECT 108.69500 161.47000 109.09500 161.87000 ;
     RECT 109.49500 19.07000 109.89500 19.47000 ;
     RECT 109.49500 83.07000 109.89500 83.47000 ;
     RECT 109.49500 159.87000 109.89500 160.27000 ;
     RECT 110.29500 51.07000 110.69500 51.47000 ;
     RECT 110.29500 83.87000 110.69500 84.27000 ;
     RECT 111.09500 161.47000 111.49500 161.87000 ;
     RECT 111.89500 54.27000 112.29500 54.67000 ;
     RECT 111.89500 137.47000 112.29500 137.87000 ;
     RECT 111.89500 183.87000 112.29500 184.27000 ;
     RECT 112.69500 43.87000 113.09500 44.27000 ;
     RECT 112.69500 178.27000 113.09500 178.67000 ;
     RECT 113.49500 37.47000 113.89500 37.87000 ;
     RECT 113.49500 65.47000 113.89500 65.87000 ;
     RECT 113.49500 129.47000 113.89500 129.87000 ;
     RECT 114.29500 36.67000 114.69500 37.07000 ;
     RECT 114.29500 62.27000 114.69500 62.67000 ;
     RECT 114.29500 72.67000 114.69500 73.07000 ;
     RECT 114.29500 98.27000 114.69500 98.67000 ;
     RECT 114.29500 139.07000 114.69500 139.47000 ;
     RECT 114.29500 202.27000 114.69500 202.67000 ;
     RECT 115.09500 86.27000 115.49500 86.67000 ;
     RECT 115.09500 115.07000 115.49500 115.47000 ;
     RECT 115.89500 40.67000 116.29500 41.07000 ;
     RECT 115.89500 87.87000 116.29500 88.27000 ;
     RECT 115.89500 108.67000 116.29500 109.07000 ;
     RECT 116.69500 65.47000 117.09500 65.87000 ;
     RECT 116.69500 83.07000 117.09500 83.47000 ;
     RECT 116.69500 159.07000 117.09500 159.47000 ;
     RECT 117.49500 39.07000 117.89500 39.47000 ;
     RECT 117.49500 85.47000 117.89500 85.87000 ;
     RECT 118.29500 35.07000 118.69500 35.47000 ;
     RECT 118.29500 63.87000 118.69500 64.27000 ;
     RECT 119.09500 57.47000 119.49500 57.87000 ;
     RECT 119.09500 79.07000 119.49500 79.47000 ;
     RECT 119.09500 118.27000 119.49500 118.67000 ;
     RECT 119.89500 54.27000 120.29500 54.67000 ;
     RECT 119.89500 163.87000 120.29500 164.27000 ;
     RECT 121.49500 27.87000 121.89500 28.27000 ;
     RECT 121.49500 88.67000 121.89500 89.07000 ;
     RECT 121.49500 128.67000 121.89500 129.07000 ;
     RECT 121.49500 175.07000 121.89500 175.47000 ;
     RECT 122.29500 48.67000 122.69500 49.07000 ;
     RECT 122.29500 62.27000 122.69500 62.67000 ;
     RECT 122.29500 103.87000 122.69500 104.27000 ;
     RECT 122.29500 138.27000 122.69500 138.67000 ;
     RECT 122.29500 154.27000 122.69500 154.67000 ;
     RECT 123.09500 24.67000 123.49500 25.07000 ;
     RECT 123.09500 160.67000 123.49500 161.07000 ;
     RECT 123.89500 62.27000 124.29500 62.67000 ;
     RECT 123.89500 64.67000 124.29500 65.07000 ;
     RECT 123.89500 87.87000 124.29500 88.27000 ;
     RECT 123.89500 111.87000 124.29500 112.27000 ;
     RECT 123.89500 127.87000 124.29500 128.27000 ;
     RECT 123.89500 131.87000 124.29500 132.27000 ;
     RECT 124.69500 55.07000 125.09500 55.47000 ;
     RECT 124.69500 68.67000 125.09500 69.07000 ;
     RECT 124.69500 77.47000 125.09500 77.87000 ;
     RECT 124.69500 94.27000 125.09500 94.67000 ;
     RECT 124.69500 98.27000 125.09500 98.67000 ;
     RECT 124.69500 198.27000 125.09500 198.67000 ;
     RECT 125.49500 36.67000 125.89500 37.07000 ;
     RECT 125.49500 89.47000 125.89500 89.87000 ;
     RECT 125.49500 126.27000 125.89500 126.67000 ;
     RECT 125.49500 139.87000 125.89500 140.27000 ;
     RECT 125.49500 162.27000 125.89500 162.67000 ;
     RECT 126.29500 37.47000 126.69500 37.87000 ;
     RECT 126.29500 51.87000 126.69500 52.27000 ;
     RECT 126.29500 132.67000 126.69500 133.07000 ;
     RECT 126.29500 145.47000 126.69500 145.87000 ;
     RECT 127.09500 47.87000 127.49500 48.27000 ;
     RECT 127.09500 71.07000 127.49500 71.47000 ;
     RECT 127.09500 81.47000 127.49500 81.87000 ;
     RECT 127.09500 99.87000 127.49500 100.27000 ;
     RECT 127.89500 58.27000 128.29500 58.67000 ;
     RECT 127.89500 88.67000 128.29500 89.07000 ;
     RECT 127.89500 132.67000 128.29500 133.07000 ;
     RECT 127.89500 140.67000 128.29500 141.07000 ;
     RECT 127.89500 142.27000 128.29500 142.67000 ;
     RECT 127.89500 147.07000 128.29500 147.47000 ;
     RECT 127.89500 167.87000 128.29500 168.27000 ;
     RECT 128.69500 13.47000 129.09500 13.87000 ;
     RECT 128.69500 53.47000 129.09500 53.87000 ;
     RECT 128.69500 70.27000 129.09500 70.67000 ;
     RECT 128.69500 123.07000 129.09500 123.47000 ;
     RECT 129.49500 47.87000 129.89500 48.27000 ;
     RECT 129.49500 51.87000 129.89500 52.27000 ;
     RECT 129.49500 71.07000 129.89500 71.47000 ;
     RECT 129.49500 103.87000 129.89500 104.27000 ;
     RECT 129.49500 139.87000 129.89500 140.27000 ;
     RECT 129.49500 146.27000 129.89500 146.67000 ;
     RECT 129.49500 155.07000 129.89500 155.47000 ;
     RECT 130.29500 52.67000 130.69500 53.07000 ;
     RECT 130.29500 70.27000 130.69500 70.67000 ;
     RECT 130.29500 81.47000 130.69500 81.87000 ;
     RECT 130.29500 124.67000 130.69500 125.07000 ;
     RECT 130.29500 184.67000 130.69500 185.07000 ;
     RECT 131.09500 57.47000 131.49500 57.87000 ;
     RECT 131.09500 67.07000 131.49500 67.47000 ;
     RECT 131.09500 93.47000 131.49500 93.87000 ;
     RECT 131.09500 109.47000 131.49500 109.87000 ;
     RECT 131.09500 138.27000 131.49500 138.67000 ;
     RECT 131.09500 177.47000 131.49500 177.87000 ;
     RECT 131.89500 113.47000 132.29500 113.87000 ;
     RECT 131.89500 143.87000 132.29500 144.27000 ;
     RECT 131.89500 163.87000 132.29500 164.27000 ;
     RECT 132.69500 48.67000 133.09500 49.07000 ;
     RECT 132.69500 63.07000 133.09500 63.47000 ;
     RECT 132.69500 85.47000 133.09500 85.87000 ;
     RECT 132.69500 87.87000 133.09500 88.27000 ;
     RECT 132.69500 89.47000 133.09500 89.87000 ;
     RECT 132.69500 138.27000 133.09500 138.67000 ;
     RECT 132.69500 153.47000 133.09500 153.87000 ;
     RECT 132.69500 161.47000 133.09500 161.87000 ;
     RECT 133.49500 36.67000 133.89500 37.07000 ;
     RECT 133.49500 47.87000 133.89500 48.27000 ;
     RECT 133.49500 72.67000 133.89500 73.07000 ;
     RECT 133.49500 95.07000 133.89500 95.47000 ;
     RECT 133.49500 145.47000 133.89500 145.87000 ;
     RECT 134.29500 49.47000 134.69500 49.87000 ;
     RECT 134.29500 55.07000 134.69500 55.47000 ;
     RECT 134.29500 64.67000 134.69500 65.07000 ;
     RECT 134.29500 67.87000 134.69500 68.27000 ;
     RECT 134.29500 71.07000 134.69500 71.47000 ;
     RECT 134.29500 81.47000 134.69500 81.87000 ;
     RECT 134.29500 134.27000 134.69500 134.67000 ;
     RECT 134.29500 149.47000 134.69500 149.87000 ;
     RECT 135.09500 34.27000 135.49500 34.67000 ;
     RECT 135.09500 55.87000 135.49500 56.27000 ;
     RECT 135.09500 78.27000 135.49500 78.67000 ;
     RECT 135.09500 116.67000 135.49500 117.07000 ;
     RECT 135.09500 143.07000 135.49500 143.47000 ;
     RECT 135.09500 163.87000 135.49500 164.27000 ;
     RECT 135.09500 169.47000 135.49500 169.87000 ;
     RECT 135.89500 18.27000 136.29500 18.67000 ;
     RECT 135.89500 51.07000 136.29500 51.47000 ;
     RECT 135.89500 56.67000 136.29500 57.07000 ;
     RECT 135.89500 130.27000 136.29500 130.67000 ;
     RECT 135.89500 147.07000 136.29500 147.47000 ;
     RECT 135.89500 168.67000 136.29500 169.07000 ;
     RECT 135.89500 170.27000 136.29500 170.67000 ;
     RECT 136.69500 59.07000 137.09500 59.47000 ;
     RECT 136.69500 65.47000 137.09500 65.87000 ;
     RECT 136.69500 79.87000 137.09500 80.27000 ;
     RECT 136.69500 103.87000 137.09500 104.27000 ;
     RECT 136.69500 108.67000 137.09500 109.07000 ;
     RECT 136.69500 154.27000 137.09500 154.67000 ;
     RECT 137.49500 32.67000 137.89500 33.07000 ;
     RECT 137.49500 43.87000 137.89500 44.27000 ;
     RECT 137.49500 55.87000 137.89500 56.27000 ;
     RECT 137.49500 64.67000 137.89500 65.07000 ;
     RECT 137.49500 80.67000 137.89500 81.07000 ;
     RECT 137.49500 114.27000 137.89500 114.67000 ;
     RECT 137.49500 139.87000 137.89500 140.27000 ;
     RECT 137.49500 160.67000 137.89500 161.07000 ;
     RECT 138.29500 22.27000 138.69500 22.67000 ;
     RECT 138.29500 23.87000 138.69500 24.27000 ;
     RECT 138.29500 35.07000 138.69500 35.47000 ;
     RECT 138.29500 47.87000 138.69500 48.27000 ;
     RECT 138.29500 68.67000 138.69500 69.07000 ;
     RECT 138.29500 79.87000 138.69500 80.27000 ;
     RECT 138.29500 98.27000 138.69500 98.67000 ;
     RECT 138.29500 147.87000 138.69500 148.27000 ;
     RECT 138.29500 152.67000 138.69500 153.07000 ;
     RECT 139.09500 33.47000 139.49500 33.87000 ;
     RECT 139.09500 37.47000 139.49500 37.87000 ;
     RECT 139.09500 41.47000 139.49500 41.87000 ;
     RECT 139.09500 63.07000 139.49500 63.47000 ;
     RECT 139.09500 71.87000 139.49500 72.27000 ;
     RECT 139.09500 108.67000 139.49500 109.07000 ;
     RECT 139.09500 134.27000 139.49500 134.67000 ;
     RECT 139.09500 163.87000 139.49500 164.27000 ;
     RECT 139.09500 167.87000 139.49500 168.27000 ;
     RECT 139.09500 189.47000 139.49500 189.87000 ;
     RECT 139.89500 49.47000 140.29500 49.87000 ;
     RECT 139.89500 89.47000 140.29500 89.87000 ;
     RECT 139.89500 160.67000 140.29500 161.07000 ;
     RECT 140.69500 127.87000 141.09500 128.27000 ;
     RECT 140.69500 137.47000 141.09500 137.87000 ;
     RECT 140.69500 163.87000 141.09500 164.27000 ;
     RECT 141.49500 53.47000 141.89500 53.87000 ;
     RECT 141.49500 94.27000 141.89500 94.67000 ;
     RECT 141.49500 109.47000 141.89500 109.87000 ;
     RECT 141.49500 128.67000 141.89500 129.07000 ;
     RECT 141.49500 138.27000 141.89500 138.67000 ;
     RECT 141.49500 156.67000 141.89500 157.07000 ;
     RECT 141.49500 160.67000 141.89500 161.07000 ;
     RECT 142.29500 29.47000 142.69500 29.87000 ;
     RECT 142.29500 83.87000 142.69500 84.27000 ;
     RECT 142.29500 99.07000 142.69500 99.47000 ;
     RECT 142.29500 152.67000 142.69500 153.07000 ;
     RECT 143.09500 25.47000 143.49500 25.87000 ;
     RECT 143.09500 43.87000 143.49500 44.27000 ;
     RECT 143.09500 47.87000 143.49500 48.27000 ;
     RECT 143.09500 53.47000 143.49500 53.87000 ;
     RECT 143.09500 55.87000 143.49500 56.27000 ;
     RECT 143.09500 102.27000 143.49500 102.67000 ;
     RECT 143.09500 149.47000 143.49500 149.87000 ;
     RECT 143.89500 51.07000 144.29500 51.47000 ;
     RECT 143.89500 63.07000 144.29500 63.47000 ;
     RECT 143.89500 74.27000 144.29500 74.67000 ;
     RECT 143.89500 77.47000 144.29500 77.87000 ;
     RECT 143.89500 103.87000 144.29500 104.27000 ;
     RECT 143.89500 108.67000 144.29500 109.07000 ;
     RECT 143.89500 162.27000 144.29500 162.67000 ;
     RECT 143.89500 163.87000 144.29500 164.27000 ;
     RECT 144.69500 32.67000 145.09500 33.07000 ;
     RECT 144.69500 58.27000 145.09500 58.67000 ;
     RECT 144.69500 87.87000 145.09500 88.27000 ;
     RECT 144.69500 97.47000 145.09500 97.87000 ;
     RECT 144.69500 122.27000 145.09500 122.67000 ;
     RECT 144.69500 124.67000 145.09500 125.07000 ;
     RECT 144.69500 147.87000 145.09500 148.27000 ;
     RECT 144.69500 174.27000 145.09500 174.67000 ;
     RECT 144.69500 185.47000 145.09500 185.87000 ;
     RECT 145.49500 23.07000 145.89500 23.47000 ;
     RECT 145.49500 62.27000 145.89500 62.67000 ;
     RECT 145.49500 63.87000 145.89500 64.27000 ;
     RECT 145.49500 74.27000 145.89500 74.67000 ;
     RECT 145.49500 96.67000 145.89500 97.07000 ;
     RECT 145.49500 138.27000 145.89500 138.67000 ;
     RECT 145.49500 152.67000 145.89500 153.07000 ;
     RECT 145.49500 168.67000 145.89500 169.07000 ;
     RECT 146.29500 57.47000 146.69500 57.87000 ;
     RECT 146.29500 70.27000 146.69500 70.67000 ;
     RECT 146.29500 94.27000 146.69500 94.67000 ;
     RECT 146.29500 122.27000 146.69500 122.67000 ;
     RECT 146.29500 129.47000 146.69500 129.87000 ;
     RECT 146.29500 159.07000 146.69500 159.47000 ;
     RECT 146.29500 178.27000 146.69500 178.67000 ;
     RECT 147.09500 19.07000 147.49500 19.47000 ;
     RECT 147.09500 26.27000 147.49500 26.67000 ;
     RECT 147.09500 68.67000 147.49500 69.07000 ;
     RECT 147.09500 71.07000 147.49500 71.47000 ;
     RECT 147.09500 85.47000 147.49500 85.87000 ;
     RECT 147.09500 116.67000 147.49500 117.07000 ;
     RECT 147.09500 139.87000 147.49500 140.27000 ;
     RECT 147.09500 163.87000 147.49500 164.27000 ;
     RECT 147.89500 63.07000 148.29500 63.47000 ;
     RECT 147.89500 88.67000 148.29500 89.07000 ;
     RECT 147.89500 107.87000 148.29500 108.27000 ;
     RECT 147.89500 124.67000 148.29500 125.07000 ;
     RECT 147.89500 157.47000 148.29500 157.87000 ;
     RECT 147.89500 174.27000 148.29500 174.67000 ;
     RECT 148.69500 62.27000 149.09500 62.67000 ;
     RECT 148.69500 65.47000 149.09500 65.87000 ;
     RECT 148.69500 87.87000 149.09500 88.27000 ;
     RECT 148.69500 160.67000 149.09500 161.07000 ;
     RECT 149.49500 35.07000 149.89500 35.47000 ;
     RECT 149.49500 70.27000 149.89500 70.67000 ;
     RECT 149.49500 86.27000 149.89500 86.67000 ;
     RECT 149.49500 139.07000 149.89500 139.47000 ;
     RECT 150.29500 47.87000 150.69500 48.27000 ;
     RECT 150.29500 51.07000 150.69500 51.47000 ;
     RECT 150.29500 78.27000 150.69500 78.67000 ;
     RECT 150.29500 83.87000 150.69500 84.27000 ;
     RECT 150.29500 92.67000 150.69500 93.07000 ;
     RECT 151.09500 24.67000 151.49500 25.07000 ;
     RECT 151.09500 28.67000 151.49500 29.07000 ;
     RECT 151.09500 63.87000 151.49500 64.27000 ;
     RECT 151.09500 77.47000 151.49500 77.87000 ;
     RECT 151.09500 89.47000 151.49500 89.87000 ;
     RECT 151.09500 131.07000 151.49500 131.47000 ;
     RECT 151.09500 140.67000 151.49500 141.07000 ;
     RECT 151.09500 156.67000 151.49500 157.07000 ;
     RECT 151.09500 194.27000 151.49500 194.67000 ;
     RECT 151.89500 21.47000 152.29500 21.87000 ;
     RECT 151.89500 51.87000 152.29500 52.27000 ;
     RECT 151.89500 127.87000 152.29500 128.27000 ;
     RECT 151.89500 129.47000 152.29500 129.87000 ;
     RECT 152.69500 71.07000 153.09500 71.47000 ;
     RECT 152.69500 78.27000 153.09500 78.67000 ;
     RECT 152.69500 134.27000 153.09500 134.67000 ;
     RECT 152.69500 139.07000 153.09500 139.47000 ;
     RECT 152.69500 142.27000 153.09500 142.67000 ;
     RECT 153.49500 33.47000 153.89500 33.87000 ;
     RECT 153.49500 62.27000 153.89500 62.67000 ;
     RECT 153.49500 94.27000 153.89500 94.67000 ;
     RECT 153.49500 132.67000 153.89500 133.07000 ;
     RECT 153.49500 140.67000 153.89500 141.07000 ;
     RECT 153.49500 157.47000 153.89500 157.87000 ;
     RECT 154.29500 17.47000 154.69500 17.87000 ;
     RECT 154.29500 24.67000 154.69500 25.07000 ;
     RECT 154.29500 51.07000 154.69500 51.47000 ;
     RECT 154.29500 73.47000 154.69500 73.87000 ;
     RECT 154.29500 88.67000 154.69500 89.07000 ;
     RECT 154.29500 102.27000 154.69500 102.67000 ;
     RECT 154.29500 114.27000 154.69500 114.67000 ;
     RECT 154.29500 127.87000 154.69500 128.27000 ;
     RECT 155.09500 14.27000 155.49500 14.67000 ;
     RECT 155.09500 19.87000 155.49500 20.27000 ;
     RECT 155.09500 38.27000 155.49500 38.67000 ;
     RECT 155.09500 65.47000 155.49500 65.87000 ;
     RECT 155.09500 78.27000 155.49500 78.67000 ;
     RECT 155.09500 87.87000 155.49500 88.27000 ;
     RECT 155.09500 115.07000 155.49500 115.47000 ;
     RECT 155.09500 141.47000 155.49500 141.87000 ;
     RECT 155.09500 162.27000 155.49500 162.67000 ;
     RECT 155.89500 36.67000 156.29500 37.07000 ;
     RECT 155.89500 51.87000 156.29500 52.27000 ;
     RECT 155.89500 62.27000 156.29500 62.67000 ;
     RECT 155.89500 67.87000 156.29500 68.27000 ;
     RECT 155.89500 95.07000 156.29500 95.47000 ;
     RECT 155.89500 126.27000 156.29500 126.67000 ;
     RECT 155.89500 147.87000 156.29500 148.27000 ;
     RECT 155.89500 153.47000 156.29500 153.87000 ;
     RECT 155.89500 160.67000 156.29500 161.07000 ;
     RECT 156.69500 19.07000 157.09500 19.47000 ;
     RECT 156.69500 57.47000 157.09500 57.87000 ;
     RECT 156.69500 63.07000 157.09500 63.47000 ;
     RECT 156.69500 80.67000 157.09500 81.07000 ;
     RECT 156.69500 85.47000 157.09500 85.87000 ;
     RECT 156.69500 87.87000 157.09500 88.27000 ;
     RECT 156.69500 122.27000 157.09500 122.67000 ;
     RECT 156.69500 132.67000 157.09500 133.07000 ;
     RECT 156.69500 134.27000 157.09500 134.67000 ;
     RECT 156.69500 145.47000 157.09500 145.87000 ;
     RECT 156.69500 169.47000 157.09500 169.87000 ;
     RECT 157.49500 23.87000 157.89500 24.27000 ;
     RECT 157.49500 32.67000 157.89500 33.07000 ;
     RECT 157.49500 53.47000 157.89500 53.87000 ;
     RECT 157.49500 79.87000 157.89500 80.27000 ;
     RECT 157.49500 99.07000 157.89500 99.47000 ;
     RECT 157.49500 123.07000 157.89500 123.47000 ;
     RECT 157.49500 124.67000 157.89500 125.07000 ;
     RECT 157.49500 167.87000 157.89500 168.27000 ;
     RECT 157.49500 183.87000 157.89500 184.27000 ;
     RECT 158.29500 22.27000 158.69500 22.67000 ;
     RECT 158.29500 39.07000 158.69500 39.47000 ;
     RECT 158.29500 67.07000 158.69500 67.47000 ;
     RECT 158.29500 94.27000 158.69500 94.67000 ;
     RECT 158.29500 97.47000 158.69500 97.87000 ;
     RECT 158.29500 130.27000 158.69500 130.67000 ;
     RECT 158.29500 141.47000 158.69500 141.87000 ;
     RECT 158.29500 161.47000 158.69500 161.87000 ;
     RECT 159.09500 13.47000 159.49500 13.87000 ;
     RECT 159.09500 29.47000 159.49500 29.87000 ;
     RECT 159.09500 74.27000 159.49500 74.67000 ;
     RECT 159.09500 113.47000 159.49500 113.87000 ;
     RECT 159.09500 119.07000 159.49500 119.47000 ;
     RECT 159.09500 129.47000 159.49500 129.87000 ;
     RECT 159.09500 144.67000 159.49500 145.07000 ;
     RECT 159.09500 160.67000 159.49500 161.07000 ;
     RECT 159.89500 27.87000 160.29500 28.27000 ;
     RECT 159.89500 33.47000 160.29500 33.87000 ;
     RECT 159.89500 35.07000 160.29500 35.47000 ;
     RECT 159.89500 43.87000 160.29500 44.27000 ;
     RECT 159.89500 51.07000 160.29500 51.47000 ;
     RECT 159.89500 58.27000 160.29500 58.67000 ;
     RECT 159.89500 79.87000 160.29500 80.27000 ;
     RECT 159.89500 92.67000 160.29500 93.07000 ;
     RECT 159.89500 109.47000 160.29500 109.87000 ;
     RECT 159.89500 114.27000 160.29500 114.67000 ;
     RECT 159.89500 117.47000 160.29500 117.87000 ;
     RECT 159.89500 122.27000 160.29500 122.67000 ;
     RECT 159.89500 143.07000 160.29500 143.47000 ;
     RECT 159.89500 161.47000 160.29500 161.87000 ;
     RECT 159.89500 169.47000 160.29500 169.87000 ;
     RECT 160.69500 22.27000 161.09500 22.67000 ;
     RECT 160.69500 53.47000 161.09500 53.87000 ;
     RECT 160.69500 85.47000 161.09500 85.87000 ;
     RECT 160.69500 102.27000 161.09500 102.67000 ;
     RECT 160.69500 143.87000 161.09500 144.27000 ;
     RECT 160.69500 176.67000 161.09500 177.07000 ;
     RECT 161.49500 27.87000 161.89500 28.27000 ;
     RECT 161.49500 59.07000 161.89500 59.47000 ;
     RECT 161.49500 67.87000 161.89500 68.27000 ;
     RECT 161.49500 77.47000 161.89500 77.87000 ;
     RECT 161.49500 87.07000 161.89500 87.47000 ;
     RECT 161.49500 95.07000 161.89500 95.47000 ;
     RECT 161.49500 107.87000 161.89500 108.27000 ;
     RECT 161.49500 111.07000 161.89500 111.47000 ;
     RECT 161.49500 124.67000 161.89500 125.07000 ;
     RECT 161.49500 148.67000 161.89500 149.07000 ;
     RECT 161.49500 158.27000 161.89500 158.67000 ;
     RECT 161.49500 169.47000 161.89500 169.87000 ;
     RECT 162.29500 47.87000 162.69500 48.27000 ;
     RECT 162.29500 55.87000 162.69500 56.27000 ;
     RECT 162.29500 71.07000 162.69500 71.47000 ;
     RECT 162.29500 130.27000 162.69500 130.67000 ;
     RECT 162.29500 143.07000 162.69500 143.47000 ;
     RECT 162.29500 155.07000 162.69500 155.47000 ;
     RECT 163.09500 36.67000 163.49500 37.07000 ;
     RECT 163.09500 63.07000 163.49500 63.47000 ;
     RECT 163.09500 107.87000 163.49500 108.27000 ;
     RECT 163.09500 112.67000 163.49500 113.07000 ;
     RECT 163.09500 118.27000 163.49500 118.67000 ;
     RECT 163.09500 148.67000 163.49500 149.07000 ;
     RECT 163.89500 29.47000 164.29500 29.87000 ;
     RECT 163.89500 47.87000 164.29500 48.27000 ;
     RECT 163.89500 99.07000 164.29500 99.47000 ;
     RECT 163.89500 109.47000 164.29500 109.87000 ;
     RECT 163.89500 131.07000 164.29500 131.47000 ;
     RECT 163.89500 139.87000 164.29500 140.27000 ;
     RECT 163.89500 155.07000 164.29500 155.47000 ;
     RECT 164.69500 23.87000 165.09500 24.27000 ;
     RECT 164.69500 33.47000 165.09500 33.87000 ;
     RECT 164.69500 40.67000 165.09500 41.07000 ;
     RECT 164.69500 42.27000 165.09500 42.67000 ;
     RECT 164.69500 63.87000 165.09500 64.27000 ;
     RECT 164.69500 72.67000 165.09500 73.07000 ;
     RECT 164.69500 81.47000 165.09500 81.87000 ;
     RECT 164.69500 87.07000 165.09500 87.47000 ;
     RECT 164.69500 94.27000 165.09500 94.67000 ;
     RECT 164.69500 103.87000 165.09500 104.27000 ;
     RECT 164.69500 141.47000 165.09500 141.87000 ;
     RECT 165.49500 49.47000 165.89500 49.87000 ;
     RECT 165.49500 79.87000 165.89500 80.27000 ;
     RECT 165.49500 112.67000 165.89500 113.07000 ;
     RECT 165.49500 155.07000 165.89500 155.47000 ;
     RECT 166.29500 55.07000 166.69500 55.47000 ;
     RECT 166.29500 59.07000 166.69500 59.47000 ;
     RECT 166.29500 68.67000 166.69500 69.07000 ;
     RECT 166.29500 87.87000 166.69500 88.27000 ;
     RECT 166.29500 115.87000 166.69500 116.27000 ;
     RECT 166.29500 162.27000 166.69500 162.67000 ;
     RECT 167.09500 56.67000 167.49500 57.07000 ;
     RECT 167.09500 83.07000 167.49500 83.47000 ;
     RECT 167.09500 87.07000 167.49500 87.47000 ;
     RECT 167.09500 115.07000 167.49500 115.47000 ;
     RECT 167.09500 140.67000 167.49500 141.07000 ;
     RECT 167.09500 144.67000 167.49500 145.07000 ;
     RECT 167.09500 154.27000 167.49500 154.67000 ;
     RECT 167.09500 159.07000 167.49500 159.47000 ;
     RECT 167.09500 188.67000 167.49500 189.07000 ;
     RECT 167.89500 19.07000 168.29500 19.47000 ;
     RECT 167.89500 71.07000 168.29500 71.47000 ;
     RECT 167.89500 72.67000 168.29500 73.07000 ;
     RECT 167.89500 177.47000 168.29500 177.87000 ;
     RECT 167.89500 179.07000 168.29500 179.47000 ;
     RECT 168.69500 27.87000 169.09500 28.27000 ;
     RECT 168.69500 43.87000 169.09500 44.27000 ;
     RECT 168.69500 68.67000 169.09500 69.07000 ;
     RECT 168.69500 137.47000 169.09500 137.87000 ;
     RECT 168.69500 156.67000 169.09500 157.07000 ;
     RECT 168.69500 163.07000 169.09500 163.47000 ;
     RECT 169.49500 12.67000 169.89500 13.07000 ;
     RECT 169.49500 29.47000 169.89500 29.87000 ;
     RECT 169.49500 47.87000 169.89500 48.27000 ;
     RECT 169.49500 66.27000 169.89500 66.67000 ;
     RECT 169.49500 70.27000 169.89500 70.67000 ;
     RECT 169.49500 71.87000 169.89500 72.27000 ;
     RECT 169.49500 100.67000 169.89500 101.07000 ;
     RECT 169.49500 134.27000 169.89500 134.67000 ;
     RECT 169.49500 148.67000 169.89500 149.07000 ;
     RECT 169.49500 159.07000 169.89500 159.47000 ;
     RECT 170.29500 28.67000 170.69500 29.07000 ;
     RECT 170.29500 71.07000 170.69500 71.47000 ;
     RECT 170.29500 113.47000 170.69500 113.87000 ;
     RECT 170.29500 126.27000 170.69500 126.67000 ;
     RECT 170.29500 147.87000 170.69500 148.27000 ;
     RECT 170.29500 149.47000 170.69500 149.87000 ;
     RECT 170.29500 167.87000 170.69500 168.27000 ;
     RECT 171.09500 5.47000 171.49500 5.87000 ;
     RECT 171.09500 40.67000 171.49500 41.07000 ;
     RECT 171.09500 63.07000 171.49500 63.47000 ;
     RECT 171.09500 66.27000 171.49500 66.67000 ;
     RECT 171.09500 71.87000 171.49500 72.27000 ;
     RECT 171.09500 87.07000 171.49500 87.47000 ;
     RECT 171.09500 100.67000 171.49500 101.07000 ;
     RECT 171.09500 146.27000 171.49500 146.67000 ;
     RECT 171.09500 155.07000 171.49500 155.47000 ;
     RECT 171.89500 77.47000 172.29500 77.87000 ;
     RECT 171.89500 117.47000 172.29500 117.87000 ;
     RECT 171.89500 154.27000 172.29500 154.67000 ;
     RECT 172.69500 14.27000 173.09500 14.67000 ;
     RECT 172.69500 38.27000 173.09500 38.67000 ;
     RECT 172.69500 67.87000 173.09500 68.27000 ;
     RECT 172.69500 97.47000 173.09500 97.87000 ;
     RECT 172.69500 139.07000 173.09500 139.47000 ;
     RECT 172.69500 152.67000 173.09500 153.07000 ;
     RECT 172.69500 171.07000 173.09500 171.47000 ;
     RECT 173.49500 26.27000 173.89500 26.67000 ;
     RECT 173.49500 62.27000 173.89500 62.67000 ;
     RECT 173.49500 118.27000 173.89500 118.67000 ;
     RECT 173.49500 154.27000 173.89500 154.67000 ;
     RECT 173.49500 167.87000 173.89500 168.27000 ;
     RECT 174.29500 33.47000 174.69500 33.87000 ;
     RECT 174.29500 43.07000 174.69500 43.47000 ;
     RECT 174.29500 79.87000 174.69500 80.27000 ;
     RECT 174.29500 110.27000 174.69500 110.67000 ;
     RECT 174.29500 140.67000 174.69500 141.07000 ;
     RECT 174.29500 145.47000 174.69500 145.87000 ;
     RECT 174.29500 147.87000 174.69500 148.27000 ;
     RECT 174.29500 162.27000 174.69500 162.67000 ;
     RECT 175.09500 34.27000 175.49500 34.67000 ;
     RECT 175.09500 51.07000 175.49500 51.47000 ;
     RECT 175.09500 92.67000 175.49500 93.07000 ;
     RECT 175.09500 102.27000 175.49500 102.67000 ;
     RECT 175.09500 139.87000 175.49500 140.27000 ;
     RECT 175.09500 143.87000 175.49500 144.27000 ;
     RECT 175.09500 158.27000 175.49500 158.67000 ;
     RECT 175.09500 168.67000 175.49500 169.07000 ;
     RECT 175.89500 42.27000 176.29500 42.67000 ;
     RECT 175.89500 97.47000 176.29500 97.87000 ;
     RECT 175.89500 123.07000 176.29500 123.47000 ;
     RECT 176.69500 72.67000 177.09500 73.07000 ;
     RECT 176.69500 83.07000 177.09500 83.47000 ;
     RECT 176.69500 144.67000 177.09500 145.07000 ;
     RECT 177.49500 47.87000 177.89500 48.27000 ;
     RECT 177.49500 70.27000 177.89500 70.67000 ;
     RECT 177.49500 103.87000 177.89500 104.27000 ;
     RECT 177.49500 143.07000 177.89500 143.47000 ;
     RECT 177.49500 154.27000 177.89500 154.67000 ;
     RECT 178.29500 18.27000 178.69500 18.67000 ;
     RECT 178.29500 34.27000 178.69500 34.67000 ;
     RECT 178.29500 42.27000 178.69500 42.67000 ;
     RECT 178.29500 63.07000 178.69500 63.47000 ;
     RECT 178.29500 139.87000 178.69500 140.27000 ;
     RECT 178.29500 161.47000 178.69500 161.87000 ;
     RECT 179.09500 35.87000 179.49500 36.27000 ;
     RECT 179.09500 51.07000 179.49500 51.47000 ;
     RECT 179.09500 88.67000 179.49500 89.07000 ;
     RECT 179.09500 110.27000 179.49500 110.67000 ;
     RECT 179.09500 143.07000 179.49500 143.47000 ;
     RECT 179.09500 167.87000 179.49500 168.27000 ;
     RECT 179.89500 43.87000 180.29500 44.27000 ;
     RECT 179.89500 74.27000 180.29500 74.67000 ;
     RECT 179.89500 95.07000 180.29500 95.47000 ;
     RECT 179.89500 108.67000 180.29500 109.07000 ;
     RECT 179.89500 111.87000 180.29500 112.27000 ;
     RECT 179.89500 133.47000 180.29500 133.87000 ;
     RECT 180.69500 89.47000 181.09500 89.87000 ;
     RECT 181.49500 41.47000 181.89500 41.87000 ;
     RECT 181.49500 43.87000 181.89500 44.27000 ;
     RECT 181.49500 68.67000 181.89500 69.07000 ;
     RECT 181.49500 174.27000 181.89500 174.67000 ;
     RECT 182.29500 66.27000 182.69500 66.67000 ;
     RECT 182.29500 77.47000 182.69500 77.87000 ;
     RECT 182.29500 102.27000 182.69500 102.67000 ;
     RECT 182.29500 103.87000 182.69500 104.27000 ;
     RECT 182.29500 140.67000 182.69500 141.07000 ;
     RECT 182.29500 153.47000 182.69500 153.87000 ;
     RECT 183.09500 13.47000 183.49500 13.87000 ;
     RECT 183.09500 26.27000 183.49500 26.67000 ;
     RECT 183.09500 64.67000 183.49500 65.07000 ;
     RECT 183.09500 95.07000 183.49500 95.47000 ;
     RECT 183.09500 132.67000 183.49500 133.07000 ;
     RECT 183.09500 147.87000 183.49500 148.27000 ;
     RECT 183.09500 162.27000 183.49500 162.67000 ;
     RECT 183.89500 39.07000 184.29500 39.47000 ;
     RECT 183.89500 79.87000 184.29500 80.27000 ;
     RECT 183.89500 133.47000 184.29500 133.87000 ;
     RECT 183.89500 145.47000 184.29500 145.87000 ;
     RECT 184.69500 34.27000 185.09500 34.67000 ;
     RECT 184.69500 54.27000 185.09500 54.67000 ;
     RECT 184.69500 95.07000 185.09500 95.47000 ;
     RECT 184.69500 103.87000 185.09500 104.27000 ;
     RECT 184.69500 113.47000 185.09500 113.87000 ;
     RECT 184.69500 143.87000 185.09500 144.27000 ;
     RECT 185.49500 7.87000 185.89500 8.27000 ;
     RECT 185.49500 43.07000 185.89500 43.47000 ;
     RECT 185.49500 65.47000 185.89500 65.87000 ;
     RECT 185.49500 74.27000 185.89500 74.67000 ;
     RECT 185.49500 123.07000 185.89500 123.47000 ;
     RECT 185.49500 144.67000 185.89500 145.07000 ;
     RECT 186.29500 47.87000 186.69500 48.27000 ;
     RECT 186.29500 71.07000 186.69500 71.47000 ;
     RECT 186.29500 92.67000 186.69500 93.07000 ;
     RECT 186.29500 117.47000 186.69500 117.87000 ;
     RECT 186.29500 141.47000 186.69500 141.87000 ;
     RECT 186.29500 162.27000 186.69500 162.67000 ;
     RECT 186.29500 176.67000 186.69500 177.07000 ;
     RECT 187.09500 27.87000 187.49500 28.27000 ;
     RECT 187.09500 54.27000 187.49500 54.67000 ;
     RECT 187.09500 79.07000 187.49500 79.47000 ;
     RECT 187.09500 97.47000 187.49500 97.87000 ;
     RECT 187.09500 124.67000 187.49500 125.07000 ;
     RECT 187.09500 139.87000 187.49500 140.27000 ;
     RECT 187.09500 144.67000 187.49500 145.07000 ;
     RECT 187.09500 171.07000 187.49500 171.47000 ;
     RECT 187.89500 24.67000 188.29500 25.07000 ;
     RECT 187.89500 43.87000 188.29500 44.27000 ;
     RECT 187.89500 48.67000 188.29500 49.07000 ;
     RECT 187.89500 53.47000 188.29500 53.87000 ;
     RECT 187.89500 63.87000 188.29500 64.27000 ;
     RECT 187.89500 73.47000 188.29500 73.87000 ;
     RECT 187.89500 92.67000 188.29500 93.07000 ;
     RECT 187.89500 102.27000 188.29500 102.67000 ;
     RECT 187.89500 125.47000 188.29500 125.87000 ;
     RECT 187.89500 149.47000 188.29500 149.87000 ;
     RECT 187.89500 161.47000 188.29500 161.87000 ;
     RECT 188.69500 11.07000 189.09500 11.47000 ;
     RECT 188.69500 23.87000 189.09500 24.27000 ;
     RECT 188.69500 42.27000 189.09500 42.67000 ;
     RECT 188.69500 69.47000 189.09500 69.87000 ;
     RECT 188.69500 88.67000 189.09500 89.07000 ;
     RECT 188.69500 133.47000 189.09500 133.87000 ;
     RECT 188.69500 141.47000 189.09500 141.87000 ;
     RECT 188.69500 147.07000 189.09500 147.47000 ;
     RECT 189.49500 27.87000 189.89500 28.27000 ;
     RECT 189.49500 67.87000 189.89500 68.27000 ;
     RECT 189.49500 117.47000 189.89500 117.87000 ;
     RECT 189.49500 139.07000 189.89500 139.47000 ;
     RECT 189.49500 144.67000 189.89500 145.07000 ;
     RECT 189.49500 147.87000 189.89500 148.27000 ;
     RECT 189.49500 178.27000 189.89500 178.67000 ;
     RECT 190.29500 13.47000 190.69500 13.87000 ;
     RECT 190.29500 33.47000 190.69500 33.87000 ;
     RECT 190.29500 162.27000 190.69500 162.67000 ;
     RECT 191.09500 23.87000 191.49500 24.27000 ;
     RECT 191.09500 50.27000 191.49500 50.67000 ;
     RECT 191.09500 52.67000 191.49500 53.07000 ;
     RECT 191.09500 66.27000 191.49500 66.67000 ;
     RECT 191.09500 83.07000 191.49500 83.47000 ;
     RECT 191.09500 94.27000 191.49500 94.67000 ;
     RECT 191.09500 118.27000 191.49500 118.67000 ;
     RECT 191.09500 144.67000 191.49500 145.07000 ;
     RECT 191.09500 160.67000 191.49500 161.07000 ;
     RECT 191.89500 51.07000 192.29500 51.47000 ;
     RECT 191.89500 107.87000 192.29500 108.27000 ;
     RECT 191.89500 109.47000 192.29500 109.87000 ;
     RECT 191.89500 127.07000 192.29500 127.47000 ;
     RECT 191.89500 129.47000 192.29500 129.87000 ;
     RECT 191.89500 138.27000 192.29500 138.67000 ;
     RECT 191.89500 162.27000 192.29500 162.67000 ;
     RECT 192.69500 19.07000 193.09500 19.47000 ;
     RECT 192.69500 32.67000 193.09500 33.07000 ;
     RECT 192.69500 56.67000 193.09500 57.07000 ;
     RECT 192.69500 88.67000 193.09500 89.07000 ;
     RECT 192.69500 111.87000 193.09500 112.27000 ;
     RECT 192.69500 142.27000 193.09500 142.67000 ;
     RECT 193.49500 51.07000 193.89500 51.47000 ;
     RECT 193.49500 55.07000 193.89500 55.47000 ;
     RECT 193.49500 107.87000 193.89500 108.27000 ;
     RECT 193.49500 129.47000 193.89500 129.87000 ;
     RECT 193.49500 139.87000 193.89500 140.27000 ;
     RECT 193.49500 159.87000 193.89500 160.27000 ;
     RECT 194.29500 12.67000 194.69500 13.07000 ;
     RECT 194.29500 42.27000 194.69500 42.67000 ;
     RECT 194.29500 64.67000 194.69500 65.07000 ;
     RECT 194.29500 79.87000 194.69500 80.27000 ;
     RECT 194.29500 92.67000 194.69500 93.07000 ;
     RECT 194.29500 103.87000 194.69500 104.27000 ;
     RECT 194.29500 123.07000 194.69500 123.47000 ;
     RECT 194.29500 146.27000 194.69500 146.67000 ;
     RECT 195.09500 6.27000 195.49500 6.67000 ;
     RECT 195.09500 22.27000 195.49500 22.67000 ;
     RECT 195.09500 39.87000 195.49500 40.27000 ;
     RECT 195.09500 49.47000 195.49500 49.87000 ;
     RECT 195.09500 69.47000 195.49500 69.87000 ;
     RECT 195.09500 74.27000 195.49500 74.67000 ;
     RECT 195.09500 127.87000 195.49500 128.27000 ;
     RECT 195.09500 152.67000 195.49500 153.07000 ;
     RECT 195.09500 163.87000 195.49500 164.27000 ;
     RECT 195.89500 7.07000 196.29500 7.47000 ;
     RECT 195.89500 47.87000 196.29500 48.27000 ;
     RECT 195.89500 53.47000 196.29500 53.87000 ;
     RECT 195.89500 78.27000 196.29500 78.67000 ;
     RECT 195.89500 103.87000 196.29500 104.27000 ;
     RECT 195.89500 129.47000 196.29500 129.87000 ;
     RECT 195.89500 156.67000 196.29500 157.07000 ;
     RECT 195.89500 169.47000 196.29500 169.87000 ;
     RECT 196.69500 38.27000 197.09500 38.67000 ;
     RECT 196.69500 56.67000 197.09500 57.07000 ;
     RECT 196.69500 93.47000 197.09500 93.87000 ;
     RECT 196.69500 119.07000 197.09500 119.47000 ;
     RECT 196.69500 170.27000 197.09500 170.67000 ;
     RECT 197.49500 57.47000 197.89500 57.87000 ;
     RECT 197.49500 73.47000 197.89500 73.87000 ;
     RECT 197.49500 126.27000 197.89500 126.67000 ;
     RECT 197.49500 167.87000 197.89500 168.27000 ;
     RECT 199.89500 7.87000 200.29500 8.27000 ;
     RECT 199.89500 68.67000 200.29500 69.07000 ;
     RECT 199.89500 72.67000 200.29500 73.07000 ;
     RECT 200.69500 124.67000 201.09500 125.07000 ;
     RECT 200.69500 159.87000 201.09500 160.27000 ;
     RECT 201.49500 85.47000 201.89500 85.87000 ;
     RECT 201.49500 115.87000 201.89500 116.27000 ;
     RECT 201.49500 152.67000 201.89500 153.07000 ;
     RECT 202.29500 39.87000 202.69500 40.27000 ;
     RECT 202.29500 67.87000 202.69500 68.27000 ;
     RECT 202.29500 118.27000 202.69500 118.67000 ;
     RECT 202.29500 176.67000 202.69500 177.07000 ;
     RECT 203.09500 66.27000 203.49500 66.67000 ;
     RECT 203.09500 148.67000 203.49500 149.07000 ;
     RECT 203.89500 38.27000 204.29500 38.67000 ;
     RECT 203.89500 92.67000 204.29500 93.07000 ;
     RECT 204.69500 175.87000 205.09500 176.27000 ;
     RECT 205.49500 19.07000 205.89500 19.47000 ;
     RECT 205.49500 92.67000 205.89500 93.07000 ;
     RECT 205.49500 115.07000 205.89500 115.47000 ;
     RECT 206.29500 12.67000 206.69500 13.07000 ;
     RECT 206.29500 50.27000 206.69500 50.67000 ;
     RECT 206.29500 93.47000 206.69500 93.87000 ;
     RECT 206.29500 143.87000 206.69500 144.27000 ;
     RECT 207.09500 78.27000 207.49500 78.67000 ;
     RECT 207.09500 179.87000 207.49500 180.27000 ;
     RECT 207.89500 63.87000 208.29500 64.27000 ;
     RECT 207.89500 138.27000 208.29500 138.67000 ;
     RECT 207.89500 145.47000 208.29500 145.87000 ;
     RECT 208.69500 130.27000 209.09500 130.67000 ;
    LAYER via8 ;
     RECT 13.49500 135.87000 13.89500 136.27000 ;
     RECT 15.09500 129.47000 15.49500 129.87000 ;
     RECT 15.89500 148.67000 16.29500 149.07000 ;
     RECT 16.69500 63.87000 17.09500 64.27000 ;
     RECT 16.69500 94.27000 17.09500 94.67000 ;
     RECT 16.69500 156.67000 17.09500 157.07000 ;
     RECT 18.29500 211.07000 18.69500 211.47000 ;
     RECT 22.29500 86.27000 22.69500 86.67000 ;
     RECT 22.29500 103.87000 22.69500 104.27000 ;
     RECT 22.29500 113.47000 22.69500 113.87000 ;
     RECT 22.29500 143.87000 22.69500 144.27000 ;
     RECT 23.09500 38.27000 23.49500 38.67000 ;
     RECT 23.89500 54.27000 24.29500 54.67000 ;
     RECT 23.89500 127.87000 24.29500 128.27000 ;
     RECT 23.89500 166.27000 24.29500 166.67000 ;
     RECT 24.69500 199.87000 25.09500 200.27000 ;
     RECT 25.49500 79.87000 25.89500 80.27000 ;
     RECT 25.49500 129.47000 25.89500 129.87000 ;
     RECT 26.29500 115.07000 26.69500 115.47000 ;
     RECT 27.09500 159.87000 27.49500 160.27000 ;
     RECT 27.09500 161.47000 27.49500 161.87000 ;
     RECT 27.89500 62.27000 28.29500 62.67000 ;
     RECT 27.89500 193.47000 28.29500 193.87000 ;
     RECT 30.29500 140.67000 30.69500 141.07000 ;
     RECT 30.29500 187.07000 30.69500 187.47000 ;
     RECT 31.09500 123.07000 31.49500 123.47000 ;
     RECT 31.09500 159.87000 31.49500 160.27000 ;
     RECT 31.09500 163.07000 31.49500 163.47000 ;
     RECT 31.09500 182.27000 31.49500 182.67000 ;
     RECT 31.89500 54.27000 32.29500 54.67000 ;
     RECT 31.89500 60.67000 32.29500 61.07000 ;
     RECT 31.89500 166.27000 32.29500 166.67000 ;
     RECT 32.69500 135.87000 33.09500 136.27000 ;
     RECT 33.49500 99.07000 33.89500 99.47000 ;
     RECT 33.49500 121.47000 33.89500 121.87000 ;
     RECT 33.49500 126.27000 33.89500 126.67000 ;
     RECT 33.49500 169.47000 33.89500 169.87000 ;
     RECT 35.09500 180.67000 35.49500 181.07000 ;
     RECT 35.89500 83.07000 36.29500 83.47000 ;
     RECT 36.69500 62.27000 37.09500 62.67000 ;
     RECT 36.69500 145.47000 37.09500 145.87000 ;
     RECT 36.69500 161.47000 37.09500 161.87000 ;
     RECT 37.49500 51.07000 37.89500 51.47000 ;
     RECT 37.49500 59.07000 37.89500 59.47000 ;
     RECT 37.49500 89.47000 37.89500 89.87000 ;
     RECT 38.29500 75.07000 38.69500 75.47000 ;
     RECT 38.29500 132.67000 38.69500 133.07000 ;
     RECT 38.29500 155.07000 38.69500 155.47000 ;
     RECT 38.29500 177.47000 38.69500 177.87000 ;
     RECT 39.09500 102.27000 39.49500 102.67000 ;
     RECT 39.09500 163.07000 39.49500 163.47000 ;
     RECT 39.89500 54.27000 40.29500 54.67000 ;
     RECT 41.49500 151.87000 41.89500 152.27000 ;
     RECT 41.49500 166.27000 41.89500 166.67000 ;
     RECT 43.09500 62.27000 43.49500 62.67000 ;
     RECT 43.09500 86.27000 43.49500 86.67000 ;
     RECT 43.09500 94.27000 43.49500 94.67000 ;
     RECT 43.09500 103.87000 43.49500 104.27000 ;
     RECT 43.09500 107.07000 43.49500 107.47000 ;
     RECT 43.89500 68.67000 44.29500 69.07000 ;
     RECT 44.69500 161.47000 45.09500 161.87000 ;
     RECT 44.69500 190.27000 45.09500 190.67000 ;
     RECT 45.49500 193.47000 45.89500 193.87000 ;
     RECT 46.29500 159.87000 46.69500 160.27000 ;
     RECT 47.09500 54.27000 47.49500 54.67000 ;
     RECT 47.09500 89.47000 47.49500 89.87000 ;
     RECT 47.09500 166.27000 47.49500 166.67000 ;
     RECT 47.89500 145.47000 48.29500 145.87000 ;
     RECT 47.89500 161.47000 48.29500 161.87000 ;
     RECT 47.89500 199.87000 48.29500 200.27000 ;
     RECT 48.69500 60.67000 49.09500 61.07000 ;
     RECT 48.69500 73.47000 49.09500 73.87000 ;
     RECT 48.69500 78.27000 49.09500 78.67000 ;
     RECT 49.49500 169.47000 49.89500 169.87000 ;
     RECT 49.49500 187.07000 49.89500 187.47000 ;
     RECT 50.29500 123.07000 50.69500 123.47000 ;
     RECT 50.29500 142.27000 50.69500 142.67000 ;
     RECT 51.09500 57.47000 51.49500 57.87000 ;
     RECT 51.09500 71.87000 51.49500 72.27000 ;
     RECT 51.09500 79.87000 51.49500 80.27000 ;
     RECT 51.09500 148.67000 51.49500 149.07000 ;
     RECT 51.09500 161.47000 51.49500 161.87000 ;
     RECT 51.09500 206.27000 51.49500 206.67000 ;
     RECT 51.89500 62.27000 52.29500 62.67000 ;
     RECT 51.89500 99.07000 52.29500 99.47000 ;
     RECT 51.89500 159.87000 52.29500 160.27000 ;
     RECT 51.89500 195.07000 52.29500 195.47000 ;
     RECT 51.89500 199.87000 52.29500 200.27000 ;
     RECT 52.69500 63.87000 53.09500 64.27000 ;
     RECT 53.49500 70.27000 53.89500 70.67000 ;
     RECT 53.49500 78.27000 53.89500 78.67000 ;
     RECT 54.29500 83.07000 54.69500 83.47000 ;
     RECT 54.29500 182.27000 54.69500 182.67000 ;
     RECT 54.29500 203.07000 54.69500 203.47000 ;
     RECT 55.09500 89.47000 55.49500 89.87000 ;
     RECT 55.09500 97.47000 55.49500 97.87000 ;
     RECT 55.09500 161.47000 55.49500 161.87000 ;
     RECT 55.89500 25.47000 56.29500 25.87000 ;
     RECT 55.89500 33.47000 56.29500 33.87000 ;
     RECT 55.89500 41.47000 56.29500 41.87000 ;
     RECT 55.89500 54.27000 56.29500 54.67000 ;
     RECT 55.89500 79.87000 56.29500 80.27000 ;
     RECT 55.89500 81.47000 56.29500 81.87000 ;
     RECT 55.89500 86.27000 56.29500 86.67000 ;
     RECT 55.89500 110.27000 56.29500 110.67000 ;
     RECT 55.89500 123.07000 56.29500 123.47000 ;
     RECT 55.89500 129.47000 56.29500 129.87000 ;
     RECT 55.89500 155.07000 56.29500 155.47000 ;
     RECT 55.89500 159.87000 56.29500 160.27000 ;
     RECT 56.69500 68.67000 57.09500 69.07000 ;
     RECT 56.69500 78.27000 57.09500 78.67000 ;
     RECT 56.69500 102.27000 57.09500 102.67000 ;
     RECT 56.69500 180.67000 57.09500 181.07000 ;
     RECT 57.49500 46.27000 57.89500 46.67000 ;
     RECT 57.49500 59.07000 57.89500 59.47000 ;
     RECT 57.49500 70.27000 57.89500 70.67000 ;
     RECT 57.49500 84.67000 57.89500 85.07000 ;
     RECT 57.49500 92.67000 57.89500 93.07000 ;
     RECT 57.49500 100.67000 57.89500 101.07000 ;
     RECT 57.49500 107.07000 57.89500 107.47000 ;
     RECT 57.49500 126.27000 57.89500 126.67000 ;
     RECT 57.49500 137.47000 57.89500 137.87000 ;
     RECT 57.49500 143.87000 57.89500 144.27000 ;
     RECT 57.49500 155.07000 57.89500 155.47000 ;
     RECT 57.49500 158.27000 57.89500 158.67000 ;
     RECT 58.29500 156.67000 58.69500 157.07000 ;
     RECT 59.09500 25.47000 59.49500 25.87000 ;
     RECT 59.09500 35.07000 59.49500 35.47000 ;
     RECT 59.09500 44.67000 59.49500 45.07000 ;
     RECT 59.09500 57.47000 59.49500 57.87000 ;
     RECT 59.09500 59.07000 59.49500 59.47000 ;
     RECT 59.09500 76.67000 59.49500 77.07000 ;
     RECT 59.09500 105.47000 59.49500 105.87000 ;
     RECT 59.09500 118.27000 59.49500 118.67000 ;
     RECT 59.09500 123.07000 59.49500 123.47000 ;
     RECT 59.09500 124.67000 59.49500 125.07000 ;
     RECT 59.09500 131.07000 59.49500 131.47000 ;
     RECT 59.09500 161.47000 59.49500 161.87000 ;
     RECT 59.09500 193.47000 59.49500 193.87000 ;
     RECT 59.89500 62.27000 60.29500 62.67000 ;
     RECT 59.89500 78.27000 60.29500 78.67000 ;
     RECT 59.89500 102.27000 60.29500 102.67000 ;
     RECT 59.89500 198.27000 60.29500 198.67000 ;
     RECT 62.29500 100.67000 62.69500 101.07000 ;
     RECT 63.09500 65.47000 63.49500 65.87000 ;
     RECT 63.09500 115.07000 63.49500 115.47000 ;
     RECT 63.09500 156.67000 63.49500 157.07000 ;
     RECT 63.89500 54.27000 64.29500 54.67000 ;
     RECT 63.89500 71.87000 64.29500 72.27000 ;
     RECT 63.89500 79.87000 64.29500 80.27000 ;
     RECT 63.89500 86.27000 64.29500 86.67000 ;
     RECT 63.89500 113.47000 64.29500 113.87000 ;
     RECT 63.89500 139.07000 64.29500 139.47000 ;
     RECT 63.89500 143.87000 64.29500 144.27000 ;
     RECT 63.89500 161.47000 64.29500 161.87000 ;
     RECT 63.89500 175.87000 64.29500 176.27000 ;
     RECT 65.49500 143.87000 65.89500 144.27000 ;
     RECT 66.29500 52.67000 66.69500 53.07000 ;
     RECT 66.29500 62.27000 66.69500 62.67000 ;
     RECT 66.29500 89.47000 66.69500 89.87000 ;
     RECT 66.29500 94.27000 66.69500 94.67000 ;
     RECT 67.09500 70.27000 67.49500 70.67000 ;
     RECT 67.09500 91.07000 67.49500 91.47000 ;
     RECT 67.89500 62.27000 68.29500 62.67000 ;
     RECT 67.89500 65.47000 68.29500 65.87000 ;
     RECT 67.89500 161.47000 68.29500 161.87000 ;
     RECT 68.69500 39.87000 69.09500 40.27000 ;
     RECT 68.69500 55.87000 69.09500 56.27000 ;
     RECT 68.69500 118.27000 69.09500 118.67000 ;
     RECT 68.69500 121.47000 69.09500 121.87000 ;
     RECT 68.69500 126.27000 69.09500 126.67000 ;
     RECT 69.49500 97.47000 69.89500 97.87000 ;
     RECT 69.49500 143.87000 69.89500 144.27000 ;
     RECT 70.29500 105.47000 70.69500 105.87000 ;
     RECT 70.29500 123.07000 70.69500 123.47000 ;
     RECT 71.89500 54.27000 72.29500 54.67000 ;
     RECT 71.89500 190.27000 72.29500 190.67000 ;
     RECT 72.69500 164.67000 73.09500 165.07000 ;
     RECT 72.69500 199.87000 73.09500 200.27000 ;
     RECT 73.49500 166.27000 73.89500 166.67000 ;
     RECT 74.29500 155.07000 74.69500 155.47000 ;
     RECT 75.09500 57.47000 75.49500 57.87000 ;
     RECT 75.09500 68.67000 75.49500 69.07000 ;
     RECT 75.09500 75.07000 75.49500 75.47000 ;
     RECT 75.09500 129.47000 75.49500 129.87000 ;
     RECT 75.09500 161.47000 75.49500 161.87000 ;
     RECT 75.09500 193.47000 75.49500 193.87000 ;
     RECT 76.69500 79.87000 77.09500 80.27000 ;
     RECT 77.49500 150.27000 77.89500 150.67000 ;
     RECT 78.29500 94.27000 78.69500 94.67000 ;
     RECT 78.29500 129.47000 78.69500 129.87000 ;
     RECT 78.29500 174.27000 78.69500 174.67000 ;
     RECT 79.09500 63.87000 79.49500 64.27000 ;
     RECT 79.09500 195.07000 79.49500 195.47000 ;
     RECT 79.89500 54.27000 80.29500 54.67000 ;
     RECT 79.89500 187.07000 80.29500 187.47000 ;
     RECT 80.69500 164.67000 81.09500 165.07000 ;
     RECT 81.49500 60.67000 81.89500 61.07000 ;
     RECT 81.49500 91.07000 81.89500 91.47000 ;
     RECT 82.29500 177.47000 82.69500 177.87000 ;
     RECT 82.29500 206.27000 82.69500 206.67000 ;
     RECT 83.09500 161.47000 83.49500 161.87000 ;
     RECT 83.09500 198.27000 83.49500 198.67000 ;
     RECT 83.89500 71.87000 84.29500 72.27000 ;
     RECT 84.69500 63.87000 85.09500 64.27000 ;
     RECT 85.49500 158.27000 85.89500 158.67000 ;
     RECT 85.49500 163.07000 85.89500 163.47000 ;
     RECT 85.49500 185.47000 85.89500 185.87000 ;
     RECT 86.29500 161.47000 86.69500 161.87000 ;
     RECT 87.89500 54.27000 88.29500 54.67000 ;
     RECT 87.89500 73.47000 88.29500 73.87000 ;
     RECT 88.69500 126.27000 89.09500 126.67000 ;
     RECT 88.69500 193.47000 89.09500 193.87000 ;
     RECT 88.69500 203.07000 89.09500 203.47000 ;
     RECT 89.49500 62.27000 89.89500 62.67000 ;
     RECT 89.49500 65.47000 89.89500 65.87000 ;
     RECT 89.49500 209.47000 89.89500 209.87000 ;
     RECT 90.29500 38.27000 90.69500 38.67000 ;
     RECT 90.29500 59.07000 90.69500 59.47000 ;
     RECT 90.29500 63.87000 90.69500 64.27000 ;
     RECT 91.09500 55.87000 91.49500 56.27000 ;
     RECT 91.09500 89.47000 91.49500 89.87000 ;
     RECT 91.09500 97.47000 91.49500 97.87000 ;
     RECT 91.09500 105.47000 91.49500 105.87000 ;
     RECT 91.09500 118.27000 91.49500 118.67000 ;
     RECT 91.09500 150.27000 91.49500 150.67000 ;
     RECT 92.69500 62.27000 93.09500 62.67000 ;
     RECT 92.69500 159.87000 93.09500 160.27000 ;
     RECT 94.29500 137.47000 94.69500 137.87000 ;
     RECT 95.09500 54.27000 95.49500 54.67000 ;
     RECT 97.49500 86.27000 97.89500 86.67000 ;
     RECT 97.49500 94.27000 97.89500 94.67000 ;
     RECT 97.49500 159.87000 97.89500 160.27000 ;
     RECT 97.49500 175.87000 97.89500 176.27000 ;
     RECT 99.09500 62.27000 99.49500 62.67000 ;
     RECT 100.69500 164.67000 101.09500 165.07000 ;
     RECT 101.49500 161.47000 101.89500 161.87000 ;
     RECT 103.89500 54.27000 104.29500 54.67000 ;
     RECT 103.89500 73.47000 104.29500 73.87000 ;
     RECT 103.89500 78.27000 104.29500 78.67000 ;
     RECT 103.89500 163.07000 104.29500 163.47000 ;
     RECT 104.69500 52.67000 105.09500 53.07000 ;
     RECT 107.09500 62.27000 107.49500 62.67000 ;
     RECT 108.69500 161.47000 109.09500 161.87000 ;
     RECT 109.49500 68.67000 109.89500 69.07000 ;
     RECT 111.09500 161.47000 111.49500 161.87000 ;
     RECT 111.89500 54.27000 112.29500 54.67000 ;
     RECT 113.49500 191.87000 113.89500 192.27000 ;
     RECT 114.29500 62.27000 114.69500 62.67000 ;
     RECT 115.09500 86.27000 115.49500 86.67000 ;
     RECT 115.09500 115.07000 115.49500 115.47000 ;
     RECT 115.89500 65.47000 116.29500 65.87000 ;
     RECT 115.89500 94.27000 116.29500 94.67000 ;
     RECT 116.69500 161.47000 117.09500 161.87000 ;
     RECT 119.09500 118.27000 119.49500 118.67000 ;
     RECT 119.09500 129.47000 119.49500 129.87000 ;
     RECT 119.89500 54.27000 120.29500 54.67000 ;
     RECT 119.89500 166.27000 120.29500 166.67000 ;
     RECT 122.29500 17.47000 122.69500 17.87000 ;
     RECT 122.29500 62.27000 122.69500 62.67000 ;
     RECT 122.29500 103.87000 122.69500 104.27000 ;
     RECT 123.09500 161.47000 123.49500 161.87000 ;
     RECT 123.89500 195.07000 124.29500 195.47000 ;
     RECT 124.69500 54.27000 125.09500 54.67000 ;
     RECT 124.69500 62.27000 125.09500 62.67000 ;
     RECT 125.49500 132.67000 125.89500 133.07000 ;
     RECT 127.89500 129.47000 128.29500 129.87000 ;
     RECT 127.89500 147.07000 128.29500 147.47000 ;
     RECT 127.89500 167.87000 128.29500 168.27000 ;
     RECT 128.69500 70.27000 129.09500 70.67000 ;
     RECT 128.69500 123.07000 129.09500 123.47000 ;
     RECT 129.49500 105.47000 129.89500 105.87000 ;
     RECT 129.49500 140.67000 129.89500 141.07000 ;
     RECT 131.09500 57.47000 131.49500 57.87000 ;
     RECT 131.09500 105.47000 131.49500 105.87000 ;
     RECT 131.09500 134.27000 131.49500 134.67000 ;
     RECT 132.69500 4.67000 133.09500 5.07000 ;
     RECT 132.69500 63.87000 133.09500 64.27000 ;
     RECT 132.69500 87.87000 133.09500 88.27000 ;
     RECT 132.69500 89.47000 133.09500 89.87000 ;
     RECT 132.69500 161.47000 133.09500 161.87000 ;
     RECT 133.49500 36.67000 133.89500 37.07000 ;
     RECT 133.49500 47.87000 133.89500 48.27000 ;
     RECT 134.29500 49.47000 134.69500 49.87000 ;
     RECT 135.09500 11.07000 135.49500 11.47000 ;
     RECT 135.09500 38.27000 135.49500 38.67000 ;
     RECT 135.09500 166.27000 135.49500 166.67000 ;
     RECT 135.89500 54.27000 136.29500 54.67000 ;
     RECT 135.89500 142.27000 136.29500 142.67000 ;
     RECT 135.89500 169.47000 136.29500 169.87000 ;
     RECT 135.89500 206.27000 136.29500 206.67000 ;
     RECT 136.69500 57.47000 137.09500 57.87000 ;
     RECT 138.29500 23.87000 138.69500 24.27000 ;
     RECT 138.29500 151.87000 138.69500 152.27000 ;
     RECT 139.09500 73.47000 139.49500 73.87000 ;
     RECT 139.89500 150.27000 140.29500 150.67000 ;
     RECT 140.69500 127.87000 141.09500 128.27000 ;
     RECT 141.49500 159.87000 141.89500 160.27000 ;
     RECT 142.29500 78.27000 142.69500 78.67000 ;
     RECT 142.29500 103.87000 142.69500 104.27000 ;
     RECT 142.29500 153.47000 142.69500 153.87000 ;
     RECT 143.09500 54.27000 143.49500 54.67000 ;
     RECT 143.89500 65.47000 144.29500 65.87000 ;
     RECT 143.89500 103.87000 144.29500 104.27000 ;
     RECT 143.89500 107.07000 144.29500 107.47000 ;
     RECT 143.89500 163.07000 144.29500 163.47000 ;
     RECT 143.89500 164.67000 144.29500 165.07000 ;
     RECT 144.69500 31.87000 145.09500 32.27000 ;
     RECT 144.69500 59.07000 145.09500 59.47000 ;
     RECT 145.49500 63.87000 145.89500 64.27000 ;
     RECT 145.49500 75.07000 145.89500 75.47000 ;
     RECT 145.49500 91.07000 145.89500 91.47000 ;
     RECT 145.49500 123.07000 145.89500 123.47000 ;
     RECT 145.49500 161.47000 145.89500 161.87000 ;
     RECT 146.29500 57.47000 146.69500 57.87000 ;
     RECT 146.29500 129.47000 146.69500 129.87000 ;
     RECT 147.09500 123.07000 147.49500 123.47000 ;
     RECT 147.09500 142.27000 147.49500 142.67000 ;
     RECT 147.89500 115.07000 148.29500 115.47000 ;
     RECT 147.89500 161.47000 148.29500 161.87000 ;
     RECT 147.89500 169.47000 148.29500 169.87000 ;
     RECT 148.69500 47.87000 149.09500 48.27000 ;
     RECT 148.69500 83.07000 149.09500 83.47000 ;
     RECT 149.49500 86.27000 149.89500 86.67000 ;
     RECT 149.49500 150.27000 149.89500 150.67000 ;
     RECT 150.29500 43.07000 150.69500 43.47000 ;
     RECT 150.29500 51.07000 150.69500 51.47000 ;
     RECT 150.29500 78.27000 150.69500 78.67000 ;
     RECT 151.09500 28.67000 151.49500 29.07000 ;
     RECT 151.09500 46.27000 151.49500 46.67000 ;
     RECT 151.09500 89.47000 151.49500 89.87000 ;
     RECT 151.09500 134.27000 151.49500 134.67000 ;
     RECT 151.09500 195.07000 151.49500 195.47000 ;
     RECT 151.89500 111.87000 152.29500 112.27000 ;
     RECT 151.89500 129.47000 152.29500 129.87000 ;
     RECT 152.69500 76.67000 153.09500 77.07000 ;
     RECT 152.69500 126.27000 153.09500 126.67000 ;
     RECT 153.49500 147.07000 153.89500 147.47000 ;
     RECT 154.29500 17.47000 154.69500 17.87000 ;
     RECT 154.29500 102.27000 154.69500 102.67000 ;
     RECT 155.09500 78.27000 155.49500 78.67000 ;
     RECT 155.09500 89.47000 155.49500 89.87000 ;
     RECT 155.09500 94.27000 155.49500 94.67000 ;
     RECT 155.89500 36.67000 156.29500 37.07000 ;
     RECT 156.69500 86.27000 157.09500 86.67000 ;
     RECT 156.69500 92.67000 157.09500 93.07000 ;
     RECT 156.69500 169.47000 157.09500 169.87000 ;
     RECT 157.49500 23.87000 157.89500 24.27000 ;
     RECT 157.49500 31.87000 157.89500 32.27000 ;
     RECT 157.49500 121.47000 157.89500 121.87000 ;
     RECT 158.29500 52.67000 158.69500 53.07000 ;
     RECT 158.29500 97.47000 158.69500 97.87000 ;
     RECT 159.09500 75.07000 159.49500 75.47000 ;
     RECT 159.09500 131.07000 159.49500 131.47000 ;
     RECT 159.09500 143.87000 159.49500 144.27000 ;
     RECT 159.89500 25.47000 160.29500 25.87000 ;
     RECT 159.89500 31.87000 160.29500 32.27000 ;
     RECT 159.89500 35.07000 160.29500 35.47000 ;
     RECT 159.89500 46.27000 160.29500 46.67000 ;
     RECT 159.89500 94.27000 160.29500 94.67000 ;
     RECT 159.89500 105.47000 160.29500 105.87000 ;
     RECT 159.89500 113.47000 160.29500 113.87000 ;
     RECT 159.89500 116.67000 160.29500 117.07000 ;
     RECT 159.89500 124.67000 160.29500 125.07000 ;
     RECT 159.89500 134.27000 160.29500 134.67000 ;
     RECT 161.49500 71.87000 161.89500 72.27000 ;
     RECT 161.49500 83.07000 161.89500 83.47000 ;
     RECT 161.49500 107.07000 161.89500 107.47000 ;
     RECT 161.49500 118.27000 161.89500 118.67000 ;
     RECT 161.49500 124.67000 161.89500 125.07000 ;
     RECT 161.49500 148.67000 161.89500 149.07000 ;
     RECT 161.49500 169.47000 161.89500 169.87000 ;
     RECT 161.49500 180.67000 161.89500 181.07000 ;
     RECT 162.29500 55.87000 162.69500 56.27000 ;
     RECT 162.29500 73.47000 162.69500 73.87000 ;
     RECT 163.09500 38.27000 163.49500 38.67000 ;
     RECT 163.09500 103.87000 163.49500 104.27000 ;
     RECT 163.09500 113.47000 163.49500 113.87000 ;
     RECT 163.89500 46.27000 164.29500 46.67000 ;
     RECT 163.89500 155.07000 164.29500 155.47000 ;
     RECT 164.69500 23.87000 165.09500 24.27000 ;
     RECT 164.69500 33.47000 165.09500 33.87000 ;
     RECT 164.69500 39.87000 165.09500 40.27000 ;
     RECT 164.69500 73.47000 165.09500 73.87000 ;
     RECT 164.69500 81.47000 165.09500 81.87000 ;
     RECT 164.69500 86.27000 165.09500 86.67000 ;
     RECT 164.69500 94.27000 165.09500 94.67000 ;
     RECT 164.69500 103.87000 165.09500 104.27000 ;
     RECT 166.29500 59.07000 166.69500 59.47000 ;
     RECT 166.29500 68.67000 166.69500 69.07000 ;
     RECT 166.29500 87.87000 166.69500 88.27000 ;
     RECT 167.09500 23.87000 167.49500 24.27000 ;
     RECT 167.09500 86.27000 167.49500 86.67000 ;
     RECT 167.89500 73.47000 168.29500 73.87000 ;
     RECT 167.89500 180.67000 168.29500 181.07000 ;
     RECT 168.69500 75.07000 169.09500 75.47000 ;
     RECT 168.69500 163.07000 169.09500 163.47000 ;
     RECT 169.49500 70.27000 169.89500 70.67000 ;
     RECT 169.49500 161.47000 169.89500 161.87000 ;
     RECT 170.29500 28.67000 170.69500 29.07000 ;
     RECT 170.29500 145.47000 170.69500 145.87000 ;
     RECT 171.09500 63.87000 171.49500 64.27000 ;
     RECT 171.09500 67.07000 171.49500 67.47000 ;
     RECT 171.09500 102.27000 171.49500 102.67000 ;
     RECT 171.09500 147.07000 171.49500 147.47000 ;
     RECT 171.09500 156.67000 171.49500 157.07000 ;
     RECT 171.09500 161.47000 171.49500 161.87000 ;
     RECT 171.89500 78.27000 172.29500 78.67000 ;
     RECT 172.69500 139.07000 173.09500 139.47000 ;
     RECT 173.49500 62.27000 173.89500 62.67000 ;
     RECT 173.49500 118.27000 173.89500 118.67000 ;
     RECT 173.49500 151.87000 173.89500 152.27000 ;
     RECT 173.49500 167.87000 173.89500 168.27000 ;
     RECT 174.29500 79.87000 174.69500 80.27000 ;
     RECT 174.29500 103.87000 174.69500 104.27000 ;
     RECT 174.29500 142.27000 174.69500 142.67000 ;
     RECT 174.29500 145.47000 174.69500 145.87000 ;
     RECT 175.09500 11.07000 175.49500 11.47000 ;
     RECT 175.09500 143.87000 175.49500 144.27000 ;
     RECT 175.89500 38.27000 176.29500 38.67000 ;
     RECT 176.69500 169.47000 177.09500 169.87000 ;
     RECT 177.49500 155.07000 177.89500 155.47000 ;
     RECT 179.09500 89.47000 179.49500 89.87000 ;
     RECT 179.89500 83.07000 180.29500 83.47000 ;
     RECT 179.89500 110.27000 180.29500 110.67000 ;
     RECT 180.69500 89.47000 181.09500 89.87000 ;
     RECT 181.49500 41.47000 181.89500 41.87000 ;
     RECT 182.29500 65.47000 182.69500 65.87000 ;
     RECT 183.89500 134.27000 184.29500 134.67000 ;
     RECT 184.69500 31.87000 185.09500 32.27000 ;
     RECT 184.69500 41.47000 185.09500 41.87000 ;
     RECT 184.69500 97.47000 185.09500 97.87000 ;
     RECT 184.69500 99.07000 185.09500 99.47000 ;
     RECT 185.49500 115.07000 185.89500 115.47000 ;
     RECT 186.29500 55.87000 186.69500 56.27000 ;
     RECT 187.89500 46.27000 188.29500 46.67000 ;
     RECT 187.89500 57.47000 188.29500 57.87000 ;
     RECT 187.89500 63.87000 188.29500 64.27000 ;
     RECT 187.89500 150.27000 188.29500 150.67000 ;
     RECT 187.89500 161.47000 188.29500 161.87000 ;
     RECT 188.69500 11.07000 189.09500 11.47000 ;
     RECT 188.69500 23.87000 189.09500 24.27000 ;
     RECT 188.69500 43.07000 189.09500 43.47000 ;
     RECT 188.69500 143.87000 189.09500 144.27000 ;
     RECT 188.69500 147.07000 189.09500 147.47000 ;
     RECT 189.49500 73.47000 189.89500 73.87000 ;
     RECT 190.29500 143.87000 190.69500 144.27000 ;
     RECT 191.09500 12.67000 191.49500 13.07000 ;
     RECT 191.09500 51.07000 191.49500 51.47000 ;
     RECT 191.09500 118.27000 191.49500 118.67000 ;
     RECT 191.89500 108.67000 192.29500 109.07000 ;
     RECT 191.89500 129.47000 192.29500 129.87000 ;
     RECT 191.89500 159.87000 192.29500 160.27000 ;
     RECT 193.49500 139.07000 193.89500 139.47000 ;
     RECT 194.29500 12.67000 194.69500 13.07000 ;
     RECT 194.29500 78.27000 194.69500 78.67000 ;
     RECT 194.29500 91.07000 194.69500 91.47000 ;
     RECT 194.29500 103.87000 194.69500 104.27000 ;
     RECT 194.29500 123.07000 194.69500 123.47000 ;
     RECT 195.09500 47.87000 195.49500 48.27000 ;
     RECT 195.09500 55.87000 195.49500 56.27000 ;
     RECT 195.09500 75.07000 195.49500 75.47000 ;
     RECT 195.09500 185.47000 195.49500 185.87000 ;
     RECT 195.89500 129.47000 196.29500 129.87000 ;
     RECT 195.89500 156.67000 196.29500 157.07000 ;
     RECT 195.89500 169.47000 196.29500 169.87000 ;
     RECT 196.69500 38.27000 197.09500 38.67000 ;
     RECT 199.89500 71.87000 200.29500 72.27000 ;
     RECT 201.49500 52.67000 201.89500 53.07000 ;
     RECT 202.29500 4.67000 202.69500 5.07000 ;
     RECT 202.29500 41.47000 202.69500 41.87000 ;
     RECT 203.09500 46.27000 203.49500 46.67000 ;
     RECT 203.09500 89.47000 203.49500 89.87000 ;
     RECT 203.09500 108.67000 203.49500 109.07000 ;
     RECT 204.69500 196.67000 205.09500 197.07000 ;
     RECT 206.29500 12.67000 206.69500 13.07000 ;
     RECT 206.29500 143.87000 206.69500 144.27000 ;
     RECT 207.09500 78.27000 207.49500 78.67000 ;
     RECT 207.89500 63.87000 208.29500 64.27000 ;
     RECT 207.89500 99.07000 208.29500 99.47000 ;
     RECT 208.69500 206.27000 209.09500 206.67000 ;
    LAYER via9 ;
     RECT 23.69500 54.07000 24.49500 54.87000 ;
     RECT 23.69500 127.67000 24.49500 128.47000 ;
     RECT 23.69500 166.07000 24.49500 166.87000 ;
     RECT 23.69500 193.27000 24.49500 194.07000 ;
     RECT 25.29500 129.27000 26.09500 130.07000 ;
     RECT 25.29500 161.27000 26.09500 162.07000 ;
     RECT 26.89500 62.07000 27.69500 62.87000 ;
     RECT 26.89500 158.07000 27.69500 158.87000 ;
     RECT 30.09500 140.47000 30.89500 141.27000 ;
     RECT 30.09500 161.27000 30.89500 162.07000 ;
     RECT 31.69500 54.07000 32.49500 54.87000 ;
     RECT 31.69500 166.07000 32.49500 166.87000 ;
     RECT 34.89500 161.27000 35.69500 162.07000 ;
     RECT 36.49500 62.07000 37.29500 62.87000 ;
     RECT 38.09500 132.47000 38.89500 133.27000 ;
     RECT 38.09500 161.27000 38.89500 162.07000 ;
     RECT 39.69500 54.07000 40.49500 54.87000 ;
     RECT 39.69500 166.07000 40.49500 166.87000 ;
     RECT 42.89500 62.07000 43.69500 62.87000 ;
     RECT 44.49500 94.07000 45.29500 94.87000 ;
     RECT 44.49500 102.07000 45.29500 102.87000 ;
     RECT 44.49500 161.27000 45.29500 162.07000 ;
     RECT 47.69500 54.07000 48.49500 54.87000 ;
     RECT 47.69500 161.27000 48.49500 162.07000 ;
     RECT 49.29500 71.67000 50.09500 72.47000 ;
     RECT 49.29500 78.07000 50.09500 78.87000 ;
     RECT 49.29500 142.07000 50.09500 142.87000 ;
     RECT 49.29500 159.67000 50.09500 160.47000 ;
     RECT 50.89500 41.27000 51.69500 42.07000 ;
     RECT 50.89500 57.27000 51.69500 58.07000 ;
     RECT 50.89500 161.27000 51.69500 162.07000 ;
     RECT 52.49500 62.07000 53.29500 62.87000 ;
     RECT 52.49500 78.07000 53.29500 78.87000 ;
     RECT 52.49500 100.47000 53.29500 101.27000 ;
     RECT 52.49500 186.87000 53.29500 187.67000 ;
     RECT 52.49500 193.27000 53.29500 194.07000 ;
     RECT 55.69500 25.27000 56.49500 26.07000 ;
     RECT 55.69500 33.27000 56.49500 34.07000 ;
     RECT 55.69500 41.27000 56.49500 42.07000 ;
     RECT 55.69500 46.07000 56.49500 46.87000 ;
     RECT 55.69500 54.07000 56.49500 54.87000 ;
     RECT 55.69500 70.07000 56.49500 70.87000 ;
     RECT 55.69500 81.27000 56.49500 82.07000 ;
     RECT 55.69500 86.07000 56.49500 86.87000 ;
     RECT 55.69500 97.27000 56.49500 98.07000 ;
     RECT 55.69500 102.07000 56.49500 102.87000 ;
     RECT 55.69500 110.07000 56.49500 110.87000 ;
     RECT 55.69500 122.87000 56.49500 123.67000 ;
     RECT 55.69500 161.27000 56.49500 162.07000 ;
     RECT 57.29500 50.87000 58.09500 51.67000 ;
     RECT 57.29500 76.47000 58.09500 77.27000 ;
     RECT 57.29500 84.47000 58.09500 85.27000 ;
     RECT 57.29500 92.47000 58.09500 93.27000 ;
     RECT 57.29500 124.47000 58.09500 125.27000 ;
     RECT 57.29500 143.67000 58.09500 144.47000 ;
     RECT 57.29500 159.67000 58.09500 160.47000 ;
     RECT 58.09500 57.27000 58.89500 58.07000 ;
     RECT 58.89500 25.27000 59.69500 26.07000 ;
     RECT 58.89500 33.27000 59.69500 34.07000 ;
     RECT 58.89500 46.07000 59.69500 46.87000 ;
     RECT 58.89500 65.27000 59.69500 66.07000 ;
     RECT 58.89500 102.07000 59.69500 102.87000 ;
     RECT 58.89500 105.27000 59.69500 106.07000 ;
     RECT 58.89500 118.07000 59.69500 118.87000 ;
     RECT 58.89500 161.27000 59.69500 162.07000 ;
     RECT 60.49500 62.07000 61.29500 62.87000 ;
     RECT 62.09500 73.27000 62.89500 74.07000 ;
     RECT 62.09500 100.47000 62.89500 101.27000 ;
     RECT 62.09500 156.47000 62.89500 157.27000 ;
     RECT 63.69500 54.07000 64.49500 54.87000 ;
     RECT 63.69500 138.87000 64.49500 139.67000 ;
     RECT 63.69500 161.27000 64.49500 162.07000 ;
     RECT 65.29500 62.07000 66.09500 62.87000 ;
     RECT 66.89500 70.07000 67.69500 70.87000 ;
     RECT 66.89500 90.87000 67.69500 91.67000 ;
     RECT 66.89500 161.27000 67.69500 162.07000 ;
     RECT 71.69500 54.07000 72.49500 54.87000 ;
     RECT 74.89500 57.27000 75.69500 58.07000 ;
     RECT 74.89500 161.27000 75.69500 162.07000 ;
     RECT 74.89500 166.07000 75.69500 166.87000 ;
     RECT 78.09500 174.07000 78.89500 174.87000 ;
     RECT 78.09500 210.87000 78.89500 211.67000 ;
     RECT 79.69500 54.07000 80.49500 54.87000 ;
     RECT 81.29500 60.47000 82.09500 61.27000 ;
     RECT 81.29500 90.87000 82.09500 91.67000 ;
     RECT 82.89500 161.27000 83.69500 162.07000 ;
     RECT 82.89500 164.47000 83.69500 165.27000 ;
     RECT 84.49500 63.67000 85.29500 64.47000 ;
     RECT 86.09500 161.27000 86.89500 162.07000 ;
     RECT 86.09500 166.07000 86.89500 166.87000 ;
     RECT 86.09500 185.27000 86.89500 186.07000 ;
     RECT 87.69500 54.07000 88.49500 54.87000 ;
     RECT 89.29500 193.27000 90.09500 194.07000 ;
     RECT 89.29500 209.27000 90.09500 210.07000 ;
     RECT 92.49500 62.07000 93.29500 62.87000 ;
     RECT 92.49500 158.07000 93.29500 158.87000 ;
     RECT 95.69500 54.07000 96.49500 54.87000 ;
     RECT 95.69500 166.07000 96.49500 166.87000 ;
     RECT 97.29500 159.67000 98.09500 160.47000 ;
     RECT 98.89500 62.07000 99.69500 62.87000 ;
     RECT 103.69500 54.07000 104.49500 54.87000 ;
     RECT 103.69500 161.27000 104.49500 162.07000 ;
     RECT 106.89500 62.07000 107.69500 62.87000 ;
     RECT 106.89500 161.27000 107.69500 162.07000 ;
     RECT 111.69500 54.07000 112.49500 54.87000 ;
     RECT 111.69500 63.67000 112.49500 64.47000 ;
     RECT 111.69500 150.07000 112.49500 150.87000 ;
     RECT 111.69500 161.27000 112.49500 162.07000 ;
     RECT 113.29500 159.67000 114.09500 160.47000 ;
     RECT 114.89500 62.07000 115.69500 62.87000 ;
     RECT 114.89500 65.27000 115.69500 66.07000 ;
     RECT 114.89500 86.07000 115.69500 86.87000 ;
     RECT 114.89500 114.87000 115.69500 115.67000 ;
     RECT 114.89500 161.27000 115.69500 162.07000 ;
     RECT 114.89500 166.07000 115.69500 166.87000 ;
     RECT 114.89500 196.47000 115.69500 197.27000 ;
     RECT 119.69500 54.07000 120.49500 54.87000 ;
     RECT 119.69500 166.07000 120.49500 166.87000 ;
     RECT 122.89500 62.07000 123.69500 62.87000 ;
     RECT 122.89500 161.27000 123.69500 162.07000 ;
     RECT 127.69500 54.07000 128.49500 54.87000 ;
     RECT 127.69500 167.67000 128.49500 168.47000 ;
     RECT 129.29500 68.47000 130.09500 69.27000 ;
     RECT 129.29500 87.67000 130.09500 88.47000 ;
     RECT 129.29500 105.27000 130.09500 106.07000 ;
     RECT 129.29500 140.47000 130.09500 141.27000 ;
     RECT 130.89500 57.27000 131.69500 58.07000 ;
     RECT 132.49500 65.27000 133.29500 66.07000 ;
     RECT 132.49500 89.27000 133.29500 90.07000 ;
     RECT 132.49500 161.27000 133.29500 162.07000 ;
     RECT 134.09500 36.47000 134.89500 37.27000 ;
     RECT 134.09500 49.27000 134.89500 50.07000 ;
     RECT 135.69500 54.07000 136.49500 54.87000 ;
     RECT 135.69500 166.07000 136.49500 166.87000 ;
     RECT 138.89500 57.27000 139.69500 58.07000 ;
     RECT 138.89500 161.27000 139.69500 162.07000 ;
     RECT 140.49500 127.67000 141.29500 128.47000 ;
     RECT 140.49500 150.07000 141.29500 150.87000 ;
     RECT 142.09500 58.87000 142.89500 59.67000 ;
     RECT 142.09500 153.27000 142.89500 154.07000 ;
     RECT 142.09500 161.27000 142.89500 162.07000 ;
     RECT 143.69500 54.07000 144.49500 54.87000 ;
     RECT 143.69500 106.87000 144.49500 107.67000 ;
     RECT 143.69500 126.07000 144.49500 126.87000 ;
     RECT 143.69500 166.07000 144.49500 166.87000 ;
     RECT 145.29500 74.87000 146.09500 75.67000 ;
     RECT 146.89500 36.47000 147.69500 37.27000 ;
     RECT 146.89500 54.07000 147.69500 54.87000 ;
     RECT 146.89500 161.27000 147.69500 162.07000 ;
     RECT 148.49500 57.27000 149.29500 58.07000 ;
     RECT 151.69500 46.07000 152.49500 46.87000 ;
     RECT 151.69500 89.27000 152.49500 90.07000 ;
     RECT 153.29500 132.47000 154.09500 133.27000 ;
     RECT 153.29500 145.27000 154.09500 146.07000 ;
     RECT 154.89500 41.27000 155.69500 42.07000 ;
     RECT 154.89500 76.47000 155.69500 77.27000 ;
     RECT 154.89500 79.67000 155.69500 80.47000 ;
     RECT 154.89500 86.07000 155.69500 86.87000 ;
     RECT 156.49500 74.87000 157.29500 75.67000 ;
     RECT 156.49500 92.47000 157.29500 93.27000 ;
     RECT 156.49500 121.27000 157.29500 122.07000 ;
     RECT 156.49500 130.87000 157.29500 131.67000 ;
     RECT 156.49500 169.27000 157.29500 170.07000 ;
     RECT 158.09500 86.07000 158.89500 86.87000 ;
     RECT 158.09500 126.07000 158.89500 126.87000 ;
     RECT 159.69500 25.27000 160.49500 26.07000 ;
     RECT 159.69500 33.27000 160.49500 34.07000 ;
     RECT 159.69500 46.07000 160.49500 46.87000 ;
     RECT 159.69500 71.67000 160.49500 72.47000 ;
     RECT 159.69500 94.07000 160.49500 94.87000 ;
     RECT 159.69500 97.27000 160.49500 98.07000 ;
     RECT 159.69500 105.27000 160.49500 106.07000 ;
     RECT 159.69500 113.27000 160.49500 114.07000 ;
     RECT 161.29500 126.07000 162.09500 126.87000 ;
     RECT 161.29500 148.47000 162.09500 149.27000 ;
     RECT 162.89500 46.07000 163.69500 46.87000 ;
     RECT 162.89500 113.27000 163.69500 114.07000 ;
     RECT 162.89500 116.47000 163.69500 117.27000 ;
     RECT 164.49500 26.87000 165.29500 27.67000 ;
     RECT 164.49500 33.27000 165.29500 34.07000 ;
     RECT 164.49500 38.07000 165.29500 38.87000 ;
     RECT 164.49500 73.27000 165.29500 74.07000 ;
     RECT 164.49500 81.27000 165.29500 82.07000 ;
     RECT 164.49500 86.07000 165.29500 86.87000 ;
     RECT 164.49500 94.07000 165.29500 94.87000 ;
     RECT 164.49500 106.87000 165.29500 107.67000 ;
     RECT 166.09500 68.47000 166.89500 69.27000 ;
     RECT 166.09500 87.67000 166.89500 88.47000 ;
     RECT 169.29500 66.87000 170.09500 67.67000 ;
     RECT 169.29500 84.47000 170.09500 85.27000 ;
     RECT 169.29500 97.27000 170.09500 98.07000 ;
     RECT 169.29500 161.27000 170.09500 162.07000 ;
     RECT 169.29500 185.27000 170.09500 186.07000 ;
     RECT 174.09500 145.27000 174.89500 146.07000 ;
     RECT 174.09500 167.67000 174.89500 168.47000 ;
     RECT 188.49500 10.87000 189.29500 11.67000 ;
     RECT 188.49500 57.27000 189.29500 58.07000 ;
     RECT 191.69500 118.07000 192.49500 118.87000 ;
     RECT 191.69500 159.67000 192.49500 160.47000 ;
     RECT 194.89500 12.47000 195.69500 13.27000 ;
     RECT 194.89500 47.67000 195.69500 48.47000 ;
     RECT 194.89500 129.27000 195.69500 130.07000 ;
     RECT 194.89500 169.27000 195.69500 170.07000 ;
     RECT 194.89500 191.67000 195.69500 192.47000 ;
     RECT 199.69500 57.27000 200.49500 58.07000 ;
     RECT 199.69500 71.67000 200.49500 72.47000 ;
     RECT 206.09500 12.47000 206.89500 13.27000 ;
     RECT 206.09500 78.07000 206.89500 78.87000 ;
  END
END block_v2_g
END LIBRARY
